VERSION 5.8 ;
BUSBITCHARS "[]" ;
DIVIDERCHAR "/" ;
UNITS
    DATABASE MICRONS 1000 ;
END UNITS

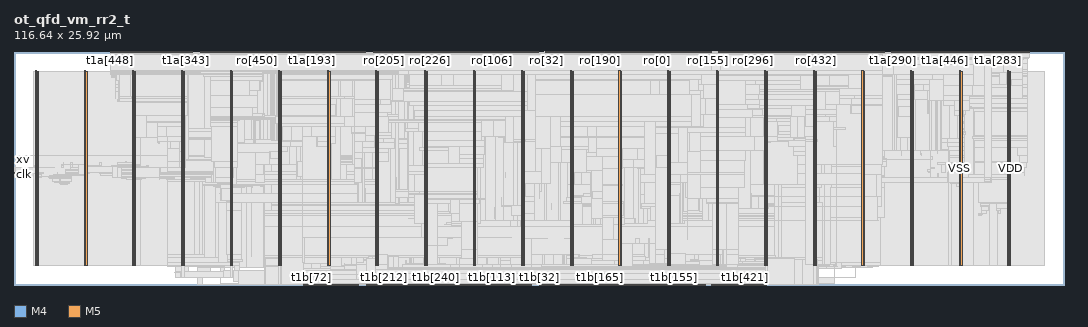
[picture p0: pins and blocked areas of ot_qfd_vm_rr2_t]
MACRO ot_qfd_vm_rr2_t
  FOREIGN ot_qfd_vm_rr2_t 0 0 ;
  CLASS BLOCK ;
  SIZE 116.64 BY 25.92 ;
  PIN clk
    DIRECTION INPUT ;
    USE SIGNAL ;
    PORT
      LAYER M4 ;
        RECT  0 12.24 0.084 12.264 ;
    END
  END clk
  PIN me_in
    DIRECTION INPUT ;
    USE SIGNAL ;
    PORT
      LAYER M4 ;
        RECT  0 12.336 0.084 12.36 ;
    END
  END me_in
  PIN ovf
    DIRECTION OUTPUT ;
    USE SIGNAL ;
    PORT
      LAYER M5 ;
        RECT  67.536 0 67.56 0.084 ;
    END
  END ovf
  PIN pop
    DIRECTION INPUT ;
    USE SIGNAL ;
    PORT
      LAYER M4 ;
        RECT  0 12.432 0.084 12.456 ;
    END
  END pop
  PIN ro[0]
    DIRECTION OUTPUT ;
    USE SIGNAL ;
    PORT
      LAYER M5 ;
        RECT  71.376 25.836 71.4 25.92 ;
    END
  END ro[0]
  PIN ro[100]
    DIRECTION OUTPUT ;
    USE SIGNAL ;
    PORT
      LAYER M5 ;
        RECT  52.56 25.836 52.584 25.92 ;
    END
  END ro[100]
  PIN ro[101]
    DIRECTION OUTPUT ;
    USE SIGNAL ;
    PORT
      LAYER M5 ;
        RECT  52.656 25.836 52.68 25.92 ;
    END
  END ro[101]
  PIN ro[102]
    DIRECTION OUTPUT ;
    USE SIGNAL ;
    PORT
      LAYER M5 ;
        RECT  52.752 25.836 52.776 25.92 ;
    END
  END ro[102]
  PIN ro[103]
    DIRECTION OUTPUT ;
    USE SIGNAL ;
    PORT
      LAYER M5 ;
        RECT  52.848 25.836 52.872 25.92 ;
    END
  END ro[103]
  PIN ro[104]
    DIRECTION OUTPUT ;
    USE SIGNAL ;
    PORT
      LAYER M5 ;
        RECT  52.944 25.836 52.968 25.92 ;
    END
  END ro[104]
  PIN ro[105]
    DIRECTION OUTPUT ;
    USE SIGNAL ;
    PORT
      LAYER M5 ;
        RECT  53.04 25.836 53.064 25.92 ;
    END
  END ro[105]
  PIN ro[106]
    DIRECTION OUTPUT ;
    USE SIGNAL ;
    PORT
      LAYER M5 ;
        RECT  53.136 25.836 53.16 25.92 ;
    END
  END ro[106]
  PIN ro[107]
    DIRECTION OUTPUT ;
    USE SIGNAL ;
    PORT
      LAYER M5 ;
        RECT  53.232 25.836 53.256 25.92 ;
    END
  END ro[107]
  PIN ro[108]
    DIRECTION OUTPUT ;
    USE SIGNAL ;
    PORT
      LAYER M5 ;
        RECT  53.328 25.836 53.352 25.92 ;
    END
  END ro[108]
  PIN ro[109]
    DIRECTION OUTPUT ;
    USE SIGNAL ;
    PORT
      LAYER M5 ;
        RECT  53.424 25.836 53.448 25.92 ;
    END
  END ro[109]
  PIN ro[10]
    DIRECTION OUTPUT ;
    USE SIGNAL ;
    PORT
      LAYER M5 ;
        RECT  72.336 25.836 72.36 25.92 ;
    END
  END ro[10]
  PIN ro[110]
    DIRECTION OUTPUT ;
    USE SIGNAL ;
    PORT
      LAYER M5 ;
        RECT  53.52 25.836 53.544 25.92 ;
    END
  END ro[110]
  PIN ro[111]
    DIRECTION OUTPUT ;
    USE SIGNAL ;
    PORT
      LAYER M5 ;
        RECT  53.616 25.836 53.64 25.92 ;
    END
  END ro[111]
  PIN ro[112]
    DIRECTION OUTPUT ;
    USE SIGNAL ;
    PORT
      LAYER M5 ;
        RECT  53.712 25.836 53.736 25.92 ;
    END
  END ro[112]
  PIN ro[113]
    DIRECTION OUTPUT ;
    USE SIGNAL ;
    PORT
      LAYER M5 ;
        RECT  53.808 25.836 53.832 25.92 ;
    END
  END ro[113]
  PIN ro[114]
    DIRECTION OUTPUT ;
    USE SIGNAL ;
    PORT
      LAYER M5 ;
        RECT  53.904 25.836 53.928 25.92 ;
    END
  END ro[114]
  PIN ro[115]
    DIRECTION OUTPUT ;
    USE SIGNAL ;
    PORT
      LAYER M5 ;
        RECT  54 25.836 54.024 25.92 ;
    END
  END ro[115]
  PIN ro[116]
    DIRECTION OUTPUT ;
    USE SIGNAL ;
    PORT
      LAYER M5 ;
        RECT  54.096 25.836 54.12 25.92 ;
    END
  END ro[116]
  PIN ro[117]
    DIRECTION OUTPUT ;
    USE SIGNAL ;
    PORT
      LAYER M5 ;
        RECT  54.192 25.836 54.216 25.92 ;
    END
  END ro[117]
  PIN ro[118]
    DIRECTION OUTPUT ;
    USE SIGNAL ;
    PORT
      LAYER M5 ;
        RECT  54.288 25.836 54.312 25.92 ;
    END
  END ro[118]
  PIN ro[119]
    DIRECTION OUTPUT ;
    USE SIGNAL ;
    PORT
      LAYER M5 ;
        RECT  54.384 25.836 54.408 25.92 ;
    END
  END ro[119]
  PIN ro[11]
    DIRECTION OUTPUT ;
    USE SIGNAL ;
    PORT
      LAYER M5 ;
        RECT  72.432 25.836 72.456 25.92 ;
    END
  END ro[11]
  PIN ro[120]
    DIRECTION OUTPUT ;
    USE SIGNAL ;
    PORT
      LAYER M5 ;
        RECT  54.48 25.836 54.504 25.92 ;
    END
  END ro[120]
  PIN ro[121]
    DIRECTION OUTPUT ;
    USE SIGNAL ;
    PORT
      LAYER M5 ;
        RECT  54.576 25.836 54.6 25.92 ;
    END
  END ro[121]
  PIN ro[122]
    DIRECTION OUTPUT ;
    USE SIGNAL ;
    PORT
      LAYER M5 ;
        RECT  54.672 25.836 54.696 25.92 ;
    END
  END ro[122]
  PIN ro[123]
    DIRECTION OUTPUT ;
    USE SIGNAL ;
    PORT
      LAYER M5 ;
        RECT  54.768 25.836 54.792 25.92 ;
    END
  END ro[123]
  PIN ro[124]
    DIRECTION OUTPUT ;
    USE SIGNAL ;
    PORT
      LAYER M5 ;
        RECT  54.864 25.836 54.888 25.92 ;
    END
  END ro[124]
  PIN ro[125]
    DIRECTION OUTPUT ;
    USE SIGNAL ;
    PORT
      LAYER M5 ;
        RECT  54.96 25.836 54.984 25.92 ;
    END
  END ro[125]
  PIN ro[126]
    DIRECTION OUTPUT ;
    USE SIGNAL ;
    PORT
      LAYER M5 ;
        RECT  55.056 25.836 55.08 25.92 ;
    END
  END ro[126]
  PIN ro[127]
    DIRECTION OUTPUT ;
    USE SIGNAL ;
    PORT
      LAYER M5 ;
        RECT  55.152 25.836 55.176 25.92 ;
    END
  END ro[127]
  PIN ro[128]
    DIRECTION OUTPUT ;
    USE SIGNAL ;
    PORT
      LAYER M5 ;
        RECT  74.448 25.836 74.472 25.92 ;
    END
  END ro[128]
  PIN ro[129]
    DIRECTION OUTPUT ;
    USE SIGNAL ;
    PORT
      LAYER M5 ;
        RECT  74.544 25.836 74.568 25.92 ;
    END
  END ro[129]
  PIN ro[12]
    DIRECTION OUTPUT ;
    USE SIGNAL ;
    PORT
      LAYER M5 ;
        RECT  72.528 25.836 72.552 25.92 ;
    END
  END ro[12]
  PIN ro[130]
    DIRECTION OUTPUT ;
    USE SIGNAL ;
    PORT
      LAYER M5 ;
        RECT  74.64 25.836 74.664 25.92 ;
    END
  END ro[130]
  PIN ro[131]
    DIRECTION OUTPUT ;
    USE SIGNAL ;
    PORT
      LAYER M5 ;
        RECT  74.736 25.836 74.76 25.92 ;
    END
  END ro[131]
  PIN ro[132]
    DIRECTION OUTPUT ;
    USE SIGNAL ;
    PORT
      LAYER M5 ;
        RECT  74.832 25.836 74.856 25.92 ;
    END
  END ro[132]
  PIN ro[133]
    DIRECTION OUTPUT ;
    USE SIGNAL ;
    PORT
      LAYER M5 ;
        RECT  74.928 25.836 74.952 25.92 ;
    END
  END ro[133]
  PIN ro[134]
    DIRECTION OUTPUT ;
    USE SIGNAL ;
    PORT
      LAYER M5 ;
        RECT  75.024 25.836 75.048 25.92 ;
    END
  END ro[134]
  PIN ro[135]
    DIRECTION OUTPUT ;
    USE SIGNAL ;
    PORT
      LAYER M5 ;
        RECT  75.12 25.836 75.144 25.92 ;
    END
  END ro[135]
  PIN ro[136]
    DIRECTION OUTPUT ;
    USE SIGNAL ;
    PORT
      LAYER M5 ;
        RECT  75.216 25.836 75.24 25.92 ;
    END
  END ro[136]
  PIN ro[137]
    DIRECTION OUTPUT ;
    USE SIGNAL ;
    PORT
      LAYER M5 ;
        RECT  75.312 25.836 75.336 25.92 ;
    END
  END ro[137]
  PIN ro[138]
    DIRECTION OUTPUT ;
    USE SIGNAL ;
    PORT
      LAYER M5 ;
        RECT  75.408 25.836 75.432 25.92 ;
    END
  END ro[138]
  PIN ro[139]
    DIRECTION OUTPUT ;
    USE SIGNAL ;
    PORT
      LAYER M5 ;
        RECT  75.504 25.836 75.528 25.92 ;
    END
  END ro[139]
  PIN ro[13]
    DIRECTION OUTPUT ;
    USE SIGNAL ;
    PORT
      LAYER M5 ;
        RECT  72.624 25.836 72.648 25.92 ;
    END
  END ro[13]
  PIN ro[140]
    DIRECTION OUTPUT ;
    USE SIGNAL ;
    PORT
      LAYER M5 ;
        RECT  75.6 25.836 75.624 25.92 ;
    END
  END ro[140]
  PIN ro[141]
    DIRECTION OUTPUT ;
    USE SIGNAL ;
    PORT
      LAYER M5 ;
        RECT  75.696 25.836 75.72 25.92 ;
    END
  END ro[141]
  PIN ro[142]
    DIRECTION OUTPUT ;
    USE SIGNAL ;
    PORT
      LAYER M5 ;
        RECT  75.792 25.836 75.816 25.92 ;
    END
  END ro[142]
  PIN ro[143]
    DIRECTION OUTPUT ;
    USE SIGNAL ;
    PORT
      LAYER M5 ;
        RECT  75.888 25.836 75.912 25.92 ;
    END
  END ro[143]
  PIN ro[144]
    DIRECTION OUTPUT ;
    USE SIGNAL ;
    PORT
      LAYER M5 ;
        RECT  75.984 25.836 76.008 25.92 ;
    END
  END ro[144]
  PIN ro[145]
    DIRECTION OUTPUT ;
    USE SIGNAL ;
    PORT
      LAYER M5 ;
        RECT  76.08 25.836 76.104 25.92 ;
    END
  END ro[145]
  PIN ro[146]
    DIRECTION OUTPUT ;
    USE SIGNAL ;
    PORT
      LAYER M5 ;
        RECT  76.176 25.836 76.2 25.92 ;
    END
  END ro[146]
  PIN ro[147]
    DIRECTION OUTPUT ;
    USE SIGNAL ;
    PORT
      LAYER M5 ;
        RECT  76.272 25.836 76.296 25.92 ;
    END
  END ro[147]
  PIN ro[148]
    DIRECTION OUTPUT ;
    USE SIGNAL ;
    PORT
      LAYER M5 ;
        RECT  76.368 25.836 76.392 25.92 ;
    END
  END ro[148]
  PIN ro[149]
    DIRECTION OUTPUT ;
    USE SIGNAL ;
    PORT
      LAYER M5 ;
        RECT  76.464 25.836 76.488 25.92 ;
    END
  END ro[149]
  PIN ro[14]
    DIRECTION OUTPUT ;
    USE SIGNAL ;
    PORT
      LAYER M5 ;
        RECT  72.72 25.836 72.744 25.92 ;
    END
  END ro[14]
  PIN ro[150]
    DIRECTION OUTPUT ;
    USE SIGNAL ;
    PORT
      LAYER M5 ;
        RECT  76.56 25.836 76.584 25.92 ;
    END
  END ro[150]
  PIN ro[151]
    DIRECTION OUTPUT ;
    USE SIGNAL ;
    PORT
      LAYER M5 ;
        RECT  76.656 25.836 76.68 25.92 ;
    END
  END ro[151]
  PIN ro[152]
    DIRECTION OUTPUT ;
    USE SIGNAL ;
    PORT
      LAYER M5 ;
        RECT  76.752 25.836 76.776 25.92 ;
    END
  END ro[152]
  PIN ro[153]
    DIRECTION OUTPUT ;
    USE SIGNAL ;
    PORT
      LAYER M5 ;
        RECT  76.848 25.836 76.872 25.92 ;
    END
  END ro[153]
  PIN ro[154]
    DIRECTION OUTPUT ;
    USE SIGNAL ;
    PORT
      LAYER M5 ;
        RECT  76.944 25.836 76.968 25.92 ;
    END
  END ro[154]
  PIN ro[155]
    DIRECTION OUTPUT ;
    USE SIGNAL ;
    PORT
      LAYER M5 ;
        RECT  77.04 25.836 77.064 25.92 ;
    END
  END ro[155]
  PIN ro[156]
    DIRECTION OUTPUT ;
    USE SIGNAL ;
    PORT
      LAYER M5 ;
        RECT  77.136 25.836 77.16 25.92 ;
    END
  END ro[156]
  PIN ro[157]
    DIRECTION OUTPUT ;
    USE SIGNAL ;
    PORT
      LAYER M5 ;
        RECT  77.232 25.836 77.256 25.92 ;
    END
  END ro[157]
  PIN ro[158]
    DIRECTION OUTPUT ;
    USE SIGNAL ;
    PORT
      LAYER M5 ;
        RECT  77.328 25.836 77.352 25.92 ;
    END
  END ro[158]
  PIN ro[159]
    DIRECTION OUTPUT ;
    USE SIGNAL ;
    PORT
      LAYER M5 ;
        RECT  77.424 25.836 77.448 25.92 ;
    END
  END ro[159]
  PIN ro[15]
    DIRECTION OUTPUT ;
    USE SIGNAL ;
    PORT
      LAYER M5 ;
        RECT  72.816 25.836 72.84 25.92 ;
    END
  END ro[15]
  PIN ro[160]
    DIRECTION OUTPUT ;
    USE SIGNAL ;
    PORT
      LAYER M5 ;
        RECT  62.16 25.836 62.184 25.92 ;
    END
  END ro[160]
  PIN ro[161]
    DIRECTION OUTPUT ;
    USE SIGNAL ;
    PORT
      LAYER M5 ;
        RECT  62.256 25.836 62.28 25.92 ;
    END
  END ro[161]
  PIN ro[162]
    DIRECTION OUTPUT ;
    USE SIGNAL ;
    PORT
      LAYER M5 ;
        RECT  62.352 25.836 62.376 25.92 ;
    END
  END ro[162]
  PIN ro[163]
    DIRECTION OUTPUT ;
    USE SIGNAL ;
    PORT
      LAYER M5 ;
        RECT  62.448 25.836 62.472 25.92 ;
    END
  END ro[163]
  PIN ro[164]
    DIRECTION OUTPUT ;
    USE SIGNAL ;
    PORT
      LAYER M5 ;
        RECT  62.544 25.836 62.568 25.92 ;
    END
  END ro[164]
  PIN ro[165]
    DIRECTION OUTPUT ;
    USE SIGNAL ;
    PORT
      LAYER M5 ;
        RECT  62.64 25.836 62.664 25.92 ;
    END
  END ro[165]
  PIN ro[166]
    DIRECTION OUTPUT ;
    USE SIGNAL ;
    PORT
      LAYER M5 ;
        RECT  62.736 25.836 62.76 25.92 ;
    END
  END ro[166]
  PIN ro[167]
    DIRECTION OUTPUT ;
    USE SIGNAL ;
    PORT
      LAYER M5 ;
        RECT  62.832 25.836 62.856 25.92 ;
    END
  END ro[167]
  PIN ro[168]
    DIRECTION OUTPUT ;
    USE SIGNAL ;
    PORT
      LAYER M5 ;
        RECT  62.928 25.836 62.952 25.92 ;
    END
  END ro[168]
  PIN ro[169]
    DIRECTION OUTPUT ;
    USE SIGNAL ;
    PORT
      LAYER M5 ;
        RECT  63.024 25.836 63.048 25.92 ;
    END
  END ro[169]
  PIN ro[16]
    DIRECTION OUTPUT ;
    USE SIGNAL ;
    PORT
      LAYER M5 ;
        RECT  72.912 25.836 72.936 25.92 ;
    END
  END ro[16]
  PIN ro[170]
    DIRECTION OUTPUT ;
    USE SIGNAL ;
    PORT
      LAYER M5 ;
        RECT  63.12 25.836 63.144 25.92 ;
    END
  END ro[170]
  PIN ro[171]
    DIRECTION OUTPUT ;
    USE SIGNAL ;
    PORT
      LAYER M5 ;
        RECT  63.216 25.836 63.24 25.92 ;
    END
  END ro[171]
  PIN ro[172]
    DIRECTION OUTPUT ;
    USE SIGNAL ;
    PORT
      LAYER M5 ;
        RECT  63.312 25.836 63.336 25.92 ;
    END
  END ro[172]
  PIN ro[173]
    DIRECTION OUTPUT ;
    USE SIGNAL ;
    PORT
      LAYER M5 ;
        RECT  63.408 25.836 63.432 25.92 ;
    END
  END ro[173]
  PIN ro[174]
    DIRECTION OUTPUT ;
    USE SIGNAL ;
    PORT
      LAYER M5 ;
        RECT  63.504 25.836 63.528 25.92 ;
    END
  END ro[174]
  PIN ro[175]
    DIRECTION OUTPUT ;
    USE SIGNAL ;
    PORT
      LAYER M5 ;
        RECT  63.6 25.836 63.624 25.92 ;
    END
  END ro[175]
  PIN ro[176]
    DIRECTION OUTPUT ;
    USE SIGNAL ;
    PORT
      LAYER M5 ;
        RECT  63.696 25.836 63.72 25.92 ;
    END
  END ro[176]
  PIN ro[177]
    DIRECTION OUTPUT ;
    USE SIGNAL ;
    PORT
      LAYER M5 ;
        RECT  63.792 25.836 63.816 25.92 ;
    END
  END ro[177]
  PIN ro[178]
    DIRECTION OUTPUT ;
    USE SIGNAL ;
    PORT
      LAYER M5 ;
        RECT  63.888 25.836 63.912 25.92 ;
    END
  END ro[178]
  PIN ro[179]
    DIRECTION OUTPUT ;
    USE SIGNAL ;
    PORT
      LAYER M5 ;
        RECT  63.984 25.836 64.008 25.92 ;
    END
  END ro[179]
  PIN ro[17]
    DIRECTION OUTPUT ;
    USE SIGNAL ;
    PORT
      LAYER M5 ;
        RECT  73.008 25.836 73.032 25.92 ;
    END
  END ro[17]
  PIN ro[180]
    DIRECTION OUTPUT ;
    USE SIGNAL ;
    PORT
      LAYER M5 ;
        RECT  64.08 25.836 64.104 25.92 ;
    END
  END ro[180]
  PIN ro[181]
    DIRECTION OUTPUT ;
    USE SIGNAL ;
    PORT
      LAYER M5 ;
        RECT  64.176 25.836 64.2 25.92 ;
    END
  END ro[181]
  PIN ro[182]
    DIRECTION OUTPUT ;
    USE SIGNAL ;
    PORT
      LAYER M5 ;
        RECT  64.272 25.836 64.296 25.92 ;
    END
  END ro[182]
  PIN ro[183]
    DIRECTION OUTPUT ;
    USE SIGNAL ;
    PORT
      LAYER M5 ;
        RECT  64.368 25.836 64.392 25.92 ;
    END
  END ro[183]
  PIN ro[184]
    DIRECTION OUTPUT ;
    USE SIGNAL ;
    PORT
      LAYER M5 ;
        RECT  64.464 25.836 64.488 25.92 ;
    END
  END ro[184]
  PIN ro[185]
    DIRECTION OUTPUT ;
    USE SIGNAL ;
    PORT
      LAYER M5 ;
        RECT  64.56 25.836 64.584 25.92 ;
    END
  END ro[185]
  PIN ro[186]
    DIRECTION OUTPUT ;
    USE SIGNAL ;
    PORT
      LAYER M5 ;
        RECT  64.656 25.836 64.68 25.92 ;
    END
  END ro[186]
  PIN ro[187]
    DIRECTION OUTPUT ;
    USE SIGNAL ;
    PORT
      LAYER M5 ;
        RECT  64.752 25.836 64.776 25.92 ;
    END
  END ro[187]
  PIN ro[188]
    DIRECTION OUTPUT ;
    USE SIGNAL ;
    PORT
      LAYER M5 ;
        RECT  64.848 25.836 64.872 25.92 ;
    END
  END ro[188]
  PIN ro[189]
    DIRECTION OUTPUT ;
    USE SIGNAL ;
    PORT
      LAYER M5 ;
        RECT  64.944 25.836 64.968 25.92 ;
    END
  END ro[189]
  PIN ro[18]
    DIRECTION OUTPUT ;
    USE SIGNAL ;
    PORT
      LAYER M5 ;
        RECT  73.104 25.836 73.128 25.92 ;
    END
  END ro[18]
  PIN ro[190]
    DIRECTION OUTPUT ;
    USE SIGNAL ;
    PORT
      LAYER M5 ;
        RECT  65.04 25.836 65.064 25.92 ;
    END
  END ro[190]
  PIN ro[191]
    DIRECTION OUTPUT ;
    USE SIGNAL ;
    PORT
      LAYER M5 ;
        RECT  65.136 25.836 65.16 25.92 ;
    END
  END ro[191]
  PIN ro[192]
    DIRECTION OUTPUT ;
    USE SIGNAL ;
    PORT
      LAYER M5 ;
        RECT  39.888 25.836 39.912 25.92 ;
    END
  END ro[192]
  PIN ro[193]
    DIRECTION OUTPUT ;
    USE SIGNAL ;
    PORT
      LAYER M5 ;
        RECT  39.984 25.836 40.008 25.92 ;
    END
  END ro[193]
  PIN ro[194]
    DIRECTION OUTPUT ;
    USE SIGNAL ;
    PORT
      LAYER M5 ;
        RECT  40.08 25.836 40.104 25.92 ;
    END
  END ro[194]
  PIN ro[195]
    DIRECTION OUTPUT ;
    USE SIGNAL ;
    PORT
      LAYER M5 ;
        RECT  40.176 25.836 40.2 25.92 ;
    END
  END ro[195]
  PIN ro[196]
    DIRECTION OUTPUT ;
    USE SIGNAL ;
    PORT
      LAYER M5 ;
        RECT  40.272 25.836 40.296 25.92 ;
    END
  END ro[196]
  PIN ro[197]
    DIRECTION OUTPUT ;
    USE SIGNAL ;
    PORT
      LAYER M5 ;
        RECT  40.368 25.836 40.392 25.92 ;
    END
  END ro[197]
  PIN ro[198]
    DIRECTION OUTPUT ;
    USE SIGNAL ;
    PORT
      LAYER M5 ;
        RECT  40.464 25.836 40.488 25.92 ;
    END
  END ro[198]
  PIN ro[199]
    DIRECTION OUTPUT ;
    USE SIGNAL ;
    PORT
      LAYER M5 ;
        RECT  40.56 25.836 40.584 25.92 ;
    END
  END ro[199]
  PIN ro[19]
    DIRECTION OUTPUT ;
    USE SIGNAL ;
    PORT
      LAYER M5 ;
        RECT  73.2 25.836 73.224 25.92 ;
    END
  END ro[19]
  PIN ro[1]
    DIRECTION OUTPUT ;
    USE SIGNAL ;
    PORT
      LAYER M5 ;
        RECT  71.472 25.836 71.496 25.92 ;
    END
  END ro[1]
  PIN ro[200]
    DIRECTION OUTPUT ;
    USE SIGNAL ;
    PORT
      LAYER M5 ;
        RECT  40.656 25.836 40.68 25.92 ;
    END
  END ro[200]
  PIN ro[201]
    DIRECTION OUTPUT ;
    USE SIGNAL ;
    PORT
      LAYER M5 ;
        RECT  40.752 25.836 40.776 25.92 ;
    END
  END ro[201]
  PIN ro[202]
    DIRECTION OUTPUT ;
    USE SIGNAL ;
    PORT
      LAYER M5 ;
        RECT  40.848 25.836 40.872 25.92 ;
    END
  END ro[202]
  PIN ro[203]
    DIRECTION OUTPUT ;
    USE SIGNAL ;
    PORT
      LAYER M5 ;
        RECT  40.944 25.836 40.968 25.92 ;
    END
  END ro[203]
  PIN ro[204]
    DIRECTION OUTPUT ;
    USE SIGNAL ;
    PORT
      LAYER M5 ;
        RECT  41.04 25.836 41.064 25.92 ;
    END
  END ro[204]
  PIN ro[205]
    DIRECTION OUTPUT ;
    USE SIGNAL ;
    PORT
      LAYER M5 ;
        RECT  41.136 25.836 41.16 25.92 ;
    END
  END ro[205]
  PIN ro[206]
    DIRECTION OUTPUT ;
    USE SIGNAL ;
    PORT
      LAYER M5 ;
        RECT  41.232 25.836 41.256 25.92 ;
    END
  END ro[206]
  PIN ro[207]
    DIRECTION OUTPUT ;
    USE SIGNAL ;
    PORT
      LAYER M5 ;
        RECT  41.328 25.836 41.352 25.92 ;
    END
  END ro[207]
  PIN ro[208]
    DIRECTION OUTPUT ;
    USE SIGNAL ;
    PORT
      LAYER M5 ;
        RECT  41.424 25.836 41.448 25.92 ;
    END
  END ro[208]
  PIN ro[209]
    DIRECTION OUTPUT ;
    USE SIGNAL ;
    PORT
      LAYER M5 ;
        RECT  41.52 25.836 41.544 25.92 ;
    END
  END ro[209]
  PIN ro[20]
    DIRECTION OUTPUT ;
    USE SIGNAL ;
    PORT
      LAYER M5 ;
        RECT  73.296 25.836 73.32 25.92 ;
    END
  END ro[20]
  PIN ro[210]
    DIRECTION OUTPUT ;
    USE SIGNAL ;
    PORT
      LAYER M5 ;
        RECT  41.616 25.836 41.64 25.92 ;
    END
  END ro[210]
  PIN ro[211]
    DIRECTION OUTPUT ;
    USE SIGNAL ;
    PORT
      LAYER M5 ;
        RECT  41.712 25.836 41.736 25.92 ;
    END
  END ro[211]
  PIN ro[212]
    DIRECTION OUTPUT ;
    USE SIGNAL ;
    PORT
      LAYER M5 ;
        RECT  41.808 25.836 41.832 25.92 ;
    END
  END ro[212]
  PIN ro[213]
    DIRECTION OUTPUT ;
    USE SIGNAL ;
    PORT
      LAYER M5 ;
        RECT  41.904 25.836 41.928 25.92 ;
    END
  END ro[213]
  PIN ro[214]
    DIRECTION OUTPUT ;
    USE SIGNAL ;
    PORT
      LAYER M5 ;
        RECT  42 25.836 42.024 25.92 ;
    END
  END ro[214]
  PIN ro[215]
    DIRECTION OUTPUT ;
    USE SIGNAL ;
    PORT
      LAYER M5 ;
        RECT  42.096 25.836 42.12 25.92 ;
    END
  END ro[215]
  PIN ro[216]
    DIRECTION OUTPUT ;
    USE SIGNAL ;
    PORT
      LAYER M5 ;
        RECT  42.192 25.836 42.216 25.92 ;
    END
  END ro[216]
  PIN ro[217]
    DIRECTION OUTPUT ;
    USE SIGNAL ;
    PORT
      LAYER M5 ;
        RECT  42.288 25.836 42.312 25.92 ;
    END
  END ro[217]
  PIN ro[218]
    DIRECTION OUTPUT ;
    USE SIGNAL ;
    PORT
      LAYER M5 ;
        RECT  42.384 25.836 42.408 25.92 ;
    END
  END ro[218]
  PIN ro[219]
    DIRECTION OUTPUT ;
    USE SIGNAL ;
    PORT
      LAYER M5 ;
        RECT  42.48 25.836 42.504 25.92 ;
    END
  END ro[219]
  PIN ro[21]
    DIRECTION OUTPUT ;
    USE SIGNAL ;
    PORT
      LAYER M5 ;
        RECT  73.392 25.836 73.416 25.92 ;
    END
  END ro[21]
  PIN ro[220]
    DIRECTION OUTPUT ;
    USE SIGNAL ;
    PORT
      LAYER M5 ;
        RECT  42.576 25.836 42.6 25.92 ;
    END
  END ro[220]
  PIN ro[221]
    DIRECTION OUTPUT ;
    USE SIGNAL ;
    PORT
      LAYER M5 ;
        RECT  42.672 25.836 42.696 25.92 ;
    END
  END ro[221]
  PIN ro[222]
    DIRECTION OUTPUT ;
    USE SIGNAL ;
    PORT
      LAYER M5 ;
        RECT  42.768 25.836 42.792 25.92 ;
    END
  END ro[222]
  PIN ro[223]
    DIRECTION OUTPUT ;
    USE SIGNAL ;
    PORT
      LAYER M5 ;
        RECT  42.864 25.836 42.888 25.92 ;
    END
  END ro[223]
  PIN ro[224]
    DIRECTION OUTPUT ;
    USE SIGNAL ;
    PORT
      LAYER M5 ;
        RECT  46.032 25.836 46.056 25.92 ;
    END
  END ro[224]
  PIN ro[225]
    DIRECTION OUTPUT ;
    USE SIGNAL ;
    PORT
      LAYER M5 ;
        RECT  46.128 25.836 46.152 25.92 ;
    END
  END ro[225]
  PIN ro[226]
    DIRECTION OUTPUT ;
    USE SIGNAL ;
    PORT
      LAYER M5 ;
        RECT  46.224 25.836 46.248 25.92 ;
    END
  END ro[226]
  PIN ro[227]
    DIRECTION OUTPUT ;
    USE SIGNAL ;
    PORT
      LAYER M5 ;
        RECT  46.32 25.836 46.344 25.92 ;
    END
  END ro[227]
  PIN ro[228]
    DIRECTION OUTPUT ;
    USE SIGNAL ;
    PORT
      LAYER M5 ;
        RECT  46.416 25.836 46.44 25.92 ;
    END
  END ro[228]
  PIN ro[229]
    DIRECTION OUTPUT ;
    USE SIGNAL ;
    PORT
      LAYER M5 ;
        RECT  46.512 25.836 46.536 25.92 ;
    END
  END ro[229]
  PIN ro[22]
    DIRECTION OUTPUT ;
    USE SIGNAL ;
    PORT
      LAYER M5 ;
        RECT  73.488 25.836 73.512 25.92 ;
    END
  END ro[22]
  PIN ro[230]
    DIRECTION OUTPUT ;
    USE SIGNAL ;
    PORT
      LAYER M5 ;
        RECT  46.608 25.836 46.632 25.92 ;
    END
  END ro[230]
  PIN ro[231]
    DIRECTION OUTPUT ;
    USE SIGNAL ;
    PORT
      LAYER M5 ;
        RECT  46.704 25.836 46.728 25.92 ;
    END
  END ro[231]
  PIN ro[232]
    DIRECTION OUTPUT ;
    USE SIGNAL ;
    PORT
      LAYER M5 ;
        RECT  46.8 25.836 46.824 25.92 ;
    END
  END ro[232]
  PIN ro[233]
    DIRECTION OUTPUT ;
    USE SIGNAL ;
    PORT
      LAYER M5 ;
        RECT  46.896 25.836 46.92 25.92 ;
    END
  END ro[233]
  PIN ro[234]
    DIRECTION OUTPUT ;
    USE SIGNAL ;
    PORT
      LAYER M5 ;
        RECT  46.992 25.836 47.016 25.92 ;
    END
  END ro[234]
  PIN ro[235]
    DIRECTION OUTPUT ;
    USE SIGNAL ;
    PORT
      LAYER M5 ;
        RECT  47.088 25.836 47.112 25.92 ;
    END
  END ro[235]
  PIN ro[236]
    DIRECTION OUTPUT ;
    USE SIGNAL ;
    PORT
      LAYER M5 ;
        RECT  47.184 25.836 47.208 25.92 ;
    END
  END ro[236]
  PIN ro[237]
    DIRECTION OUTPUT ;
    USE SIGNAL ;
    PORT
      LAYER M5 ;
        RECT  47.28 25.836 47.304 25.92 ;
    END
  END ro[237]
  PIN ro[238]
    DIRECTION OUTPUT ;
    USE SIGNAL ;
    PORT
      LAYER M5 ;
        RECT  47.376 25.836 47.4 25.92 ;
    END
  END ro[238]
  PIN ro[239]
    DIRECTION OUTPUT ;
    USE SIGNAL ;
    PORT
      LAYER M5 ;
        RECT  47.472 25.836 47.496 25.92 ;
    END
  END ro[239]
  PIN ro[23]
    DIRECTION OUTPUT ;
    USE SIGNAL ;
    PORT
      LAYER M5 ;
        RECT  73.584 25.836 73.608 25.92 ;
    END
  END ro[23]
  PIN ro[240]
    DIRECTION OUTPUT ;
    USE SIGNAL ;
    PORT
      LAYER M5 ;
        RECT  47.568 25.836 47.592 25.92 ;
    END
  END ro[240]
  PIN ro[241]
    DIRECTION OUTPUT ;
    USE SIGNAL ;
    PORT
      LAYER M5 ;
        RECT  47.664 25.836 47.688 25.92 ;
    END
  END ro[241]
  PIN ro[242]
    DIRECTION OUTPUT ;
    USE SIGNAL ;
    PORT
      LAYER M5 ;
        RECT  47.76 25.836 47.784 25.92 ;
    END
  END ro[242]
  PIN ro[243]
    DIRECTION OUTPUT ;
    USE SIGNAL ;
    PORT
      LAYER M5 ;
        RECT  47.856 25.836 47.88 25.92 ;
    END
  END ro[243]
  PIN ro[244]
    DIRECTION OUTPUT ;
    USE SIGNAL ;
    PORT
      LAYER M5 ;
        RECT  47.952 25.836 47.976 25.92 ;
    END
  END ro[244]
  PIN ro[245]
    DIRECTION OUTPUT ;
    USE SIGNAL ;
    PORT
      LAYER M5 ;
        RECT  48.048 25.836 48.072 25.92 ;
    END
  END ro[245]
  PIN ro[246]
    DIRECTION OUTPUT ;
    USE SIGNAL ;
    PORT
      LAYER M5 ;
        RECT  48.144 25.836 48.168 25.92 ;
    END
  END ro[246]
  PIN ro[247]
    DIRECTION OUTPUT ;
    USE SIGNAL ;
    PORT
      LAYER M5 ;
        RECT  48.24 25.836 48.264 25.92 ;
    END
  END ro[247]
  PIN ro[248]
    DIRECTION OUTPUT ;
    USE SIGNAL ;
    PORT
      LAYER M5 ;
        RECT  48.336 25.836 48.36 25.92 ;
    END
  END ro[248]
  PIN ro[249]
    DIRECTION OUTPUT ;
    USE SIGNAL ;
    PORT
      LAYER M5 ;
        RECT  48.432 25.836 48.456 25.92 ;
    END
  END ro[249]
  PIN ro[24]
    DIRECTION OUTPUT ;
    USE SIGNAL ;
    PORT
      LAYER M5 ;
        RECT  73.68 25.836 73.704 25.92 ;
    END
  END ro[24]
  PIN ro[250]
    DIRECTION OUTPUT ;
    USE SIGNAL ;
    PORT
      LAYER M5 ;
        RECT  48.528 25.836 48.552 25.92 ;
    END
  END ro[250]
  PIN ro[251]
    DIRECTION OUTPUT ;
    USE SIGNAL ;
    PORT
      LAYER M5 ;
        RECT  48.624 25.836 48.648 25.92 ;
    END
  END ro[251]
  PIN ro[252]
    DIRECTION OUTPUT ;
    USE SIGNAL ;
    PORT
      LAYER M5 ;
        RECT  48.72 25.836 48.744 25.92 ;
    END
  END ro[252]
  PIN ro[253]
    DIRECTION OUTPUT ;
    USE SIGNAL ;
    PORT
      LAYER M5 ;
        RECT  48.816 25.836 48.84 25.92 ;
    END
  END ro[253]
  PIN ro[254]
    DIRECTION OUTPUT ;
    USE SIGNAL ;
    PORT
      LAYER M5 ;
        RECT  48.912 25.836 48.936 25.92 ;
    END
  END ro[254]
  PIN ro[255]
    DIRECTION OUTPUT ;
    USE SIGNAL ;
    PORT
      LAYER M5 ;
        RECT  49.008 25.836 49.032 25.92 ;
    END
  END ro[255]
  PIN ro[256]
    DIRECTION OUTPUT ;
    USE SIGNAL ;
    PORT
      LAYER M5 ;
        RECT  65.232 25.836 65.256 25.92 ;
    END
  END ro[256]
  PIN ro[257]
    DIRECTION OUTPUT ;
    USE SIGNAL ;
    PORT
      LAYER M5 ;
        RECT  65.328 25.836 65.352 25.92 ;
    END
  END ro[257]
  PIN ro[258]
    DIRECTION OUTPUT ;
    USE SIGNAL ;
    PORT
      LAYER M5 ;
        RECT  65.424 25.836 65.448 25.92 ;
    END
  END ro[258]
  PIN ro[259]
    DIRECTION OUTPUT ;
    USE SIGNAL ;
    PORT
      LAYER M5 ;
        RECT  65.52 25.836 65.544 25.92 ;
    END
  END ro[259]
  PIN ro[25]
    DIRECTION OUTPUT ;
    USE SIGNAL ;
    PORT
      LAYER M5 ;
        RECT  73.776 25.836 73.8 25.92 ;
    END
  END ro[25]
  PIN ro[260]
    DIRECTION OUTPUT ;
    USE SIGNAL ;
    PORT
      LAYER M5 ;
        RECT  65.616 25.836 65.64 25.92 ;
    END
  END ro[260]
  PIN ro[261]
    DIRECTION OUTPUT ;
    USE SIGNAL ;
    PORT
      LAYER M5 ;
        RECT  65.712 25.836 65.736 25.92 ;
    END
  END ro[261]
  PIN ro[262]
    DIRECTION OUTPUT ;
    USE SIGNAL ;
    PORT
      LAYER M5 ;
        RECT  65.808 25.836 65.832 25.92 ;
    END
  END ro[262]
  PIN ro[263]
    DIRECTION OUTPUT ;
    USE SIGNAL ;
    PORT
      LAYER M5 ;
        RECT  65.904 25.836 65.928 25.92 ;
    END
  END ro[263]
  PIN ro[264]
    DIRECTION OUTPUT ;
    USE SIGNAL ;
    PORT
      LAYER M5 ;
        RECT  66 25.836 66.024 25.92 ;
    END
  END ro[264]
  PIN ro[265]
    DIRECTION OUTPUT ;
    USE SIGNAL ;
    PORT
      LAYER M5 ;
        RECT  66.096 25.836 66.12 25.92 ;
    END
  END ro[265]
  PIN ro[266]
    DIRECTION OUTPUT ;
    USE SIGNAL ;
    PORT
      LAYER M5 ;
        RECT  66.192 25.836 66.216 25.92 ;
    END
  END ro[266]
  PIN ro[267]
    DIRECTION OUTPUT ;
    USE SIGNAL ;
    PORT
      LAYER M5 ;
        RECT  66.288 25.836 66.312 25.92 ;
    END
  END ro[267]
  PIN ro[268]
    DIRECTION OUTPUT ;
    USE SIGNAL ;
    PORT
      LAYER M5 ;
        RECT  66.384 25.836 66.408 25.92 ;
    END
  END ro[268]
  PIN ro[269]
    DIRECTION OUTPUT ;
    USE SIGNAL ;
    PORT
      LAYER M5 ;
        RECT  66.48 25.836 66.504 25.92 ;
    END
  END ro[269]
  PIN ro[26]
    DIRECTION OUTPUT ;
    USE SIGNAL ;
    PORT
      LAYER M5 ;
        RECT  73.872 25.836 73.896 25.92 ;
    END
  END ro[26]
  PIN ro[270]
    DIRECTION OUTPUT ;
    USE SIGNAL ;
    PORT
      LAYER M5 ;
        RECT  66.576 25.836 66.6 25.92 ;
    END
  END ro[270]
  PIN ro[271]
    DIRECTION OUTPUT ;
    USE SIGNAL ;
    PORT
      LAYER M5 ;
        RECT  66.672 25.836 66.696 25.92 ;
    END
  END ro[271]
  PIN ro[272]
    DIRECTION OUTPUT ;
    USE SIGNAL ;
    PORT
      LAYER M5 ;
        RECT  66.768 25.836 66.792 25.92 ;
    END
  END ro[272]
  PIN ro[273]
    DIRECTION OUTPUT ;
    USE SIGNAL ;
    PORT
      LAYER M5 ;
        RECT  66.864 25.836 66.888 25.92 ;
    END
  END ro[273]
  PIN ro[274]
    DIRECTION OUTPUT ;
    USE SIGNAL ;
    PORT
      LAYER M5 ;
        RECT  66.96 25.836 66.984 25.92 ;
    END
  END ro[274]
  PIN ro[275]
    DIRECTION OUTPUT ;
    USE SIGNAL ;
    PORT
      LAYER M5 ;
        RECT  67.056 25.836 67.08 25.92 ;
    END
  END ro[275]
  PIN ro[276]
    DIRECTION OUTPUT ;
    USE SIGNAL ;
    PORT
      LAYER M5 ;
        RECT  67.152 25.836 67.176 25.92 ;
    END
  END ro[276]
  PIN ro[277]
    DIRECTION OUTPUT ;
    USE SIGNAL ;
    PORT
      LAYER M5 ;
        RECT  67.248 25.836 67.272 25.92 ;
    END
  END ro[277]
  PIN ro[278]
    DIRECTION OUTPUT ;
    USE SIGNAL ;
    PORT
      LAYER M5 ;
        RECT  67.344 25.836 67.368 25.92 ;
    END
  END ro[278]
  PIN ro[279]
    DIRECTION OUTPUT ;
    USE SIGNAL ;
    PORT
      LAYER M5 ;
        RECT  67.44 25.836 67.464 25.92 ;
    END
  END ro[279]
  PIN ro[27]
    DIRECTION OUTPUT ;
    USE SIGNAL ;
    PORT
      LAYER M5 ;
        RECT  73.968 25.836 73.992 25.92 ;
    END
  END ro[27]
  PIN ro[280]
    DIRECTION OUTPUT ;
    USE SIGNAL ;
    PORT
      LAYER M5 ;
        RECT  67.536 25.836 67.56 25.92 ;
    END
  END ro[280]
  PIN ro[281]
    DIRECTION OUTPUT ;
    USE SIGNAL ;
    PORT
      LAYER M5 ;
        RECT  67.632 25.836 67.656 25.92 ;
    END
  END ro[281]
  PIN ro[282]
    DIRECTION OUTPUT ;
    USE SIGNAL ;
    PORT
      LAYER M5 ;
        RECT  67.728 25.836 67.752 25.92 ;
    END
  END ro[282]
  PIN ro[283]
    DIRECTION OUTPUT ;
    USE SIGNAL ;
    PORT
      LAYER M5 ;
        RECT  67.824 25.836 67.848 25.92 ;
    END
  END ro[283]
  PIN ro[284]
    DIRECTION OUTPUT ;
    USE SIGNAL ;
    PORT
      LAYER M5 ;
        RECT  67.92 25.836 67.944 25.92 ;
    END
  END ro[284]
  PIN ro[285]
    DIRECTION OUTPUT ;
    USE SIGNAL ;
    PORT
      LAYER M5 ;
        RECT  68.016 25.836 68.04 25.92 ;
    END
  END ro[285]
  PIN ro[286]
    DIRECTION OUTPUT ;
    USE SIGNAL ;
    PORT
      LAYER M5 ;
        RECT  68.112 25.836 68.136 25.92 ;
    END
  END ro[286]
  PIN ro[287]
    DIRECTION OUTPUT ;
    USE SIGNAL ;
    PORT
      LAYER M5 ;
        RECT  68.208 25.836 68.232 25.92 ;
    END
  END ro[287]
  PIN ro[288]
    DIRECTION OUTPUT ;
    USE SIGNAL ;
    PORT
      LAYER M5 ;
        RECT  81.36 25.836 81.384 25.92 ;
    END
  END ro[288]
  PIN ro[289]
    DIRECTION OUTPUT ;
    USE SIGNAL ;
    PORT
      LAYER M5 ;
        RECT  81.456 25.836 81.48 25.92 ;
    END
  END ro[289]
  PIN ro[28]
    DIRECTION OUTPUT ;
    USE SIGNAL ;
    PORT
      LAYER M5 ;
        RECT  74.064 25.836 74.088 25.92 ;
    END
  END ro[28]
  PIN ro[290]
    DIRECTION OUTPUT ;
    USE SIGNAL ;
    PORT
      LAYER M5 ;
        RECT  81.552 25.836 81.576 25.92 ;
    END
  END ro[290]
  PIN ro[291]
    DIRECTION OUTPUT ;
    USE SIGNAL ;
    PORT
      LAYER M5 ;
        RECT  81.648 25.836 81.672 25.92 ;
    END
  END ro[291]
  PIN ro[292]
    DIRECTION OUTPUT ;
    USE SIGNAL ;
    PORT
      LAYER M5 ;
        RECT  81.744 25.836 81.768 25.92 ;
    END
  END ro[292]
  PIN ro[293]
    DIRECTION OUTPUT ;
    USE SIGNAL ;
    PORT
      LAYER M5 ;
        RECT  81.84 25.836 81.864 25.92 ;
    END
  END ro[293]
  PIN ro[294]
    DIRECTION OUTPUT ;
    USE SIGNAL ;
    PORT
      LAYER M5 ;
        RECT  81.936 25.836 81.96 25.92 ;
    END
  END ro[294]
  PIN ro[295]
    DIRECTION OUTPUT ;
    USE SIGNAL ;
    PORT
      LAYER M5 ;
        RECT  82.032 25.836 82.056 25.92 ;
    END
  END ro[295]
  PIN ro[296]
    DIRECTION OUTPUT ;
    USE SIGNAL ;
    PORT
      LAYER M5 ;
        RECT  82.128 25.836 82.152 25.92 ;
    END
  END ro[296]
  PIN ro[297]
    DIRECTION OUTPUT ;
    USE SIGNAL ;
    PORT
      LAYER M5 ;
        RECT  82.224 25.836 82.248 25.92 ;
    END
  END ro[297]
  PIN ro[298]
    DIRECTION OUTPUT ;
    USE SIGNAL ;
    PORT
      LAYER M5 ;
        RECT  82.32 25.836 82.344 25.92 ;
    END
  END ro[298]
  PIN ro[299]
    DIRECTION OUTPUT ;
    USE SIGNAL ;
    PORT
      LAYER M5 ;
        RECT  82.416 25.836 82.44 25.92 ;
    END
  END ro[299]
  PIN ro[29]
    DIRECTION OUTPUT ;
    USE SIGNAL ;
    PORT
      LAYER M5 ;
        RECT  74.16 25.836 74.184 25.92 ;
    END
  END ro[29]
  PIN ro[2]
    DIRECTION OUTPUT ;
    USE SIGNAL ;
    PORT
      LAYER M5 ;
        RECT  71.568 25.836 71.592 25.92 ;
    END
  END ro[2]
  PIN ro[300]
    DIRECTION OUTPUT ;
    USE SIGNAL ;
    PORT
      LAYER M5 ;
        RECT  82.512 25.836 82.536 25.92 ;
    END
  END ro[300]
  PIN ro[301]
    DIRECTION OUTPUT ;
    USE SIGNAL ;
    PORT
      LAYER M5 ;
        RECT  82.608 25.836 82.632 25.92 ;
    END
  END ro[301]
  PIN ro[302]
    DIRECTION OUTPUT ;
    USE SIGNAL ;
    PORT
      LAYER M5 ;
        RECT  82.704 25.836 82.728 25.92 ;
    END
  END ro[302]
  PIN ro[303]
    DIRECTION OUTPUT ;
    USE SIGNAL ;
    PORT
      LAYER M5 ;
        RECT  82.8 25.836 82.824 25.92 ;
    END
  END ro[303]
  PIN ro[304]
    DIRECTION OUTPUT ;
    USE SIGNAL ;
    PORT
      LAYER M5 ;
        RECT  82.896 25.836 82.92 25.92 ;
    END
  END ro[304]
  PIN ro[305]
    DIRECTION OUTPUT ;
    USE SIGNAL ;
    PORT
      LAYER M5 ;
        RECT  82.992 25.836 83.016 25.92 ;
    END
  END ro[305]
  PIN ro[306]
    DIRECTION OUTPUT ;
    USE SIGNAL ;
    PORT
      LAYER M5 ;
        RECT  83.088 25.836 83.112 25.92 ;
    END
  END ro[306]
  PIN ro[307]
    DIRECTION OUTPUT ;
    USE SIGNAL ;
    PORT
      LAYER M5 ;
        RECT  83.184 25.836 83.208 25.92 ;
    END
  END ro[307]
  PIN ro[308]
    DIRECTION OUTPUT ;
    USE SIGNAL ;
    PORT
      LAYER M5 ;
        RECT  83.28 25.836 83.304 25.92 ;
    END
  END ro[308]
  PIN ro[309]
    DIRECTION OUTPUT ;
    USE SIGNAL ;
    PORT
      LAYER M5 ;
        RECT  83.376 25.836 83.4 25.92 ;
    END
  END ro[309]
  PIN ro[30]
    DIRECTION OUTPUT ;
    USE SIGNAL ;
    PORT
      LAYER M5 ;
        RECT  74.256 25.836 74.28 25.92 ;
    END
  END ro[30]
  PIN ro[310]
    DIRECTION OUTPUT ;
    USE SIGNAL ;
    PORT
      LAYER M5 ;
        RECT  83.472 25.836 83.496 25.92 ;
    END
  END ro[310]
  PIN ro[311]
    DIRECTION OUTPUT ;
    USE SIGNAL ;
    PORT
      LAYER M5 ;
        RECT  83.568 25.836 83.592 25.92 ;
    END
  END ro[311]
  PIN ro[312]
    DIRECTION OUTPUT ;
    USE SIGNAL ;
    PORT
      LAYER M5 ;
        RECT  83.664 25.836 83.688 25.92 ;
    END
  END ro[312]
  PIN ro[313]
    DIRECTION OUTPUT ;
    USE SIGNAL ;
    PORT
      LAYER M5 ;
        RECT  83.76 25.836 83.784 25.92 ;
    END
  END ro[313]
  PIN ro[314]
    DIRECTION OUTPUT ;
    USE SIGNAL ;
    PORT
      LAYER M5 ;
        RECT  83.856 25.836 83.88 25.92 ;
    END
  END ro[314]
  PIN ro[315]
    DIRECTION OUTPUT ;
    USE SIGNAL ;
    PORT
      LAYER M5 ;
        RECT  83.952 25.836 83.976 25.92 ;
    END
  END ro[315]
  PIN ro[316]
    DIRECTION OUTPUT ;
    USE SIGNAL ;
    PORT
      LAYER M5 ;
        RECT  84.048 25.836 84.072 25.92 ;
    END
  END ro[316]
  PIN ro[317]
    DIRECTION OUTPUT ;
    USE SIGNAL ;
    PORT
      LAYER M5 ;
        RECT  84.144 25.836 84.168 25.92 ;
    END
  END ro[317]
  PIN ro[318]
    DIRECTION OUTPUT ;
    USE SIGNAL ;
    PORT
      LAYER M5 ;
        RECT  84.24 25.836 84.264 25.92 ;
    END
  END ro[318]
  PIN ro[319]
    DIRECTION OUTPUT ;
    USE SIGNAL ;
    PORT
      LAYER M5 ;
        RECT  84.336 25.836 84.36 25.92 ;
    END
  END ro[319]
  PIN ro[31]
    DIRECTION OUTPUT ;
    USE SIGNAL ;
    PORT
      LAYER M5 ;
        RECT  74.352 25.836 74.376 25.92 ;
    END
  END ro[31]
  PIN ro[320]
    DIRECTION OUTPUT ;
    USE SIGNAL ;
    PORT
      LAYER M5 ;
        RECT  42.96 25.836 42.984 25.92 ;
    END
  END ro[320]
  PIN ro[321]
    DIRECTION OUTPUT ;
    USE SIGNAL ;
    PORT
      LAYER M5 ;
        RECT  43.056 25.836 43.08 25.92 ;
    END
  END ro[321]
  PIN ro[322]
    DIRECTION OUTPUT ;
    USE SIGNAL ;
    PORT
      LAYER M5 ;
        RECT  43.152 25.836 43.176 25.92 ;
    END
  END ro[322]
  PIN ro[323]
    DIRECTION OUTPUT ;
    USE SIGNAL ;
    PORT
      LAYER M5 ;
        RECT  43.248 25.836 43.272 25.92 ;
    END
  END ro[323]
  PIN ro[324]
    DIRECTION OUTPUT ;
    USE SIGNAL ;
    PORT
      LAYER M5 ;
        RECT  43.344 25.836 43.368 25.92 ;
    END
  END ro[324]
  PIN ro[325]
    DIRECTION OUTPUT ;
    USE SIGNAL ;
    PORT
      LAYER M5 ;
        RECT  43.44 25.836 43.464 25.92 ;
    END
  END ro[325]
  PIN ro[326]
    DIRECTION OUTPUT ;
    USE SIGNAL ;
    PORT
      LAYER M5 ;
        RECT  43.536 25.836 43.56 25.92 ;
    END
  END ro[326]
  PIN ro[327]
    DIRECTION OUTPUT ;
    USE SIGNAL ;
    PORT
      LAYER M5 ;
        RECT  43.632 25.836 43.656 25.92 ;
    END
  END ro[327]
  PIN ro[328]
    DIRECTION OUTPUT ;
    USE SIGNAL ;
    PORT
      LAYER M5 ;
        RECT  43.728 25.836 43.752 25.92 ;
    END
  END ro[328]
  PIN ro[329]
    DIRECTION OUTPUT ;
    USE SIGNAL ;
    PORT
      LAYER M5 ;
        RECT  43.824 25.836 43.848 25.92 ;
    END
  END ro[329]
  PIN ro[32]
    DIRECTION OUTPUT ;
    USE SIGNAL ;
    PORT
      LAYER M5 ;
        RECT  59.088 25.836 59.112 25.92 ;
    END
  END ro[32]
  PIN ro[330]
    DIRECTION OUTPUT ;
    USE SIGNAL ;
    PORT
      LAYER M5 ;
        RECT  43.92 25.836 43.944 25.92 ;
    END
  END ro[330]
  PIN ro[331]
    DIRECTION OUTPUT ;
    USE SIGNAL ;
    PORT
      LAYER M5 ;
        RECT  44.016 25.836 44.04 25.92 ;
    END
  END ro[331]
  PIN ro[332]
    DIRECTION OUTPUT ;
    USE SIGNAL ;
    PORT
      LAYER M5 ;
        RECT  44.112 25.836 44.136 25.92 ;
    END
  END ro[332]
  PIN ro[333]
    DIRECTION OUTPUT ;
    USE SIGNAL ;
    PORT
      LAYER M5 ;
        RECT  44.208 25.836 44.232 25.92 ;
    END
  END ro[333]
  PIN ro[334]
    DIRECTION OUTPUT ;
    USE SIGNAL ;
    PORT
      LAYER M5 ;
        RECT  44.304 25.836 44.328 25.92 ;
    END
  END ro[334]
  PIN ro[335]
    DIRECTION OUTPUT ;
    USE SIGNAL ;
    PORT
      LAYER M5 ;
        RECT  44.4 25.836 44.424 25.92 ;
    END
  END ro[335]
  PIN ro[336]
    DIRECTION OUTPUT ;
    USE SIGNAL ;
    PORT
      LAYER M5 ;
        RECT  44.496 25.836 44.52 25.92 ;
    END
  END ro[336]
  PIN ro[337]
    DIRECTION OUTPUT ;
    USE SIGNAL ;
    PORT
      LAYER M5 ;
        RECT  44.592 25.836 44.616 25.92 ;
    END
  END ro[337]
  PIN ro[338]
    DIRECTION OUTPUT ;
    USE SIGNAL ;
    PORT
      LAYER M5 ;
        RECT  44.688 25.836 44.712 25.92 ;
    END
  END ro[338]
  PIN ro[339]
    DIRECTION OUTPUT ;
    USE SIGNAL ;
    PORT
      LAYER M5 ;
        RECT  44.784 25.836 44.808 25.92 ;
    END
  END ro[339]
  PIN ro[33]
    DIRECTION OUTPUT ;
    USE SIGNAL ;
    PORT
      LAYER M5 ;
        RECT  59.184 25.836 59.208 25.92 ;
    END
  END ro[33]
  PIN ro[340]
    DIRECTION OUTPUT ;
    USE SIGNAL ;
    PORT
      LAYER M5 ;
        RECT  44.88 25.836 44.904 25.92 ;
    END
  END ro[340]
  PIN ro[341]
    DIRECTION OUTPUT ;
    USE SIGNAL ;
    PORT
      LAYER M5 ;
        RECT  44.976 25.836 45 25.92 ;
    END
  END ro[341]
  PIN ro[342]
    DIRECTION OUTPUT ;
    USE SIGNAL ;
    PORT
      LAYER M5 ;
        RECT  45.072 25.836 45.096 25.92 ;
    END
  END ro[342]
  PIN ro[343]
    DIRECTION OUTPUT ;
    USE SIGNAL ;
    PORT
      LAYER M5 ;
        RECT  45.168 25.836 45.192 25.92 ;
    END
  END ro[343]
  PIN ro[344]
    DIRECTION OUTPUT ;
    USE SIGNAL ;
    PORT
      LAYER M5 ;
        RECT  45.264 25.836 45.288 25.92 ;
    END
  END ro[344]
  PIN ro[345]
    DIRECTION OUTPUT ;
    USE SIGNAL ;
    PORT
      LAYER M5 ;
        RECT  45.36 25.836 45.384 25.92 ;
    END
  END ro[345]
  PIN ro[346]
    DIRECTION OUTPUT ;
    USE SIGNAL ;
    PORT
      LAYER M5 ;
        RECT  45.456 25.836 45.48 25.92 ;
    END
  END ro[346]
  PIN ro[347]
    DIRECTION OUTPUT ;
    USE SIGNAL ;
    PORT
      LAYER M5 ;
        RECT  45.552 25.836 45.576 25.92 ;
    END
  END ro[347]
  PIN ro[348]
    DIRECTION OUTPUT ;
    USE SIGNAL ;
    PORT
      LAYER M5 ;
        RECT  45.648 25.836 45.672 25.92 ;
    END
  END ro[348]
  PIN ro[349]
    DIRECTION OUTPUT ;
    USE SIGNAL ;
    PORT
      LAYER M5 ;
        RECT  45.744 25.836 45.768 25.92 ;
    END
  END ro[349]
  PIN ro[34]
    DIRECTION OUTPUT ;
    USE SIGNAL ;
    PORT
      LAYER M5 ;
        RECT  59.28 25.836 59.304 25.92 ;
    END
  END ro[34]
  PIN ro[350]
    DIRECTION OUTPUT ;
    USE SIGNAL ;
    PORT
      LAYER M5 ;
        RECT  45.84 25.836 45.864 25.92 ;
    END
  END ro[350]
  PIN ro[351]
    DIRECTION OUTPUT ;
    USE SIGNAL ;
    PORT
      LAYER M5 ;
        RECT  45.936 25.836 45.96 25.92 ;
    END
  END ro[351]
  PIN ro[352]
    DIRECTION OUTPUT ;
    USE SIGNAL ;
    PORT
      LAYER M5 ;
        RECT  49.104 25.836 49.128 25.92 ;
    END
  END ro[352]
  PIN ro[353]
    DIRECTION OUTPUT ;
    USE SIGNAL ;
    PORT
      LAYER M5 ;
        RECT  49.2 25.836 49.224 25.92 ;
    END
  END ro[353]
  PIN ro[354]
    DIRECTION OUTPUT ;
    USE SIGNAL ;
    PORT
      LAYER M5 ;
        RECT  49.296 25.836 49.32 25.92 ;
    END
  END ro[354]
  PIN ro[355]
    DIRECTION OUTPUT ;
    USE SIGNAL ;
    PORT
      LAYER M5 ;
        RECT  49.392 25.836 49.416 25.92 ;
    END
  END ro[355]
  PIN ro[356]
    DIRECTION OUTPUT ;
    USE SIGNAL ;
    PORT
      LAYER M5 ;
        RECT  49.488 25.836 49.512 25.92 ;
    END
  END ro[356]
  PIN ro[357]
    DIRECTION OUTPUT ;
    USE SIGNAL ;
    PORT
      LAYER M5 ;
        RECT  49.584 25.836 49.608 25.92 ;
    END
  END ro[357]
  PIN ro[358]
    DIRECTION OUTPUT ;
    USE SIGNAL ;
    PORT
      LAYER M5 ;
        RECT  49.68 25.836 49.704 25.92 ;
    END
  END ro[358]
  PIN ro[359]
    DIRECTION OUTPUT ;
    USE SIGNAL ;
    PORT
      LAYER M5 ;
        RECT  49.776 25.836 49.8 25.92 ;
    END
  END ro[359]
  PIN ro[35]
    DIRECTION OUTPUT ;
    USE SIGNAL ;
    PORT
      LAYER M5 ;
        RECT  59.376 25.836 59.4 25.92 ;
    END
  END ro[35]
  PIN ro[360]
    DIRECTION OUTPUT ;
    USE SIGNAL ;
    PORT
      LAYER M5 ;
        RECT  49.872 25.836 49.896 25.92 ;
    END
  END ro[360]
  PIN ro[361]
    DIRECTION OUTPUT ;
    USE SIGNAL ;
    PORT
      LAYER M5 ;
        RECT  49.968 25.836 49.992 25.92 ;
    END
  END ro[361]
  PIN ro[362]
    DIRECTION OUTPUT ;
    USE SIGNAL ;
    PORT
      LAYER M5 ;
        RECT  50.064 25.836 50.088 25.92 ;
    END
  END ro[362]
  PIN ro[363]
    DIRECTION OUTPUT ;
    USE SIGNAL ;
    PORT
      LAYER M5 ;
        RECT  50.16 25.836 50.184 25.92 ;
    END
  END ro[363]
  PIN ro[364]
    DIRECTION OUTPUT ;
    USE SIGNAL ;
    PORT
      LAYER M5 ;
        RECT  50.256 25.836 50.28 25.92 ;
    END
  END ro[364]
  PIN ro[365]
    DIRECTION OUTPUT ;
    USE SIGNAL ;
    PORT
      LAYER M5 ;
        RECT  50.352 25.836 50.376 25.92 ;
    END
  END ro[365]
  PIN ro[366]
    DIRECTION OUTPUT ;
    USE SIGNAL ;
    PORT
      LAYER M5 ;
        RECT  50.448 25.836 50.472 25.92 ;
    END
  END ro[366]
  PIN ro[367]
    DIRECTION OUTPUT ;
    USE SIGNAL ;
    PORT
      LAYER M5 ;
        RECT  50.544 25.836 50.568 25.92 ;
    END
  END ro[367]
  PIN ro[368]
    DIRECTION OUTPUT ;
    USE SIGNAL ;
    PORT
      LAYER M5 ;
        RECT  50.64 25.836 50.664 25.92 ;
    END
  END ro[368]
  PIN ro[369]
    DIRECTION OUTPUT ;
    USE SIGNAL ;
    PORT
      LAYER M5 ;
        RECT  50.736 25.836 50.76 25.92 ;
    END
  END ro[369]
  PIN ro[36]
    DIRECTION OUTPUT ;
    USE SIGNAL ;
    PORT
      LAYER M5 ;
        RECT  59.472 25.836 59.496 25.92 ;
    END
  END ro[36]
  PIN ro[370]
    DIRECTION OUTPUT ;
    USE SIGNAL ;
    PORT
      LAYER M5 ;
        RECT  50.832 25.836 50.856 25.92 ;
    END
  END ro[370]
  PIN ro[371]
    DIRECTION OUTPUT ;
    USE SIGNAL ;
    PORT
      LAYER M5 ;
        RECT  50.928 25.836 50.952 25.92 ;
    END
  END ro[371]
  PIN ro[372]
    DIRECTION OUTPUT ;
    USE SIGNAL ;
    PORT
      LAYER M5 ;
        RECT  51.024 25.836 51.048 25.92 ;
    END
  END ro[372]
  PIN ro[373]
    DIRECTION OUTPUT ;
    USE SIGNAL ;
    PORT
      LAYER M5 ;
        RECT  51.12 25.836 51.144 25.92 ;
    END
  END ro[373]
  PIN ro[374]
    DIRECTION OUTPUT ;
    USE SIGNAL ;
    PORT
      LAYER M5 ;
        RECT  51.216 25.836 51.24 25.92 ;
    END
  END ro[374]
  PIN ro[375]
    DIRECTION OUTPUT ;
    USE SIGNAL ;
    PORT
      LAYER M5 ;
        RECT  51.312 25.836 51.336 25.92 ;
    END
  END ro[375]
  PIN ro[376]
    DIRECTION OUTPUT ;
    USE SIGNAL ;
    PORT
      LAYER M5 ;
        RECT  51.408 25.836 51.432 25.92 ;
    END
  END ro[376]
  PIN ro[377]
    DIRECTION OUTPUT ;
    USE SIGNAL ;
    PORT
      LAYER M5 ;
        RECT  51.504 25.836 51.528 25.92 ;
    END
  END ro[377]
  PIN ro[378]
    DIRECTION OUTPUT ;
    USE SIGNAL ;
    PORT
      LAYER M5 ;
        RECT  51.6 25.836 51.624 25.92 ;
    END
  END ro[378]
  PIN ro[379]
    DIRECTION OUTPUT ;
    USE SIGNAL ;
    PORT
      LAYER M5 ;
        RECT  51.696 25.836 51.72 25.92 ;
    END
  END ro[379]
  PIN ro[37]
    DIRECTION OUTPUT ;
    USE SIGNAL ;
    PORT
      LAYER M5 ;
        RECT  59.568 25.836 59.592 25.92 ;
    END
  END ro[37]
  PIN ro[380]
    DIRECTION OUTPUT ;
    USE SIGNAL ;
    PORT
      LAYER M5 ;
        RECT  51.792 25.836 51.816 25.92 ;
    END
  END ro[380]
  PIN ro[381]
    DIRECTION OUTPUT ;
    USE SIGNAL ;
    PORT
      LAYER M5 ;
        RECT  51.888 25.836 51.912 25.92 ;
    END
  END ro[381]
  PIN ro[382]
    DIRECTION OUTPUT ;
    USE SIGNAL ;
    PORT
      LAYER M5 ;
        RECT  51.984 25.836 52.008 25.92 ;
    END
  END ro[382]
  PIN ro[383]
    DIRECTION OUTPUT ;
    USE SIGNAL ;
    PORT
      LAYER M5 ;
        RECT  52.08 25.836 52.104 25.92 ;
    END
  END ro[383]
  PIN ro[384]
    DIRECTION OUTPUT ;
    USE SIGNAL ;
    PORT
      LAYER M5 ;
        RECT  68.304 25.836 68.328 25.92 ;
    END
  END ro[384]
  PIN ro[385]
    DIRECTION OUTPUT ;
    USE SIGNAL ;
    PORT
      LAYER M5 ;
        RECT  68.4 25.836 68.424 25.92 ;
    END
  END ro[385]
  PIN ro[386]
    DIRECTION OUTPUT ;
    USE SIGNAL ;
    PORT
      LAYER M5 ;
        RECT  68.496 25.836 68.52 25.92 ;
    END
  END ro[386]
  PIN ro[387]
    DIRECTION OUTPUT ;
    USE SIGNAL ;
    PORT
      LAYER M5 ;
        RECT  68.592 25.836 68.616 25.92 ;
    END
  END ro[387]
  PIN ro[388]
    DIRECTION OUTPUT ;
    USE SIGNAL ;
    PORT
      LAYER M5 ;
        RECT  68.688 25.836 68.712 25.92 ;
    END
  END ro[388]
  PIN ro[389]
    DIRECTION OUTPUT ;
    USE SIGNAL ;
    PORT
      LAYER M5 ;
        RECT  68.784 25.836 68.808 25.92 ;
    END
  END ro[389]
  PIN ro[38]
    DIRECTION OUTPUT ;
    USE SIGNAL ;
    PORT
      LAYER M5 ;
        RECT  59.664 25.836 59.688 25.92 ;
    END
  END ro[38]
  PIN ro[390]
    DIRECTION OUTPUT ;
    USE SIGNAL ;
    PORT
      LAYER M5 ;
        RECT  68.88 25.836 68.904 25.92 ;
    END
  END ro[390]
  PIN ro[391]
    DIRECTION OUTPUT ;
    USE SIGNAL ;
    PORT
      LAYER M5 ;
        RECT  68.976 25.836 69 25.92 ;
    END
  END ro[391]
  PIN ro[392]
    DIRECTION OUTPUT ;
    USE SIGNAL ;
    PORT
      LAYER M5 ;
        RECT  69.072 25.836 69.096 25.92 ;
    END
  END ro[392]
  PIN ro[393]
    DIRECTION OUTPUT ;
    USE SIGNAL ;
    PORT
      LAYER M5 ;
        RECT  69.168 25.836 69.192 25.92 ;
    END
  END ro[393]
  PIN ro[394]
    DIRECTION OUTPUT ;
    USE SIGNAL ;
    PORT
      LAYER M5 ;
        RECT  69.264 25.836 69.288 25.92 ;
    END
  END ro[394]
  PIN ro[395]
    DIRECTION OUTPUT ;
    USE SIGNAL ;
    PORT
      LAYER M5 ;
        RECT  69.36 25.836 69.384 25.92 ;
    END
  END ro[395]
  PIN ro[396]
    DIRECTION OUTPUT ;
    USE SIGNAL ;
    PORT
      LAYER M5 ;
        RECT  69.456 25.836 69.48 25.92 ;
    END
  END ro[396]
  PIN ro[397]
    DIRECTION OUTPUT ;
    USE SIGNAL ;
    PORT
      LAYER M5 ;
        RECT  69.552 25.836 69.576 25.92 ;
    END
  END ro[397]
  PIN ro[398]
    DIRECTION OUTPUT ;
    USE SIGNAL ;
    PORT
      LAYER M5 ;
        RECT  69.648 25.836 69.672 25.92 ;
    END
  END ro[398]
  PIN ro[399]
    DIRECTION OUTPUT ;
    USE SIGNAL ;
    PORT
      LAYER M5 ;
        RECT  69.744 25.836 69.768 25.92 ;
    END
  END ro[399]
  PIN ro[39]
    DIRECTION OUTPUT ;
    USE SIGNAL ;
    PORT
      LAYER M5 ;
        RECT  59.76 25.836 59.784 25.92 ;
    END
  END ro[39]
  PIN ro[3]
    DIRECTION OUTPUT ;
    USE SIGNAL ;
    PORT
      LAYER M5 ;
        RECT  71.664 25.836 71.688 25.92 ;
    END
  END ro[3]
  PIN ro[400]
    DIRECTION OUTPUT ;
    USE SIGNAL ;
    PORT
      LAYER M5 ;
        RECT  69.84 25.836 69.864 25.92 ;
    END
  END ro[400]
  PIN ro[401]
    DIRECTION OUTPUT ;
    USE SIGNAL ;
    PORT
      LAYER M5 ;
        RECT  69.936 25.836 69.96 25.92 ;
    END
  END ro[401]
  PIN ro[402]
    DIRECTION OUTPUT ;
    USE SIGNAL ;
    PORT
      LAYER M5 ;
        RECT  70.032 25.836 70.056 25.92 ;
    END
  END ro[402]
  PIN ro[403]
    DIRECTION OUTPUT ;
    USE SIGNAL ;
    PORT
      LAYER M5 ;
        RECT  70.128 25.836 70.152 25.92 ;
    END
  END ro[403]
  PIN ro[404]
    DIRECTION OUTPUT ;
    USE SIGNAL ;
    PORT
      LAYER M5 ;
        RECT  70.224 25.836 70.248 25.92 ;
    END
  END ro[404]
  PIN ro[405]
    DIRECTION OUTPUT ;
    USE SIGNAL ;
    PORT
      LAYER M5 ;
        RECT  70.32 25.836 70.344 25.92 ;
    END
  END ro[405]
  PIN ro[406]
    DIRECTION OUTPUT ;
    USE SIGNAL ;
    PORT
      LAYER M5 ;
        RECT  70.416 25.836 70.44 25.92 ;
    END
  END ro[406]
  PIN ro[407]
    DIRECTION OUTPUT ;
    USE SIGNAL ;
    PORT
      LAYER M5 ;
        RECT  70.512 25.836 70.536 25.92 ;
    END
  END ro[407]
  PIN ro[408]
    DIRECTION OUTPUT ;
    USE SIGNAL ;
    PORT
      LAYER M5 ;
        RECT  70.608 25.836 70.632 25.92 ;
    END
  END ro[408]
  PIN ro[409]
    DIRECTION OUTPUT ;
    USE SIGNAL ;
    PORT
      LAYER M5 ;
        RECT  70.704 25.836 70.728 25.92 ;
    END
  END ro[409]
  PIN ro[40]
    DIRECTION OUTPUT ;
    USE SIGNAL ;
    PORT
      LAYER M5 ;
        RECT  59.856 25.836 59.88 25.92 ;
    END
  END ro[40]
  PIN ro[410]
    DIRECTION OUTPUT ;
    USE SIGNAL ;
    PORT
      LAYER M5 ;
        RECT  70.8 25.836 70.824 25.92 ;
    END
  END ro[410]
  PIN ro[411]
    DIRECTION OUTPUT ;
    USE SIGNAL ;
    PORT
      LAYER M5 ;
        RECT  70.896 25.836 70.92 25.92 ;
    END
  END ro[411]
  PIN ro[412]
    DIRECTION OUTPUT ;
    USE SIGNAL ;
    PORT
      LAYER M5 ;
        RECT  70.992 25.836 71.016 25.92 ;
    END
  END ro[412]
  PIN ro[413]
    DIRECTION OUTPUT ;
    USE SIGNAL ;
    PORT
      LAYER M5 ;
        RECT  71.088 25.836 71.112 25.92 ;
    END
  END ro[413]
  PIN ro[414]
    DIRECTION OUTPUT ;
    USE SIGNAL ;
    PORT
      LAYER M5 ;
        RECT  71.184 25.836 71.208 25.92 ;
    END
  END ro[414]
  PIN ro[415]
    DIRECTION OUTPUT ;
    USE SIGNAL ;
    PORT
      LAYER M5 ;
        RECT  71.28 25.836 71.304 25.92 ;
    END
  END ro[415]
  PIN ro[416]
    DIRECTION OUTPUT ;
    USE SIGNAL ;
    PORT
      LAYER M5 ;
        RECT  87.504 25.836 87.528 25.92 ;
    END
  END ro[416]
  PIN ro[417]
    DIRECTION OUTPUT ;
    USE SIGNAL ;
    PORT
      LAYER M5 ;
        RECT  87.6 25.836 87.624 25.92 ;
    END
  END ro[417]
  PIN ro[418]
    DIRECTION OUTPUT ;
    USE SIGNAL ;
    PORT
      LAYER M5 ;
        RECT  87.696 25.836 87.72 25.92 ;
    END
  END ro[418]
  PIN ro[419]
    DIRECTION OUTPUT ;
    USE SIGNAL ;
    PORT
      LAYER M5 ;
        RECT  87.792 25.836 87.816 25.92 ;
    END
  END ro[419]
  PIN ro[41]
    DIRECTION OUTPUT ;
    USE SIGNAL ;
    PORT
      LAYER M5 ;
        RECT  59.952 25.836 59.976 25.92 ;
    END
  END ro[41]
  PIN ro[420]
    DIRECTION OUTPUT ;
    USE SIGNAL ;
    PORT
      LAYER M5 ;
        RECT  87.888 25.836 87.912 25.92 ;
    END
  END ro[420]
  PIN ro[421]
    DIRECTION OUTPUT ;
    USE SIGNAL ;
    PORT
      LAYER M5 ;
        RECT  87.984 25.836 88.008 25.92 ;
    END
  END ro[421]
  PIN ro[422]
    DIRECTION OUTPUT ;
    USE SIGNAL ;
    PORT
      LAYER M5 ;
        RECT  88.08 25.836 88.104 25.92 ;
    END
  END ro[422]
  PIN ro[423]
    DIRECTION OUTPUT ;
    USE SIGNAL ;
    PORT
      LAYER M5 ;
        RECT  88.176 25.836 88.2 25.92 ;
    END
  END ro[423]
  PIN ro[424]
    DIRECTION OUTPUT ;
    USE SIGNAL ;
    PORT
      LAYER M5 ;
        RECT  88.272 25.836 88.296 25.92 ;
    END
  END ro[424]
  PIN ro[425]
    DIRECTION OUTPUT ;
    USE SIGNAL ;
    PORT
      LAYER M5 ;
        RECT  88.368 25.836 88.392 25.92 ;
    END
  END ro[425]
  PIN ro[426]
    DIRECTION OUTPUT ;
    USE SIGNAL ;
    PORT
      LAYER M5 ;
        RECT  88.464 25.836 88.488 25.92 ;
    END
  END ro[426]
  PIN ro[427]
    DIRECTION OUTPUT ;
    USE SIGNAL ;
    PORT
      LAYER M5 ;
        RECT  88.56 25.836 88.584 25.92 ;
    END
  END ro[427]
  PIN ro[428]
    DIRECTION OUTPUT ;
    USE SIGNAL ;
    PORT
      LAYER M5 ;
        RECT  88.656 25.836 88.68 25.92 ;
    END
  END ro[428]
  PIN ro[429]
    DIRECTION OUTPUT ;
    USE SIGNAL ;
    PORT
      LAYER M5 ;
        RECT  88.752 25.836 88.776 25.92 ;
    END
  END ro[429]
  PIN ro[42]
    DIRECTION OUTPUT ;
    USE SIGNAL ;
    PORT
      LAYER M5 ;
        RECT  60.048 25.836 60.072 25.92 ;
    END
  END ro[42]
  PIN ro[430]
    DIRECTION OUTPUT ;
    USE SIGNAL ;
    PORT
      LAYER M5 ;
        RECT  88.848 25.836 88.872 25.92 ;
    END
  END ro[430]
  PIN ro[431]
    DIRECTION OUTPUT ;
    USE SIGNAL ;
    PORT
      LAYER M5 ;
        RECT  88.944 25.836 88.968 25.92 ;
    END
  END ro[431]
  PIN ro[432]
    DIRECTION OUTPUT ;
    USE SIGNAL ;
    PORT
      LAYER M5 ;
        RECT  89.04 25.836 89.064 25.92 ;
    END
  END ro[432]
  PIN ro[433]
    DIRECTION OUTPUT ;
    USE SIGNAL ;
    PORT
      LAYER M5 ;
        RECT  89.136 25.836 89.16 25.92 ;
    END
  END ro[433]
  PIN ro[434]
    DIRECTION OUTPUT ;
    USE SIGNAL ;
    PORT
      LAYER M5 ;
        RECT  89.232 25.836 89.256 25.92 ;
    END
  END ro[434]
  PIN ro[435]
    DIRECTION OUTPUT ;
    USE SIGNAL ;
    PORT
      LAYER M5 ;
        RECT  89.328 25.836 89.352 25.92 ;
    END
  END ro[435]
  PIN ro[436]
    DIRECTION OUTPUT ;
    USE SIGNAL ;
    PORT
      LAYER M5 ;
        RECT  89.424 25.836 89.448 25.92 ;
    END
  END ro[436]
  PIN ro[437]
    DIRECTION OUTPUT ;
    USE SIGNAL ;
    PORT
      LAYER M5 ;
        RECT  89.52 25.836 89.544 25.92 ;
    END
  END ro[437]
  PIN ro[438]
    DIRECTION OUTPUT ;
    USE SIGNAL ;
    PORT
      LAYER M5 ;
        RECT  89.616 25.836 89.64 25.92 ;
    END
  END ro[438]
  PIN ro[439]
    DIRECTION OUTPUT ;
    USE SIGNAL ;
    PORT
      LAYER M5 ;
        RECT  89.712 25.836 89.736 25.92 ;
    END
  END ro[439]
  PIN ro[43]
    DIRECTION OUTPUT ;
    USE SIGNAL ;
    PORT
      LAYER M5 ;
        RECT  60.144 25.836 60.168 25.92 ;
    END
  END ro[43]
  PIN ro[440]
    DIRECTION OUTPUT ;
    USE SIGNAL ;
    PORT
      LAYER M5 ;
        RECT  89.808 25.836 89.832 25.92 ;
    END
  END ro[440]
  PIN ro[441]
    DIRECTION OUTPUT ;
    USE SIGNAL ;
    PORT
      LAYER M5 ;
        RECT  89.904 25.836 89.928 25.92 ;
    END
  END ro[441]
  PIN ro[442]
    DIRECTION OUTPUT ;
    USE SIGNAL ;
    PORT
      LAYER M5 ;
        RECT  90 25.836 90.024 25.92 ;
    END
  END ro[442]
  PIN ro[443]
    DIRECTION OUTPUT ;
    USE SIGNAL ;
    PORT
      LAYER M5 ;
        RECT  90.096 25.836 90.12 25.92 ;
    END
  END ro[443]
  PIN ro[444]
    DIRECTION OUTPUT ;
    USE SIGNAL ;
    PORT
      LAYER M5 ;
        RECT  90.192 25.836 90.216 25.92 ;
    END
  END ro[444]
  PIN ro[445]
    DIRECTION OUTPUT ;
    USE SIGNAL ;
    PORT
      LAYER M5 ;
        RECT  90.288 25.836 90.312 25.92 ;
    END
  END ro[445]
  PIN ro[446]
    DIRECTION OUTPUT ;
    USE SIGNAL ;
    PORT
      LAYER M5 ;
        RECT  90.384 25.836 90.408 25.92 ;
    END
  END ro[446]
  PIN ro[447]
    DIRECTION OUTPUT ;
    USE SIGNAL ;
    PORT
      LAYER M5 ;
        RECT  90.48 25.836 90.504 25.92 ;
    END
  END ro[447]
  PIN ro[448]
    DIRECTION OUTPUT ;
    USE SIGNAL ;
    PORT
      LAYER M5 ;
        RECT  26.832 25.836 26.856 25.92 ;
    END
  END ro[448]
  PIN ro[449]
    DIRECTION OUTPUT ;
    USE SIGNAL ;
    PORT
      LAYER M5 ;
        RECT  26.928 25.836 26.952 25.92 ;
    END
  END ro[449]
  PIN ro[44]
    DIRECTION OUTPUT ;
    USE SIGNAL ;
    PORT
      LAYER M5 ;
        RECT  60.24 25.836 60.264 25.92 ;
    END
  END ro[44]
  PIN ro[450]
    DIRECTION OUTPUT ;
    USE SIGNAL ;
    PORT
      LAYER M5 ;
        RECT  27.024 25.836 27.048 25.92 ;
    END
  END ro[450]
  PIN ro[451]
    DIRECTION OUTPUT ;
    USE SIGNAL ;
    PORT
      LAYER M5 ;
        RECT  27.12 25.836 27.144 25.92 ;
    END
  END ro[451]
  PIN ro[452]
    DIRECTION OUTPUT ;
    USE SIGNAL ;
    PORT
      LAYER M5 ;
        RECT  27.216 25.836 27.24 25.92 ;
    END
  END ro[452]
  PIN ro[453]
    DIRECTION OUTPUT ;
    USE SIGNAL ;
    PORT
      LAYER M5 ;
        RECT  27.312 25.836 27.336 25.92 ;
    END
  END ro[453]
  PIN ro[454]
    DIRECTION OUTPUT ;
    USE SIGNAL ;
    PORT
      LAYER M5 ;
        RECT  27.408 25.836 27.432 25.92 ;
    END
  END ro[454]
  PIN ro[455]
    DIRECTION OUTPUT ;
    USE SIGNAL ;
    PORT
      LAYER M5 ;
        RECT  27.504 25.836 27.528 25.92 ;
    END
  END ro[455]
  PIN ro[456]
    DIRECTION OUTPUT ;
    USE SIGNAL ;
    PORT
      LAYER M5 ;
        RECT  27.6 25.836 27.624 25.92 ;
    END
  END ro[456]
  PIN ro[457]
    DIRECTION OUTPUT ;
    USE SIGNAL ;
    PORT
      LAYER M5 ;
        RECT  27.696 25.836 27.72 25.92 ;
    END
  END ro[457]
  PIN ro[458]
    DIRECTION OUTPUT ;
    USE SIGNAL ;
    PORT
      LAYER M5 ;
        RECT  27.792 25.836 27.816 25.92 ;
    END
  END ro[458]
  PIN ro[459]
    DIRECTION OUTPUT ;
    USE SIGNAL ;
    PORT
      LAYER M5 ;
        RECT  27.888 25.836 27.912 25.92 ;
    END
  END ro[459]
  PIN ro[45]
    DIRECTION OUTPUT ;
    USE SIGNAL ;
    PORT
      LAYER M5 ;
        RECT  60.336 25.836 60.36 25.92 ;
    END
  END ro[45]
  PIN ro[460]
    DIRECTION OUTPUT ;
    USE SIGNAL ;
    PORT
      LAYER M5 ;
        RECT  27.984 25.836 28.008 25.92 ;
    END
  END ro[460]
  PIN ro[461]
    DIRECTION OUTPUT ;
    USE SIGNAL ;
    PORT
      LAYER M5 ;
        RECT  28.08 25.836 28.104 25.92 ;
    END
  END ro[461]
  PIN ro[462]
    DIRECTION OUTPUT ;
    USE SIGNAL ;
    PORT
      LAYER M5 ;
        RECT  28.176 25.836 28.2 25.92 ;
    END
  END ro[462]
  PIN ro[463]
    DIRECTION OUTPUT ;
    USE SIGNAL ;
    PORT
      LAYER M5 ;
        RECT  28.272 25.836 28.296 25.92 ;
    END
  END ro[463]
  PIN ro[464]
    DIRECTION OUTPUT ;
    USE SIGNAL ;
    PORT
      LAYER M5 ;
        RECT  28.368 25.836 28.392 25.92 ;
    END
  END ro[464]
  PIN ro[465]
    DIRECTION OUTPUT ;
    USE SIGNAL ;
    PORT
      LAYER M5 ;
        RECT  28.464 25.836 28.488 25.92 ;
    END
  END ro[465]
  PIN ro[466]
    DIRECTION OUTPUT ;
    USE SIGNAL ;
    PORT
      LAYER M5 ;
        RECT  28.56 25.836 28.584 25.92 ;
    END
  END ro[466]
  PIN ro[467]
    DIRECTION OUTPUT ;
    USE SIGNAL ;
    PORT
      LAYER M5 ;
        RECT  28.656 25.836 28.68 25.92 ;
    END
  END ro[467]
  PIN ro[468]
    DIRECTION OUTPUT ;
    USE SIGNAL ;
    PORT
      LAYER M5 ;
        RECT  28.752 25.836 28.776 25.92 ;
    END
  END ro[468]
  PIN ro[469]
    DIRECTION OUTPUT ;
    USE SIGNAL ;
    PORT
      LAYER M5 ;
        RECT  28.848 25.836 28.872 25.92 ;
    END
  END ro[469]
  PIN ro[46]
    DIRECTION OUTPUT ;
    USE SIGNAL ;
    PORT
      LAYER M5 ;
        RECT  60.432 25.836 60.456 25.92 ;
    END
  END ro[46]
  PIN ro[470]
    DIRECTION OUTPUT ;
    USE SIGNAL ;
    PORT
      LAYER M5 ;
        RECT  28.944 25.836 28.968 25.92 ;
    END
  END ro[470]
  PIN ro[471]
    DIRECTION OUTPUT ;
    USE SIGNAL ;
    PORT
      LAYER M5 ;
        RECT  29.04 25.836 29.064 25.92 ;
    END
  END ro[471]
  PIN ro[472]
    DIRECTION OUTPUT ;
    USE SIGNAL ;
    PORT
      LAYER M5 ;
        RECT  29.136 25.836 29.16 25.92 ;
    END
  END ro[472]
  PIN ro[473]
    DIRECTION OUTPUT ;
    USE SIGNAL ;
    PORT
      LAYER M5 ;
        RECT  29.232 25.836 29.256 25.92 ;
    END
  END ro[473]
  PIN ro[474]
    DIRECTION OUTPUT ;
    USE SIGNAL ;
    PORT
      LAYER M5 ;
        RECT  29.328 25.836 29.352 25.92 ;
    END
  END ro[474]
  PIN ro[475]
    DIRECTION OUTPUT ;
    USE SIGNAL ;
    PORT
      LAYER M5 ;
        RECT  29.424 25.836 29.448 25.92 ;
    END
  END ro[475]
  PIN ro[476]
    DIRECTION OUTPUT ;
    USE SIGNAL ;
    PORT
      LAYER M5 ;
        RECT  29.52 25.836 29.544 25.92 ;
    END
  END ro[476]
  PIN ro[477]
    DIRECTION OUTPUT ;
    USE SIGNAL ;
    PORT
      LAYER M5 ;
        RECT  29.616 25.836 29.64 25.92 ;
    END
  END ro[477]
  PIN ro[478]
    DIRECTION OUTPUT ;
    USE SIGNAL ;
    PORT
      LAYER M5 ;
        RECT  29.712 25.836 29.736 25.92 ;
    END
  END ro[478]
  PIN ro[479]
    DIRECTION OUTPUT ;
    USE SIGNAL ;
    PORT
      LAYER M5 ;
        RECT  29.808 25.836 29.832 25.92 ;
    END
  END ro[479]
  PIN ro[47]
    DIRECTION OUTPUT ;
    USE SIGNAL ;
    PORT
      LAYER M5 ;
        RECT  60.528 25.836 60.552 25.92 ;
    END
  END ro[47]
  PIN ro[480]
    DIRECTION OUTPUT ;
    USE SIGNAL ;
    PORT
      LAYER M5 ;
        RECT  55.248 25.836 55.272 25.92 ;
    END
  END ro[480]
  PIN ro[481]
    DIRECTION OUTPUT ;
    USE SIGNAL ;
    PORT
      LAYER M5 ;
        RECT  55.344 25.836 55.368 25.92 ;
    END
  END ro[481]
  PIN ro[482]
    DIRECTION OUTPUT ;
    USE SIGNAL ;
    PORT
      LAYER M5 ;
        RECT  55.44 25.836 55.464 25.92 ;
    END
  END ro[482]
  PIN ro[483]
    DIRECTION OUTPUT ;
    USE SIGNAL ;
    PORT
      LAYER M5 ;
        RECT  55.536 25.836 55.56 25.92 ;
    END
  END ro[483]
  PIN ro[484]
    DIRECTION OUTPUT ;
    USE SIGNAL ;
    PORT
      LAYER M5 ;
        RECT  55.632 25.836 55.656 25.92 ;
    END
  END ro[484]
  PIN ro[485]
    DIRECTION OUTPUT ;
    USE SIGNAL ;
    PORT
      LAYER M5 ;
        RECT  55.728 25.836 55.752 25.92 ;
    END
  END ro[485]
  PIN ro[486]
    DIRECTION OUTPUT ;
    USE SIGNAL ;
    PORT
      LAYER M5 ;
        RECT  55.824 25.836 55.848 25.92 ;
    END
  END ro[486]
  PIN ro[487]
    DIRECTION OUTPUT ;
    USE SIGNAL ;
    PORT
      LAYER M5 ;
        RECT  55.92 25.836 55.944 25.92 ;
    END
  END ro[487]
  PIN ro[488]
    DIRECTION OUTPUT ;
    USE SIGNAL ;
    PORT
      LAYER M5 ;
        RECT  56.016 25.836 56.04 25.92 ;
    END
  END ro[488]
  PIN ro[489]
    DIRECTION OUTPUT ;
    USE SIGNAL ;
    PORT
      LAYER M5 ;
        RECT  56.112 25.836 56.136 25.92 ;
    END
  END ro[489]
  PIN ro[48]
    DIRECTION OUTPUT ;
    USE SIGNAL ;
    PORT
      LAYER M5 ;
        RECT  60.624 25.836 60.648 25.92 ;
    END
  END ro[48]
  PIN ro[490]
    DIRECTION OUTPUT ;
    USE SIGNAL ;
    PORT
      LAYER M5 ;
        RECT  56.208 25.836 56.232 25.92 ;
    END
  END ro[490]
  PIN ro[491]
    DIRECTION OUTPUT ;
    USE SIGNAL ;
    PORT
      LAYER M5 ;
        RECT  56.304 25.836 56.328 25.92 ;
    END
  END ro[491]
  PIN ro[492]
    DIRECTION OUTPUT ;
    USE SIGNAL ;
    PORT
      LAYER M5 ;
        RECT  56.4 25.836 56.424 25.92 ;
    END
  END ro[492]
  PIN ro[493]
    DIRECTION OUTPUT ;
    USE SIGNAL ;
    PORT
      LAYER M5 ;
        RECT  56.496 25.836 56.52 25.92 ;
    END
  END ro[493]
  PIN ro[494]
    DIRECTION OUTPUT ;
    USE SIGNAL ;
    PORT
      LAYER M5 ;
        RECT  56.592 25.836 56.616 25.92 ;
    END
  END ro[494]
  PIN ro[495]
    DIRECTION OUTPUT ;
    USE SIGNAL ;
    PORT
      LAYER M5 ;
        RECT  56.688 25.836 56.712 25.92 ;
    END
  END ro[495]
  PIN ro[496]
    DIRECTION OUTPUT ;
    USE SIGNAL ;
    PORT
      LAYER M5 ;
        RECT  56.784 25.836 56.808 25.92 ;
    END
  END ro[496]
  PIN ro[497]
    DIRECTION OUTPUT ;
    USE SIGNAL ;
    PORT
      LAYER M5 ;
        RECT  56.88 25.836 56.904 25.92 ;
    END
  END ro[497]
  PIN ro[498]
    DIRECTION OUTPUT ;
    USE SIGNAL ;
    PORT
      LAYER M5 ;
        RECT  56.976 25.836 57 25.92 ;
    END
  END ro[498]
  PIN ro[499]
    DIRECTION OUTPUT ;
    USE SIGNAL ;
    PORT
      LAYER M5 ;
        RECT  57.072 25.836 57.096 25.92 ;
    END
  END ro[499]
  PIN ro[49]
    DIRECTION OUTPUT ;
    USE SIGNAL ;
    PORT
      LAYER M5 ;
        RECT  60.72 25.836 60.744 25.92 ;
    END
  END ro[49]
  PIN ro[4]
    DIRECTION OUTPUT ;
    USE SIGNAL ;
    PORT
      LAYER M5 ;
        RECT  71.76 25.836 71.784 25.92 ;
    END
  END ro[4]
  PIN ro[500]
    DIRECTION OUTPUT ;
    USE SIGNAL ;
    PORT
      LAYER M5 ;
        RECT  57.168 25.836 57.192 25.92 ;
    END
  END ro[500]
  PIN ro[501]
    DIRECTION OUTPUT ;
    USE SIGNAL ;
    PORT
      LAYER M5 ;
        RECT  57.264 25.836 57.288 25.92 ;
    END
  END ro[501]
  PIN ro[502]
    DIRECTION OUTPUT ;
    USE SIGNAL ;
    PORT
      LAYER M5 ;
        RECT  57.36 25.836 57.384 25.92 ;
    END
  END ro[502]
  PIN ro[503]
    DIRECTION OUTPUT ;
    USE SIGNAL ;
    PORT
      LAYER M5 ;
        RECT  57.456 25.836 57.48 25.92 ;
    END
  END ro[503]
  PIN ro[504]
    DIRECTION OUTPUT ;
    USE SIGNAL ;
    PORT
      LAYER M5 ;
        RECT  57.552 25.836 57.576 25.92 ;
    END
  END ro[504]
  PIN ro[505]
    DIRECTION OUTPUT ;
    USE SIGNAL ;
    PORT
      LAYER M5 ;
        RECT  57.648 25.836 57.672 25.92 ;
    END
  END ro[505]
  PIN ro[506]
    DIRECTION OUTPUT ;
    USE SIGNAL ;
    PORT
      LAYER M5 ;
        RECT  57.744 25.836 57.768 25.92 ;
    END
  END ro[506]
  PIN ro[507]
    DIRECTION OUTPUT ;
    USE SIGNAL ;
    PORT
      LAYER M5 ;
        RECT  57.84 25.836 57.864 25.92 ;
    END
  END ro[507]
  PIN ro[508]
    DIRECTION OUTPUT ;
    USE SIGNAL ;
    PORT
      LAYER M5 ;
        RECT  57.936 25.836 57.96 25.92 ;
    END
  END ro[508]
  PIN ro[509]
    DIRECTION OUTPUT ;
    USE SIGNAL ;
    PORT
      LAYER M5 ;
        RECT  58.032 25.836 58.056 25.92 ;
    END
  END ro[509]
  PIN ro[50]
    DIRECTION OUTPUT ;
    USE SIGNAL ;
    PORT
      LAYER M5 ;
        RECT  60.816 25.836 60.84 25.92 ;
    END
  END ro[50]
  PIN ro[510]
    DIRECTION OUTPUT ;
    USE SIGNAL ;
    PORT
      LAYER M5 ;
        RECT  58.128 25.836 58.152 25.92 ;
    END
  END ro[510]
  PIN ro[511]
    DIRECTION OUTPUT ;
    USE SIGNAL ;
    PORT
      LAYER M5 ;
        RECT  58.224 25.836 58.248 25.92 ;
    END
  END ro[511]
  PIN ro[51]
    DIRECTION OUTPUT ;
    USE SIGNAL ;
    PORT
      LAYER M5 ;
        RECT  60.912 25.836 60.936 25.92 ;
    END
  END ro[51]
  PIN ro[52]
    DIRECTION OUTPUT ;
    USE SIGNAL ;
    PORT
      LAYER M5 ;
        RECT  61.008 25.836 61.032 25.92 ;
    END
  END ro[52]
  PIN ro[53]
    DIRECTION OUTPUT ;
    USE SIGNAL ;
    PORT
      LAYER M5 ;
        RECT  61.104 25.836 61.128 25.92 ;
    END
  END ro[53]
  PIN ro[54]
    DIRECTION OUTPUT ;
    USE SIGNAL ;
    PORT
      LAYER M5 ;
        RECT  61.2 25.836 61.224 25.92 ;
    END
  END ro[54]
  PIN ro[55]
    DIRECTION OUTPUT ;
    USE SIGNAL ;
    PORT
      LAYER M5 ;
        RECT  61.296 25.836 61.32 25.92 ;
    END
  END ro[55]
  PIN ro[56]
    DIRECTION OUTPUT ;
    USE SIGNAL ;
    PORT
      LAYER M5 ;
        RECT  61.392 25.836 61.416 25.92 ;
    END
  END ro[56]
  PIN ro[57]
    DIRECTION OUTPUT ;
    USE SIGNAL ;
    PORT
      LAYER M5 ;
        RECT  61.488 25.836 61.512 25.92 ;
    END
  END ro[57]
  PIN ro[58]
    DIRECTION OUTPUT ;
    USE SIGNAL ;
    PORT
      LAYER M5 ;
        RECT  61.584 25.836 61.608 25.92 ;
    END
  END ro[58]
  PIN ro[59]
    DIRECTION OUTPUT ;
    USE SIGNAL ;
    PORT
      LAYER M5 ;
        RECT  61.68 25.836 61.704 25.92 ;
    END
  END ro[59]
  PIN ro[5]
    DIRECTION OUTPUT ;
    USE SIGNAL ;
    PORT
      LAYER M5 ;
        RECT  71.856 25.836 71.88 25.92 ;
    END
  END ro[5]
  PIN ro[60]
    DIRECTION OUTPUT ;
    USE SIGNAL ;
    PORT
      LAYER M5 ;
        RECT  61.776 25.836 61.8 25.92 ;
    END
  END ro[60]
  PIN ro[61]
    DIRECTION OUTPUT ;
    USE SIGNAL ;
    PORT
      LAYER M5 ;
        RECT  61.872 25.836 61.896 25.92 ;
    END
  END ro[61]
  PIN ro[62]
    DIRECTION OUTPUT ;
    USE SIGNAL ;
    PORT
      LAYER M5 ;
        RECT  61.968 25.836 61.992 25.92 ;
    END
  END ro[62]
  PIN ro[63]
    DIRECTION OUTPUT ;
    USE SIGNAL ;
    PORT
      LAYER M5 ;
        RECT  62.064 25.836 62.088 25.92 ;
    END
  END ro[63]
  PIN ro[64]
    DIRECTION OUTPUT ;
    USE SIGNAL ;
    PORT
      LAYER M5 ;
        RECT  23.76 25.836 23.784 25.92 ;
    END
  END ro[64]
  PIN ro[65]
    DIRECTION OUTPUT ;
    USE SIGNAL ;
    PORT
      LAYER M5 ;
        RECT  23.856 25.836 23.88 25.92 ;
    END
  END ro[65]
  PIN ro[66]
    DIRECTION OUTPUT ;
    USE SIGNAL ;
    PORT
      LAYER M5 ;
        RECT  23.952 25.836 23.976 25.92 ;
    END
  END ro[66]
  PIN ro[67]
    DIRECTION OUTPUT ;
    USE SIGNAL ;
    PORT
      LAYER M5 ;
        RECT  24.048 25.836 24.072 25.92 ;
    END
  END ro[67]
  PIN ro[68]
    DIRECTION OUTPUT ;
    USE SIGNAL ;
    PORT
      LAYER M5 ;
        RECT  24.144 25.836 24.168 25.92 ;
    END
  END ro[68]
  PIN ro[69]
    DIRECTION OUTPUT ;
    USE SIGNAL ;
    PORT
      LAYER M5 ;
        RECT  24.24 25.836 24.264 25.92 ;
    END
  END ro[69]
  PIN ro[6]
    DIRECTION OUTPUT ;
    USE SIGNAL ;
    PORT
      LAYER M5 ;
        RECT  71.952 25.836 71.976 25.92 ;
    END
  END ro[6]
  PIN ro[70]
    DIRECTION OUTPUT ;
    USE SIGNAL ;
    PORT
      LAYER M5 ;
        RECT  24.336 25.836 24.36 25.92 ;
    END
  END ro[70]
  PIN ro[71]
    DIRECTION OUTPUT ;
    USE SIGNAL ;
    PORT
      LAYER M5 ;
        RECT  24.432 25.836 24.456 25.92 ;
    END
  END ro[71]
  PIN ro[72]
    DIRECTION OUTPUT ;
    USE SIGNAL ;
    PORT
      LAYER M5 ;
        RECT  24.528 25.836 24.552 25.92 ;
    END
  END ro[72]
  PIN ro[73]
    DIRECTION OUTPUT ;
    USE SIGNAL ;
    PORT
      LAYER M5 ;
        RECT  24.624 25.836 24.648 25.92 ;
    END
  END ro[73]
  PIN ro[74]
    DIRECTION OUTPUT ;
    USE SIGNAL ;
    PORT
      LAYER M5 ;
        RECT  24.72 25.836 24.744 25.92 ;
    END
  END ro[74]
  PIN ro[75]
    DIRECTION OUTPUT ;
    USE SIGNAL ;
    PORT
      LAYER M5 ;
        RECT  24.816 25.836 24.84 25.92 ;
    END
  END ro[75]
  PIN ro[76]
    DIRECTION OUTPUT ;
    USE SIGNAL ;
    PORT
      LAYER M5 ;
        RECT  24.912 25.836 24.936 25.92 ;
    END
  END ro[76]
  PIN ro[77]
    DIRECTION OUTPUT ;
    USE SIGNAL ;
    PORT
      LAYER M5 ;
        RECT  25.008 25.836 25.032 25.92 ;
    END
  END ro[77]
  PIN ro[78]
    DIRECTION OUTPUT ;
    USE SIGNAL ;
    PORT
      LAYER M5 ;
        RECT  25.104 25.836 25.128 25.92 ;
    END
  END ro[78]
  PIN ro[79]
    DIRECTION OUTPUT ;
    USE SIGNAL ;
    PORT
      LAYER M5 ;
        RECT  25.2 25.836 25.224 25.92 ;
    END
  END ro[79]
  PIN ro[7]
    DIRECTION OUTPUT ;
    USE SIGNAL ;
    PORT
      LAYER M5 ;
        RECT  72.048 25.836 72.072 25.92 ;
    END
  END ro[7]
  PIN ro[80]
    DIRECTION OUTPUT ;
    USE SIGNAL ;
    PORT
      LAYER M5 ;
        RECT  25.296 25.836 25.32 25.92 ;
    END
  END ro[80]
  PIN ro[81]
    DIRECTION OUTPUT ;
    USE SIGNAL ;
    PORT
      LAYER M5 ;
        RECT  25.392 25.836 25.416 25.92 ;
    END
  END ro[81]
  PIN ro[82]
    DIRECTION OUTPUT ;
    USE SIGNAL ;
    PORT
      LAYER M5 ;
        RECT  25.488 25.836 25.512 25.92 ;
    END
  END ro[82]
  PIN ro[83]
    DIRECTION OUTPUT ;
    USE SIGNAL ;
    PORT
      LAYER M5 ;
        RECT  25.584 25.836 25.608 25.92 ;
    END
  END ro[83]
  PIN ro[84]
    DIRECTION OUTPUT ;
    USE SIGNAL ;
    PORT
      LAYER M5 ;
        RECT  25.68 25.836 25.704 25.92 ;
    END
  END ro[84]
  PIN ro[85]
    DIRECTION OUTPUT ;
    USE SIGNAL ;
    PORT
      LAYER M5 ;
        RECT  25.776 25.836 25.8 25.92 ;
    END
  END ro[85]
  PIN ro[86]
    DIRECTION OUTPUT ;
    USE SIGNAL ;
    PORT
      LAYER M5 ;
        RECT  25.872 25.836 25.896 25.92 ;
    END
  END ro[86]
  PIN ro[87]
    DIRECTION OUTPUT ;
    USE SIGNAL ;
    PORT
      LAYER M5 ;
        RECT  25.968 25.836 25.992 25.92 ;
    END
  END ro[87]
  PIN ro[88]
    DIRECTION OUTPUT ;
    USE SIGNAL ;
    PORT
      LAYER M5 ;
        RECT  26.064 25.836 26.088 25.92 ;
    END
  END ro[88]
  PIN ro[89]
    DIRECTION OUTPUT ;
    USE SIGNAL ;
    PORT
      LAYER M5 ;
        RECT  26.16 25.836 26.184 25.92 ;
    END
  END ro[89]
  PIN ro[8]
    DIRECTION OUTPUT ;
    USE SIGNAL ;
    PORT
      LAYER M5 ;
        RECT  72.144 25.836 72.168 25.92 ;
    END
  END ro[8]
  PIN ro[90]
    DIRECTION OUTPUT ;
    USE SIGNAL ;
    PORT
      LAYER M5 ;
        RECT  26.256 25.836 26.28 25.92 ;
    END
  END ro[90]
  PIN ro[91]
    DIRECTION OUTPUT ;
    USE SIGNAL ;
    PORT
      LAYER M5 ;
        RECT  26.352 25.836 26.376 25.92 ;
    END
  END ro[91]
  PIN ro[92]
    DIRECTION OUTPUT ;
    USE SIGNAL ;
    PORT
      LAYER M5 ;
        RECT  26.448 25.836 26.472 25.92 ;
    END
  END ro[92]
  PIN ro[93]
    DIRECTION OUTPUT ;
    USE SIGNAL ;
    PORT
      LAYER M5 ;
        RECT  26.544 25.836 26.568 25.92 ;
    END
  END ro[93]
  PIN ro[94]
    DIRECTION OUTPUT ;
    USE SIGNAL ;
    PORT
      LAYER M5 ;
        RECT  26.64 25.836 26.664 25.92 ;
    END
  END ro[94]
  PIN ro[95]
    DIRECTION OUTPUT ;
    USE SIGNAL ;
    PORT
      LAYER M5 ;
        RECT  26.736 25.836 26.76 25.92 ;
    END
  END ro[95]
  PIN ro[96]
    DIRECTION OUTPUT ;
    USE SIGNAL ;
    PORT
      LAYER M5 ;
        RECT  52.176 25.836 52.2 25.92 ;
    END
  END ro[96]
  PIN ro[97]
    DIRECTION OUTPUT ;
    USE SIGNAL ;
    PORT
      LAYER M5 ;
        RECT  52.272 25.836 52.296 25.92 ;
    END
  END ro[97]
  PIN ro[98]
    DIRECTION OUTPUT ;
    USE SIGNAL ;
    PORT
      LAYER M5 ;
        RECT  52.368 25.836 52.392 25.92 ;
    END
  END ro[98]
  PIN ro[99]
    DIRECTION OUTPUT ;
    USE SIGNAL ;
    PORT
      LAYER M5 ;
        RECT  52.464 25.836 52.488 25.92 ;
    END
  END ro[99]
  PIN ro[9]
    DIRECTION OUTPUT ;
    USE SIGNAL ;
    PORT
      LAYER M5 ;
        RECT  72.24 25.836 72.264 25.92 ;
    END
  END ro[9]
  PIN rq
    DIRECTION INPUT ;
    USE SIGNAL ;
    PORT
      LAYER M4 ;
        RECT  0 12.528 0.084 12.552 ;
    END
  END rq
  PIN rqb[0]
    DIRECTION INPUT ;
    USE SIGNAL ;
    PORT
      LAYER M4 ;
        RECT  0 12.624 0.084 12.648 ;
    END
  END rqb[0]
  PIN rqb[1]
    DIRECTION INPUT ;
    USE SIGNAL ;
    PORT
      LAYER M4 ;
        RECT  0 12.72 0.084 12.744 ;
    END
  END rqb[1]
  PIN rqb[2]
    DIRECTION INPUT ;
    USE SIGNAL ;
    PORT
      LAYER M4 ;
        RECT  0 12.816 0.084 12.84 ;
    END
  END rqb[2]
  PIN rst_n
    DIRECTION INPUT ;
    USE SIGNAL ;
    PORT
      LAYER M4 ;
        RECT  0 12.912 0.084 12.936 ;
    END
  END rst_n
  PIN t1a[0]
    DIRECTION INPUT ;
    USE SIGNAL ;
    PORT
      LAYER M5 ;
        RECT  84.432 25.836 84.456 25.92 ;
    END
  END t1a[0]
  PIN t1a[100]
    DIRECTION INPUT ;
    USE SIGNAL ;
    PORT
      LAYER M5 ;
        RECT  36.432 25.836 36.456 25.92 ;
    END
  END t1a[100]
  PIN t1a[101]
    DIRECTION INPUT ;
    USE SIGNAL ;
    PORT
      LAYER M5 ;
        RECT  36.528 25.836 36.552 25.92 ;
    END
  END t1a[101]
  PIN t1a[102]
    DIRECTION INPUT ;
    USE SIGNAL ;
    PORT
      LAYER M5 ;
        RECT  36.624 25.836 36.648 25.92 ;
    END
  END t1a[102]
  PIN t1a[103]
    DIRECTION INPUT ;
    USE SIGNAL ;
    PORT
      LAYER M5 ;
        RECT  36.72 25.836 36.744 25.92 ;
    END
  END t1a[103]
  PIN t1a[104]
    DIRECTION INPUT ;
    USE SIGNAL ;
    PORT
      LAYER M5 ;
        RECT  36.816 25.836 36.84 25.92 ;
    END
  END t1a[104]
  PIN t1a[105]
    DIRECTION INPUT ;
    USE SIGNAL ;
    PORT
      LAYER M5 ;
        RECT  36.912 25.836 36.936 25.92 ;
    END
  END t1a[105]
  PIN t1a[106]
    DIRECTION INPUT ;
    USE SIGNAL ;
    PORT
      LAYER M5 ;
        RECT  37.008 25.836 37.032 25.92 ;
    END
  END t1a[106]
  PIN t1a[107]
    DIRECTION INPUT ;
    USE SIGNAL ;
    PORT
      LAYER M5 ;
        RECT  37.104 25.836 37.128 25.92 ;
    END
  END t1a[107]
  PIN t1a[108]
    DIRECTION INPUT ;
    USE SIGNAL ;
    PORT
      LAYER M5 ;
        RECT  37.2 25.836 37.224 25.92 ;
    END
  END t1a[108]
  PIN t1a[109]
    DIRECTION INPUT ;
    USE SIGNAL ;
    PORT
      LAYER M5 ;
        RECT  37.296 25.836 37.32 25.92 ;
    END
  END t1a[109]
  PIN t1a[10]
    DIRECTION INPUT ;
    USE SIGNAL ;
    PORT
      LAYER M5 ;
        RECT  85.392 25.836 85.416 25.92 ;
    END
  END t1a[10]
  PIN t1a[110]
    DIRECTION INPUT ;
    USE SIGNAL ;
    PORT
      LAYER M5 ;
        RECT  37.392 25.836 37.416 25.92 ;
    END
  END t1a[110]
  PIN t1a[111]
    DIRECTION INPUT ;
    USE SIGNAL ;
    PORT
      LAYER M5 ;
        RECT  37.488 25.836 37.512 25.92 ;
    END
  END t1a[111]
  PIN t1a[112]
    DIRECTION INPUT ;
    USE SIGNAL ;
    PORT
      LAYER M5 ;
        RECT  37.584 25.836 37.608 25.92 ;
    END
  END t1a[112]
  PIN t1a[113]
    DIRECTION INPUT ;
    USE SIGNAL ;
    PORT
      LAYER M5 ;
        RECT  37.68 25.836 37.704 25.92 ;
    END
  END t1a[113]
  PIN t1a[114]
    DIRECTION INPUT ;
    USE SIGNAL ;
    PORT
      LAYER M5 ;
        RECT  37.776 25.836 37.8 25.92 ;
    END
  END t1a[114]
  PIN t1a[115]
    DIRECTION INPUT ;
    USE SIGNAL ;
    PORT
      LAYER M5 ;
        RECT  37.872 25.836 37.896 25.92 ;
    END
  END t1a[115]
  PIN t1a[116]
    DIRECTION INPUT ;
    USE SIGNAL ;
    PORT
      LAYER M5 ;
        RECT  37.968 25.836 37.992 25.92 ;
    END
  END t1a[116]
  PIN t1a[117]
    DIRECTION INPUT ;
    USE SIGNAL ;
    PORT
      LAYER M5 ;
        RECT  38.064 25.836 38.088 25.92 ;
    END
  END t1a[117]
  PIN t1a[118]
    DIRECTION INPUT ;
    USE SIGNAL ;
    PORT
      LAYER M5 ;
        RECT  38.16 25.836 38.184 25.92 ;
    END
  END t1a[118]
  PIN t1a[119]
    DIRECTION INPUT ;
    USE SIGNAL ;
    PORT
      LAYER M5 ;
        RECT  38.256 25.836 38.28 25.92 ;
    END
  END t1a[119]
  PIN t1a[11]
    DIRECTION INPUT ;
    USE SIGNAL ;
    PORT
      LAYER M5 ;
        RECT  85.488 25.836 85.512 25.92 ;
    END
  END t1a[11]
  PIN t1a[120]
    DIRECTION INPUT ;
    USE SIGNAL ;
    PORT
      LAYER M5 ;
        RECT  38.352 25.836 38.376 25.92 ;
    END
  END t1a[120]
  PIN t1a[121]
    DIRECTION INPUT ;
    USE SIGNAL ;
    PORT
      LAYER M5 ;
        RECT  38.448 25.836 38.472 25.92 ;
    END
  END t1a[121]
  PIN t1a[122]
    DIRECTION INPUT ;
    USE SIGNAL ;
    PORT
      LAYER M5 ;
        RECT  38.544 25.836 38.568 25.92 ;
    END
  END t1a[122]
  PIN t1a[123]
    DIRECTION INPUT ;
    USE SIGNAL ;
    PORT
      LAYER M5 ;
        RECT  38.64 25.836 38.664 25.92 ;
    END
  END t1a[123]
  PIN t1a[124]
    DIRECTION INPUT ;
    USE SIGNAL ;
    PORT
      LAYER M5 ;
        RECT  38.736 25.836 38.76 25.92 ;
    END
  END t1a[124]
  PIN t1a[125]
    DIRECTION INPUT ;
    USE SIGNAL ;
    PORT
      LAYER M5 ;
        RECT  38.832 25.836 38.856 25.92 ;
    END
  END t1a[125]
  PIN t1a[126]
    DIRECTION INPUT ;
    USE SIGNAL ;
    PORT
      LAYER M5 ;
        RECT  38.928 25.836 38.952 25.92 ;
    END
  END t1a[126]
  PIN t1a[127]
    DIRECTION INPUT ;
    USE SIGNAL ;
    PORT
      LAYER M5 ;
        RECT  39.024 25.836 39.048 25.92 ;
    END
  END t1a[127]
  PIN t1a[128]
    DIRECTION INPUT ;
    USE SIGNAL ;
    PORT
      LAYER M5 ;
        RECT  78.288 25.836 78.312 25.92 ;
    END
  END t1a[128]
  PIN t1a[129]
    DIRECTION INPUT ;
    USE SIGNAL ;
    PORT
      LAYER M5 ;
        RECT  78.384 25.836 78.408 25.92 ;
    END
  END t1a[129]
  PIN t1a[12]
    DIRECTION INPUT ;
    USE SIGNAL ;
    PORT
      LAYER M5 ;
        RECT  85.584 25.836 85.608 25.92 ;
    END
  END t1a[12]
  PIN t1a[130]
    DIRECTION INPUT ;
    USE SIGNAL ;
    PORT
      LAYER M5 ;
        RECT  78.48 25.836 78.504 25.92 ;
    END
  END t1a[130]
  PIN t1a[131]
    DIRECTION INPUT ;
    USE SIGNAL ;
    PORT
      LAYER M5 ;
        RECT  78.576 25.836 78.6 25.92 ;
    END
  END t1a[131]
  PIN t1a[132]
    DIRECTION INPUT ;
    USE SIGNAL ;
    PORT
      LAYER M5 ;
        RECT  78.672 25.836 78.696 25.92 ;
    END
  END t1a[132]
  PIN t1a[133]
    DIRECTION INPUT ;
    USE SIGNAL ;
    PORT
      LAYER M5 ;
        RECT  78.768 25.836 78.792 25.92 ;
    END
  END t1a[133]
  PIN t1a[134]
    DIRECTION INPUT ;
    USE SIGNAL ;
    PORT
      LAYER M5 ;
        RECT  78.864 25.836 78.888 25.92 ;
    END
  END t1a[134]
  PIN t1a[135]
    DIRECTION INPUT ;
    USE SIGNAL ;
    PORT
      LAYER M5 ;
        RECT  78.96 25.836 78.984 25.92 ;
    END
  END t1a[135]
  PIN t1a[136]
    DIRECTION INPUT ;
    USE SIGNAL ;
    PORT
      LAYER M5 ;
        RECT  79.056 25.836 79.08 25.92 ;
    END
  END t1a[136]
  PIN t1a[137]
    DIRECTION INPUT ;
    USE SIGNAL ;
    PORT
      LAYER M5 ;
        RECT  79.152 25.836 79.176 25.92 ;
    END
  END t1a[137]
  PIN t1a[138]
    DIRECTION INPUT ;
    USE SIGNAL ;
    PORT
      LAYER M5 ;
        RECT  79.248 25.836 79.272 25.92 ;
    END
  END t1a[138]
  PIN t1a[139]
    DIRECTION INPUT ;
    USE SIGNAL ;
    PORT
      LAYER M5 ;
        RECT  79.344 25.836 79.368 25.92 ;
    END
  END t1a[139]
  PIN t1a[13]
    DIRECTION INPUT ;
    USE SIGNAL ;
    PORT
      LAYER M5 ;
        RECT  85.68 25.836 85.704 25.92 ;
    END
  END t1a[13]
  PIN t1a[140]
    DIRECTION INPUT ;
    USE SIGNAL ;
    PORT
      LAYER M5 ;
        RECT  79.44 25.836 79.464 25.92 ;
    END
  END t1a[140]
  PIN t1a[141]
    DIRECTION INPUT ;
    USE SIGNAL ;
    PORT
      LAYER M5 ;
        RECT  79.536 25.836 79.56 25.92 ;
    END
  END t1a[141]
  PIN t1a[142]
    DIRECTION INPUT ;
    USE SIGNAL ;
    PORT
      LAYER M5 ;
        RECT  79.632 25.836 79.656 25.92 ;
    END
  END t1a[142]
  PIN t1a[143]
    DIRECTION INPUT ;
    USE SIGNAL ;
    PORT
      LAYER M5 ;
        RECT  79.728 25.836 79.752 25.92 ;
    END
  END t1a[143]
  PIN t1a[144]
    DIRECTION INPUT ;
    USE SIGNAL ;
    PORT
      LAYER M5 ;
        RECT  79.824 25.836 79.848 25.92 ;
    END
  END t1a[144]
  PIN t1a[145]
    DIRECTION INPUT ;
    USE SIGNAL ;
    PORT
      LAYER M5 ;
        RECT  79.92 25.836 79.944 25.92 ;
    END
  END t1a[145]
  PIN t1a[146]
    DIRECTION INPUT ;
    USE SIGNAL ;
    PORT
      LAYER M5 ;
        RECT  80.016 25.836 80.04 25.92 ;
    END
  END t1a[146]
  PIN t1a[147]
    DIRECTION INPUT ;
    USE SIGNAL ;
    PORT
      LAYER M5 ;
        RECT  80.112 25.836 80.136 25.92 ;
    END
  END t1a[147]
  PIN t1a[148]
    DIRECTION INPUT ;
    USE SIGNAL ;
    PORT
      LAYER M5 ;
        RECT  80.208 25.836 80.232 25.92 ;
    END
  END t1a[148]
  PIN t1a[149]
    DIRECTION INPUT ;
    USE SIGNAL ;
    PORT
      LAYER M5 ;
        RECT  80.304 25.836 80.328 25.92 ;
    END
  END t1a[149]
  PIN t1a[14]
    DIRECTION INPUT ;
    USE SIGNAL ;
    PORT
      LAYER M5 ;
        RECT  85.776 25.836 85.8 25.92 ;
    END
  END t1a[14]
  PIN t1a[150]
    DIRECTION INPUT ;
    USE SIGNAL ;
    PORT
      LAYER M5 ;
        RECT  80.4 25.836 80.424 25.92 ;
    END
  END t1a[150]
  PIN t1a[151]
    DIRECTION INPUT ;
    USE SIGNAL ;
    PORT
      LAYER M5 ;
        RECT  80.496 25.836 80.52 25.92 ;
    END
  END t1a[151]
  PIN t1a[152]
    DIRECTION INPUT ;
    USE SIGNAL ;
    PORT
      LAYER M5 ;
        RECT  80.592 25.836 80.616 25.92 ;
    END
  END t1a[152]
  PIN t1a[153]
    DIRECTION INPUT ;
    USE SIGNAL ;
    PORT
      LAYER M5 ;
        RECT  80.688 25.836 80.712 25.92 ;
    END
  END t1a[153]
  PIN t1a[154]
    DIRECTION INPUT ;
    USE SIGNAL ;
    PORT
      LAYER M5 ;
        RECT  80.784 25.836 80.808 25.92 ;
    END
  END t1a[154]
  PIN t1a[155]
    DIRECTION INPUT ;
    USE SIGNAL ;
    PORT
      LAYER M5 ;
        RECT  80.88 25.836 80.904 25.92 ;
    END
  END t1a[155]
  PIN t1a[156]
    DIRECTION INPUT ;
    USE SIGNAL ;
    PORT
      LAYER M5 ;
        RECT  80.976 25.836 81 25.92 ;
    END
  END t1a[156]
  PIN t1a[157]
    DIRECTION INPUT ;
    USE SIGNAL ;
    PORT
      LAYER M5 ;
        RECT  81.072 25.836 81.096 25.92 ;
    END
  END t1a[157]
  PIN t1a[158]
    DIRECTION INPUT ;
    USE SIGNAL ;
    PORT
      LAYER M5 ;
        RECT  81.168 25.836 81.192 25.92 ;
    END
  END t1a[158]
  PIN t1a[159]
    DIRECTION INPUT ;
    USE SIGNAL ;
    PORT
      LAYER M5 ;
        RECT  81.264 25.836 81.288 25.92 ;
    END
  END t1a[159]
  PIN t1a[15]
    DIRECTION INPUT ;
    USE SIGNAL ;
    PORT
      LAYER M5 ;
        RECT  85.872 25.836 85.896 25.92 ;
    END
  END t1a[15]
  PIN t1a[160]
    DIRECTION INPUT ;
    USE SIGNAL ;
    PORT
      LAYER M5 ;
        RECT  90.576 25.836 90.6 25.92 ;
    END
  END t1a[160]
  PIN t1a[161]
    DIRECTION INPUT ;
    USE SIGNAL ;
    PORT
      LAYER M5 ;
        RECT  90.672 25.836 90.696 25.92 ;
    END
  END t1a[161]
  PIN t1a[162]
    DIRECTION INPUT ;
    USE SIGNAL ;
    PORT
      LAYER M5 ;
        RECT  90.768 25.836 90.792 25.92 ;
    END
  END t1a[162]
  PIN t1a[163]
    DIRECTION INPUT ;
    USE SIGNAL ;
    PORT
      LAYER M5 ;
        RECT  90.864 25.836 90.888 25.92 ;
    END
  END t1a[163]
  PIN t1a[164]
    DIRECTION INPUT ;
    USE SIGNAL ;
    PORT
      LAYER M5 ;
        RECT  90.96 25.836 90.984 25.92 ;
    END
  END t1a[164]
  PIN t1a[165]
    DIRECTION INPUT ;
    USE SIGNAL ;
    PORT
      LAYER M5 ;
        RECT  91.056 25.836 91.08 25.92 ;
    END
  END t1a[165]
  PIN t1a[166]
    DIRECTION INPUT ;
    USE SIGNAL ;
    PORT
      LAYER M5 ;
        RECT  91.152 25.836 91.176 25.92 ;
    END
  END t1a[166]
  PIN t1a[167]
    DIRECTION INPUT ;
    USE SIGNAL ;
    PORT
      LAYER M5 ;
        RECT  91.248 25.836 91.272 25.92 ;
    END
  END t1a[167]
  PIN t1a[168]
    DIRECTION INPUT ;
    USE SIGNAL ;
    PORT
      LAYER M5 ;
        RECT  91.344 25.836 91.368 25.92 ;
    END
  END t1a[168]
  PIN t1a[169]
    DIRECTION INPUT ;
    USE SIGNAL ;
    PORT
      LAYER M5 ;
        RECT  91.44 25.836 91.464 25.92 ;
    END
  END t1a[169]
  PIN t1a[16]
    DIRECTION INPUT ;
    USE SIGNAL ;
    PORT
      LAYER M5 ;
        RECT  85.968 25.836 85.992 25.92 ;
    END
  END t1a[16]
  PIN t1a[170]
    DIRECTION INPUT ;
    USE SIGNAL ;
    PORT
      LAYER M5 ;
        RECT  91.536 25.836 91.56 25.92 ;
    END
  END t1a[170]
  PIN t1a[171]
    DIRECTION INPUT ;
    USE SIGNAL ;
    PORT
      LAYER M5 ;
        RECT  91.632 25.836 91.656 25.92 ;
    END
  END t1a[171]
  PIN t1a[172]
    DIRECTION INPUT ;
    USE SIGNAL ;
    PORT
      LAYER M5 ;
        RECT  91.728 25.836 91.752 25.92 ;
    END
  END t1a[172]
  PIN t1a[173]
    DIRECTION INPUT ;
    USE SIGNAL ;
    PORT
      LAYER M5 ;
        RECT  91.824 25.836 91.848 25.92 ;
    END
  END t1a[173]
  PIN t1a[174]
    DIRECTION INPUT ;
    USE SIGNAL ;
    PORT
      LAYER M5 ;
        RECT  91.92 25.836 91.944 25.92 ;
    END
  END t1a[174]
  PIN t1a[175]
    DIRECTION INPUT ;
    USE SIGNAL ;
    PORT
      LAYER M5 ;
        RECT  92.016 25.836 92.04 25.92 ;
    END
  END t1a[175]
  PIN t1a[176]
    DIRECTION INPUT ;
    USE SIGNAL ;
    PORT
      LAYER M5 ;
        RECT  92.112 25.836 92.136 25.92 ;
    END
  END t1a[176]
  PIN t1a[177]
    DIRECTION INPUT ;
    USE SIGNAL ;
    PORT
      LAYER M5 ;
        RECT  92.208 25.836 92.232 25.92 ;
    END
  END t1a[177]
  PIN t1a[178]
    DIRECTION INPUT ;
    USE SIGNAL ;
    PORT
      LAYER M5 ;
        RECT  92.304 25.836 92.328 25.92 ;
    END
  END t1a[178]
  PIN t1a[179]
    DIRECTION INPUT ;
    USE SIGNAL ;
    PORT
      LAYER M5 ;
        RECT  92.4 25.836 92.424 25.92 ;
    END
  END t1a[179]
  PIN t1a[17]
    DIRECTION INPUT ;
    USE SIGNAL ;
    PORT
      LAYER M5 ;
        RECT  86.064 25.836 86.088 25.92 ;
    END
  END t1a[17]
  PIN t1a[180]
    DIRECTION INPUT ;
    USE SIGNAL ;
    PORT
      LAYER M5 ;
        RECT  92.496 25.836 92.52 25.92 ;
    END
  END t1a[180]
  PIN t1a[181]
    DIRECTION INPUT ;
    USE SIGNAL ;
    PORT
      LAYER M5 ;
        RECT  92.592 25.836 92.616 25.92 ;
    END
  END t1a[181]
  PIN t1a[182]
    DIRECTION INPUT ;
    USE SIGNAL ;
    PORT
      LAYER M5 ;
        RECT  92.688 25.836 92.712 25.92 ;
    END
  END t1a[182]
  PIN t1a[183]
    DIRECTION INPUT ;
    USE SIGNAL ;
    PORT
      LAYER M5 ;
        RECT  92.784 25.836 92.808 25.92 ;
    END
  END t1a[183]
  PIN t1a[184]
    DIRECTION INPUT ;
    USE SIGNAL ;
    PORT
      LAYER M5 ;
        RECT  92.88 25.836 92.904 25.92 ;
    END
  END t1a[184]
  PIN t1a[185]
    DIRECTION INPUT ;
    USE SIGNAL ;
    PORT
      LAYER M5 ;
        RECT  92.976 25.836 93 25.92 ;
    END
  END t1a[185]
  PIN t1a[186]
    DIRECTION INPUT ;
    USE SIGNAL ;
    PORT
      LAYER M5 ;
        RECT  93.072 25.836 93.096 25.92 ;
    END
  END t1a[186]
  PIN t1a[187]
    DIRECTION INPUT ;
    USE SIGNAL ;
    PORT
      LAYER M5 ;
        RECT  93.168 25.836 93.192 25.92 ;
    END
  END t1a[187]
  PIN t1a[188]
    DIRECTION INPUT ;
    USE SIGNAL ;
    PORT
      LAYER M5 ;
        RECT  93.264 25.836 93.288 25.92 ;
    END
  END t1a[188]
  PIN t1a[189]
    DIRECTION INPUT ;
    USE SIGNAL ;
    PORT
      LAYER M5 ;
        RECT  93.36 25.836 93.384 25.92 ;
    END
  END t1a[189]
  PIN t1a[18]
    DIRECTION INPUT ;
    USE SIGNAL ;
    PORT
      LAYER M5 ;
        RECT  86.16 25.836 86.184 25.92 ;
    END
  END t1a[18]
  PIN t1a[190]
    DIRECTION INPUT ;
    USE SIGNAL ;
    PORT
      LAYER M5 ;
        RECT  93.456 25.836 93.48 25.92 ;
    END
  END t1a[190]
  PIN t1a[191]
    DIRECTION INPUT ;
    USE SIGNAL ;
    PORT
      LAYER M5 ;
        RECT  93.552 25.836 93.576 25.92 ;
    END
  END t1a[191]
  PIN t1a[192]
    DIRECTION INPUT ;
    USE SIGNAL ;
    PORT
      LAYER M5 ;
        RECT  32.976 25.836 33 25.92 ;
    END
  END t1a[192]
  PIN t1a[193]
    DIRECTION INPUT ;
    USE SIGNAL ;
    PORT
      LAYER M5 ;
        RECT  33.072 25.836 33.096 25.92 ;
    END
  END t1a[193]
  PIN t1a[194]
    DIRECTION INPUT ;
    USE SIGNAL ;
    PORT
      LAYER M5 ;
        RECT  33.168 25.836 33.192 25.92 ;
    END
  END t1a[194]
  PIN t1a[195]
    DIRECTION INPUT ;
    USE SIGNAL ;
    PORT
      LAYER M5 ;
        RECT  33.264 25.836 33.288 25.92 ;
    END
  END t1a[195]
  PIN t1a[196]
    DIRECTION INPUT ;
    USE SIGNAL ;
    PORT
      LAYER M5 ;
        RECT  33.36 25.836 33.384 25.92 ;
    END
  END t1a[196]
  PIN t1a[197]
    DIRECTION INPUT ;
    USE SIGNAL ;
    PORT
      LAYER M5 ;
        RECT  33.456 25.836 33.48 25.92 ;
    END
  END t1a[197]
  PIN t1a[198]
    DIRECTION INPUT ;
    USE SIGNAL ;
    PORT
      LAYER M5 ;
        RECT  33.552 25.836 33.576 25.92 ;
    END
  END t1a[198]
  PIN t1a[199]
    DIRECTION INPUT ;
    USE SIGNAL ;
    PORT
      LAYER M5 ;
        RECT  33.648 25.836 33.672 25.92 ;
    END
  END t1a[199]
  PIN t1a[19]
    DIRECTION INPUT ;
    USE SIGNAL ;
    PORT
      LAYER M5 ;
        RECT  86.256 25.836 86.28 25.92 ;
    END
  END t1a[19]
  PIN t1a[1]
    DIRECTION INPUT ;
    USE SIGNAL ;
    PORT
      LAYER M5 ;
        RECT  84.528 25.836 84.552 25.92 ;
    END
  END t1a[1]
  PIN t1a[200]
    DIRECTION INPUT ;
    USE SIGNAL ;
    PORT
      LAYER M5 ;
        RECT  33.744 25.836 33.768 25.92 ;
    END
  END t1a[200]
  PIN t1a[201]
    DIRECTION INPUT ;
    USE SIGNAL ;
    PORT
      LAYER M5 ;
        RECT  33.84 25.836 33.864 25.92 ;
    END
  END t1a[201]
  PIN t1a[202]
    DIRECTION INPUT ;
    USE SIGNAL ;
    PORT
      LAYER M5 ;
        RECT  33.936 25.836 33.96 25.92 ;
    END
  END t1a[202]
  PIN t1a[203]
    DIRECTION INPUT ;
    USE SIGNAL ;
    PORT
      LAYER M5 ;
        RECT  34.032 25.836 34.056 25.92 ;
    END
  END t1a[203]
  PIN t1a[204]
    DIRECTION INPUT ;
    USE SIGNAL ;
    PORT
      LAYER M5 ;
        RECT  34.128 25.836 34.152 25.92 ;
    END
  END t1a[204]
  PIN t1a[205]
    DIRECTION INPUT ;
    USE SIGNAL ;
    PORT
      LAYER M5 ;
        RECT  34.224 25.836 34.248 25.92 ;
    END
  END t1a[205]
  PIN t1a[206]
    DIRECTION INPUT ;
    USE SIGNAL ;
    PORT
      LAYER M5 ;
        RECT  34.32 25.836 34.344 25.92 ;
    END
  END t1a[206]
  PIN t1a[207]
    DIRECTION INPUT ;
    USE SIGNAL ;
    PORT
      LAYER M5 ;
        RECT  34.416 25.836 34.44 25.92 ;
    END
  END t1a[207]
  PIN t1a[208]
    DIRECTION INPUT ;
    USE SIGNAL ;
    PORT
      LAYER M5 ;
        RECT  34.512 25.836 34.536 25.92 ;
    END
  END t1a[208]
  PIN t1a[209]
    DIRECTION INPUT ;
    USE SIGNAL ;
    PORT
      LAYER M5 ;
        RECT  34.608 25.836 34.632 25.92 ;
    END
  END t1a[209]
  PIN t1a[20]
    DIRECTION INPUT ;
    USE SIGNAL ;
    PORT
      LAYER M5 ;
        RECT  86.352 25.836 86.376 25.92 ;
    END
  END t1a[20]
  PIN t1a[210]
    DIRECTION INPUT ;
    USE SIGNAL ;
    PORT
      LAYER M5 ;
        RECT  34.704 25.836 34.728 25.92 ;
    END
  END t1a[210]
  PIN t1a[211]
    DIRECTION INPUT ;
    USE SIGNAL ;
    PORT
      LAYER M5 ;
        RECT  34.8 25.836 34.824 25.92 ;
    END
  END t1a[211]
  PIN t1a[212]
    DIRECTION INPUT ;
    USE SIGNAL ;
    PORT
      LAYER M5 ;
        RECT  34.896 25.836 34.92 25.92 ;
    END
  END t1a[212]
  PIN t1a[213]
    DIRECTION INPUT ;
    USE SIGNAL ;
    PORT
      LAYER M5 ;
        RECT  34.992 25.836 35.016 25.92 ;
    END
  END t1a[213]
  PIN t1a[214]
    DIRECTION INPUT ;
    USE SIGNAL ;
    PORT
      LAYER M5 ;
        RECT  35.088 25.836 35.112 25.92 ;
    END
  END t1a[214]
  PIN t1a[215]
    DIRECTION INPUT ;
    USE SIGNAL ;
    PORT
      LAYER M5 ;
        RECT  35.184 25.836 35.208 25.92 ;
    END
  END t1a[215]
  PIN t1a[216]
    DIRECTION INPUT ;
    USE SIGNAL ;
    PORT
      LAYER M5 ;
        RECT  35.28 25.836 35.304 25.92 ;
    END
  END t1a[216]
  PIN t1a[217]
    DIRECTION INPUT ;
    USE SIGNAL ;
    PORT
      LAYER M5 ;
        RECT  35.376 25.836 35.4 25.92 ;
    END
  END t1a[217]
  PIN t1a[218]
    DIRECTION INPUT ;
    USE SIGNAL ;
    PORT
      LAYER M5 ;
        RECT  35.472 25.836 35.496 25.92 ;
    END
  END t1a[218]
  PIN t1a[219]
    DIRECTION INPUT ;
    USE SIGNAL ;
    PORT
      LAYER M5 ;
        RECT  35.568 25.836 35.592 25.92 ;
    END
  END t1a[219]
  PIN t1a[21]
    DIRECTION INPUT ;
    USE SIGNAL ;
    PORT
      LAYER M5 ;
        RECT  86.448 25.836 86.472 25.92 ;
    END
  END t1a[21]
  PIN t1a[220]
    DIRECTION INPUT ;
    USE SIGNAL ;
    PORT
      LAYER M5 ;
        RECT  35.664 25.836 35.688 25.92 ;
    END
  END t1a[220]
  PIN t1a[221]
    DIRECTION INPUT ;
    USE SIGNAL ;
    PORT
      LAYER M5 ;
        RECT  35.76 25.836 35.784 25.92 ;
    END
  END t1a[221]
  PIN t1a[222]
    DIRECTION INPUT ;
    USE SIGNAL ;
    PORT
      LAYER M5 ;
        RECT  35.856 25.836 35.88 25.92 ;
    END
  END t1a[222]
  PIN t1a[223]
    DIRECTION INPUT ;
    USE SIGNAL ;
    PORT
      LAYER M5 ;
        RECT  35.952 25.836 35.976 25.92 ;
    END
  END t1a[223]
  PIN t1a[224]
    DIRECTION INPUT ;
    USE SIGNAL ;
    PORT
      LAYER M5 ;
        RECT  93.648 25.836 93.672 25.92 ;
    END
  END t1a[224]
  PIN t1a[225]
    DIRECTION INPUT ;
    USE SIGNAL ;
    PORT
      LAYER M5 ;
        RECT  93.744 25.836 93.768 25.92 ;
    END
  END t1a[225]
  PIN t1a[226]
    DIRECTION INPUT ;
    USE SIGNAL ;
    PORT
      LAYER M5 ;
        RECT  93.84 25.836 93.864 25.92 ;
    END
  END t1a[226]
  PIN t1a[227]
    DIRECTION INPUT ;
    USE SIGNAL ;
    PORT
      LAYER M5 ;
        RECT  93.936 25.836 93.96 25.92 ;
    END
  END t1a[227]
  PIN t1a[228]
    DIRECTION INPUT ;
    USE SIGNAL ;
    PORT
      LAYER M5 ;
        RECT  94.032 25.836 94.056 25.92 ;
    END
  END t1a[228]
  PIN t1a[229]
    DIRECTION INPUT ;
    USE SIGNAL ;
    PORT
      LAYER M5 ;
        RECT  94.128 25.836 94.152 25.92 ;
    END
  END t1a[229]
  PIN t1a[22]
    DIRECTION INPUT ;
    USE SIGNAL ;
    PORT
      LAYER M5 ;
        RECT  86.544 25.836 86.568 25.92 ;
    END
  END t1a[22]
  PIN t1a[230]
    DIRECTION INPUT ;
    USE SIGNAL ;
    PORT
      LAYER M5 ;
        RECT  94.224 25.836 94.248 25.92 ;
    END
  END t1a[230]
  PIN t1a[231]
    DIRECTION INPUT ;
    USE SIGNAL ;
    PORT
      LAYER M5 ;
        RECT  94.32 25.836 94.344 25.92 ;
    END
  END t1a[231]
  PIN t1a[232]
    DIRECTION INPUT ;
    USE SIGNAL ;
    PORT
      LAYER M5 ;
        RECT  94.416 25.836 94.44 25.92 ;
    END
  END t1a[232]
  PIN t1a[233]
    DIRECTION INPUT ;
    USE SIGNAL ;
    PORT
      LAYER M5 ;
        RECT  94.512 25.836 94.536 25.92 ;
    END
  END t1a[233]
  PIN t1a[234]
    DIRECTION INPUT ;
    USE SIGNAL ;
    PORT
      LAYER M5 ;
        RECT  94.608 25.836 94.632 25.92 ;
    END
  END t1a[234]
  PIN t1a[235]
    DIRECTION INPUT ;
    USE SIGNAL ;
    PORT
      LAYER M5 ;
        RECT  94.704 25.836 94.728 25.92 ;
    END
  END t1a[235]
  PIN t1a[236]
    DIRECTION INPUT ;
    USE SIGNAL ;
    PORT
      LAYER M5 ;
        RECT  94.8 25.836 94.824 25.92 ;
    END
  END t1a[236]
  PIN t1a[237]
    DIRECTION INPUT ;
    USE SIGNAL ;
    PORT
      LAYER M5 ;
        RECT  94.896 25.836 94.92 25.92 ;
    END
  END t1a[237]
  PIN t1a[238]
    DIRECTION INPUT ;
    USE SIGNAL ;
    PORT
      LAYER M5 ;
        RECT  94.992 25.836 95.016 25.92 ;
    END
  END t1a[238]
  PIN t1a[239]
    DIRECTION INPUT ;
    USE SIGNAL ;
    PORT
      LAYER M5 ;
        RECT  95.088 25.836 95.112 25.92 ;
    END
  END t1a[239]
  PIN t1a[23]
    DIRECTION INPUT ;
    USE SIGNAL ;
    PORT
      LAYER M5 ;
        RECT  86.64 25.836 86.664 25.92 ;
    END
  END t1a[23]
  PIN t1a[240]
    DIRECTION INPUT ;
    USE SIGNAL ;
    PORT
      LAYER M5 ;
        RECT  95.184 25.836 95.208 25.92 ;
    END
  END t1a[240]
  PIN t1a[241]
    DIRECTION INPUT ;
    USE SIGNAL ;
    PORT
      LAYER M5 ;
        RECT  95.28 25.836 95.304 25.92 ;
    END
  END t1a[241]
  PIN t1a[242]
    DIRECTION INPUT ;
    USE SIGNAL ;
    PORT
      LAYER M5 ;
        RECT  95.376 25.836 95.4 25.92 ;
    END
  END t1a[242]
  PIN t1a[243]
    DIRECTION INPUT ;
    USE SIGNAL ;
    PORT
      LAYER M5 ;
        RECT  95.472 25.836 95.496 25.92 ;
    END
  END t1a[243]
  PIN t1a[244]
    DIRECTION INPUT ;
    USE SIGNAL ;
    PORT
      LAYER M5 ;
        RECT  95.568 25.836 95.592 25.92 ;
    END
  END t1a[244]
  PIN t1a[245]
    DIRECTION INPUT ;
    USE SIGNAL ;
    PORT
      LAYER M5 ;
        RECT  95.664 25.836 95.688 25.92 ;
    END
  END t1a[245]
  PIN t1a[246]
    DIRECTION INPUT ;
    USE SIGNAL ;
    PORT
      LAYER M5 ;
        RECT  95.76 25.836 95.784 25.92 ;
    END
  END t1a[246]
  PIN t1a[247]
    DIRECTION INPUT ;
    USE SIGNAL ;
    PORT
      LAYER M5 ;
        RECT  95.856 25.836 95.88 25.92 ;
    END
  END t1a[247]
  PIN t1a[248]
    DIRECTION INPUT ;
    USE SIGNAL ;
    PORT
      LAYER M5 ;
        RECT  95.952 25.836 95.976 25.92 ;
    END
  END t1a[248]
  PIN t1a[249]
    DIRECTION INPUT ;
    USE SIGNAL ;
    PORT
      LAYER M5 ;
        RECT  96.048 25.836 96.072 25.92 ;
    END
  END t1a[249]
  PIN t1a[24]
    DIRECTION INPUT ;
    USE SIGNAL ;
    PORT
      LAYER M5 ;
        RECT  86.736 25.836 86.76 25.92 ;
    END
  END t1a[24]
  PIN t1a[250]
    DIRECTION INPUT ;
    USE SIGNAL ;
    PORT
      LAYER M5 ;
        RECT  96.144 25.836 96.168 25.92 ;
    END
  END t1a[250]
  PIN t1a[251]
    DIRECTION INPUT ;
    USE SIGNAL ;
    PORT
      LAYER M5 ;
        RECT  96.24 25.836 96.264 25.92 ;
    END
  END t1a[251]
  PIN t1a[252]
    DIRECTION INPUT ;
    USE SIGNAL ;
    PORT
      LAYER M5 ;
        RECT  96.336 25.836 96.36 25.92 ;
    END
  END t1a[252]
  PIN t1a[253]
    DIRECTION INPUT ;
    USE SIGNAL ;
    PORT
      LAYER M5 ;
        RECT  96.432 25.836 96.456 25.92 ;
    END
  END t1a[253]
  PIN t1a[254]
    DIRECTION INPUT ;
    USE SIGNAL ;
    PORT
      LAYER M5 ;
        RECT  96.528 25.836 96.552 25.92 ;
    END
  END t1a[254]
  PIN t1a[255]
    DIRECTION INPUT ;
    USE SIGNAL ;
    PORT
      LAYER M5 ;
        RECT  96.624 25.836 96.648 25.92 ;
    END
  END t1a[255]
  PIN t1a[256]
    DIRECTION INPUT ;
    USE SIGNAL ;
    PORT
      LAYER M5 ;
        RECT  106.704 25.836 106.728 25.92 ;
    END
  END t1a[256]
  PIN t1a[257]
    DIRECTION INPUT ;
    USE SIGNAL ;
    PORT
      LAYER M5 ;
        RECT  106.8 25.836 106.824 25.92 ;
    END
  END t1a[257]
  PIN t1a[258]
    DIRECTION INPUT ;
    USE SIGNAL ;
    PORT
      LAYER M5 ;
        RECT  106.896 25.836 106.92 25.92 ;
    END
  END t1a[258]
  PIN t1a[259]
    DIRECTION INPUT ;
    USE SIGNAL ;
    PORT
      LAYER M5 ;
        RECT  106.992 25.836 107.016 25.92 ;
    END
  END t1a[259]
  PIN t1a[25]
    DIRECTION INPUT ;
    USE SIGNAL ;
    PORT
      LAYER M5 ;
        RECT  86.832 25.836 86.856 25.92 ;
    END
  END t1a[25]
  PIN t1a[260]
    DIRECTION INPUT ;
    USE SIGNAL ;
    PORT
      LAYER M5 ;
        RECT  107.088 25.836 107.112 25.92 ;
    END
  END t1a[260]
  PIN t1a[261]
    DIRECTION INPUT ;
    USE SIGNAL ;
    PORT
      LAYER M5 ;
        RECT  107.184 25.836 107.208 25.92 ;
    END
  END t1a[261]
  PIN t1a[262]
    DIRECTION INPUT ;
    USE SIGNAL ;
    PORT
      LAYER M5 ;
        RECT  107.28 25.836 107.304 25.92 ;
    END
  END t1a[262]
  PIN t1a[263]
    DIRECTION INPUT ;
    USE SIGNAL ;
    PORT
      LAYER M5 ;
        RECT  107.376 25.836 107.4 25.92 ;
    END
  END t1a[263]
  PIN t1a[264]
    DIRECTION INPUT ;
    USE SIGNAL ;
    PORT
      LAYER M5 ;
        RECT  107.472 25.836 107.496 25.92 ;
    END
  END t1a[264]
  PIN t1a[265]
    DIRECTION INPUT ;
    USE SIGNAL ;
    PORT
      LAYER M5 ;
        RECT  107.568 25.836 107.592 25.92 ;
    END
  END t1a[265]
  PIN t1a[266]
    DIRECTION INPUT ;
    USE SIGNAL ;
    PORT
      LAYER M5 ;
        RECT  107.664 25.836 107.688 25.92 ;
    END
  END t1a[266]
  PIN t1a[267]
    DIRECTION INPUT ;
    USE SIGNAL ;
    PORT
      LAYER M5 ;
        RECT  107.76 25.836 107.784 25.92 ;
    END
  END t1a[267]
  PIN t1a[268]
    DIRECTION INPUT ;
    USE SIGNAL ;
    PORT
      LAYER M5 ;
        RECT  107.856 25.836 107.88 25.92 ;
    END
  END t1a[268]
  PIN t1a[269]
    DIRECTION INPUT ;
    USE SIGNAL ;
    PORT
      LAYER M5 ;
        RECT  107.952 25.836 107.976 25.92 ;
    END
  END t1a[269]
  PIN t1a[26]
    DIRECTION INPUT ;
    USE SIGNAL ;
    PORT
      LAYER M5 ;
        RECT  86.928 25.836 86.952 25.92 ;
    END
  END t1a[26]
  PIN t1a[270]
    DIRECTION INPUT ;
    USE SIGNAL ;
    PORT
      LAYER M5 ;
        RECT  108.048 25.836 108.072 25.92 ;
    END
  END t1a[270]
  PIN t1a[271]
    DIRECTION INPUT ;
    USE SIGNAL ;
    PORT
      LAYER M5 ;
        RECT  108.144 25.836 108.168 25.92 ;
    END
  END t1a[271]
  PIN t1a[272]
    DIRECTION INPUT ;
    USE SIGNAL ;
    PORT
      LAYER M5 ;
        RECT  108.24 25.836 108.264 25.92 ;
    END
  END t1a[272]
  PIN t1a[273]
    DIRECTION INPUT ;
    USE SIGNAL ;
    PORT
      LAYER M5 ;
        RECT  108.336 25.836 108.36 25.92 ;
    END
  END t1a[273]
  PIN t1a[274]
    DIRECTION INPUT ;
    USE SIGNAL ;
    PORT
      LAYER M5 ;
        RECT  108.432 25.836 108.456 25.92 ;
    END
  END t1a[274]
  PIN t1a[275]
    DIRECTION INPUT ;
    USE SIGNAL ;
    PORT
      LAYER M5 ;
        RECT  108.528 25.836 108.552 25.92 ;
    END
  END t1a[275]
  PIN t1a[276]
    DIRECTION INPUT ;
    USE SIGNAL ;
    PORT
      LAYER M5 ;
        RECT  108.624 25.836 108.648 25.92 ;
    END
  END t1a[276]
  PIN t1a[277]
    DIRECTION INPUT ;
    USE SIGNAL ;
    PORT
      LAYER M5 ;
        RECT  108.72 25.836 108.744 25.92 ;
    END
  END t1a[277]
  PIN t1a[278]
    DIRECTION INPUT ;
    USE SIGNAL ;
    PORT
      LAYER M5 ;
        RECT  108.816 25.836 108.84 25.92 ;
    END
  END t1a[278]
  PIN t1a[279]
    DIRECTION INPUT ;
    USE SIGNAL ;
    PORT
      LAYER M5 ;
        RECT  108.912 25.836 108.936 25.92 ;
    END
  END t1a[279]
  PIN t1a[27]
    DIRECTION INPUT ;
    USE SIGNAL ;
    PORT
      LAYER M5 ;
        RECT  87.024 25.836 87.048 25.92 ;
    END
  END t1a[27]
  PIN t1a[280]
    DIRECTION INPUT ;
    USE SIGNAL ;
    PORT
      LAYER M5 ;
        RECT  109.008 25.836 109.032 25.92 ;
    END
  END t1a[280]
  PIN t1a[281]
    DIRECTION INPUT ;
    USE SIGNAL ;
    PORT
      LAYER M5 ;
        RECT  109.104 25.836 109.128 25.92 ;
    END
  END t1a[281]
  PIN t1a[282]
    DIRECTION INPUT ;
    USE SIGNAL ;
    PORT
      LAYER M5 ;
        RECT  109.2 25.836 109.224 25.92 ;
    END
  END t1a[282]
  PIN t1a[283]
    DIRECTION INPUT ;
    USE SIGNAL ;
    PORT
      LAYER M5 ;
        RECT  109.296 25.836 109.32 25.92 ;
    END
  END t1a[283]
  PIN t1a[284]
    DIRECTION INPUT ;
    USE SIGNAL ;
    PORT
      LAYER M5 ;
        RECT  109.392 25.836 109.416 25.92 ;
    END
  END t1a[284]
  PIN t1a[285]
    DIRECTION INPUT ;
    USE SIGNAL ;
    PORT
      LAYER M5 ;
        RECT  109.488 25.836 109.512 25.92 ;
    END
  END t1a[285]
  PIN t1a[286]
    DIRECTION INPUT ;
    USE SIGNAL ;
    PORT
      LAYER M5 ;
        RECT  109.584 25.836 109.608 25.92 ;
    END
  END t1a[286]
  PIN t1a[287]
    DIRECTION INPUT ;
    USE SIGNAL ;
    PORT
      LAYER M5 ;
        RECT  109.68 25.836 109.704 25.92 ;
    END
  END t1a[287]
  PIN t1a[288]
    DIRECTION INPUT ;
    USE SIGNAL ;
    PORT
      LAYER M5 ;
        RECT  97.488 25.836 97.512 25.92 ;
    END
  END t1a[288]
  PIN t1a[289]
    DIRECTION INPUT ;
    USE SIGNAL ;
    PORT
      LAYER M5 ;
        RECT  97.584 25.836 97.608 25.92 ;
    END
  END t1a[289]
  PIN t1a[28]
    DIRECTION INPUT ;
    USE SIGNAL ;
    PORT
      LAYER M5 ;
        RECT  87.12 25.836 87.144 25.92 ;
    END
  END t1a[28]
  PIN t1a[290]
    DIRECTION INPUT ;
    USE SIGNAL ;
    PORT
      LAYER M5 ;
        RECT  97.68 25.836 97.704 25.92 ;
    END
  END t1a[290]
  PIN t1a[291]
    DIRECTION INPUT ;
    USE SIGNAL ;
    PORT
      LAYER M5 ;
        RECT  97.776 25.836 97.8 25.92 ;
    END
  END t1a[291]
  PIN t1a[292]
    DIRECTION INPUT ;
    USE SIGNAL ;
    PORT
      LAYER M5 ;
        RECT  97.872 25.836 97.896 25.92 ;
    END
  END t1a[292]
  PIN t1a[293]
    DIRECTION INPUT ;
    USE SIGNAL ;
    PORT
      LAYER M5 ;
        RECT  97.968 25.836 97.992 25.92 ;
    END
  END t1a[293]
  PIN t1a[294]
    DIRECTION INPUT ;
    USE SIGNAL ;
    PORT
      LAYER M5 ;
        RECT  98.064 25.836 98.088 25.92 ;
    END
  END t1a[294]
  PIN t1a[295]
    DIRECTION INPUT ;
    USE SIGNAL ;
    PORT
      LAYER M5 ;
        RECT  98.16 25.836 98.184 25.92 ;
    END
  END t1a[295]
  PIN t1a[296]
    DIRECTION INPUT ;
    USE SIGNAL ;
    PORT
      LAYER M5 ;
        RECT  98.256 25.836 98.28 25.92 ;
    END
  END t1a[296]
  PIN t1a[297]
    DIRECTION INPUT ;
    USE SIGNAL ;
    PORT
      LAYER M5 ;
        RECT  98.352 25.836 98.376 25.92 ;
    END
  END t1a[297]
  PIN t1a[298]
    DIRECTION INPUT ;
    USE SIGNAL ;
    PORT
      LAYER M5 ;
        RECT  98.448 25.836 98.472 25.92 ;
    END
  END t1a[298]
  PIN t1a[299]
    DIRECTION INPUT ;
    USE SIGNAL ;
    PORT
      LAYER M5 ;
        RECT  98.544 25.836 98.568 25.92 ;
    END
  END t1a[299]
  PIN t1a[29]
    DIRECTION INPUT ;
    USE SIGNAL ;
    PORT
      LAYER M5 ;
        RECT  87.216 25.836 87.24 25.92 ;
    END
  END t1a[29]
  PIN t1a[2]
    DIRECTION INPUT ;
    USE SIGNAL ;
    PORT
      LAYER M5 ;
        RECT  84.624 25.836 84.648 25.92 ;
    END
  END t1a[2]
  PIN t1a[300]
    DIRECTION INPUT ;
    USE SIGNAL ;
    PORT
      LAYER M5 ;
        RECT  98.64 25.836 98.664 25.92 ;
    END
  END t1a[300]
  PIN t1a[301]
    DIRECTION INPUT ;
    USE SIGNAL ;
    PORT
      LAYER M5 ;
        RECT  98.736 25.836 98.76 25.92 ;
    END
  END t1a[301]
  PIN t1a[302]
    DIRECTION INPUT ;
    USE SIGNAL ;
    PORT
      LAYER M5 ;
        RECT  98.832 25.836 98.856 25.92 ;
    END
  END t1a[302]
  PIN t1a[303]
    DIRECTION INPUT ;
    USE SIGNAL ;
    PORT
      LAYER M5 ;
        RECT  98.928 25.836 98.952 25.92 ;
    END
  END t1a[303]
  PIN t1a[304]
    DIRECTION INPUT ;
    USE SIGNAL ;
    PORT
      LAYER M5 ;
        RECT  99.024 25.836 99.048 25.92 ;
    END
  END t1a[304]
  PIN t1a[305]
    DIRECTION INPUT ;
    USE SIGNAL ;
    PORT
      LAYER M5 ;
        RECT  99.12 25.836 99.144 25.92 ;
    END
  END t1a[305]
  PIN t1a[306]
    DIRECTION INPUT ;
    USE SIGNAL ;
    PORT
      LAYER M5 ;
        RECT  99.216 25.836 99.24 25.92 ;
    END
  END t1a[306]
  PIN t1a[307]
    DIRECTION INPUT ;
    USE SIGNAL ;
    PORT
      LAYER M5 ;
        RECT  99.312 25.836 99.336 25.92 ;
    END
  END t1a[307]
  PIN t1a[308]
    DIRECTION INPUT ;
    USE SIGNAL ;
    PORT
      LAYER M5 ;
        RECT  99.408 25.836 99.432 25.92 ;
    END
  END t1a[308]
  PIN t1a[309]
    DIRECTION INPUT ;
    USE SIGNAL ;
    PORT
      LAYER M5 ;
        RECT  99.504 25.836 99.528 25.92 ;
    END
  END t1a[309]
  PIN t1a[30]
    DIRECTION INPUT ;
    USE SIGNAL ;
    PORT
      LAYER M5 ;
        RECT  87.312 25.836 87.336 25.92 ;
    END
  END t1a[30]
  PIN t1a[310]
    DIRECTION INPUT ;
    USE SIGNAL ;
    PORT
      LAYER M5 ;
        RECT  99.6 25.836 99.624 25.92 ;
    END
  END t1a[310]
  PIN t1a[311]
    DIRECTION INPUT ;
    USE SIGNAL ;
    PORT
      LAYER M5 ;
        RECT  99.696 25.836 99.72 25.92 ;
    END
  END t1a[311]
  PIN t1a[312]
    DIRECTION INPUT ;
    USE SIGNAL ;
    PORT
      LAYER M5 ;
        RECT  99.792 25.836 99.816 25.92 ;
    END
  END t1a[312]
  PIN t1a[313]
    DIRECTION INPUT ;
    USE SIGNAL ;
    PORT
      LAYER M5 ;
        RECT  99.888 25.836 99.912 25.92 ;
    END
  END t1a[313]
  PIN t1a[314]
    DIRECTION INPUT ;
    USE SIGNAL ;
    PORT
      LAYER M5 ;
        RECT  99.984 25.836 100.008 25.92 ;
    END
  END t1a[314]
  PIN t1a[315]
    DIRECTION INPUT ;
    USE SIGNAL ;
    PORT
      LAYER M5 ;
        RECT  100.08 25.836 100.104 25.92 ;
    END
  END t1a[315]
  PIN t1a[316]
    DIRECTION INPUT ;
    USE SIGNAL ;
    PORT
      LAYER M5 ;
        RECT  100.176 25.836 100.2 25.92 ;
    END
  END t1a[316]
  PIN t1a[317]
    DIRECTION INPUT ;
    USE SIGNAL ;
    PORT
      LAYER M5 ;
        RECT  100.272 25.836 100.296 25.92 ;
    END
  END t1a[317]
  PIN t1a[318]
    DIRECTION INPUT ;
    USE SIGNAL ;
    PORT
      LAYER M5 ;
        RECT  100.368 25.836 100.392 25.92 ;
    END
  END t1a[318]
  PIN t1a[319]
    DIRECTION INPUT ;
    USE SIGNAL ;
    PORT
      LAYER M5 ;
        RECT  100.464 25.836 100.488 25.92 ;
    END
  END t1a[319]
  PIN t1a[31]
    DIRECTION INPUT ;
    USE SIGNAL ;
    PORT
      LAYER M5 ;
        RECT  87.408 25.836 87.432 25.92 ;
    END
  END t1a[31]
  PIN t1a[320]
    DIRECTION INPUT ;
    USE SIGNAL ;
    PORT
      LAYER M5 ;
        RECT  16.848 25.836 16.872 25.92 ;
    END
  END t1a[320]
  PIN t1a[321]
    DIRECTION INPUT ;
    USE SIGNAL ;
    PORT
      LAYER M5 ;
        RECT  16.944 25.836 16.968 25.92 ;
    END
  END t1a[321]
  PIN t1a[322]
    DIRECTION INPUT ;
    USE SIGNAL ;
    PORT
      LAYER M5 ;
        RECT  17.04 25.836 17.064 25.92 ;
    END
  END t1a[322]
  PIN t1a[323]
    DIRECTION INPUT ;
    USE SIGNAL ;
    PORT
      LAYER M5 ;
        RECT  17.136 25.836 17.16 25.92 ;
    END
  END t1a[323]
  PIN t1a[324]
    DIRECTION INPUT ;
    USE SIGNAL ;
    PORT
      LAYER M5 ;
        RECT  17.232 25.836 17.256 25.92 ;
    END
  END t1a[324]
  PIN t1a[325]
    DIRECTION INPUT ;
    USE SIGNAL ;
    PORT
      LAYER M5 ;
        RECT  17.328 25.836 17.352 25.92 ;
    END
  END t1a[325]
  PIN t1a[326]
    DIRECTION INPUT ;
    USE SIGNAL ;
    PORT
      LAYER M5 ;
        RECT  17.424 25.836 17.448 25.92 ;
    END
  END t1a[326]
  PIN t1a[327]
    DIRECTION INPUT ;
    USE SIGNAL ;
    PORT
      LAYER M5 ;
        RECT  17.52 25.836 17.544 25.92 ;
    END
  END t1a[327]
  PIN t1a[328]
    DIRECTION INPUT ;
    USE SIGNAL ;
    PORT
      LAYER M5 ;
        RECT  17.616 25.836 17.64 25.92 ;
    END
  END t1a[328]
  PIN t1a[329]
    DIRECTION INPUT ;
    USE SIGNAL ;
    PORT
      LAYER M5 ;
        RECT  17.712 25.836 17.736 25.92 ;
    END
  END t1a[329]
  PIN t1a[32]
    DIRECTION INPUT ;
    USE SIGNAL ;
    PORT
      LAYER M5 ;
        RECT  20.688 25.836 20.712 25.92 ;
    END
  END t1a[32]
  PIN t1a[330]
    DIRECTION INPUT ;
    USE SIGNAL ;
    PORT
      LAYER M5 ;
        RECT  17.808 25.836 17.832 25.92 ;
    END
  END t1a[330]
  PIN t1a[331]
    DIRECTION INPUT ;
    USE SIGNAL ;
    PORT
      LAYER M5 ;
        RECT  17.904 25.836 17.928 25.92 ;
    END
  END t1a[331]
  PIN t1a[332]
    DIRECTION INPUT ;
    USE SIGNAL ;
    PORT
      LAYER M5 ;
        RECT  18 25.836 18.024 25.92 ;
    END
  END t1a[332]
  PIN t1a[333]
    DIRECTION INPUT ;
    USE SIGNAL ;
    PORT
      LAYER M5 ;
        RECT  18.096 25.836 18.12 25.92 ;
    END
  END t1a[333]
  PIN t1a[334]
    DIRECTION INPUT ;
    USE SIGNAL ;
    PORT
      LAYER M5 ;
        RECT  18.192 25.836 18.216 25.92 ;
    END
  END t1a[334]
  PIN t1a[335]
    DIRECTION INPUT ;
    USE SIGNAL ;
    PORT
      LAYER M5 ;
        RECT  18.288 25.836 18.312 25.92 ;
    END
  END t1a[335]
  PIN t1a[336]
    DIRECTION INPUT ;
    USE SIGNAL ;
    PORT
      LAYER M5 ;
        RECT  18.384 25.836 18.408 25.92 ;
    END
  END t1a[336]
  PIN t1a[337]
    DIRECTION INPUT ;
    USE SIGNAL ;
    PORT
      LAYER M5 ;
        RECT  18.48 25.836 18.504 25.92 ;
    END
  END t1a[337]
  PIN t1a[338]
    DIRECTION INPUT ;
    USE SIGNAL ;
    PORT
      LAYER M5 ;
        RECT  18.576 25.836 18.6 25.92 ;
    END
  END t1a[338]
  PIN t1a[339]
    DIRECTION INPUT ;
    USE SIGNAL ;
    PORT
      LAYER M5 ;
        RECT  18.672 25.836 18.696 25.92 ;
    END
  END t1a[339]
  PIN t1a[33]
    DIRECTION INPUT ;
    USE SIGNAL ;
    PORT
      LAYER M5 ;
        RECT  20.784 25.836 20.808 25.92 ;
    END
  END t1a[33]
  PIN t1a[340]
    DIRECTION INPUT ;
    USE SIGNAL ;
    PORT
      LAYER M5 ;
        RECT  18.768 25.836 18.792 25.92 ;
    END
  END t1a[340]
  PIN t1a[341]
    DIRECTION INPUT ;
    USE SIGNAL ;
    PORT
      LAYER M5 ;
        RECT  18.864 25.836 18.888 25.92 ;
    END
  END t1a[341]
  PIN t1a[342]
    DIRECTION INPUT ;
    USE SIGNAL ;
    PORT
      LAYER M5 ;
        RECT  18.96 25.836 18.984 25.92 ;
    END
  END t1a[342]
  PIN t1a[343]
    DIRECTION INPUT ;
    USE SIGNAL ;
    PORT
      LAYER M5 ;
        RECT  19.056 25.836 19.08 25.92 ;
    END
  END t1a[343]
  PIN t1a[344]
    DIRECTION INPUT ;
    USE SIGNAL ;
    PORT
      LAYER M5 ;
        RECT  19.152 25.836 19.176 25.92 ;
    END
  END t1a[344]
  PIN t1a[345]
    DIRECTION INPUT ;
    USE SIGNAL ;
    PORT
      LAYER M5 ;
        RECT  19.248 25.836 19.272 25.92 ;
    END
  END t1a[345]
  PIN t1a[346]
    DIRECTION INPUT ;
    USE SIGNAL ;
    PORT
      LAYER M5 ;
        RECT  19.344 25.836 19.368 25.92 ;
    END
  END t1a[346]
  PIN t1a[347]
    DIRECTION INPUT ;
    USE SIGNAL ;
    PORT
      LAYER M5 ;
        RECT  19.44 25.836 19.464 25.92 ;
    END
  END t1a[347]
  PIN t1a[348]
    DIRECTION INPUT ;
    USE SIGNAL ;
    PORT
      LAYER M5 ;
        RECT  19.536 25.836 19.56 25.92 ;
    END
  END t1a[348]
  PIN t1a[349]
    DIRECTION INPUT ;
    USE SIGNAL ;
    PORT
      LAYER M5 ;
        RECT  19.632 25.836 19.656 25.92 ;
    END
  END t1a[349]
  PIN t1a[34]
    DIRECTION INPUT ;
    USE SIGNAL ;
    PORT
      LAYER M5 ;
        RECT  20.88 25.836 20.904 25.92 ;
    END
  END t1a[34]
  PIN t1a[350]
    DIRECTION INPUT ;
    USE SIGNAL ;
    PORT
      LAYER M5 ;
        RECT  19.728 25.836 19.752 25.92 ;
    END
  END t1a[350]
  PIN t1a[351]
    DIRECTION INPUT ;
    USE SIGNAL ;
    PORT
      LAYER M5 ;
        RECT  19.824 25.836 19.848 25.92 ;
    END
  END t1a[351]
  PIN t1a[352]
    DIRECTION INPUT ;
    USE SIGNAL ;
    PORT
      LAYER M5 ;
        RECT  13.776 25.836 13.8 25.92 ;
    END
  END t1a[352]
  PIN t1a[353]
    DIRECTION INPUT ;
    USE SIGNAL ;
    PORT
      LAYER M5 ;
        RECT  13.872 25.836 13.896 25.92 ;
    END
  END t1a[353]
  PIN t1a[354]
    DIRECTION INPUT ;
    USE SIGNAL ;
    PORT
      LAYER M5 ;
        RECT  13.968 25.836 13.992 25.92 ;
    END
  END t1a[354]
  PIN t1a[355]
    DIRECTION INPUT ;
    USE SIGNAL ;
    PORT
      LAYER M5 ;
        RECT  14.064 25.836 14.088 25.92 ;
    END
  END t1a[355]
  PIN t1a[356]
    DIRECTION INPUT ;
    USE SIGNAL ;
    PORT
      LAYER M5 ;
        RECT  14.16 25.836 14.184 25.92 ;
    END
  END t1a[356]
  PIN t1a[357]
    DIRECTION INPUT ;
    USE SIGNAL ;
    PORT
      LAYER M5 ;
        RECT  14.256 25.836 14.28 25.92 ;
    END
  END t1a[357]
  PIN t1a[358]
    DIRECTION INPUT ;
    USE SIGNAL ;
    PORT
      LAYER M5 ;
        RECT  14.352 25.836 14.376 25.92 ;
    END
  END t1a[358]
  PIN t1a[359]
    DIRECTION INPUT ;
    USE SIGNAL ;
    PORT
      LAYER M5 ;
        RECT  14.448 25.836 14.472 25.92 ;
    END
  END t1a[359]
  PIN t1a[35]
    DIRECTION INPUT ;
    USE SIGNAL ;
    PORT
      LAYER M5 ;
        RECT  20.976 25.836 21 25.92 ;
    END
  END t1a[35]
  PIN t1a[360]
    DIRECTION INPUT ;
    USE SIGNAL ;
    PORT
      LAYER M5 ;
        RECT  14.544 25.836 14.568 25.92 ;
    END
  END t1a[360]
  PIN t1a[361]
    DIRECTION INPUT ;
    USE SIGNAL ;
    PORT
      LAYER M5 ;
        RECT  14.64 25.836 14.664 25.92 ;
    END
  END t1a[361]
  PIN t1a[362]
    DIRECTION INPUT ;
    USE SIGNAL ;
    PORT
      LAYER M5 ;
        RECT  14.736 25.836 14.76 25.92 ;
    END
  END t1a[362]
  PIN t1a[363]
    DIRECTION INPUT ;
    USE SIGNAL ;
    PORT
      LAYER M5 ;
        RECT  14.832 25.836 14.856 25.92 ;
    END
  END t1a[363]
  PIN t1a[364]
    DIRECTION INPUT ;
    USE SIGNAL ;
    PORT
      LAYER M5 ;
        RECT  14.928 25.836 14.952 25.92 ;
    END
  END t1a[364]
  PIN t1a[365]
    DIRECTION INPUT ;
    USE SIGNAL ;
    PORT
      LAYER M5 ;
        RECT  15.024 25.836 15.048 25.92 ;
    END
  END t1a[365]
  PIN t1a[366]
    DIRECTION INPUT ;
    USE SIGNAL ;
    PORT
      LAYER M5 ;
        RECT  15.12 25.836 15.144 25.92 ;
    END
  END t1a[366]
  PIN t1a[367]
    DIRECTION INPUT ;
    USE SIGNAL ;
    PORT
      LAYER M5 ;
        RECT  15.216 25.836 15.24 25.92 ;
    END
  END t1a[367]
  PIN t1a[368]
    DIRECTION INPUT ;
    USE SIGNAL ;
    PORT
      LAYER M5 ;
        RECT  15.312 25.836 15.336 25.92 ;
    END
  END t1a[368]
  PIN t1a[369]
    DIRECTION INPUT ;
    USE SIGNAL ;
    PORT
      LAYER M5 ;
        RECT  15.408 25.836 15.432 25.92 ;
    END
  END t1a[369]
  PIN t1a[36]
    DIRECTION INPUT ;
    USE SIGNAL ;
    PORT
      LAYER M5 ;
        RECT  21.072 25.836 21.096 25.92 ;
    END
  END t1a[36]
  PIN t1a[370]
    DIRECTION INPUT ;
    USE SIGNAL ;
    PORT
      LAYER M5 ;
        RECT  15.504 25.836 15.528 25.92 ;
    END
  END t1a[370]
  PIN t1a[371]
    DIRECTION INPUT ;
    USE SIGNAL ;
    PORT
      LAYER M5 ;
        RECT  15.6 25.836 15.624 25.92 ;
    END
  END t1a[371]
  PIN t1a[372]
    DIRECTION INPUT ;
    USE SIGNAL ;
    PORT
      LAYER M5 ;
        RECT  15.696 25.836 15.72 25.92 ;
    END
  END t1a[372]
  PIN t1a[373]
    DIRECTION INPUT ;
    USE SIGNAL ;
    PORT
      LAYER M5 ;
        RECT  15.792 25.836 15.816 25.92 ;
    END
  END t1a[373]
  PIN t1a[374]
    DIRECTION INPUT ;
    USE SIGNAL ;
    PORT
      LAYER M5 ;
        RECT  15.888 25.836 15.912 25.92 ;
    END
  END t1a[374]
  PIN t1a[375]
    DIRECTION INPUT ;
    USE SIGNAL ;
    PORT
      LAYER M5 ;
        RECT  15.984 25.836 16.008 25.92 ;
    END
  END t1a[375]
  PIN t1a[376]
    DIRECTION INPUT ;
    USE SIGNAL ;
    PORT
      LAYER M5 ;
        RECT  16.08 25.836 16.104 25.92 ;
    END
  END t1a[376]
  PIN t1a[377]
    DIRECTION INPUT ;
    USE SIGNAL ;
    PORT
      LAYER M5 ;
        RECT  16.176 25.836 16.2 25.92 ;
    END
  END t1a[377]
  PIN t1a[378]
    DIRECTION INPUT ;
    USE SIGNAL ;
    PORT
      LAYER M5 ;
        RECT  16.272 25.836 16.296 25.92 ;
    END
  END t1a[378]
  PIN t1a[379]
    DIRECTION INPUT ;
    USE SIGNAL ;
    PORT
      LAYER M5 ;
        RECT  16.368 25.836 16.392 25.92 ;
    END
  END t1a[379]
  PIN t1a[37]
    DIRECTION INPUT ;
    USE SIGNAL ;
    PORT
      LAYER M5 ;
        RECT  21.168 25.836 21.192 25.92 ;
    END
  END t1a[37]
  PIN t1a[380]
    DIRECTION INPUT ;
    USE SIGNAL ;
    PORT
      LAYER M5 ;
        RECT  16.464 25.836 16.488 25.92 ;
    END
  END t1a[380]
  PIN t1a[381]
    DIRECTION INPUT ;
    USE SIGNAL ;
    PORT
      LAYER M5 ;
        RECT  16.56 25.836 16.584 25.92 ;
    END
  END t1a[381]
  PIN t1a[382]
    DIRECTION INPUT ;
    USE SIGNAL ;
    PORT
      LAYER M5 ;
        RECT  16.656 25.836 16.68 25.92 ;
    END
  END t1a[382]
  PIN t1a[383]
    DIRECTION INPUT ;
    USE SIGNAL ;
    PORT
      LAYER M5 ;
        RECT  16.752 25.836 16.776 25.92 ;
    END
  END t1a[383]
  PIN t1a[384]
    DIRECTION INPUT ;
    USE SIGNAL ;
    PORT
      LAYER M5 ;
        RECT  109.776 25.836 109.8 25.92 ;
    END
  END t1a[384]
  PIN t1a[385]
    DIRECTION INPUT ;
    USE SIGNAL ;
    PORT
      LAYER M5 ;
        RECT  109.872 25.836 109.896 25.92 ;
    END
  END t1a[385]
  PIN t1a[386]
    DIRECTION INPUT ;
    USE SIGNAL ;
    PORT
      LAYER M5 ;
        RECT  109.968 25.836 109.992 25.92 ;
    END
  END t1a[386]
  PIN t1a[387]
    DIRECTION INPUT ;
    USE SIGNAL ;
    PORT
      LAYER M5 ;
        RECT  110.064 25.836 110.088 25.92 ;
    END
  END t1a[387]
  PIN t1a[388]
    DIRECTION INPUT ;
    USE SIGNAL ;
    PORT
      LAYER M5 ;
        RECT  110.16 25.836 110.184 25.92 ;
    END
  END t1a[388]
  PIN t1a[389]
    DIRECTION INPUT ;
    USE SIGNAL ;
    PORT
      LAYER M5 ;
        RECT  110.256 25.836 110.28 25.92 ;
    END
  END t1a[389]
  PIN t1a[38]
    DIRECTION INPUT ;
    USE SIGNAL ;
    PORT
      LAYER M5 ;
        RECT  21.264 25.836 21.288 25.92 ;
    END
  END t1a[38]
  PIN t1a[390]
    DIRECTION INPUT ;
    USE SIGNAL ;
    PORT
      LAYER M5 ;
        RECT  110.352 25.836 110.376 25.92 ;
    END
  END t1a[390]
  PIN t1a[391]
    DIRECTION INPUT ;
    USE SIGNAL ;
    PORT
      LAYER M5 ;
        RECT  110.448 25.836 110.472 25.92 ;
    END
  END t1a[391]
  PIN t1a[392]
    DIRECTION INPUT ;
    USE SIGNAL ;
    PORT
      LAYER M5 ;
        RECT  110.544 25.836 110.568 25.92 ;
    END
  END t1a[392]
  PIN t1a[393]
    DIRECTION INPUT ;
    USE SIGNAL ;
    PORT
      LAYER M5 ;
        RECT  110.64 25.836 110.664 25.92 ;
    END
  END t1a[393]
  PIN t1a[394]
    DIRECTION INPUT ;
    USE SIGNAL ;
    PORT
      LAYER M5 ;
        RECT  110.736 25.836 110.76 25.92 ;
    END
  END t1a[394]
  PIN t1a[395]
    DIRECTION INPUT ;
    USE SIGNAL ;
    PORT
      LAYER M5 ;
        RECT  110.832 25.836 110.856 25.92 ;
    END
  END t1a[395]
  PIN t1a[396]
    DIRECTION INPUT ;
    USE SIGNAL ;
    PORT
      LAYER M5 ;
        RECT  110.928 25.836 110.952 25.92 ;
    END
  END t1a[396]
  PIN t1a[397]
    DIRECTION INPUT ;
    USE SIGNAL ;
    PORT
      LAYER M5 ;
        RECT  111.024 25.836 111.048 25.92 ;
    END
  END t1a[397]
  PIN t1a[398]
    DIRECTION INPUT ;
    USE SIGNAL ;
    PORT
      LAYER M5 ;
        RECT  111.12 25.836 111.144 25.92 ;
    END
  END t1a[398]
  PIN t1a[399]
    DIRECTION INPUT ;
    USE SIGNAL ;
    PORT
      LAYER M5 ;
        RECT  111.216 25.836 111.24 25.92 ;
    END
  END t1a[399]
  PIN t1a[39]
    DIRECTION INPUT ;
    USE SIGNAL ;
    PORT
      LAYER M5 ;
        RECT  21.36 25.836 21.384 25.92 ;
    END
  END t1a[39]
  PIN t1a[3]
    DIRECTION INPUT ;
    USE SIGNAL ;
    PORT
      LAYER M5 ;
        RECT  84.72 25.836 84.744 25.92 ;
    END
  END t1a[3]
  PIN t1a[400]
    DIRECTION INPUT ;
    USE SIGNAL ;
    PORT
      LAYER M5 ;
        RECT  111.312 25.836 111.336 25.92 ;
    END
  END t1a[400]
  PIN t1a[401]
    DIRECTION INPUT ;
    USE SIGNAL ;
    PORT
      LAYER M5 ;
        RECT  111.408 25.836 111.432 25.92 ;
    END
  END t1a[401]
  PIN t1a[402]
    DIRECTION INPUT ;
    USE SIGNAL ;
    PORT
      LAYER M5 ;
        RECT  111.504 25.836 111.528 25.92 ;
    END
  END t1a[402]
  PIN t1a[403]
    DIRECTION INPUT ;
    USE SIGNAL ;
    PORT
      LAYER M5 ;
        RECT  111.6 25.836 111.624 25.92 ;
    END
  END t1a[403]
  PIN t1a[404]
    DIRECTION INPUT ;
    USE SIGNAL ;
    PORT
      LAYER M5 ;
        RECT  111.696 25.836 111.72 25.92 ;
    END
  END t1a[404]
  PIN t1a[405]
    DIRECTION INPUT ;
    USE SIGNAL ;
    PORT
      LAYER M5 ;
        RECT  111.792 25.836 111.816 25.92 ;
    END
  END t1a[405]
  PIN t1a[406]
    DIRECTION INPUT ;
    USE SIGNAL ;
    PORT
      LAYER M5 ;
        RECT  111.888 25.836 111.912 25.92 ;
    END
  END t1a[406]
  PIN t1a[407]
    DIRECTION INPUT ;
    USE SIGNAL ;
    PORT
      LAYER M5 ;
        RECT  111.984 25.836 112.008 25.92 ;
    END
  END t1a[407]
  PIN t1a[408]
    DIRECTION INPUT ;
    USE SIGNAL ;
    PORT
      LAYER M5 ;
        RECT  112.08 25.836 112.104 25.92 ;
    END
  END t1a[408]
  PIN t1a[409]
    DIRECTION INPUT ;
    USE SIGNAL ;
    PORT
      LAYER M5 ;
        RECT  112.176 25.836 112.2 25.92 ;
    END
  END t1a[409]
  PIN t1a[40]
    DIRECTION INPUT ;
    USE SIGNAL ;
    PORT
      LAYER M5 ;
        RECT  21.456 25.836 21.48 25.92 ;
    END
  END t1a[40]
  PIN t1a[410]
    DIRECTION INPUT ;
    USE SIGNAL ;
    PORT
      LAYER M5 ;
        RECT  112.272 25.836 112.296 25.92 ;
    END
  END t1a[410]
  PIN t1a[411]
    DIRECTION INPUT ;
    USE SIGNAL ;
    PORT
      LAYER M5 ;
        RECT  112.368 25.836 112.392 25.92 ;
    END
  END t1a[411]
  PIN t1a[412]
    DIRECTION INPUT ;
    USE SIGNAL ;
    PORT
      LAYER M5 ;
        RECT  112.464 25.836 112.488 25.92 ;
    END
  END t1a[412]
  PIN t1a[413]
    DIRECTION INPUT ;
    USE SIGNAL ;
    PORT
      LAYER M5 ;
        RECT  112.56 25.836 112.584 25.92 ;
    END
  END t1a[413]
  PIN t1a[414]
    DIRECTION INPUT ;
    USE SIGNAL ;
    PORT
      LAYER M5 ;
        RECT  112.656 25.836 112.68 25.92 ;
    END
  END t1a[414]
  PIN t1a[415]
    DIRECTION INPUT ;
    USE SIGNAL ;
    PORT
      LAYER M5 ;
        RECT  112.752 25.836 112.776 25.92 ;
    END
  END t1a[415]
  PIN t1a[416]
    DIRECTION INPUT ;
    USE SIGNAL ;
    PORT
      LAYER M5 ;
        RECT  100.56 25.836 100.584 25.92 ;
    END
  END t1a[416]
  PIN t1a[417]
    DIRECTION INPUT ;
    USE SIGNAL ;
    PORT
      LAYER M5 ;
        RECT  100.656 25.836 100.68 25.92 ;
    END
  END t1a[417]
  PIN t1a[418]
    DIRECTION INPUT ;
    USE SIGNAL ;
    PORT
      LAYER M5 ;
        RECT  100.752 25.836 100.776 25.92 ;
    END
  END t1a[418]
  PIN t1a[419]
    DIRECTION INPUT ;
    USE SIGNAL ;
    PORT
      LAYER M5 ;
        RECT  100.848 25.836 100.872 25.92 ;
    END
  END t1a[419]
  PIN t1a[41]
    DIRECTION INPUT ;
    USE SIGNAL ;
    PORT
      LAYER M5 ;
        RECT  21.552 25.836 21.576 25.92 ;
    END
  END t1a[41]
  PIN t1a[420]
    DIRECTION INPUT ;
    USE SIGNAL ;
    PORT
      LAYER M5 ;
        RECT  100.944 25.836 100.968 25.92 ;
    END
  END t1a[420]
  PIN t1a[421]
    DIRECTION INPUT ;
    USE SIGNAL ;
    PORT
      LAYER M5 ;
        RECT  101.04 25.836 101.064 25.92 ;
    END
  END t1a[421]
  PIN t1a[422]
    DIRECTION INPUT ;
    USE SIGNAL ;
    PORT
      LAYER M5 ;
        RECT  101.136 25.836 101.16 25.92 ;
    END
  END t1a[422]
  PIN t1a[423]
    DIRECTION INPUT ;
    USE SIGNAL ;
    PORT
      LAYER M5 ;
        RECT  101.232 25.836 101.256 25.92 ;
    END
  END t1a[423]
  PIN t1a[424]
    DIRECTION INPUT ;
    USE SIGNAL ;
    PORT
      LAYER M5 ;
        RECT  101.328 25.836 101.352 25.92 ;
    END
  END t1a[424]
  PIN t1a[425]
    DIRECTION INPUT ;
    USE SIGNAL ;
    PORT
      LAYER M5 ;
        RECT  101.424 25.836 101.448 25.92 ;
    END
  END t1a[425]
  PIN t1a[426]
    DIRECTION INPUT ;
    USE SIGNAL ;
    PORT
      LAYER M5 ;
        RECT  101.52 25.836 101.544 25.92 ;
    END
  END t1a[426]
  PIN t1a[427]
    DIRECTION INPUT ;
    USE SIGNAL ;
    PORT
      LAYER M5 ;
        RECT  101.616 25.836 101.64 25.92 ;
    END
  END t1a[427]
  PIN t1a[428]
    DIRECTION INPUT ;
    USE SIGNAL ;
    PORT
      LAYER M5 ;
        RECT  101.712 25.836 101.736 25.92 ;
    END
  END t1a[428]
  PIN t1a[429]
    DIRECTION INPUT ;
    USE SIGNAL ;
    PORT
      LAYER M5 ;
        RECT  101.808 25.836 101.832 25.92 ;
    END
  END t1a[429]
  PIN t1a[42]
    DIRECTION INPUT ;
    USE SIGNAL ;
    PORT
      LAYER M5 ;
        RECT  21.648 25.836 21.672 25.92 ;
    END
  END t1a[42]
  PIN t1a[430]
    DIRECTION INPUT ;
    USE SIGNAL ;
    PORT
      LAYER M5 ;
        RECT  101.904 25.836 101.928 25.92 ;
    END
  END t1a[430]
  PIN t1a[431]
    DIRECTION INPUT ;
    USE SIGNAL ;
    PORT
      LAYER M5 ;
        RECT  102 25.836 102.024 25.92 ;
    END
  END t1a[431]
  PIN t1a[432]
    DIRECTION INPUT ;
    USE SIGNAL ;
    PORT
      LAYER M5 ;
        RECT  102.096 25.836 102.12 25.92 ;
    END
  END t1a[432]
  PIN t1a[433]
    DIRECTION INPUT ;
    USE SIGNAL ;
    PORT
      LAYER M5 ;
        RECT  102.192 25.836 102.216 25.92 ;
    END
  END t1a[433]
  PIN t1a[434]
    DIRECTION INPUT ;
    USE SIGNAL ;
    PORT
      LAYER M5 ;
        RECT  102.288 25.836 102.312 25.92 ;
    END
  END t1a[434]
  PIN t1a[435]
    DIRECTION INPUT ;
    USE SIGNAL ;
    PORT
      LAYER M5 ;
        RECT  102.384 25.836 102.408 25.92 ;
    END
  END t1a[435]
  PIN t1a[436]
    DIRECTION INPUT ;
    USE SIGNAL ;
    PORT
      LAYER M5 ;
        RECT  102.48 25.836 102.504 25.92 ;
    END
  END t1a[436]
  PIN t1a[437]
    DIRECTION INPUT ;
    USE SIGNAL ;
    PORT
      LAYER M5 ;
        RECT  102.576 25.836 102.6 25.92 ;
    END
  END t1a[437]
  PIN t1a[438]
    DIRECTION INPUT ;
    USE SIGNAL ;
    PORT
      LAYER M5 ;
        RECT  102.672 25.836 102.696 25.92 ;
    END
  END t1a[438]
  PIN t1a[439]
    DIRECTION INPUT ;
    USE SIGNAL ;
    PORT
      LAYER M5 ;
        RECT  102.768 25.836 102.792 25.92 ;
    END
  END t1a[439]
  PIN t1a[43]
    DIRECTION INPUT ;
    USE SIGNAL ;
    PORT
      LAYER M5 ;
        RECT  21.744 25.836 21.768 25.92 ;
    END
  END t1a[43]
  PIN t1a[440]
    DIRECTION INPUT ;
    USE SIGNAL ;
    PORT
      LAYER M5 ;
        RECT  102.864 25.836 102.888 25.92 ;
    END
  END t1a[440]
  PIN t1a[441]
    DIRECTION INPUT ;
    USE SIGNAL ;
    PORT
      LAYER M5 ;
        RECT  102.96 25.836 102.984 25.92 ;
    END
  END t1a[441]
  PIN t1a[442]
    DIRECTION INPUT ;
    USE SIGNAL ;
    PORT
      LAYER M5 ;
        RECT  103.056 25.836 103.08 25.92 ;
    END
  END t1a[442]
  PIN t1a[443]
    DIRECTION INPUT ;
    USE SIGNAL ;
    PORT
      LAYER M5 ;
        RECT  103.152 25.836 103.176 25.92 ;
    END
  END t1a[443]
  PIN t1a[444]
    DIRECTION INPUT ;
    USE SIGNAL ;
    PORT
      LAYER M5 ;
        RECT  103.248 25.836 103.272 25.92 ;
    END
  END t1a[444]
  PIN t1a[445]
    DIRECTION INPUT ;
    USE SIGNAL ;
    PORT
      LAYER M5 ;
        RECT  103.344 25.836 103.368 25.92 ;
    END
  END t1a[445]
  PIN t1a[446]
    DIRECTION INPUT ;
    USE SIGNAL ;
    PORT
      LAYER M5 ;
        RECT  103.44 25.836 103.464 25.92 ;
    END
  END t1a[446]
  PIN t1a[447]
    DIRECTION INPUT ;
    USE SIGNAL ;
    PORT
      LAYER M5 ;
        RECT  103.536 25.836 103.56 25.92 ;
    END
  END t1a[447]
  PIN t1a[448]
    DIRECTION INPUT ;
    USE SIGNAL ;
    PORT
      LAYER M5 ;
        RECT  10.704 25.836 10.728 25.92 ;
    END
  END t1a[448]
  PIN t1a[449]
    DIRECTION INPUT ;
    USE SIGNAL ;
    PORT
      LAYER M5 ;
        RECT  10.8 25.836 10.824 25.92 ;
    END
  END t1a[449]
  PIN t1a[44]
    DIRECTION INPUT ;
    USE SIGNAL ;
    PORT
      LAYER M5 ;
        RECT  21.84 25.836 21.864 25.92 ;
    END
  END t1a[44]
  PIN t1a[450]
    DIRECTION INPUT ;
    USE SIGNAL ;
    PORT
      LAYER M5 ;
        RECT  10.896 25.836 10.92 25.92 ;
    END
  END t1a[450]
  PIN t1a[451]
    DIRECTION INPUT ;
    USE SIGNAL ;
    PORT
      LAYER M5 ;
        RECT  10.992 25.836 11.016 25.92 ;
    END
  END t1a[451]
  PIN t1a[452]
    DIRECTION INPUT ;
    USE SIGNAL ;
    PORT
      LAYER M5 ;
        RECT  11.088 25.836 11.112 25.92 ;
    END
  END t1a[452]
  PIN t1a[453]
    DIRECTION INPUT ;
    USE SIGNAL ;
    PORT
      LAYER M5 ;
        RECT  11.184 25.836 11.208 25.92 ;
    END
  END t1a[453]
  PIN t1a[454]
    DIRECTION INPUT ;
    USE SIGNAL ;
    PORT
      LAYER M5 ;
        RECT  11.28 25.836 11.304 25.92 ;
    END
  END t1a[454]
  PIN t1a[455]
    DIRECTION INPUT ;
    USE SIGNAL ;
    PORT
      LAYER M5 ;
        RECT  11.376 25.836 11.4 25.92 ;
    END
  END t1a[455]
  PIN t1a[456]
    DIRECTION INPUT ;
    USE SIGNAL ;
    PORT
      LAYER M5 ;
        RECT  11.472 25.836 11.496 25.92 ;
    END
  END t1a[456]
  PIN t1a[457]
    DIRECTION INPUT ;
    USE SIGNAL ;
    PORT
      LAYER M5 ;
        RECT  11.568 25.836 11.592 25.92 ;
    END
  END t1a[457]
  PIN t1a[458]
    DIRECTION INPUT ;
    USE SIGNAL ;
    PORT
      LAYER M5 ;
        RECT  11.664 25.836 11.688 25.92 ;
    END
  END t1a[458]
  PIN t1a[459]
    DIRECTION INPUT ;
    USE SIGNAL ;
    PORT
      LAYER M5 ;
        RECT  11.76 25.836 11.784 25.92 ;
    END
  END t1a[459]
  PIN t1a[45]
    DIRECTION INPUT ;
    USE SIGNAL ;
    PORT
      LAYER M5 ;
        RECT  21.936 25.836 21.96 25.92 ;
    END
  END t1a[45]
  PIN t1a[460]
    DIRECTION INPUT ;
    USE SIGNAL ;
    PORT
      LAYER M5 ;
        RECT  11.856 25.836 11.88 25.92 ;
    END
  END t1a[460]
  PIN t1a[461]
    DIRECTION INPUT ;
    USE SIGNAL ;
    PORT
      LAYER M5 ;
        RECT  11.952 25.836 11.976 25.92 ;
    END
  END t1a[461]
  PIN t1a[462]
    DIRECTION INPUT ;
    USE SIGNAL ;
    PORT
      LAYER M5 ;
        RECT  12.048 25.836 12.072 25.92 ;
    END
  END t1a[462]
  PIN t1a[463]
    DIRECTION INPUT ;
    USE SIGNAL ;
    PORT
      LAYER M5 ;
        RECT  12.144 25.836 12.168 25.92 ;
    END
  END t1a[463]
  PIN t1a[464]
    DIRECTION INPUT ;
    USE SIGNAL ;
    PORT
      LAYER M5 ;
        RECT  12.24 25.836 12.264 25.92 ;
    END
  END t1a[464]
  PIN t1a[465]
    DIRECTION INPUT ;
    USE SIGNAL ;
    PORT
      LAYER M5 ;
        RECT  12.336 25.836 12.36 25.92 ;
    END
  END t1a[465]
  PIN t1a[466]
    DIRECTION INPUT ;
    USE SIGNAL ;
    PORT
      LAYER M5 ;
        RECT  12.432 25.836 12.456 25.92 ;
    END
  END t1a[466]
  PIN t1a[467]
    DIRECTION INPUT ;
    USE SIGNAL ;
    PORT
      LAYER M5 ;
        RECT  12.528 25.836 12.552 25.92 ;
    END
  END t1a[467]
  PIN t1a[468]
    DIRECTION INPUT ;
    USE SIGNAL ;
    PORT
      LAYER M5 ;
        RECT  12.624 25.836 12.648 25.92 ;
    END
  END t1a[468]
  PIN t1a[469]
    DIRECTION INPUT ;
    USE SIGNAL ;
    PORT
      LAYER M5 ;
        RECT  12.72 25.836 12.744 25.92 ;
    END
  END t1a[469]
  PIN t1a[46]
    DIRECTION INPUT ;
    USE SIGNAL ;
    PORT
      LAYER M5 ;
        RECT  22.032 25.836 22.056 25.92 ;
    END
  END t1a[46]
  PIN t1a[470]
    DIRECTION INPUT ;
    USE SIGNAL ;
    PORT
      LAYER M5 ;
        RECT  12.816 25.836 12.84 25.92 ;
    END
  END t1a[470]
  PIN t1a[471]
    DIRECTION INPUT ;
    USE SIGNAL ;
    PORT
      LAYER M5 ;
        RECT  12.912 25.836 12.936 25.92 ;
    END
  END t1a[471]
  PIN t1a[472]
    DIRECTION INPUT ;
    USE SIGNAL ;
    PORT
      LAYER M5 ;
        RECT  13.008 25.836 13.032 25.92 ;
    END
  END t1a[472]
  PIN t1a[473]
    DIRECTION INPUT ;
    USE SIGNAL ;
    PORT
      LAYER M5 ;
        RECT  13.104 25.836 13.128 25.92 ;
    END
  END t1a[473]
  PIN t1a[474]
    DIRECTION INPUT ;
    USE SIGNAL ;
    PORT
      LAYER M5 ;
        RECT  13.2 25.836 13.224 25.92 ;
    END
  END t1a[474]
  PIN t1a[475]
    DIRECTION INPUT ;
    USE SIGNAL ;
    PORT
      LAYER M5 ;
        RECT  13.296 25.836 13.32 25.92 ;
    END
  END t1a[475]
  PIN t1a[476]
    DIRECTION INPUT ;
    USE SIGNAL ;
    PORT
      LAYER M5 ;
        RECT  13.392 25.836 13.416 25.92 ;
    END
  END t1a[476]
  PIN t1a[477]
    DIRECTION INPUT ;
    USE SIGNAL ;
    PORT
      LAYER M5 ;
        RECT  13.488 25.836 13.512 25.92 ;
    END
  END t1a[477]
  PIN t1a[478]
    DIRECTION INPUT ;
    USE SIGNAL ;
    PORT
      LAYER M5 ;
        RECT  13.584 25.836 13.608 25.92 ;
    END
  END t1a[478]
  PIN t1a[479]
    DIRECTION INPUT ;
    USE SIGNAL ;
    PORT
      LAYER M5 ;
        RECT  13.68 25.836 13.704 25.92 ;
    END
  END t1a[479]
  PIN t1a[47]
    DIRECTION INPUT ;
    USE SIGNAL ;
    PORT
      LAYER M5 ;
        RECT  22.128 25.836 22.152 25.92 ;
    END
  END t1a[47]
  PIN t1a[480]
    DIRECTION INPUT ;
    USE SIGNAL ;
    PORT
      LAYER M5 ;
        RECT  103.632 25.836 103.656 25.92 ;
    END
  END t1a[480]
  PIN t1a[481]
    DIRECTION INPUT ;
    USE SIGNAL ;
    PORT
      LAYER M5 ;
        RECT  103.728 25.836 103.752 25.92 ;
    END
  END t1a[481]
  PIN t1a[482]
    DIRECTION INPUT ;
    USE SIGNAL ;
    PORT
      LAYER M5 ;
        RECT  103.824 25.836 103.848 25.92 ;
    END
  END t1a[482]
  PIN t1a[483]
    DIRECTION INPUT ;
    USE SIGNAL ;
    PORT
      LAYER M5 ;
        RECT  103.92 25.836 103.944 25.92 ;
    END
  END t1a[483]
  PIN t1a[484]
    DIRECTION INPUT ;
    USE SIGNAL ;
    PORT
      LAYER M5 ;
        RECT  104.016 25.836 104.04 25.92 ;
    END
  END t1a[484]
  PIN t1a[485]
    DIRECTION INPUT ;
    USE SIGNAL ;
    PORT
      LAYER M5 ;
        RECT  104.112 25.836 104.136 25.92 ;
    END
  END t1a[485]
  PIN t1a[486]
    DIRECTION INPUT ;
    USE SIGNAL ;
    PORT
      LAYER M5 ;
        RECT  104.208 25.836 104.232 25.92 ;
    END
  END t1a[486]
  PIN t1a[487]
    DIRECTION INPUT ;
    USE SIGNAL ;
    PORT
      LAYER M5 ;
        RECT  104.304 25.836 104.328 25.92 ;
    END
  END t1a[487]
  PIN t1a[488]
    DIRECTION INPUT ;
    USE SIGNAL ;
    PORT
      LAYER M5 ;
        RECT  104.4 25.836 104.424 25.92 ;
    END
  END t1a[488]
  PIN t1a[489]
    DIRECTION INPUT ;
    USE SIGNAL ;
    PORT
      LAYER M5 ;
        RECT  104.496 25.836 104.52 25.92 ;
    END
  END t1a[489]
  PIN t1a[48]
    DIRECTION INPUT ;
    USE SIGNAL ;
    PORT
      LAYER M5 ;
        RECT  22.224 25.836 22.248 25.92 ;
    END
  END t1a[48]
  PIN t1a[490]
    DIRECTION INPUT ;
    USE SIGNAL ;
    PORT
      LAYER M5 ;
        RECT  104.592 25.836 104.616 25.92 ;
    END
  END t1a[490]
  PIN t1a[491]
    DIRECTION INPUT ;
    USE SIGNAL ;
    PORT
      LAYER M5 ;
        RECT  104.688 25.836 104.712 25.92 ;
    END
  END t1a[491]
  PIN t1a[492]
    DIRECTION INPUT ;
    USE SIGNAL ;
    PORT
      LAYER M5 ;
        RECT  104.784 25.836 104.808 25.92 ;
    END
  END t1a[492]
  PIN t1a[493]
    DIRECTION INPUT ;
    USE SIGNAL ;
    PORT
      LAYER M5 ;
        RECT  104.88 25.836 104.904 25.92 ;
    END
  END t1a[493]
  PIN t1a[494]
    DIRECTION INPUT ;
    USE SIGNAL ;
    PORT
      LAYER M5 ;
        RECT  104.976 25.836 105 25.92 ;
    END
  END t1a[494]
  PIN t1a[495]
    DIRECTION INPUT ;
    USE SIGNAL ;
    PORT
      LAYER M5 ;
        RECT  105.072 25.836 105.096 25.92 ;
    END
  END t1a[495]
  PIN t1a[496]
    DIRECTION INPUT ;
    USE SIGNAL ;
    PORT
      LAYER M5 ;
        RECT  105.168 25.836 105.192 25.92 ;
    END
  END t1a[496]
  PIN t1a[497]
    DIRECTION INPUT ;
    USE SIGNAL ;
    PORT
      LAYER M5 ;
        RECT  105.264 25.836 105.288 25.92 ;
    END
  END t1a[497]
  PIN t1a[498]
    DIRECTION INPUT ;
    USE SIGNAL ;
    PORT
      LAYER M5 ;
        RECT  105.36 25.836 105.384 25.92 ;
    END
  END t1a[498]
  PIN t1a[499]
    DIRECTION INPUT ;
    USE SIGNAL ;
    PORT
      LAYER M5 ;
        RECT  105.456 25.836 105.48 25.92 ;
    END
  END t1a[499]
  PIN t1a[49]
    DIRECTION INPUT ;
    USE SIGNAL ;
    PORT
      LAYER M5 ;
        RECT  22.32 25.836 22.344 25.92 ;
    END
  END t1a[49]
  PIN t1a[4]
    DIRECTION INPUT ;
    USE SIGNAL ;
    PORT
      LAYER M5 ;
        RECT  84.816 25.836 84.84 25.92 ;
    END
  END t1a[4]
  PIN t1a[500]
    DIRECTION INPUT ;
    USE SIGNAL ;
    PORT
      LAYER M5 ;
        RECT  105.552 25.836 105.576 25.92 ;
    END
  END t1a[500]
  PIN t1a[501]
    DIRECTION INPUT ;
    USE SIGNAL ;
    PORT
      LAYER M5 ;
        RECT  105.648 25.836 105.672 25.92 ;
    END
  END t1a[501]
  PIN t1a[502]
    DIRECTION INPUT ;
    USE SIGNAL ;
    PORT
      LAYER M5 ;
        RECT  105.744 25.836 105.768 25.92 ;
    END
  END t1a[502]
  PIN t1a[503]
    DIRECTION INPUT ;
    USE SIGNAL ;
    PORT
      LAYER M5 ;
        RECT  105.84 25.836 105.864 25.92 ;
    END
  END t1a[503]
  PIN t1a[504]
    DIRECTION INPUT ;
    USE SIGNAL ;
    PORT
      LAYER M5 ;
        RECT  105.936 25.836 105.96 25.92 ;
    END
  END t1a[504]
  PIN t1a[505]
    DIRECTION INPUT ;
    USE SIGNAL ;
    PORT
      LAYER M5 ;
        RECT  106.032 25.836 106.056 25.92 ;
    END
  END t1a[505]
  PIN t1a[506]
    DIRECTION INPUT ;
    USE SIGNAL ;
    PORT
      LAYER M5 ;
        RECT  106.128 25.836 106.152 25.92 ;
    END
  END t1a[506]
  PIN t1a[507]
    DIRECTION INPUT ;
    USE SIGNAL ;
    PORT
      LAYER M5 ;
        RECT  106.224 25.836 106.248 25.92 ;
    END
  END t1a[507]
  PIN t1a[508]
    DIRECTION INPUT ;
    USE SIGNAL ;
    PORT
      LAYER M5 ;
        RECT  106.32 25.836 106.344 25.92 ;
    END
  END t1a[508]
  PIN t1a[509]
    DIRECTION INPUT ;
    USE SIGNAL ;
    PORT
      LAYER M5 ;
        RECT  106.416 25.836 106.44 25.92 ;
    END
  END t1a[509]
  PIN t1a[50]
    DIRECTION INPUT ;
    USE SIGNAL ;
    PORT
      LAYER M5 ;
        RECT  22.416 25.836 22.44 25.92 ;
    END
  END t1a[50]
  PIN t1a[510]
    DIRECTION INPUT ;
    USE SIGNAL ;
    PORT
      LAYER M5 ;
        RECT  106.512 25.836 106.536 25.92 ;
    END
  END t1a[510]
  PIN t1a[511]
    DIRECTION INPUT ;
    USE SIGNAL ;
    PORT
      LAYER M5 ;
        RECT  106.608 25.836 106.632 25.92 ;
    END
  END t1a[511]
  PIN t1a[51]
    DIRECTION INPUT ;
    USE SIGNAL ;
    PORT
      LAYER M5 ;
        RECT  22.512 25.836 22.536 25.92 ;
    END
  END t1a[51]
  PIN t1a[52]
    DIRECTION INPUT ;
    USE SIGNAL ;
    PORT
      LAYER M5 ;
        RECT  22.608 25.836 22.632 25.92 ;
    END
  END t1a[52]
  PIN t1a[53]
    DIRECTION INPUT ;
    USE SIGNAL ;
    PORT
      LAYER M5 ;
        RECT  22.704 25.836 22.728 25.92 ;
    END
  END t1a[53]
  PIN t1a[54]
    DIRECTION INPUT ;
    USE SIGNAL ;
    PORT
      LAYER M5 ;
        RECT  22.8 25.836 22.824 25.92 ;
    END
  END t1a[54]
  PIN t1a[55]
    DIRECTION INPUT ;
    USE SIGNAL ;
    PORT
      LAYER M5 ;
        RECT  22.896 25.836 22.92 25.92 ;
    END
  END t1a[55]
  PIN t1a[56]
    DIRECTION INPUT ;
    USE SIGNAL ;
    PORT
      LAYER M5 ;
        RECT  22.992 25.836 23.016 25.92 ;
    END
  END t1a[56]
  PIN t1a[57]
    DIRECTION INPUT ;
    USE SIGNAL ;
    PORT
      LAYER M5 ;
        RECT  23.088 25.836 23.112 25.92 ;
    END
  END t1a[57]
  PIN t1a[58]
    DIRECTION INPUT ;
    USE SIGNAL ;
    PORT
      LAYER M5 ;
        RECT  23.184 25.836 23.208 25.92 ;
    END
  END t1a[58]
  PIN t1a[59]
    DIRECTION INPUT ;
    USE SIGNAL ;
    PORT
      LAYER M5 ;
        RECT  23.28 25.836 23.304 25.92 ;
    END
  END t1a[59]
  PIN t1a[5]
    DIRECTION INPUT ;
    USE SIGNAL ;
    PORT
      LAYER M5 ;
        RECT  84.912 25.836 84.936 25.92 ;
    END
  END t1a[5]
  PIN t1a[60]
    DIRECTION INPUT ;
    USE SIGNAL ;
    PORT
      LAYER M5 ;
        RECT  23.376 25.836 23.4 25.92 ;
    END
  END t1a[60]
  PIN t1a[61]
    DIRECTION INPUT ;
    USE SIGNAL ;
    PORT
      LAYER M5 ;
        RECT  23.472 25.836 23.496 25.92 ;
    END
  END t1a[61]
  PIN t1a[62]
    DIRECTION INPUT ;
    USE SIGNAL ;
    PORT
      LAYER M5 ;
        RECT  23.568 25.836 23.592 25.92 ;
    END
  END t1a[62]
  PIN t1a[63]
    DIRECTION INPUT ;
    USE SIGNAL ;
    PORT
      LAYER M5 ;
        RECT  23.664 25.836 23.688 25.92 ;
    END
  END t1a[63]
  PIN t1a[64]
    DIRECTION INPUT ;
    USE SIGNAL ;
    PORT
      LAYER M5 ;
        RECT  29.904 25.836 29.928 25.92 ;
    END
  END t1a[64]
  PIN t1a[65]
    DIRECTION INPUT ;
    USE SIGNAL ;
    PORT
      LAYER M5 ;
        RECT  30 25.836 30.024 25.92 ;
    END
  END t1a[65]
  PIN t1a[66]
    DIRECTION INPUT ;
    USE SIGNAL ;
    PORT
      LAYER M5 ;
        RECT  30.096 25.836 30.12 25.92 ;
    END
  END t1a[66]
  PIN t1a[67]
    DIRECTION INPUT ;
    USE SIGNAL ;
    PORT
      LAYER M5 ;
        RECT  30.192 25.836 30.216 25.92 ;
    END
  END t1a[67]
  PIN t1a[68]
    DIRECTION INPUT ;
    USE SIGNAL ;
    PORT
      LAYER M5 ;
        RECT  30.288 25.836 30.312 25.92 ;
    END
  END t1a[68]
  PIN t1a[69]
    DIRECTION INPUT ;
    USE SIGNAL ;
    PORT
      LAYER M5 ;
        RECT  30.384 25.836 30.408 25.92 ;
    END
  END t1a[69]
  PIN t1a[6]
    DIRECTION INPUT ;
    USE SIGNAL ;
    PORT
      LAYER M5 ;
        RECT  85.008 25.836 85.032 25.92 ;
    END
  END t1a[6]
  PIN t1a[70]
    DIRECTION INPUT ;
    USE SIGNAL ;
    PORT
      LAYER M5 ;
        RECT  30.48 25.836 30.504 25.92 ;
    END
  END t1a[70]
  PIN t1a[71]
    DIRECTION INPUT ;
    USE SIGNAL ;
    PORT
      LAYER M5 ;
        RECT  30.576 25.836 30.6 25.92 ;
    END
  END t1a[71]
  PIN t1a[72]
    DIRECTION INPUT ;
    USE SIGNAL ;
    PORT
      LAYER M5 ;
        RECT  30.672 25.836 30.696 25.92 ;
    END
  END t1a[72]
  PIN t1a[73]
    DIRECTION INPUT ;
    USE SIGNAL ;
    PORT
      LAYER M5 ;
        RECT  30.768 25.836 30.792 25.92 ;
    END
  END t1a[73]
  PIN t1a[74]
    DIRECTION INPUT ;
    USE SIGNAL ;
    PORT
      LAYER M5 ;
        RECT  30.864 25.836 30.888 25.92 ;
    END
  END t1a[74]
  PIN t1a[75]
    DIRECTION INPUT ;
    USE SIGNAL ;
    PORT
      LAYER M5 ;
        RECT  30.96 25.836 30.984 25.92 ;
    END
  END t1a[75]
  PIN t1a[76]
    DIRECTION INPUT ;
    USE SIGNAL ;
    PORT
      LAYER M5 ;
        RECT  31.056 25.836 31.08 25.92 ;
    END
  END t1a[76]
  PIN t1a[77]
    DIRECTION INPUT ;
    USE SIGNAL ;
    PORT
      LAYER M5 ;
        RECT  31.152 25.836 31.176 25.92 ;
    END
  END t1a[77]
  PIN t1a[78]
    DIRECTION INPUT ;
    USE SIGNAL ;
    PORT
      LAYER M5 ;
        RECT  31.248 25.836 31.272 25.92 ;
    END
  END t1a[78]
  PIN t1a[79]
    DIRECTION INPUT ;
    USE SIGNAL ;
    PORT
      LAYER M5 ;
        RECT  31.344 25.836 31.368 25.92 ;
    END
  END t1a[79]
  PIN t1a[7]
    DIRECTION INPUT ;
    USE SIGNAL ;
    PORT
      LAYER M5 ;
        RECT  85.104 25.836 85.128 25.92 ;
    END
  END t1a[7]
  PIN t1a[80]
    DIRECTION INPUT ;
    USE SIGNAL ;
    PORT
      LAYER M5 ;
        RECT  31.44 25.836 31.464 25.92 ;
    END
  END t1a[80]
  PIN t1a[81]
    DIRECTION INPUT ;
    USE SIGNAL ;
    PORT
      LAYER M5 ;
        RECT  31.536 25.836 31.56 25.92 ;
    END
  END t1a[81]
  PIN t1a[82]
    DIRECTION INPUT ;
    USE SIGNAL ;
    PORT
      LAYER M5 ;
        RECT  31.632 25.836 31.656 25.92 ;
    END
  END t1a[82]
  PIN t1a[83]
    DIRECTION INPUT ;
    USE SIGNAL ;
    PORT
      LAYER M5 ;
        RECT  31.728 25.836 31.752 25.92 ;
    END
  END t1a[83]
  PIN t1a[84]
    DIRECTION INPUT ;
    USE SIGNAL ;
    PORT
      LAYER M5 ;
        RECT  31.824 25.836 31.848 25.92 ;
    END
  END t1a[84]
  PIN t1a[85]
    DIRECTION INPUT ;
    USE SIGNAL ;
    PORT
      LAYER M5 ;
        RECT  31.92 25.836 31.944 25.92 ;
    END
  END t1a[85]
  PIN t1a[86]
    DIRECTION INPUT ;
    USE SIGNAL ;
    PORT
      LAYER M5 ;
        RECT  32.016 25.836 32.04 25.92 ;
    END
  END t1a[86]
  PIN t1a[87]
    DIRECTION INPUT ;
    USE SIGNAL ;
    PORT
      LAYER M5 ;
        RECT  32.112 25.836 32.136 25.92 ;
    END
  END t1a[87]
  PIN t1a[88]
    DIRECTION INPUT ;
    USE SIGNAL ;
    PORT
      LAYER M5 ;
        RECT  32.208 25.836 32.232 25.92 ;
    END
  END t1a[88]
  PIN t1a[89]
    DIRECTION INPUT ;
    USE SIGNAL ;
    PORT
      LAYER M5 ;
        RECT  32.304 25.836 32.328 25.92 ;
    END
  END t1a[89]
  PIN t1a[8]
    DIRECTION INPUT ;
    USE SIGNAL ;
    PORT
      LAYER M5 ;
        RECT  85.2 25.836 85.224 25.92 ;
    END
  END t1a[8]
  PIN t1a[90]
    DIRECTION INPUT ;
    USE SIGNAL ;
    PORT
      LAYER M5 ;
        RECT  32.4 25.836 32.424 25.92 ;
    END
  END t1a[90]
  PIN t1a[91]
    DIRECTION INPUT ;
    USE SIGNAL ;
    PORT
      LAYER M5 ;
        RECT  32.496 25.836 32.52 25.92 ;
    END
  END t1a[91]
  PIN t1a[92]
    DIRECTION INPUT ;
    USE SIGNAL ;
    PORT
      LAYER M5 ;
        RECT  32.592 25.836 32.616 25.92 ;
    END
  END t1a[92]
  PIN t1a[93]
    DIRECTION INPUT ;
    USE SIGNAL ;
    PORT
      LAYER M5 ;
        RECT  32.688 25.836 32.712 25.92 ;
    END
  END t1a[93]
  PIN t1a[94]
    DIRECTION INPUT ;
    USE SIGNAL ;
    PORT
      LAYER M5 ;
        RECT  32.784 25.836 32.808 25.92 ;
    END
  END t1a[94]
  PIN t1a[95]
    DIRECTION INPUT ;
    USE SIGNAL ;
    PORT
      LAYER M5 ;
        RECT  32.88 25.836 32.904 25.92 ;
    END
  END t1a[95]
  PIN t1a[96]
    DIRECTION INPUT ;
    USE SIGNAL ;
    PORT
      LAYER M5 ;
        RECT  36.048 25.836 36.072 25.92 ;
    END
  END t1a[96]
  PIN t1a[97]
    DIRECTION INPUT ;
    USE SIGNAL ;
    PORT
      LAYER M5 ;
        RECT  36.144 25.836 36.168 25.92 ;
    END
  END t1a[97]
  PIN t1a[98]
    DIRECTION INPUT ;
    USE SIGNAL ;
    PORT
      LAYER M5 ;
        RECT  36.24 25.836 36.264 25.92 ;
    END
  END t1a[98]
  PIN t1a[99]
    DIRECTION INPUT ;
    USE SIGNAL ;
    PORT
      LAYER M5 ;
        RECT  36.336 25.836 36.36 25.92 ;
    END
  END t1a[99]
  PIN t1a[9]
    DIRECTION INPUT ;
    USE SIGNAL ;
    PORT
      LAYER M5 ;
        RECT  85.296 25.836 85.32 25.92 ;
    END
  END t1a[9]
  PIN t1b[0]
    DIRECTION INPUT ;
    USE SIGNAL ;
    PORT
      LAYER M5 ;
        RECT  67.632 0 67.656 0.084 ;
    END
  END t1b[0]
  PIN t1b[100]
    DIRECTION INPUT ;
    USE SIGNAL ;
    PORT
      LAYER M5 ;
        RECT  51.888 0 51.912 0.084 ;
    END
  END t1b[100]
  PIN t1b[101]
    DIRECTION INPUT ;
    USE SIGNAL ;
    PORT
      LAYER M5 ;
        RECT  51.984 0 52.008 0.084 ;
    END
  END t1b[101]
  PIN t1b[102]
    DIRECTION INPUT ;
    USE SIGNAL ;
    PORT
      LAYER M5 ;
        RECT  52.08 0 52.104 0.084 ;
    END
  END t1b[102]
  PIN t1b[103]
    DIRECTION INPUT ;
    USE SIGNAL ;
    PORT
      LAYER M5 ;
        RECT  52.176 0 52.2 0.084 ;
    END
  END t1b[103]
  PIN t1b[104]
    DIRECTION INPUT ;
    USE SIGNAL ;
    PORT
      LAYER M5 ;
        RECT  52.272 0 52.296 0.084 ;
    END
  END t1b[104]
  PIN t1b[105]
    DIRECTION INPUT ;
    USE SIGNAL ;
    PORT
      LAYER M5 ;
        RECT  52.368 0 52.392 0.084 ;
    END
  END t1b[105]
  PIN t1b[106]
    DIRECTION INPUT ;
    USE SIGNAL ;
    PORT
      LAYER M5 ;
        RECT  52.464 0 52.488 0.084 ;
    END
  END t1b[106]
  PIN t1b[107]
    DIRECTION INPUT ;
    USE SIGNAL ;
    PORT
      LAYER M5 ;
        RECT  52.56 0 52.584 0.084 ;
    END
  END t1b[107]
  PIN t1b[108]
    DIRECTION INPUT ;
    USE SIGNAL ;
    PORT
      LAYER M5 ;
        RECT  52.656 0 52.68 0.084 ;
    END
  END t1b[108]
  PIN t1b[109]
    DIRECTION INPUT ;
    USE SIGNAL ;
    PORT
      LAYER M5 ;
        RECT  52.752 0 52.776 0.084 ;
    END
  END t1b[109]
  PIN t1b[10]
    DIRECTION INPUT ;
    USE SIGNAL ;
    PORT
      LAYER M5 ;
        RECT  68.592 0 68.616 0.084 ;
    END
  END t1b[10]
  PIN t1b[110]
    DIRECTION INPUT ;
    USE SIGNAL ;
    PORT
      LAYER M5 ;
        RECT  52.848 0 52.872 0.084 ;
    END
  END t1b[110]
  PIN t1b[111]
    DIRECTION INPUT ;
    USE SIGNAL ;
    PORT
      LAYER M5 ;
        RECT  52.944 0 52.968 0.084 ;
    END
  END t1b[111]
  PIN t1b[112]
    DIRECTION INPUT ;
    USE SIGNAL ;
    PORT
      LAYER M5 ;
        RECT  53.04 0 53.064 0.084 ;
    END
  END t1b[112]
  PIN t1b[113]
    DIRECTION INPUT ;
    USE SIGNAL ;
    PORT
      LAYER M5 ;
        RECT  53.136 0 53.16 0.084 ;
    END
  END t1b[113]
  PIN t1b[114]
    DIRECTION INPUT ;
    USE SIGNAL ;
    PORT
      LAYER M5 ;
        RECT  53.232 0 53.256 0.084 ;
    END
  END t1b[114]
  PIN t1b[115]
    DIRECTION INPUT ;
    USE SIGNAL ;
    PORT
      LAYER M5 ;
        RECT  53.328 0 53.352 0.084 ;
    END
  END t1b[115]
  PIN t1b[116]
    DIRECTION INPUT ;
    USE SIGNAL ;
    PORT
      LAYER M5 ;
        RECT  53.424 0 53.448 0.084 ;
    END
  END t1b[116]
  PIN t1b[117]
    DIRECTION INPUT ;
    USE SIGNAL ;
    PORT
      LAYER M5 ;
        RECT  53.52 0 53.544 0.084 ;
    END
  END t1b[117]
  PIN t1b[118]
    DIRECTION INPUT ;
    USE SIGNAL ;
    PORT
      LAYER M5 ;
        RECT  53.616 0 53.64 0.084 ;
    END
  END t1b[118]
  PIN t1b[119]
    DIRECTION INPUT ;
    USE SIGNAL ;
    PORT
      LAYER M5 ;
        RECT  53.712 0 53.736 0.084 ;
    END
  END t1b[119]
  PIN t1b[11]
    DIRECTION INPUT ;
    USE SIGNAL ;
    PORT
      LAYER M5 ;
        RECT  68.688 0 68.712 0.084 ;
    END
  END t1b[11]
  PIN t1b[120]
    DIRECTION INPUT ;
    USE SIGNAL ;
    PORT
      LAYER M5 ;
        RECT  53.808 0 53.832 0.084 ;
    END
  END t1b[120]
  PIN t1b[121]
    DIRECTION INPUT ;
    USE SIGNAL ;
    PORT
      LAYER M5 ;
        RECT  53.904 0 53.928 0.084 ;
    END
  END t1b[121]
  PIN t1b[122]
    DIRECTION INPUT ;
    USE SIGNAL ;
    PORT
      LAYER M5 ;
        RECT  54 0 54.024 0.084 ;
    END
  END t1b[122]
  PIN t1b[123]
    DIRECTION INPUT ;
    USE SIGNAL ;
    PORT
      LAYER M5 ;
        RECT  54.096 0 54.12 0.084 ;
    END
  END t1b[123]
  PIN t1b[124]
    DIRECTION INPUT ;
    USE SIGNAL ;
    PORT
      LAYER M5 ;
        RECT  54.192 0 54.216 0.084 ;
    END
  END t1b[124]
  PIN t1b[125]
    DIRECTION INPUT ;
    USE SIGNAL ;
    PORT
      LAYER M5 ;
        RECT  54.288 0 54.312 0.084 ;
    END
  END t1b[125]
  PIN t1b[126]
    DIRECTION INPUT ;
    USE SIGNAL ;
    PORT
      LAYER M5 ;
        RECT  54.384 0 54.408 0.084 ;
    END
  END t1b[126]
  PIN t1b[127]
    DIRECTION INPUT ;
    USE SIGNAL ;
    PORT
      LAYER M5 ;
        RECT  70.608 0 70.632 0.084 ;
    END
  END t1b[127]
  PIN t1b[128]
    DIRECTION INPUT ;
    USE SIGNAL ;
    PORT
      LAYER M5 ;
        RECT  70.704 0 70.728 0.084 ;
    END
  END t1b[128]
  PIN t1b[129]
    DIRECTION INPUT ;
    USE SIGNAL ;
    PORT
      LAYER M5 ;
        RECT  70.8 0 70.824 0.084 ;
    END
  END t1b[129]
  PIN t1b[12]
    DIRECTION INPUT ;
    USE SIGNAL ;
    PORT
      LAYER M5 ;
        RECT  68.784 0 68.808 0.084 ;
    END
  END t1b[12]
  PIN t1b[130]
    DIRECTION INPUT ;
    USE SIGNAL ;
    PORT
      LAYER M5 ;
        RECT  70.896 0 70.92 0.084 ;
    END
  END t1b[130]
  PIN t1b[131]
    DIRECTION INPUT ;
    USE SIGNAL ;
    PORT
      LAYER M5 ;
        RECT  70.992 0 71.016 0.084 ;
    END
  END t1b[131]
  PIN t1b[132]
    DIRECTION INPUT ;
    USE SIGNAL ;
    PORT
      LAYER M5 ;
        RECT  71.088 0 71.112 0.084 ;
    END
  END t1b[132]
  PIN t1b[133]
    DIRECTION INPUT ;
    USE SIGNAL ;
    PORT
      LAYER M5 ;
        RECT  71.184 0 71.208 0.084 ;
    END
  END t1b[133]
  PIN t1b[134]
    DIRECTION INPUT ;
    USE SIGNAL ;
    PORT
      LAYER M5 ;
        RECT  71.28 0 71.304 0.084 ;
    END
  END t1b[134]
  PIN t1b[135]
    DIRECTION INPUT ;
    USE SIGNAL ;
    PORT
      LAYER M5 ;
        RECT  71.376 0 71.4 0.084 ;
    END
  END t1b[135]
  PIN t1b[136]
    DIRECTION INPUT ;
    USE SIGNAL ;
    PORT
      LAYER M5 ;
        RECT  71.472 0 71.496 0.084 ;
    END
  END t1b[136]
  PIN t1b[137]
    DIRECTION INPUT ;
    USE SIGNAL ;
    PORT
      LAYER M5 ;
        RECT  71.568 0 71.592 0.084 ;
    END
  END t1b[137]
  PIN t1b[138]
    DIRECTION INPUT ;
    USE SIGNAL ;
    PORT
      LAYER M5 ;
        RECT  71.664 0 71.688 0.084 ;
    END
  END t1b[138]
  PIN t1b[139]
    DIRECTION INPUT ;
    USE SIGNAL ;
    PORT
      LAYER M5 ;
        RECT  71.76 0 71.784 0.084 ;
    END
  END t1b[139]
  PIN t1b[13]
    DIRECTION INPUT ;
    USE SIGNAL ;
    PORT
      LAYER M5 ;
        RECT  68.88 0 68.904 0.084 ;
    END
  END t1b[13]
  PIN t1b[140]
    DIRECTION INPUT ;
    USE SIGNAL ;
    PORT
      LAYER M5 ;
        RECT  71.856 0 71.88 0.084 ;
    END
  END t1b[140]
  PIN t1b[141]
    DIRECTION INPUT ;
    USE SIGNAL ;
    PORT
      LAYER M5 ;
        RECT  71.952 0 71.976 0.084 ;
    END
  END t1b[141]
  PIN t1b[142]
    DIRECTION INPUT ;
    USE SIGNAL ;
    PORT
      LAYER M5 ;
        RECT  72.048 0 72.072 0.084 ;
    END
  END t1b[142]
  PIN t1b[143]
    DIRECTION INPUT ;
    USE SIGNAL ;
    PORT
      LAYER M5 ;
        RECT  72.144 0 72.168 0.084 ;
    END
  END t1b[143]
  PIN t1b[144]
    DIRECTION INPUT ;
    USE SIGNAL ;
    PORT
      LAYER M5 ;
        RECT  72.24 0 72.264 0.084 ;
    END
  END t1b[144]
  PIN t1b[145]
    DIRECTION INPUT ;
    USE SIGNAL ;
    PORT
      LAYER M5 ;
        RECT  72.336 0 72.36 0.084 ;
    END
  END t1b[145]
  PIN t1b[146]
    DIRECTION INPUT ;
    USE SIGNAL ;
    PORT
      LAYER M5 ;
        RECT  72.432 0 72.456 0.084 ;
    END
  END t1b[146]
  PIN t1b[147]
    DIRECTION INPUT ;
    USE SIGNAL ;
    PORT
      LAYER M5 ;
        RECT  72.528 0 72.552 0.084 ;
    END
  END t1b[147]
  PIN t1b[148]
    DIRECTION INPUT ;
    USE SIGNAL ;
    PORT
      LAYER M5 ;
        RECT  72.624 0 72.648 0.084 ;
    END
  END t1b[148]
  PIN t1b[149]
    DIRECTION INPUT ;
    USE SIGNAL ;
    PORT
      LAYER M5 ;
        RECT  72.72 0 72.744 0.084 ;
    END
  END t1b[149]
  PIN t1b[14]
    DIRECTION INPUT ;
    USE SIGNAL ;
    PORT
      LAYER M5 ;
        RECT  68.976 0 69 0.084 ;
    END
  END t1b[14]
  PIN t1b[150]
    DIRECTION INPUT ;
    USE SIGNAL ;
    PORT
      LAYER M5 ;
        RECT  72.816 0 72.84 0.084 ;
    END
  END t1b[150]
  PIN t1b[151]
    DIRECTION INPUT ;
    USE SIGNAL ;
    PORT
      LAYER M5 ;
        RECT  72.912 0 72.936 0.084 ;
    END
  END t1b[151]
  PIN t1b[152]
    DIRECTION INPUT ;
    USE SIGNAL ;
    PORT
      LAYER M5 ;
        RECT  73.008 0 73.032 0.084 ;
    END
  END t1b[152]
  PIN t1b[153]
    DIRECTION INPUT ;
    USE SIGNAL ;
    PORT
      LAYER M5 ;
        RECT  73.104 0 73.128 0.084 ;
    END
  END t1b[153]
  PIN t1b[154]
    DIRECTION INPUT ;
    USE SIGNAL ;
    PORT
      LAYER M5 ;
        RECT  73.2 0 73.224 0.084 ;
    END
  END t1b[154]
  PIN t1b[155]
    DIRECTION INPUT ;
    USE SIGNAL ;
    PORT
      LAYER M5 ;
        RECT  73.296 0 73.32 0.084 ;
    END
  END t1b[155]
  PIN t1b[156]
    DIRECTION INPUT ;
    USE SIGNAL ;
    PORT
      LAYER M5 ;
        RECT  73.392 0 73.416 0.084 ;
    END
  END t1b[156]
  PIN t1b[157]
    DIRECTION INPUT ;
    USE SIGNAL ;
    PORT
      LAYER M5 ;
        RECT  73.488 0 73.512 0.084 ;
    END
  END t1b[157]
  PIN t1b[158]
    DIRECTION INPUT ;
    USE SIGNAL ;
    PORT
      LAYER M5 ;
        RECT  73.584 0 73.608 0.084 ;
    END
  END t1b[158]
  PIN t1b[159]
    DIRECTION INPUT ;
    USE SIGNAL ;
    PORT
      LAYER M5 ;
        RECT  64.464 0 64.488 0.084 ;
    END
  END t1b[159]
  PIN t1b[15]
    DIRECTION INPUT ;
    USE SIGNAL ;
    PORT
      LAYER M5 ;
        RECT  69.072 0 69.096 0.084 ;
    END
  END t1b[15]
  PIN t1b[160]
    DIRECTION INPUT ;
    USE SIGNAL ;
    PORT
      LAYER M5 ;
        RECT  64.56 0 64.584 0.084 ;
    END
  END t1b[160]
  PIN t1b[161]
    DIRECTION INPUT ;
    USE SIGNAL ;
    PORT
      LAYER M5 ;
        RECT  64.656 0 64.68 0.084 ;
    END
  END t1b[161]
  PIN t1b[162]
    DIRECTION INPUT ;
    USE SIGNAL ;
    PORT
      LAYER M5 ;
        RECT  64.752 0 64.776 0.084 ;
    END
  END t1b[162]
  PIN t1b[163]
    DIRECTION INPUT ;
    USE SIGNAL ;
    PORT
      LAYER M5 ;
        RECT  64.848 0 64.872 0.084 ;
    END
  END t1b[163]
  PIN t1b[164]
    DIRECTION INPUT ;
    USE SIGNAL ;
    PORT
      LAYER M5 ;
        RECT  64.944 0 64.968 0.084 ;
    END
  END t1b[164]
  PIN t1b[165]
    DIRECTION INPUT ;
    USE SIGNAL ;
    PORT
      LAYER M5 ;
        RECT  65.04 0 65.064 0.084 ;
    END
  END t1b[165]
  PIN t1b[166]
    DIRECTION INPUT ;
    USE SIGNAL ;
    PORT
      LAYER M5 ;
        RECT  65.136 0 65.16 0.084 ;
    END
  END t1b[166]
  PIN t1b[167]
    DIRECTION INPUT ;
    USE SIGNAL ;
    PORT
      LAYER M5 ;
        RECT  65.232 0 65.256 0.084 ;
    END
  END t1b[167]
  PIN t1b[168]
    DIRECTION INPUT ;
    USE SIGNAL ;
    PORT
      LAYER M5 ;
        RECT  65.328 0 65.352 0.084 ;
    END
  END t1b[168]
  PIN t1b[169]
    DIRECTION INPUT ;
    USE SIGNAL ;
    PORT
      LAYER M5 ;
        RECT  65.424 0 65.448 0.084 ;
    END
  END t1b[169]
  PIN t1b[16]
    DIRECTION INPUT ;
    USE SIGNAL ;
    PORT
      LAYER M5 ;
        RECT  69.168 0 69.192 0.084 ;
    END
  END t1b[16]
  PIN t1b[170]
    DIRECTION INPUT ;
    USE SIGNAL ;
    PORT
      LAYER M5 ;
        RECT  65.52 0 65.544 0.084 ;
    END
  END t1b[170]
  PIN t1b[171]
    DIRECTION INPUT ;
    USE SIGNAL ;
    PORT
      LAYER M5 ;
        RECT  65.616 0 65.64 0.084 ;
    END
  END t1b[171]
  PIN t1b[172]
    DIRECTION INPUT ;
    USE SIGNAL ;
    PORT
      LAYER M5 ;
        RECT  65.712 0 65.736 0.084 ;
    END
  END t1b[172]
  PIN t1b[173]
    DIRECTION INPUT ;
    USE SIGNAL ;
    PORT
      LAYER M5 ;
        RECT  65.808 0 65.832 0.084 ;
    END
  END t1b[173]
  PIN t1b[174]
    DIRECTION INPUT ;
    USE SIGNAL ;
    PORT
      LAYER M5 ;
        RECT  65.904 0 65.928 0.084 ;
    END
  END t1b[174]
  PIN t1b[175]
    DIRECTION INPUT ;
    USE SIGNAL ;
    PORT
      LAYER M5 ;
        RECT  66 0 66.024 0.084 ;
    END
  END t1b[175]
  PIN t1b[176]
    DIRECTION INPUT ;
    USE SIGNAL ;
    PORT
      LAYER M5 ;
        RECT  66.096 0 66.12 0.084 ;
    END
  END t1b[176]
  PIN t1b[177]
    DIRECTION INPUT ;
    USE SIGNAL ;
    PORT
      LAYER M5 ;
        RECT  66.192 0 66.216 0.084 ;
    END
  END t1b[177]
  PIN t1b[178]
    DIRECTION INPUT ;
    USE SIGNAL ;
    PORT
      LAYER M5 ;
        RECT  66.288 0 66.312 0.084 ;
    END
  END t1b[178]
  PIN t1b[179]
    DIRECTION INPUT ;
    USE SIGNAL ;
    PORT
      LAYER M5 ;
        RECT  66.384 0 66.408 0.084 ;
    END
  END t1b[179]
  PIN t1b[17]
    DIRECTION INPUT ;
    USE SIGNAL ;
    PORT
      LAYER M5 ;
        RECT  69.264 0 69.288 0.084 ;
    END
  END t1b[17]
  PIN t1b[180]
    DIRECTION INPUT ;
    USE SIGNAL ;
    PORT
      LAYER M5 ;
        RECT  66.48 0 66.504 0.084 ;
    END
  END t1b[180]
  PIN t1b[181]
    DIRECTION INPUT ;
    USE SIGNAL ;
    PORT
      LAYER M5 ;
        RECT  66.576 0 66.6 0.084 ;
    END
  END t1b[181]
  PIN t1b[182]
    DIRECTION INPUT ;
    USE SIGNAL ;
    PORT
      LAYER M5 ;
        RECT  66.672 0 66.696 0.084 ;
    END
  END t1b[182]
  PIN t1b[183]
    DIRECTION INPUT ;
    USE SIGNAL ;
    PORT
      LAYER M5 ;
        RECT  66.768 0 66.792 0.084 ;
    END
  END t1b[183]
  PIN t1b[184]
    DIRECTION INPUT ;
    USE SIGNAL ;
    PORT
      LAYER M5 ;
        RECT  66.864 0 66.888 0.084 ;
    END
  END t1b[184]
  PIN t1b[185]
    DIRECTION INPUT ;
    USE SIGNAL ;
    PORT
      LAYER M5 ;
        RECT  66.96 0 66.984 0.084 ;
    END
  END t1b[185]
  PIN t1b[186]
    DIRECTION INPUT ;
    USE SIGNAL ;
    PORT
      LAYER M5 ;
        RECT  67.056 0 67.08 0.084 ;
    END
  END t1b[186]
  PIN t1b[187]
    DIRECTION INPUT ;
    USE SIGNAL ;
    PORT
      LAYER M5 ;
        RECT  67.152 0 67.176 0.084 ;
    END
  END t1b[187]
  PIN t1b[188]
    DIRECTION INPUT ;
    USE SIGNAL ;
    PORT
      LAYER M5 ;
        RECT  67.248 0 67.272 0.084 ;
    END
  END t1b[188]
  PIN t1b[189]
    DIRECTION INPUT ;
    USE SIGNAL ;
    PORT
      LAYER M5 ;
        RECT  67.344 0 67.368 0.084 ;
    END
  END t1b[189]
  PIN t1b[18]
    DIRECTION INPUT ;
    USE SIGNAL ;
    PORT
      LAYER M5 ;
        RECT  69.36 0 69.384 0.084 ;
    END
  END t1b[18]
  PIN t1b[190]
    DIRECTION INPUT ;
    USE SIGNAL ;
    PORT
      LAYER M5 ;
        RECT  67.44 0 67.464 0.084 ;
    END
  END t1b[190]
  PIN t1b[191]
    DIRECTION INPUT ;
    USE SIGNAL ;
    PORT
      LAYER M5 ;
        RECT  39.12 0 39.144 0.084 ;
    END
  END t1b[191]
  PIN t1b[192]
    DIRECTION INPUT ;
    USE SIGNAL ;
    PORT
      LAYER M5 ;
        RECT  39.216 0 39.24 0.084 ;
    END
  END t1b[192]
  PIN t1b[193]
    DIRECTION INPUT ;
    USE SIGNAL ;
    PORT
      LAYER M5 ;
        RECT  39.312 0 39.336 0.084 ;
    END
  END t1b[193]
  PIN t1b[194]
    DIRECTION INPUT ;
    USE SIGNAL ;
    PORT
      LAYER M5 ;
        RECT  39.408 0 39.432 0.084 ;
    END
  END t1b[194]
  PIN t1b[195]
    DIRECTION INPUT ;
    USE SIGNAL ;
    PORT
      LAYER M5 ;
        RECT  39.504 0 39.528 0.084 ;
    END
  END t1b[195]
  PIN t1b[196]
    DIRECTION INPUT ;
    USE SIGNAL ;
    PORT
      LAYER M5 ;
        RECT  39.6 0 39.624 0.084 ;
    END
  END t1b[196]
  PIN t1b[197]
    DIRECTION INPUT ;
    USE SIGNAL ;
    PORT
      LAYER M5 ;
        RECT  39.696 0 39.72 0.084 ;
    END
  END t1b[197]
  PIN t1b[198]
    DIRECTION INPUT ;
    USE SIGNAL ;
    PORT
      LAYER M5 ;
        RECT  39.792 0 39.816 0.084 ;
    END
  END t1b[198]
  PIN t1b[199]
    DIRECTION INPUT ;
    USE SIGNAL ;
    PORT
      LAYER M5 ;
        RECT  39.888 0 39.912 0.084 ;
    END
  END t1b[199]
  PIN t1b[19]
    DIRECTION INPUT ;
    USE SIGNAL ;
    PORT
      LAYER M5 ;
        RECT  69.456 0 69.48 0.084 ;
    END
  END t1b[19]
  PIN t1b[1]
    DIRECTION INPUT ;
    USE SIGNAL ;
    PORT
      LAYER M5 ;
        RECT  67.728 0 67.752 0.084 ;
    END
  END t1b[1]
  PIN t1b[200]
    DIRECTION INPUT ;
    USE SIGNAL ;
    PORT
      LAYER M5 ;
        RECT  39.984 0 40.008 0.084 ;
    END
  END t1b[200]
  PIN t1b[201]
    DIRECTION INPUT ;
    USE SIGNAL ;
    PORT
      LAYER M5 ;
        RECT  40.08 0 40.104 0.084 ;
    END
  END t1b[201]
  PIN t1b[202]
    DIRECTION INPUT ;
    USE SIGNAL ;
    PORT
      LAYER M5 ;
        RECT  40.176 0 40.2 0.084 ;
    END
  END t1b[202]
  PIN t1b[203]
    DIRECTION INPUT ;
    USE SIGNAL ;
    PORT
      LAYER M5 ;
        RECT  40.272 0 40.296 0.084 ;
    END
  END t1b[203]
  PIN t1b[204]
    DIRECTION INPUT ;
    USE SIGNAL ;
    PORT
      LAYER M5 ;
        RECT  40.368 0 40.392 0.084 ;
    END
  END t1b[204]
  PIN t1b[205]
    DIRECTION INPUT ;
    USE SIGNAL ;
    PORT
      LAYER M5 ;
        RECT  40.464 0 40.488 0.084 ;
    END
  END t1b[205]
  PIN t1b[206]
    DIRECTION INPUT ;
    USE SIGNAL ;
    PORT
      LAYER M5 ;
        RECT  40.56 0 40.584 0.084 ;
    END
  END t1b[206]
  PIN t1b[207]
    DIRECTION INPUT ;
    USE SIGNAL ;
    PORT
      LAYER M5 ;
        RECT  40.656 0 40.68 0.084 ;
    END
  END t1b[207]
  PIN t1b[208]
    DIRECTION INPUT ;
    USE SIGNAL ;
    PORT
      LAYER M5 ;
        RECT  40.752 0 40.776 0.084 ;
    END
  END t1b[208]
  PIN t1b[209]
    DIRECTION INPUT ;
    USE SIGNAL ;
    PORT
      LAYER M5 ;
        RECT  40.848 0 40.872 0.084 ;
    END
  END t1b[209]
  PIN t1b[20]
    DIRECTION INPUT ;
    USE SIGNAL ;
    PORT
      LAYER M5 ;
        RECT  69.552 0 69.576 0.084 ;
    END
  END t1b[20]
  PIN t1b[210]
    DIRECTION INPUT ;
    USE SIGNAL ;
    PORT
      LAYER M5 ;
        RECT  40.944 0 40.968 0.084 ;
    END
  END t1b[210]
  PIN t1b[211]
    DIRECTION INPUT ;
    USE SIGNAL ;
    PORT
      LAYER M5 ;
        RECT  41.04 0 41.064 0.084 ;
    END
  END t1b[211]
  PIN t1b[212]
    DIRECTION INPUT ;
    USE SIGNAL ;
    PORT
      LAYER M5 ;
        RECT  41.136 0 41.16 0.084 ;
    END
  END t1b[212]
  PIN t1b[213]
    DIRECTION INPUT ;
    USE SIGNAL ;
    PORT
      LAYER M5 ;
        RECT  41.232 0 41.256 0.084 ;
    END
  END t1b[213]
  PIN t1b[214]
    DIRECTION INPUT ;
    USE SIGNAL ;
    PORT
      LAYER M5 ;
        RECT  41.328 0 41.352 0.084 ;
    END
  END t1b[214]
  PIN t1b[215]
    DIRECTION INPUT ;
    USE SIGNAL ;
    PORT
      LAYER M5 ;
        RECT  41.424 0 41.448 0.084 ;
    END
  END t1b[215]
  PIN t1b[216]
    DIRECTION INPUT ;
    USE SIGNAL ;
    PORT
      LAYER M5 ;
        RECT  41.52 0 41.544 0.084 ;
    END
  END t1b[216]
  PIN t1b[217]
    DIRECTION INPUT ;
    USE SIGNAL ;
    PORT
      LAYER M5 ;
        RECT  41.616 0 41.64 0.084 ;
    END
  END t1b[217]
  PIN t1b[218]
    DIRECTION INPUT ;
    USE SIGNAL ;
    PORT
      LAYER M5 ;
        RECT  41.712 0 41.736 0.084 ;
    END
  END t1b[218]
  PIN t1b[219]
    DIRECTION INPUT ;
    USE SIGNAL ;
    PORT
      LAYER M5 ;
        RECT  41.808 0 41.832 0.084 ;
    END
  END t1b[219]
  PIN t1b[21]
    DIRECTION INPUT ;
    USE SIGNAL ;
    PORT
      LAYER M5 ;
        RECT  69.648 0 69.672 0.084 ;
    END
  END t1b[21]
  PIN t1b[220]
    DIRECTION INPUT ;
    USE SIGNAL ;
    PORT
      LAYER M5 ;
        RECT  41.904 0 41.928 0.084 ;
    END
  END t1b[220]
  PIN t1b[221]
    DIRECTION INPUT ;
    USE SIGNAL ;
    PORT
      LAYER M5 ;
        RECT  42 0 42.024 0.084 ;
    END
  END t1b[221]
  PIN t1b[222]
    DIRECTION INPUT ;
    USE SIGNAL ;
    PORT
      LAYER M5 ;
        RECT  42.096 0 42.12 0.084 ;
    END
  END t1b[222]
  PIN t1b[223]
    DIRECTION INPUT ;
    USE SIGNAL ;
    PORT
      LAYER M5 ;
        RECT  45.264 0 45.288 0.084 ;
    END
  END t1b[223]
  PIN t1b[224]
    DIRECTION INPUT ;
    USE SIGNAL ;
    PORT
      LAYER M5 ;
        RECT  45.36 0 45.384 0.084 ;
    END
  END t1b[224]
  PIN t1b[225]
    DIRECTION INPUT ;
    USE SIGNAL ;
    PORT
      LAYER M5 ;
        RECT  45.456 0 45.48 0.084 ;
    END
  END t1b[225]
  PIN t1b[226]
    DIRECTION INPUT ;
    USE SIGNAL ;
    PORT
      LAYER M5 ;
        RECT  45.552 0 45.576 0.084 ;
    END
  END t1b[226]
  PIN t1b[227]
    DIRECTION INPUT ;
    USE SIGNAL ;
    PORT
      LAYER M5 ;
        RECT  45.648 0 45.672 0.084 ;
    END
  END t1b[227]
  PIN t1b[228]
    DIRECTION INPUT ;
    USE SIGNAL ;
    PORT
      LAYER M5 ;
        RECT  45.744 0 45.768 0.084 ;
    END
  END t1b[228]
  PIN t1b[229]
    DIRECTION INPUT ;
    USE SIGNAL ;
    PORT
      LAYER M5 ;
        RECT  45.84 0 45.864 0.084 ;
    END
  END t1b[229]
  PIN t1b[22]
    DIRECTION INPUT ;
    USE SIGNAL ;
    PORT
      LAYER M5 ;
        RECT  69.744 0 69.768 0.084 ;
    END
  END t1b[22]
  PIN t1b[230]
    DIRECTION INPUT ;
    USE SIGNAL ;
    PORT
      LAYER M5 ;
        RECT  45.936 0 45.96 0.084 ;
    END
  END t1b[230]
  PIN t1b[231]
    DIRECTION INPUT ;
    USE SIGNAL ;
    PORT
      LAYER M5 ;
        RECT  46.032 0 46.056 0.084 ;
    END
  END t1b[231]
  PIN t1b[232]
    DIRECTION INPUT ;
    USE SIGNAL ;
    PORT
      LAYER M5 ;
        RECT  46.128 0 46.152 0.084 ;
    END
  END t1b[232]
  PIN t1b[233]
    DIRECTION INPUT ;
    USE SIGNAL ;
    PORT
      LAYER M5 ;
        RECT  46.224 0 46.248 0.084 ;
    END
  END t1b[233]
  PIN t1b[234]
    DIRECTION INPUT ;
    USE SIGNAL ;
    PORT
      LAYER M5 ;
        RECT  46.32 0 46.344 0.084 ;
    END
  END t1b[234]
  PIN t1b[235]
    DIRECTION INPUT ;
    USE SIGNAL ;
    PORT
      LAYER M5 ;
        RECT  46.416 0 46.44 0.084 ;
    END
  END t1b[235]
  PIN t1b[236]
    DIRECTION INPUT ;
    USE SIGNAL ;
    PORT
      LAYER M5 ;
        RECT  46.512 0 46.536 0.084 ;
    END
  END t1b[236]
  PIN t1b[237]
    DIRECTION INPUT ;
    USE SIGNAL ;
    PORT
      LAYER M5 ;
        RECT  46.608 0 46.632 0.084 ;
    END
  END t1b[237]
  PIN t1b[238]
    DIRECTION INPUT ;
    USE SIGNAL ;
    PORT
      LAYER M5 ;
        RECT  46.704 0 46.728 0.084 ;
    END
  END t1b[238]
  PIN t1b[239]
    DIRECTION INPUT ;
    USE SIGNAL ;
    PORT
      LAYER M5 ;
        RECT  46.8 0 46.824 0.084 ;
    END
  END t1b[239]
  PIN t1b[23]
    DIRECTION INPUT ;
    USE SIGNAL ;
    PORT
      LAYER M5 ;
        RECT  69.84 0 69.864 0.084 ;
    END
  END t1b[23]
  PIN t1b[240]
    DIRECTION INPUT ;
    USE SIGNAL ;
    PORT
      LAYER M5 ;
        RECT  46.896 0 46.92 0.084 ;
    END
  END t1b[240]
  PIN t1b[241]
    DIRECTION INPUT ;
    USE SIGNAL ;
    PORT
      LAYER M5 ;
        RECT  46.992 0 47.016 0.084 ;
    END
  END t1b[241]
  PIN t1b[242]
    DIRECTION INPUT ;
    USE SIGNAL ;
    PORT
      LAYER M5 ;
        RECT  47.088 0 47.112 0.084 ;
    END
  END t1b[242]
  PIN t1b[243]
    DIRECTION INPUT ;
    USE SIGNAL ;
    PORT
      LAYER M5 ;
        RECT  47.184 0 47.208 0.084 ;
    END
  END t1b[243]
  PIN t1b[244]
    DIRECTION INPUT ;
    USE SIGNAL ;
    PORT
      LAYER M5 ;
        RECT  47.28 0 47.304 0.084 ;
    END
  END t1b[244]
  PIN t1b[245]
    DIRECTION INPUT ;
    USE SIGNAL ;
    PORT
      LAYER M5 ;
        RECT  47.376 0 47.4 0.084 ;
    END
  END t1b[245]
  PIN t1b[246]
    DIRECTION INPUT ;
    USE SIGNAL ;
    PORT
      LAYER M5 ;
        RECT  47.472 0 47.496 0.084 ;
    END
  END t1b[246]
  PIN t1b[247]
    DIRECTION INPUT ;
    USE SIGNAL ;
    PORT
      LAYER M5 ;
        RECT  47.568 0 47.592 0.084 ;
    END
  END t1b[247]
  PIN t1b[248]
    DIRECTION INPUT ;
    USE SIGNAL ;
    PORT
      LAYER M5 ;
        RECT  47.664 0 47.688 0.084 ;
    END
  END t1b[248]
  PIN t1b[249]
    DIRECTION INPUT ;
    USE SIGNAL ;
    PORT
      LAYER M5 ;
        RECT  47.76 0 47.784 0.084 ;
    END
  END t1b[249]
  PIN t1b[24]
    DIRECTION INPUT ;
    USE SIGNAL ;
    PORT
      LAYER M5 ;
        RECT  69.936 0 69.96 0.084 ;
    END
  END t1b[24]
  PIN t1b[250]
    DIRECTION INPUT ;
    USE SIGNAL ;
    PORT
      LAYER M5 ;
        RECT  47.856 0 47.88 0.084 ;
    END
  END t1b[250]
  PIN t1b[251]
    DIRECTION INPUT ;
    USE SIGNAL ;
    PORT
      LAYER M5 ;
        RECT  47.952 0 47.976 0.084 ;
    END
  END t1b[251]
  PIN t1b[252]
    DIRECTION INPUT ;
    USE SIGNAL ;
    PORT
      LAYER M5 ;
        RECT  48.048 0 48.072 0.084 ;
    END
  END t1b[252]
  PIN t1b[253]
    DIRECTION INPUT ;
    USE SIGNAL ;
    PORT
      LAYER M5 ;
        RECT  48.144 0 48.168 0.084 ;
    END
  END t1b[253]
  PIN t1b[254]
    DIRECTION INPUT ;
    USE SIGNAL ;
    PORT
      LAYER M5 ;
        RECT  48.24 0 48.264 0.084 ;
    END
  END t1b[254]
  PIN t1b[255]
    DIRECTION INPUT ;
    USE SIGNAL ;
    PORT
      LAYER M5 ;
        RECT  61.392 0 61.416 0.084 ;
    END
  END t1b[255]
  PIN t1b[256]
    DIRECTION INPUT ;
    USE SIGNAL ;
    PORT
      LAYER M5 ;
        RECT  61.488 0 61.512 0.084 ;
    END
  END t1b[256]
  PIN t1b[257]
    DIRECTION INPUT ;
    USE SIGNAL ;
    PORT
      LAYER M5 ;
        RECT  61.584 0 61.608 0.084 ;
    END
  END t1b[257]
  PIN t1b[258]
    DIRECTION INPUT ;
    USE SIGNAL ;
    PORT
      LAYER M5 ;
        RECT  61.68 0 61.704 0.084 ;
    END
  END t1b[258]
  PIN t1b[259]
    DIRECTION INPUT ;
    USE SIGNAL ;
    PORT
      LAYER M5 ;
        RECT  61.776 0 61.8 0.084 ;
    END
  END t1b[259]
  PIN t1b[25]
    DIRECTION INPUT ;
    USE SIGNAL ;
    PORT
      LAYER M5 ;
        RECT  70.032 0 70.056 0.084 ;
    END
  END t1b[25]
  PIN t1b[260]
    DIRECTION INPUT ;
    USE SIGNAL ;
    PORT
      LAYER M5 ;
        RECT  61.872 0 61.896 0.084 ;
    END
  END t1b[260]
  PIN t1b[261]
    DIRECTION INPUT ;
    USE SIGNAL ;
    PORT
      LAYER M5 ;
        RECT  61.968 0 61.992 0.084 ;
    END
  END t1b[261]
  PIN t1b[262]
    DIRECTION INPUT ;
    USE SIGNAL ;
    PORT
      LAYER M5 ;
        RECT  62.064 0 62.088 0.084 ;
    END
  END t1b[262]
  PIN t1b[263]
    DIRECTION INPUT ;
    USE SIGNAL ;
    PORT
      LAYER M5 ;
        RECT  62.16 0 62.184 0.084 ;
    END
  END t1b[263]
  PIN t1b[264]
    DIRECTION INPUT ;
    USE SIGNAL ;
    PORT
      LAYER M5 ;
        RECT  62.256 0 62.28 0.084 ;
    END
  END t1b[264]
  PIN t1b[265]
    DIRECTION INPUT ;
    USE SIGNAL ;
    PORT
      LAYER M5 ;
        RECT  62.352 0 62.376 0.084 ;
    END
  END t1b[265]
  PIN t1b[266]
    DIRECTION INPUT ;
    USE SIGNAL ;
    PORT
      LAYER M5 ;
        RECT  62.448 0 62.472 0.084 ;
    END
  END t1b[266]
  PIN t1b[267]
    DIRECTION INPUT ;
    USE SIGNAL ;
    PORT
      LAYER M5 ;
        RECT  62.544 0 62.568 0.084 ;
    END
  END t1b[267]
  PIN t1b[268]
    DIRECTION INPUT ;
    USE SIGNAL ;
    PORT
      LAYER M5 ;
        RECT  62.64 0 62.664 0.084 ;
    END
  END t1b[268]
  PIN t1b[269]
    DIRECTION INPUT ;
    USE SIGNAL ;
    PORT
      LAYER M5 ;
        RECT  62.736 0 62.76 0.084 ;
    END
  END t1b[269]
  PIN t1b[26]
    DIRECTION INPUT ;
    USE SIGNAL ;
    PORT
      LAYER M5 ;
        RECT  70.128 0 70.152 0.084 ;
    END
  END t1b[26]
  PIN t1b[270]
    DIRECTION INPUT ;
    USE SIGNAL ;
    PORT
      LAYER M5 ;
        RECT  62.832 0 62.856 0.084 ;
    END
  END t1b[270]
  PIN t1b[271]
    DIRECTION INPUT ;
    USE SIGNAL ;
    PORT
      LAYER M5 ;
        RECT  62.928 0 62.952 0.084 ;
    END
  END t1b[271]
  PIN t1b[272]
    DIRECTION INPUT ;
    USE SIGNAL ;
    PORT
      LAYER M5 ;
        RECT  63.024 0 63.048 0.084 ;
    END
  END t1b[272]
  PIN t1b[273]
    DIRECTION INPUT ;
    USE SIGNAL ;
    PORT
      LAYER M5 ;
        RECT  63.12 0 63.144 0.084 ;
    END
  END t1b[273]
  PIN t1b[274]
    DIRECTION INPUT ;
    USE SIGNAL ;
    PORT
      LAYER M5 ;
        RECT  63.216 0 63.24 0.084 ;
    END
  END t1b[274]
  PIN t1b[275]
    DIRECTION INPUT ;
    USE SIGNAL ;
    PORT
      LAYER M5 ;
        RECT  63.312 0 63.336 0.084 ;
    END
  END t1b[275]
  PIN t1b[276]
    DIRECTION INPUT ;
    USE SIGNAL ;
    PORT
      LAYER M5 ;
        RECT  63.408 0 63.432 0.084 ;
    END
  END t1b[276]
  PIN t1b[277]
    DIRECTION INPUT ;
    USE SIGNAL ;
    PORT
      LAYER M5 ;
        RECT  63.504 0 63.528 0.084 ;
    END
  END t1b[277]
  PIN t1b[278]
    DIRECTION INPUT ;
    USE SIGNAL ;
    PORT
      LAYER M5 ;
        RECT  63.6 0 63.624 0.084 ;
    END
  END t1b[278]
  PIN t1b[279]
    DIRECTION INPUT ;
    USE SIGNAL ;
    PORT
      LAYER M5 ;
        RECT  63.696 0 63.72 0.084 ;
    END
  END t1b[279]
  PIN t1b[27]
    DIRECTION INPUT ;
    USE SIGNAL ;
    PORT
      LAYER M5 ;
        RECT  70.224 0 70.248 0.084 ;
    END
  END t1b[27]
  PIN t1b[280]
    DIRECTION INPUT ;
    USE SIGNAL ;
    PORT
      LAYER M5 ;
        RECT  63.792 0 63.816 0.084 ;
    END
  END t1b[280]
  PIN t1b[281]
    DIRECTION INPUT ;
    USE SIGNAL ;
    PORT
      LAYER M5 ;
        RECT  63.888 0 63.912 0.084 ;
    END
  END t1b[281]
  PIN t1b[282]
    DIRECTION INPUT ;
    USE SIGNAL ;
    PORT
      LAYER M5 ;
        RECT  63.984 0 64.008 0.084 ;
    END
  END t1b[282]
  PIN t1b[283]
    DIRECTION INPUT ;
    USE SIGNAL ;
    PORT
      LAYER M5 ;
        RECT  64.08 0 64.104 0.084 ;
    END
  END t1b[283]
  PIN t1b[284]
    DIRECTION INPUT ;
    USE SIGNAL ;
    PORT
      LAYER M5 ;
        RECT  64.176 0 64.2 0.084 ;
    END
  END t1b[284]
  PIN t1b[285]
    DIRECTION INPUT ;
    USE SIGNAL ;
    PORT
      LAYER M5 ;
        RECT  64.272 0 64.296 0.084 ;
    END
  END t1b[285]
  PIN t1b[286]
    DIRECTION INPUT ;
    USE SIGNAL ;
    PORT
      LAYER M5 ;
        RECT  64.368 0 64.392 0.084 ;
    END
  END t1b[286]
  PIN t1b[287]
    DIRECTION INPUT ;
    USE SIGNAL ;
    PORT
      LAYER M5 ;
        RECT  73.68 0 73.704 0.084 ;
    END
  END t1b[287]
  PIN t1b[288]
    DIRECTION INPUT ;
    USE SIGNAL ;
    PORT
      LAYER M5 ;
        RECT  73.776 0 73.8 0.084 ;
    END
  END t1b[288]
  PIN t1b[289]
    DIRECTION INPUT ;
    USE SIGNAL ;
    PORT
      LAYER M5 ;
        RECT  73.872 0 73.896 0.084 ;
    END
  END t1b[289]
  PIN t1b[28]
    DIRECTION INPUT ;
    USE SIGNAL ;
    PORT
      LAYER M5 ;
        RECT  70.32 0 70.344 0.084 ;
    END
  END t1b[28]
  PIN t1b[290]
    DIRECTION INPUT ;
    USE SIGNAL ;
    PORT
      LAYER M5 ;
        RECT  73.968 0 73.992 0.084 ;
    END
  END t1b[290]
  PIN t1b[291]
    DIRECTION INPUT ;
    USE SIGNAL ;
    PORT
      LAYER M5 ;
        RECT  74.064 0 74.088 0.084 ;
    END
  END t1b[291]
  PIN t1b[292]
    DIRECTION INPUT ;
    USE SIGNAL ;
    PORT
      LAYER M5 ;
        RECT  74.16 0 74.184 0.084 ;
    END
  END t1b[292]
  PIN t1b[293]
    DIRECTION INPUT ;
    USE SIGNAL ;
    PORT
      LAYER M5 ;
        RECT  74.256 0 74.28 0.084 ;
    END
  END t1b[293]
  PIN t1b[294]
    DIRECTION INPUT ;
    USE SIGNAL ;
    PORT
      LAYER M5 ;
        RECT  74.352 0 74.376 0.084 ;
    END
  END t1b[294]
  PIN t1b[295]
    DIRECTION INPUT ;
    USE SIGNAL ;
    PORT
      LAYER M5 ;
        RECT  74.448 0 74.472 0.084 ;
    END
  END t1b[295]
  PIN t1b[296]
    DIRECTION INPUT ;
    USE SIGNAL ;
    PORT
      LAYER M5 ;
        RECT  74.544 0 74.568 0.084 ;
    END
  END t1b[296]
  PIN t1b[297]
    DIRECTION INPUT ;
    USE SIGNAL ;
    PORT
      LAYER M5 ;
        RECT  74.64 0 74.664 0.084 ;
    END
  END t1b[297]
  PIN t1b[298]
    DIRECTION INPUT ;
    USE SIGNAL ;
    PORT
      LAYER M5 ;
        RECT  74.736 0 74.76 0.084 ;
    END
  END t1b[298]
  PIN t1b[299]
    DIRECTION INPUT ;
    USE SIGNAL ;
    PORT
      LAYER M5 ;
        RECT  74.832 0 74.856 0.084 ;
    END
  END t1b[299]
  PIN t1b[29]
    DIRECTION INPUT ;
    USE SIGNAL ;
    PORT
      LAYER M5 ;
        RECT  70.416 0 70.44 0.084 ;
    END
  END t1b[29]
  PIN t1b[2]
    DIRECTION INPUT ;
    USE SIGNAL ;
    PORT
      LAYER M5 ;
        RECT  67.824 0 67.848 0.084 ;
    END
  END t1b[2]
  PIN t1b[300]
    DIRECTION INPUT ;
    USE SIGNAL ;
    PORT
      LAYER M5 ;
        RECT  74.928 0 74.952 0.084 ;
    END
  END t1b[300]
  PIN t1b[301]
    DIRECTION INPUT ;
    USE SIGNAL ;
    PORT
      LAYER M5 ;
        RECT  75.024 0 75.048 0.084 ;
    END
  END t1b[301]
  PIN t1b[302]
    DIRECTION INPUT ;
    USE SIGNAL ;
    PORT
      LAYER M5 ;
        RECT  75.12 0 75.144 0.084 ;
    END
  END t1b[302]
  PIN t1b[303]
    DIRECTION INPUT ;
    USE SIGNAL ;
    PORT
      LAYER M5 ;
        RECT  75.216 0 75.24 0.084 ;
    END
  END t1b[303]
  PIN t1b[304]
    DIRECTION INPUT ;
    USE SIGNAL ;
    PORT
      LAYER M5 ;
        RECT  75.312 0 75.336 0.084 ;
    END
  END t1b[304]
  PIN t1b[305]
    DIRECTION INPUT ;
    USE SIGNAL ;
    PORT
      LAYER M5 ;
        RECT  75.408 0 75.432 0.084 ;
    END
  END t1b[305]
  PIN t1b[306]
    DIRECTION INPUT ;
    USE SIGNAL ;
    PORT
      LAYER M5 ;
        RECT  75.504 0 75.528 0.084 ;
    END
  END t1b[306]
  PIN t1b[307]
    DIRECTION INPUT ;
    USE SIGNAL ;
    PORT
      LAYER M5 ;
        RECT  75.6 0 75.624 0.084 ;
    END
  END t1b[307]
  PIN t1b[308]
    DIRECTION INPUT ;
    USE SIGNAL ;
    PORT
      LAYER M5 ;
        RECT  75.696 0 75.72 0.084 ;
    END
  END t1b[308]
  PIN t1b[309]
    DIRECTION INPUT ;
    USE SIGNAL ;
    PORT
      LAYER M5 ;
        RECT  75.792 0 75.816 0.084 ;
    END
  END t1b[309]
  PIN t1b[30]
    DIRECTION INPUT ;
    USE SIGNAL ;
    PORT
      LAYER M5 ;
        RECT  70.512 0 70.536 0.084 ;
    END
  END t1b[30]
  PIN t1b[310]
    DIRECTION INPUT ;
    USE SIGNAL ;
    PORT
      LAYER M5 ;
        RECT  75.888 0 75.912 0.084 ;
    END
  END t1b[310]
  PIN t1b[311]
    DIRECTION INPUT ;
    USE SIGNAL ;
    PORT
      LAYER M5 ;
        RECT  75.984 0 76.008 0.084 ;
    END
  END t1b[311]
  PIN t1b[312]
    DIRECTION INPUT ;
    USE SIGNAL ;
    PORT
      LAYER M5 ;
        RECT  76.08 0 76.104 0.084 ;
    END
  END t1b[312]
  PIN t1b[313]
    DIRECTION INPUT ;
    USE SIGNAL ;
    PORT
      LAYER M5 ;
        RECT  76.176 0 76.2 0.084 ;
    END
  END t1b[313]
  PIN t1b[314]
    DIRECTION INPUT ;
    USE SIGNAL ;
    PORT
      LAYER M5 ;
        RECT  76.272 0 76.296 0.084 ;
    END
  END t1b[314]
  PIN t1b[315]
    DIRECTION INPUT ;
    USE SIGNAL ;
    PORT
      LAYER M5 ;
        RECT  76.368 0 76.392 0.084 ;
    END
  END t1b[315]
  PIN t1b[316]
    DIRECTION INPUT ;
    USE SIGNAL ;
    PORT
      LAYER M5 ;
        RECT  76.464 0 76.488 0.084 ;
    END
  END t1b[316]
  PIN t1b[317]
    DIRECTION INPUT ;
    USE SIGNAL ;
    PORT
      LAYER M5 ;
        RECT  76.56 0 76.584 0.084 ;
    END
  END t1b[317]
  PIN t1b[318]
    DIRECTION INPUT ;
    USE SIGNAL ;
    PORT
      LAYER M5 ;
        RECT  76.656 0 76.68 0.084 ;
    END
  END t1b[318]
  PIN t1b[319]
    DIRECTION INPUT ;
    USE SIGNAL ;
    PORT
      LAYER M5 ;
        RECT  42.192 0 42.216 0.084 ;
    END
  END t1b[319]
  PIN t1b[31]
    DIRECTION INPUT ;
    USE SIGNAL ;
    PORT
      LAYER M5 ;
        RECT  58.32 0 58.344 0.084 ;
    END
  END t1b[31]
  PIN t1b[320]
    DIRECTION INPUT ;
    USE SIGNAL ;
    PORT
      LAYER M5 ;
        RECT  42.288 0 42.312 0.084 ;
    END
  END t1b[320]
  PIN t1b[321]
    DIRECTION INPUT ;
    USE SIGNAL ;
    PORT
      LAYER M5 ;
        RECT  42.384 0 42.408 0.084 ;
    END
  END t1b[321]
  PIN t1b[322]
    DIRECTION INPUT ;
    USE SIGNAL ;
    PORT
      LAYER M5 ;
        RECT  42.48 0 42.504 0.084 ;
    END
  END t1b[322]
  PIN t1b[323]
    DIRECTION INPUT ;
    USE SIGNAL ;
    PORT
      LAYER M5 ;
        RECT  42.576 0 42.6 0.084 ;
    END
  END t1b[323]
  PIN t1b[324]
    DIRECTION INPUT ;
    USE SIGNAL ;
    PORT
      LAYER M5 ;
        RECT  42.672 0 42.696 0.084 ;
    END
  END t1b[324]
  PIN t1b[325]
    DIRECTION INPUT ;
    USE SIGNAL ;
    PORT
      LAYER M5 ;
        RECT  42.768 0 42.792 0.084 ;
    END
  END t1b[325]
  PIN t1b[326]
    DIRECTION INPUT ;
    USE SIGNAL ;
    PORT
      LAYER M5 ;
        RECT  42.864 0 42.888 0.084 ;
    END
  END t1b[326]
  PIN t1b[327]
    DIRECTION INPUT ;
    USE SIGNAL ;
    PORT
      LAYER M5 ;
        RECT  42.96 0 42.984 0.084 ;
    END
  END t1b[327]
  PIN t1b[328]
    DIRECTION INPUT ;
    USE SIGNAL ;
    PORT
      LAYER M5 ;
        RECT  43.056 0 43.08 0.084 ;
    END
  END t1b[328]
  PIN t1b[329]
    DIRECTION INPUT ;
    USE SIGNAL ;
    PORT
      LAYER M5 ;
        RECT  43.152 0 43.176 0.084 ;
    END
  END t1b[329]
  PIN t1b[32]
    DIRECTION INPUT ;
    USE SIGNAL ;
    PORT
      LAYER M5 ;
        RECT  58.416 0 58.44 0.084 ;
    END
  END t1b[32]
  PIN t1b[330]
    DIRECTION INPUT ;
    USE SIGNAL ;
    PORT
      LAYER M5 ;
        RECT  43.248 0 43.272 0.084 ;
    END
  END t1b[330]
  PIN t1b[331]
    DIRECTION INPUT ;
    USE SIGNAL ;
    PORT
      LAYER M5 ;
        RECT  43.344 0 43.368 0.084 ;
    END
  END t1b[331]
  PIN t1b[332]
    DIRECTION INPUT ;
    USE SIGNAL ;
    PORT
      LAYER M5 ;
        RECT  43.44 0 43.464 0.084 ;
    END
  END t1b[332]
  PIN t1b[333]
    DIRECTION INPUT ;
    USE SIGNAL ;
    PORT
      LAYER M5 ;
        RECT  43.536 0 43.56 0.084 ;
    END
  END t1b[333]
  PIN t1b[334]
    DIRECTION INPUT ;
    USE SIGNAL ;
    PORT
      LAYER M5 ;
        RECT  43.632 0 43.656 0.084 ;
    END
  END t1b[334]
  PIN t1b[335]
    DIRECTION INPUT ;
    USE SIGNAL ;
    PORT
      LAYER M5 ;
        RECT  43.728 0 43.752 0.084 ;
    END
  END t1b[335]
  PIN t1b[336]
    DIRECTION INPUT ;
    USE SIGNAL ;
    PORT
      LAYER M5 ;
        RECT  43.824 0 43.848 0.084 ;
    END
  END t1b[336]
  PIN t1b[337]
    DIRECTION INPUT ;
    USE SIGNAL ;
    PORT
      LAYER M5 ;
        RECT  43.92 0 43.944 0.084 ;
    END
  END t1b[337]
  PIN t1b[338]
    DIRECTION INPUT ;
    USE SIGNAL ;
    PORT
      LAYER M5 ;
        RECT  44.016 0 44.04 0.084 ;
    END
  END t1b[338]
  PIN t1b[339]
    DIRECTION INPUT ;
    USE SIGNAL ;
    PORT
      LAYER M5 ;
        RECT  44.112 0 44.136 0.084 ;
    END
  END t1b[339]
  PIN t1b[33]
    DIRECTION INPUT ;
    USE SIGNAL ;
    PORT
      LAYER M5 ;
        RECT  58.512 0 58.536 0.084 ;
    END
  END t1b[33]
  PIN t1b[340]
    DIRECTION INPUT ;
    USE SIGNAL ;
    PORT
      LAYER M5 ;
        RECT  44.208 0 44.232 0.084 ;
    END
  END t1b[340]
  PIN t1b[341]
    DIRECTION INPUT ;
    USE SIGNAL ;
    PORT
      LAYER M5 ;
        RECT  44.304 0 44.328 0.084 ;
    END
  END t1b[341]
  PIN t1b[342]
    DIRECTION INPUT ;
    USE SIGNAL ;
    PORT
      LAYER M5 ;
        RECT  44.4 0 44.424 0.084 ;
    END
  END t1b[342]
  PIN t1b[343]
    DIRECTION INPUT ;
    USE SIGNAL ;
    PORT
      LAYER M5 ;
        RECT  44.496 0 44.52 0.084 ;
    END
  END t1b[343]
  PIN t1b[344]
    DIRECTION INPUT ;
    USE SIGNAL ;
    PORT
      LAYER M5 ;
        RECT  44.592 0 44.616 0.084 ;
    END
  END t1b[344]
  PIN t1b[345]
    DIRECTION INPUT ;
    USE SIGNAL ;
    PORT
      LAYER M5 ;
        RECT  44.688 0 44.712 0.084 ;
    END
  END t1b[345]
  PIN t1b[346]
    DIRECTION INPUT ;
    USE SIGNAL ;
    PORT
      LAYER M5 ;
        RECT  44.784 0 44.808 0.084 ;
    END
  END t1b[346]
  PIN t1b[347]
    DIRECTION INPUT ;
    USE SIGNAL ;
    PORT
      LAYER M5 ;
        RECT  44.88 0 44.904 0.084 ;
    END
  END t1b[347]
  PIN t1b[348]
    DIRECTION INPUT ;
    USE SIGNAL ;
    PORT
      LAYER M5 ;
        RECT  44.976 0 45 0.084 ;
    END
  END t1b[348]
  PIN t1b[349]
    DIRECTION INPUT ;
    USE SIGNAL ;
    PORT
      LAYER M5 ;
        RECT  45.072 0 45.096 0.084 ;
    END
  END t1b[349]
  PIN t1b[34]
    DIRECTION INPUT ;
    USE SIGNAL ;
    PORT
      LAYER M5 ;
        RECT  58.608 0 58.632 0.084 ;
    END
  END t1b[34]
  PIN t1b[350]
    DIRECTION INPUT ;
    USE SIGNAL ;
    PORT
      LAYER M5 ;
        RECT  45.168 0 45.192 0.084 ;
    END
  END t1b[350]
  PIN t1b[351]
    DIRECTION INPUT ;
    USE SIGNAL ;
    PORT
      LAYER M5 ;
        RECT  48.336 0 48.36 0.084 ;
    END
  END t1b[351]
  PIN t1b[352]
    DIRECTION INPUT ;
    USE SIGNAL ;
    PORT
      LAYER M5 ;
        RECT  48.432 0 48.456 0.084 ;
    END
  END t1b[352]
  PIN t1b[353]
    DIRECTION INPUT ;
    USE SIGNAL ;
    PORT
      LAYER M5 ;
        RECT  48.528 0 48.552 0.084 ;
    END
  END t1b[353]
  PIN t1b[354]
    DIRECTION INPUT ;
    USE SIGNAL ;
    PORT
      LAYER M5 ;
        RECT  48.624 0 48.648 0.084 ;
    END
  END t1b[354]
  PIN t1b[355]
    DIRECTION INPUT ;
    USE SIGNAL ;
    PORT
      LAYER M5 ;
        RECT  48.72 0 48.744 0.084 ;
    END
  END t1b[355]
  PIN t1b[356]
    DIRECTION INPUT ;
    USE SIGNAL ;
    PORT
      LAYER M5 ;
        RECT  48.816 0 48.84 0.084 ;
    END
  END t1b[356]
  PIN t1b[357]
    DIRECTION INPUT ;
    USE SIGNAL ;
    PORT
      LAYER M5 ;
        RECT  48.912 0 48.936 0.084 ;
    END
  END t1b[357]
  PIN t1b[358]
    DIRECTION INPUT ;
    USE SIGNAL ;
    PORT
      LAYER M5 ;
        RECT  49.008 0 49.032 0.084 ;
    END
  END t1b[358]
  PIN t1b[359]
    DIRECTION INPUT ;
    USE SIGNAL ;
    PORT
      LAYER M5 ;
        RECT  49.104 0 49.128 0.084 ;
    END
  END t1b[359]
  PIN t1b[35]
    DIRECTION INPUT ;
    USE SIGNAL ;
    PORT
      LAYER M5 ;
        RECT  58.704 0 58.728 0.084 ;
    END
  END t1b[35]
  PIN t1b[360]
    DIRECTION INPUT ;
    USE SIGNAL ;
    PORT
      LAYER M5 ;
        RECT  49.2 0 49.224 0.084 ;
    END
  END t1b[360]
  PIN t1b[361]
    DIRECTION INPUT ;
    USE SIGNAL ;
    PORT
      LAYER M5 ;
        RECT  49.296 0 49.32 0.084 ;
    END
  END t1b[361]
  PIN t1b[362]
    DIRECTION INPUT ;
    USE SIGNAL ;
    PORT
      LAYER M5 ;
        RECT  49.392 0 49.416 0.084 ;
    END
  END t1b[362]
  PIN t1b[363]
    DIRECTION INPUT ;
    USE SIGNAL ;
    PORT
      LAYER M5 ;
        RECT  49.488 0 49.512 0.084 ;
    END
  END t1b[363]
  PIN t1b[364]
    DIRECTION INPUT ;
    USE SIGNAL ;
    PORT
      LAYER M5 ;
        RECT  49.584 0 49.608 0.084 ;
    END
  END t1b[364]
  PIN t1b[365]
    DIRECTION INPUT ;
    USE SIGNAL ;
    PORT
      LAYER M5 ;
        RECT  49.68 0 49.704 0.084 ;
    END
  END t1b[365]
  PIN t1b[366]
    DIRECTION INPUT ;
    USE SIGNAL ;
    PORT
      LAYER M5 ;
        RECT  49.776 0 49.8 0.084 ;
    END
  END t1b[366]
  PIN t1b[367]
    DIRECTION INPUT ;
    USE SIGNAL ;
    PORT
      LAYER M5 ;
        RECT  49.872 0 49.896 0.084 ;
    END
  END t1b[367]
  PIN t1b[368]
    DIRECTION INPUT ;
    USE SIGNAL ;
    PORT
      LAYER M5 ;
        RECT  49.968 0 49.992 0.084 ;
    END
  END t1b[368]
  PIN t1b[369]
    DIRECTION INPUT ;
    USE SIGNAL ;
    PORT
      LAYER M5 ;
        RECT  50.064 0 50.088 0.084 ;
    END
  END t1b[369]
  PIN t1b[36]
    DIRECTION INPUT ;
    USE SIGNAL ;
    PORT
      LAYER M5 ;
        RECT  58.8 0 58.824 0.084 ;
    END
  END t1b[36]
  PIN t1b[370]
    DIRECTION INPUT ;
    USE SIGNAL ;
    PORT
      LAYER M5 ;
        RECT  50.16 0 50.184 0.084 ;
    END
  END t1b[370]
  PIN t1b[371]
    DIRECTION INPUT ;
    USE SIGNAL ;
    PORT
      LAYER M5 ;
        RECT  50.256 0 50.28 0.084 ;
    END
  END t1b[371]
  PIN t1b[372]
    DIRECTION INPUT ;
    USE SIGNAL ;
    PORT
      LAYER M5 ;
        RECT  50.352 0 50.376 0.084 ;
    END
  END t1b[372]
  PIN t1b[373]
    DIRECTION INPUT ;
    USE SIGNAL ;
    PORT
      LAYER M5 ;
        RECT  50.448 0 50.472 0.084 ;
    END
  END t1b[373]
  PIN t1b[374]
    DIRECTION INPUT ;
    USE SIGNAL ;
    PORT
      LAYER M5 ;
        RECT  50.544 0 50.568 0.084 ;
    END
  END t1b[374]
  PIN t1b[375]
    DIRECTION INPUT ;
    USE SIGNAL ;
    PORT
      LAYER M5 ;
        RECT  50.64 0 50.664 0.084 ;
    END
  END t1b[375]
  PIN t1b[376]
    DIRECTION INPUT ;
    USE SIGNAL ;
    PORT
      LAYER M5 ;
        RECT  50.736 0 50.76 0.084 ;
    END
  END t1b[376]
  PIN t1b[377]
    DIRECTION INPUT ;
    USE SIGNAL ;
    PORT
      LAYER M5 ;
        RECT  50.832 0 50.856 0.084 ;
    END
  END t1b[377]
  PIN t1b[378]
    DIRECTION INPUT ;
    USE SIGNAL ;
    PORT
      LAYER M5 ;
        RECT  50.928 0 50.952 0.084 ;
    END
  END t1b[378]
  PIN t1b[379]
    DIRECTION INPUT ;
    USE SIGNAL ;
    PORT
      LAYER M5 ;
        RECT  51.024 0 51.048 0.084 ;
    END
  END t1b[379]
  PIN t1b[37]
    DIRECTION INPUT ;
    USE SIGNAL ;
    PORT
      LAYER M5 ;
        RECT  58.896 0 58.92 0.084 ;
    END
  END t1b[37]
  PIN t1b[380]
    DIRECTION INPUT ;
    USE SIGNAL ;
    PORT
      LAYER M5 ;
        RECT  51.12 0 51.144 0.084 ;
    END
  END t1b[380]
  PIN t1b[381]
    DIRECTION INPUT ;
    USE SIGNAL ;
    PORT
      LAYER M5 ;
        RECT  51.216 0 51.24 0.084 ;
    END
  END t1b[381]
  PIN t1b[382]
    DIRECTION INPUT ;
    USE SIGNAL ;
    PORT
      LAYER M5 ;
        RECT  51.312 0 51.336 0.084 ;
    END
  END t1b[382]
  PIN t1b[383]
    DIRECTION INPUT ;
    USE SIGNAL ;
    PORT
      LAYER M5 ;
        RECT  54.48 0 54.504 0.084 ;
    END
  END t1b[383]
  PIN t1b[384]
    DIRECTION INPUT ;
    USE SIGNAL ;
    PORT
      LAYER M5 ;
        RECT  54.576 0 54.6 0.084 ;
    END
  END t1b[384]
  PIN t1b[385]
    DIRECTION INPUT ;
    USE SIGNAL ;
    PORT
      LAYER M5 ;
        RECT  54.672 0 54.696 0.084 ;
    END
  END t1b[385]
  PIN t1b[386]
    DIRECTION INPUT ;
    USE SIGNAL ;
    PORT
      LAYER M5 ;
        RECT  54.768 0 54.792 0.084 ;
    END
  END t1b[386]
  PIN t1b[387]
    DIRECTION INPUT ;
    USE SIGNAL ;
    PORT
      LAYER M5 ;
        RECT  54.864 0 54.888 0.084 ;
    END
  END t1b[387]
  PIN t1b[388]
    DIRECTION INPUT ;
    USE SIGNAL ;
    PORT
      LAYER M5 ;
        RECT  54.96 0 54.984 0.084 ;
    END
  END t1b[388]
  PIN t1b[389]
    DIRECTION INPUT ;
    USE SIGNAL ;
    PORT
      LAYER M5 ;
        RECT  55.056 0 55.08 0.084 ;
    END
  END t1b[389]
  PIN t1b[38]
    DIRECTION INPUT ;
    USE SIGNAL ;
    PORT
      LAYER M5 ;
        RECT  58.992 0 59.016 0.084 ;
    END
  END t1b[38]
  PIN t1b[390]
    DIRECTION INPUT ;
    USE SIGNAL ;
    PORT
      LAYER M5 ;
        RECT  55.152 0 55.176 0.084 ;
    END
  END t1b[390]
  PIN t1b[391]
    DIRECTION INPUT ;
    USE SIGNAL ;
    PORT
      LAYER M5 ;
        RECT  55.248 0 55.272 0.084 ;
    END
  END t1b[391]
  PIN t1b[392]
    DIRECTION INPUT ;
    USE SIGNAL ;
    PORT
      LAYER M5 ;
        RECT  55.344 0 55.368 0.084 ;
    END
  END t1b[392]
  PIN t1b[393]
    DIRECTION INPUT ;
    USE SIGNAL ;
    PORT
      LAYER M5 ;
        RECT  55.44 0 55.464 0.084 ;
    END
  END t1b[393]
  PIN t1b[394]
    DIRECTION INPUT ;
    USE SIGNAL ;
    PORT
      LAYER M5 ;
        RECT  55.536 0 55.56 0.084 ;
    END
  END t1b[394]
  PIN t1b[395]
    DIRECTION INPUT ;
    USE SIGNAL ;
    PORT
      LAYER M5 ;
        RECT  55.632 0 55.656 0.084 ;
    END
  END t1b[395]
  PIN t1b[396]
    DIRECTION INPUT ;
    USE SIGNAL ;
    PORT
      LAYER M5 ;
        RECT  55.728 0 55.752 0.084 ;
    END
  END t1b[396]
  PIN t1b[397]
    DIRECTION INPUT ;
    USE SIGNAL ;
    PORT
      LAYER M5 ;
        RECT  55.824 0 55.848 0.084 ;
    END
  END t1b[397]
  PIN t1b[398]
    DIRECTION INPUT ;
    USE SIGNAL ;
    PORT
      LAYER M5 ;
        RECT  55.92 0 55.944 0.084 ;
    END
  END t1b[398]
  PIN t1b[399]
    DIRECTION INPUT ;
    USE SIGNAL ;
    PORT
      LAYER M5 ;
        RECT  56.016 0 56.04 0.084 ;
    END
  END t1b[399]
  PIN t1b[39]
    DIRECTION INPUT ;
    USE SIGNAL ;
    PORT
      LAYER M5 ;
        RECT  59.088 0 59.112 0.084 ;
    END
  END t1b[39]
  PIN t1b[3]
    DIRECTION INPUT ;
    USE SIGNAL ;
    PORT
      LAYER M5 ;
        RECT  67.92 0 67.944 0.084 ;
    END
  END t1b[3]
  PIN t1b[400]
    DIRECTION INPUT ;
    USE SIGNAL ;
    PORT
      LAYER M5 ;
        RECT  56.112 0 56.136 0.084 ;
    END
  END t1b[400]
  PIN t1b[401]
    DIRECTION INPUT ;
    USE SIGNAL ;
    PORT
      LAYER M5 ;
        RECT  56.208 0 56.232 0.084 ;
    END
  END t1b[401]
  PIN t1b[402]
    DIRECTION INPUT ;
    USE SIGNAL ;
    PORT
      LAYER M5 ;
        RECT  56.304 0 56.328 0.084 ;
    END
  END t1b[402]
  PIN t1b[403]
    DIRECTION INPUT ;
    USE SIGNAL ;
    PORT
      LAYER M5 ;
        RECT  56.4 0 56.424 0.084 ;
    END
  END t1b[403]
  PIN t1b[404]
    DIRECTION INPUT ;
    USE SIGNAL ;
    PORT
      LAYER M5 ;
        RECT  56.496 0 56.52 0.084 ;
    END
  END t1b[404]
  PIN t1b[405]
    DIRECTION INPUT ;
    USE SIGNAL ;
    PORT
      LAYER M5 ;
        RECT  56.592 0 56.616 0.084 ;
    END
  END t1b[405]
  PIN t1b[406]
    DIRECTION INPUT ;
    USE SIGNAL ;
    PORT
      LAYER M5 ;
        RECT  56.688 0 56.712 0.084 ;
    END
  END t1b[406]
  PIN t1b[407]
    DIRECTION INPUT ;
    USE SIGNAL ;
    PORT
      LAYER M5 ;
        RECT  56.784 0 56.808 0.084 ;
    END
  END t1b[407]
  PIN t1b[408]
    DIRECTION INPUT ;
    USE SIGNAL ;
    PORT
      LAYER M5 ;
        RECT  56.88 0 56.904 0.084 ;
    END
  END t1b[408]
  PIN t1b[409]
    DIRECTION INPUT ;
    USE SIGNAL ;
    PORT
      LAYER M5 ;
        RECT  56.976 0 57 0.084 ;
    END
  END t1b[409]
  PIN t1b[40]
    DIRECTION INPUT ;
    USE SIGNAL ;
    PORT
      LAYER M5 ;
        RECT  59.184 0 59.208 0.084 ;
    END
  END t1b[40]
  PIN t1b[410]
    DIRECTION INPUT ;
    USE SIGNAL ;
    PORT
      LAYER M5 ;
        RECT  57.072 0 57.096 0.084 ;
    END
  END t1b[410]
  PIN t1b[411]
    DIRECTION INPUT ;
    USE SIGNAL ;
    PORT
      LAYER M5 ;
        RECT  57.168 0 57.192 0.084 ;
    END
  END t1b[411]
  PIN t1b[412]
    DIRECTION INPUT ;
    USE SIGNAL ;
    PORT
      LAYER M5 ;
        RECT  57.264 0 57.288 0.084 ;
    END
  END t1b[412]
  PIN t1b[413]
    DIRECTION INPUT ;
    USE SIGNAL ;
    PORT
      LAYER M5 ;
        RECT  57.36 0 57.384 0.084 ;
    END
  END t1b[413]
  PIN t1b[414]
    DIRECTION INPUT ;
    USE SIGNAL ;
    PORT
      LAYER M5 ;
        RECT  57.456 0 57.48 0.084 ;
    END
  END t1b[414]
  PIN t1b[415]
    DIRECTION INPUT ;
    USE SIGNAL ;
    PORT
      LAYER M5 ;
        RECT  80.592 0 80.616 0.084 ;
    END
  END t1b[415]
  PIN t1b[416]
    DIRECTION INPUT ;
    USE SIGNAL ;
    PORT
      LAYER M5 ;
        RECT  80.688 0 80.712 0.084 ;
    END
  END t1b[416]
  PIN t1b[417]
    DIRECTION INPUT ;
    USE SIGNAL ;
    PORT
      LAYER M5 ;
        RECT  80.784 0 80.808 0.084 ;
    END
  END t1b[417]
  PIN t1b[418]
    DIRECTION INPUT ;
    USE SIGNAL ;
    PORT
      LAYER M5 ;
        RECT  80.88 0 80.904 0.084 ;
    END
  END t1b[418]
  PIN t1b[419]
    DIRECTION INPUT ;
    USE SIGNAL ;
    PORT
      LAYER M5 ;
        RECT  80.976 0 81 0.084 ;
    END
  END t1b[419]
  PIN t1b[41]
    DIRECTION INPUT ;
    USE SIGNAL ;
    PORT
      LAYER M5 ;
        RECT  59.28 0 59.304 0.084 ;
    END
  END t1b[41]
  PIN t1b[420]
    DIRECTION INPUT ;
    USE SIGNAL ;
    PORT
      LAYER M5 ;
        RECT  81.072 0 81.096 0.084 ;
    END
  END t1b[420]
  PIN t1b[421]
    DIRECTION INPUT ;
    USE SIGNAL ;
    PORT
      LAYER M5 ;
        RECT  81.168 0 81.192 0.084 ;
    END
  END t1b[421]
  PIN t1b[422]
    DIRECTION INPUT ;
    USE SIGNAL ;
    PORT
      LAYER M5 ;
        RECT  81.264 0 81.288 0.084 ;
    END
  END t1b[422]
  PIN t1b[423]
    DIRECTION INPUT ;
    USE SIGNAL ;
    PORT
      LAYER M5 ;
        RECT  81.36 0 81.384 0.084 ;
    END
  END t1b[423]
  PIN t1b[424]
    DIRECTION INPUT ;
    USE SIGNAL ;
    PORT
      LAYER M5 ;
        RECT  81.456 0 81.48 0.084 ;
    END
  END t1b[424]
  PIN t1b[425]
    DIRECTION INPUT ;
    USE SIGNAL ;
    PORT
      LAYER M5 ;
        RECT  81.552 0 81.576 0.084 ;
    END
  END t1b[425]
  PIN t1b[426]
    DIRECTION INPUT ;
    USE SIGNAL ;
    PORT
      LAYER M5 ;
        RECT  81.648 0 81.672 0.084 ;
    END
  END t1b[426]
  PIN t1b[427]
    DIRECTION INPUT ;
    USE SIGNAL ;
    PORT
      LAYER M5 ;
        RECT  81.744 0 81.768 0.084 ;
    END
  END t1b[427]
  PIN t1b[428]
    DIRECTION INPUT ;
    USE SIGNAL ;
    PORT
      LAYER M5 ;
        RECT  81.84 0 81.864 0.084 ;
    END
  END t1b[428]
  PIN t1b[429]
    DIRECTION INPUT ;
    USE SIGNAL ;
    PORT
      LAYER M5 ;
        RECT  81.936 0 81.96 0.084 ;
    END
  END t1b[429]
  PIN t1b[42]
    DIRECTION INPUT ;
    USE SIGNAL ;
    PORT
      LAYER M5 ;
        RECT  59.376 0 59.4 0.084 ;
    END
  END t1b[42]
  PIN t1b[430]
    DIRECTION INPUT ;
    USE SIGNAL ;
    PORT
      LAYER M5 ;
        RECT  82.032 0 82.056 0.084 ;
    END
  END t1b[430]
  PIN t1b[431]
    DIRECTION INPUT ;
    USE SIGNAL ;
    PORT
      LAYER M5 ;
        RECT  82.128 0 82.152 0.084 ;
    END
  END t1b[431]
  PIN t1b[432]
    DIRECTION INPUT ;
    USE SIGNAL ;
    PORT
      LAYER M5 ;
        RECT  82.224 0 82.248 0.084 ;
    END
  END t1b[432]
  PIN t1b[433]
    DIRECTION INPUT ;
    USE SIGNAL ;
    PORT
      LAYER M5 ;
        RECT  82.32 0 82.344 0.084 ;
    END
  END t1b[433]
  PIN t1b[434]
    DIRECTION INPUT ;
    USE SIGNAL ;
    PORT
      LAYER M5 ;
        RECT  82.416 0 82.44 0.084 ;
    END
  END t1b[434]
  PIN t1b[435]
    DIRECTION INPUT ;
    USE SIGNAL ;
    PORT
      LAYER M5 ;
        RECT  82.512 0 82.536 0.084 ;
    END
  END t1b[435]
  PIN t1b[436]
    DIRECTION INPUT ;
    USE SIGNAL ;
    PORT
      LAYER M5 ;
        RECT  82.608 0 82.632 0.084 ;
    END
  END t1b[436]
  PIN t1b[437]
    DIRECTION INPUT ;
    USE SIGNAL ;
    PORT
      LAYER M5 ;
        RECT  82.704 0 82.728 0.084 ;
    END
  END t1b[437]
  PIN t1b[438]
    DIRECTION INPUT ;
    USE SIGNAL ;
    PORT
      LAYER M5 ;
        RECT  82.8 0 82.824 0.084 ;
    END
  END t1b[438]
  PIN t1b[439]
    DIRECTION INPUT ;
    USE SIGNAL ;
    PORT
      LAYER M5 ;
        RECT  82.896 0 82.92 0.084 ;
    END
  END t1b[439]
  PIN t1b[43]
    DIRECTION INPUT ;
    USE SIGNAL ;
    PORT
      LAYER M5 ;
        RECT  59.472 0 59.496 0.084 ;
    END
  END t1b[43]
  PIN t1b[440]
    DIRECTION INPUT ;
    USE SIGNAL ;
    PORT
      LAYER M5 ;
        RECT  82.992 0 83.016 0.084 ;
    END
  END t1b[440]
  PIN t1b[441]
    DIRECTION INPUT ;
    USE SIGNAL ;
    PORT
      LAYER M5 ;
        RECT  83.088 0 83.112 0.084 ;
    END
  END t1b[441]
  PIN t1b[442]
    DIRECTION INPUT ;
    USE SIGNAL ;
    PORT
      LAYER M5 ;
        RECT  83.184 0 83.208 0.084 ;
    END
  END t1b[442]
  PIN t1b[443]
    DIRECTION INPUT ;
    USE SIGNAL ;
    PORT
      LAYER M5 ;
        RECT  83.28 0 83.304 0.084 ;
    END
  END t1b[443]
  PIN t1b[444]
    DIRECTION INPUT ;
    USE SIGNAL ;
    PORT
      LAYER M5 ;
        RECT  83.376 0 83.4 0.084 ;
    END
  END t1b[444]
  PIN t1b[445]
    DIRECTION INPUT ;
    USE SIGNAL ;
    PORT
      LAYER M5 ;
        RECT  83.472 0 83.496 0.084 ;
    END
  END t1b[445]
  PIN t1b[446]
    DIRECTION INPUT ;
    USE SIGNAL ;
    PORT
      LAYER M5 ;
        RECT  83.568 0 83.592 0.084 ;
    END
  END t1b[446]
  PIN t1b[447]
    DIRECTION INPUT ;
    USE SIGNAL ;
    PORT
      LAYER M5 ;
        RECT  35.28 0 35.304 0.084 ;
    END
  END t1b[447]
  PIN t1b[448]
    DIRECTION INPUT ;
    USE SIGNAL ;
    PORT
      LAYER M5 ;
        RECT  35.376 0 35.4 0.084 ;
    END
  END t1b[448]
  PIN t1b[449]
    DIRECTION INPUT ;
    USE SIGNAL ;
    PORT
      LAYER M5 ;
        RECT  35.472 0 35.496 0.084 ;
    END
  END t1b[449]
  PIN t1b[44]
    DIRECTION INPUT ;
    USE SIGNAL ;
    PORT
      LAYER M5 ;
        RECT  59.568 0 59.592 0.084 ;
    END
  END t1b[44]
  PIN t1b[450]
    DIRECTION INPUT ;
    USE SIGNAL ;
    PORT
      LAYER M5 ;
        RECT  35.568 0 35.592 0.084 ;
    END
  END t1b[450]
  PIN t1b[451]
    DIRECTION INPUT ;
    USE SIGNAL ;
    PORT
      LAYER M5 ;
        RECT  35.664 0 35.688 0.084 ;
    END
  END t1b[451]
  PIN t1b[452]
    DIRECTION INPUT ;
    USE SIGNAL ;
    PORT
      LAYER M5 ;
        RECT  35.76 0 35.784 0.084 ;
    END
  END t1b[452]
  PIN t1b[453]
    DIRECTION INPUT ;
    USE SIGNAL ;
    PORT
      LAYER M5 ;
        RECT  35.856 0 35.88 0.084 ;
    END
  END t1b[453]
  PIN t1b[454]
    DIRECTION INPUT ;
    USE SIGNAL ;
    PORT
      LAYER M5 ;
        RECT  35.952 0 35.976 0.084 ;
    END
  END t1b[454]
  PIN t1b[455]
    DIRECTION INPUT ;
    USE SIGNAL ;
    PORT
      LAYER M5 ;
        RECT  36.048 0 36.072 0.084 ;
    END
  END t1b[455]
  PIN t1b[456]
    DIRECTION INPUT ;
    USE SIGNAL ;
    PORT
      LAYER M5 ;
        RECT  36.144 0 36.168 0.084 ;
    END
  END t1b[456]
  PIN t1b[457]
    DIRECTION INPUT ;
    USE SIGNAL ;
    PORT
      LAYER M5 ;
        RECT  36.24 0 36.264 0.084 ;
    END
  END t1b[457]
  PIN t1b[458]
    DIRECTION INPUT ;
    USE SIGNAL ;
    PORT
      LAYER M5 ;
        RECT  36.336 0 36.36 0.084 ;
    END
  END t1b[458]
  PIN t1b[459]
    DIRECTION INPUT ;
    USE SIGNAL ;
    PORT
      LAYER M5 ;
        RECT  36.432 0 36.456 0.084 ;
    END
  END t1b[459]
  PIN t1b[45]
    DIRECTION INPUT ;
    USE SIGNAL ;
    PORT
      LAYER M5 ;
        RECT  59.664 0 59.688 0.084 ;
    END
  END t1b[45]
  PIN t1b[460]
    DIRECTION INPUT ;
    USE SIGNAL ;
    PORT
      LAYER M5 ;
        RECT  36.528 0 36.552 0.084 ;
    END
  END t1b[460]
  PIN t1b[461]
    DIRECTION INPUT ;
    USE SIGNAL ;
    PORT
      LAYER M5 ;
        RECT  36.624 0 36.648 0.084 ;
    END
  END t1b[461]
  PIN t1b[462]
    DIRECTION INPUT ;
    USE SIGNAL ;
    PORT
      LAYER M5 ;
        RECT  36.72 0 36.744 0.084 ;
    END
  END t1b[462]
  PIN t1b[463]
    DIRECTION INPUT ;
    USE SIGNAL ;
    PORT
      LAYER M5 ;
        RECT  36.816 0 36.84 0.084 ;
    END
  END t1b[463]
  PIN t1b[464]
    DIRECTION INPUT ;
    USE SIGNAL ;
    PORT
      LAYER M5 ;
        RECT  36.912 0 36.936 0.084 ;
    END
  END t1b[464]
  PIN t1b[465]
    DIRECTION INPUT ;
    USE SIGNAL ;
    PORT
      LAYER M5 ;
        RECT  37.008 0 37.032 0.084 ;
    END
  END t1b[465]
  PIN t1b[466]
    DIRECTION INPUT ;
    USE SIGNAL ;
    PORT
      LAYER M5 ;
        RECT  37.104 0 37.128 0.084 ;
    END
  END t1b[466]
  PIN t1b[467]
    DIRECTION INPUT ;
    USE SIGNAL ;
    PORT
      LAYER M5 ;
        RECT  37.2 0 37.224 0.084 ;
    END
  END t1b[467]
  PIN t1b[468]
    DIRECTION INPUT ;
    USE SIGNAL ;
    PORT
      LAYER M5 ;
        RECT  37.296 0 37.32 0.084 ;
    END
  END t1b[468]
  PIN t1b[469]
    DIRECTION INPUT ;
    USE SIGNAL ;
    PORT
      LAYER M5 ;
        RECT  37.392 0 37.416 0.084 ;
    END
  END t1b[469]
  PIN t1b[46]
    DIRECTION INPUT ;
    USE SIGNAL ;
    PORT
      LAYER M5 ;
        RECT  59.76 0 59.784 0.084 ;
    END
  END t1b[46]
  PIN t1b[470]
    DIRECTION INPUT ;
    USE SIGNAL ;
    PORT
      LAYER M5 ;
        RECT  37.488 0 37.512 0.084 ;
    END
  END t1b[470]
  PIN t1b[471]
    DIRECTION INPUT ;
    USE SIGNAL ;
    PORT
      LAYER M5 ;
        RECT  37.584 0 37.608 0.084 ;
    END
  END t1b[471]
  PIN t1b[472]
    DIRECTION INPUT ;
    USE SIGNAL ;
    PORT
      LAYER M5 ;
        RECT  37.68 0 37.704 0.084 ;
    END
  END t1b[472]
  PIN t1b[473]
    DIRECTION INPUT ;
    USE SIGNAL ;
    PORT
      LAYER M5 ;
        RECT  37.776 0 37.8 0.084 ;
    END
  END t1b[473]
  PIN t1b[474]
    DIRECTION INPUT ;
    USE SIGNAL ;
    PORT
      LAYER M5 ;
        RECT  37.872 0 37.896 0.084 ;
    END
  END t1b[474]
  PIN t1b[475]
    DIRECTION INPUT ;
    USE SIGNAL ;
    PORT
      LAYER M5 ;
        RECT  37.968 0 37.992 0.084 ;
    END
  END t1b[475]
  PIN t1b[476]
    DIRECTION INPUT ;
    USE SIGNAL ;
    PORT
      LAYER M5 ;
        RECT  38.064 0 38.088 0.084 ;
    END
  END t1b[476]
  PIN t1b[477]
    DIRECTION INPUT ;
    USE SIGNAL ;
    PORT
      LAYER M5 ;
        RECT  38.16 0 38.184 0.084 ;
    END
  END t1b[477]
  PIN t1b[478]
    DIRECTION INPUT ;
    USE SIGNAL ;
    PORT
      LAYER M5 ;
        RECT  38.256 0 38.28 0.084 ;
    END
  END t1b[478]
  PIN t1b[479]
    DIRECTION INPUT ;
    USE SIGNAL ;
    PORT
      LAYER M5 ;
        RECT  77.52 0 77.544 0.084 ;
    END
  END t1b[479]
  PIN t1b[47]
    DIRECTION INPUT ;
    USE SIGNAL ;
    PORT
      LAYER M5 ;
        RECT  59.856 0 59.88 0.084 ;
    END
  END t1b[47]
  PIN t1b[480]
    DIRECTION INPUT ;
    USE SIGNAL ;
    PORT
      LAYER M5 ;
        RECT  77.616 0 77.64 0.084 ;
    END
  END t1b[480]
  PIN t1b[481]
    DIRECTION INPUT ;
    USE SIGNAL ;
    PORT
      LAYER M5 ;
        RECT  77.712 0 77.736 0.084 ;
    END
  END t1b[481]
  PIN t1b[482]
    DIRECTION INPUT ;
    USE SIGNAL ;
    PORT
      LAYER M5 ;
        RECT  77.808 0 77.832 0.084 ;
    END
  END t1b[482]
  PIN t1b[483]
    DIRECTION INPUT ;
    USE SIGNAL ;
    PORT
      LAYER M5 ;
        RECT  77.904 0 77.928 0.084 ;
    END
  END t1b[483]
  PIN t1b[484]
    DIRECTION INPUT ;
    USE SIGNAL ;
    PORT
      LAYER M5 ;
        RECT  78 0 78.024 0.084 ;
    END
  END t1b[484]
  PIN t1b[485]
    DIRECTION INPUT ;
    USE SIGNAL ;
    PORT
      LAYER M5 ;
        RECT  78.096 0 78.12 0.084 ;
    END
  END t1b[485]
  PIN t1b[486]
    DIRECTION INPUT ;
    USE SIGNAL ;
    PORT
      LAYER M5 ;
        RECT  78.192 0 78.216 0.084 ;
    END
  END t1b[486]
  PIN t1b[487]
    DIRECTION INPUT ;
    USE SIGNAL ;
    PORT
      LAYER M5 ;
        RECT  78.288 0 78.312 0.084 ;
    END
  END t1b[487]
  PIN t1b[488]
    DIRECTION INPUT ;
    USE SIGNAL ;
    PORT
      LAYER M5 ;
        RECT  78.384 0 78.408 0.084 ;
    END
  END t1b[488]
  PIN t1b[489]
    DIRECTION INPUT ;
    USE SIGNAL ;
    PORT
      LAYER M5 ;
        RECT  78.48 0 78.504 0.084 ;
    END
  END t1b[489]
  PIN t1b[48]
    DIRECTION INPUT ;
    USE SIGNAL ;
    PORT
      LAYER M5 ;
        RECT  59.952 0 59.976 0.084 ;
    END
  END t1b[48]
  PIN t1b[490]
    DIRECTION INPUT ;
    USE SIGNAL ;
    PORT
      LAYER M5 ;
        RECT  78.576 0 78.6 0.084 ;
    END
  END t1b[490]
  PIN t1b[491]
    DIRECTION INPUT ;
    USE SIGNAL ;
    PORT
      LAYER M5 ;
        RECT  78.672 0 78.696 0.084 ;
    END
  END t1b[491]
  PIN t1b[492]
    DIRECTION INPUT ;
    USE SIGNAL ;
    PORT
      LAYER M5 ;
        RECT  78.768 0 78.792 0.084 ;
    END
  END t1b[492]
  PIN t1b[493]
    DIRECTION INPUT ;
    USE SIGNAL ;
    PORT
      LAYER M5 ;
        RECT  78.864 0 78.888 0.084 ;
    END
  END t1b[493]
  PIN t1b[494]
    DIRECTION INPUT ;
    USE SIGNAL ;
    PORT
      LAYER M5 ;
        RECT  78.96 0 78.984 0.084 ;
    END
  END t1b[494]
  PIN t1b[495]
    DIRECTION INPUT ;
    USE SIGNAL ;
    PORT
      LAYER M5 ;
        RECT  79.056 0 79.08 0.084 ;
    END
  END t1b[495]
  PIN t1b[496]
    DIRECTION INPUT ;
    USE SIGNAL ;
    PORT
      LAYER M5 ;
        RECT  79.152 0 79.176 0.084 ;
    END
  END t1b[496]
  PIN t1b[497]
    DIRECTION INPUT ;
    USE SIGNAL ;
    PORT
      LAYER M5 ;
        RECT  79.248 0 79.272 0.084 ;
    END
  END t1b[497]
  PIN t1b[498]
    DIRECTION INPUT ;
    USE SIGNAL ;
    PORT
      LAYER M5 ;
        RECT  79.344 0 79.368 0.084 ;
    END
  END t1b[498]
  PIN t1b[499]
    DIRECTION INPUT ;
    USE SIGNAL ;
    PORT
      LAYER M5 ;
        RECT  79.44 0 79.464 0.084 ;
    END
  END t1b[499]
  PIN t1b[49]
    DIRECTION INPUT ;
    USE SIGNAL ;
    PORT
      LAYER M5 ;
        RECT  60.048 0 60.072 0.084 ;
    END
  END t1b[49]
  PIN t1b[4]
    DIRECTION INPUT ;
    USE SIGNAL ;
    PORT
      LAYER M5 ;
        RECT  68.016 0 68.04 0.084 ;
    END
  END t1b[4]
  PIN t1b[500]
    DIRECTION INPUT ;
    USE SIGNAL ;
    PORT
      LAYER M5 ;
        RECT  79.536 0 79.56 0.084 ;
    END
  END t1b[500]
  PIN t1b[501]
    DIRECTION INPUT ;
    USE SIGNAL ;
    PORT
      LAYER M5 ;
        RECT  79.632 0 79.656 0.084 ;
    END
  END t1b[501]
  PIN t1b[502]
    DIRECTION INPUT ;
    USE SIGNAL ;
    PORT
      LAYER M5 ;
        RECT  79.728 0 79.752 0.084 ;
    END
  END t1b[502]
  PIN t1b[503]
    DIRECTION INPUT ;
    USE SIGNAL ;
    PORT
      LAYER M5 ;
        RECT  79.824 0 79.848 0.084 ;
    END
  END t1b[503]
  PIN t1b[504]
    DIRECTION INPUT ;
    USE SIGNAL ;
    PORT
      LAYER M5 ;
        RECT  79.92 0 79.944 0.084 ;
    END
  END t1b[504]
  PIN t1b[505]
    DIRECTION INPUT ;
    USE SIGNAL ;
    PORT
      LAYER M5 ;
        RECT  80.016 0 80.04 0.084 ;
    END
  END t1b[505]
  PIN t1b[506]
    DIRECTION INPUT ;
    USE SIGNAL ;
    PORT
      LAYER M5 ;
        RECT  80.112 0 80.136 0.084 ;
    END
  END t1b[506]
  PIN t1b[507]
    DIRECTION INPUT ;
    USE SIGNAL ;
    PORT
      LAYER M5 ;
        RECT  80.208 0 80.232 0.084 ;
    END
  END t1b[507]
  PIN t1b[508]
    DIRECTION INPUT ;
    USE SIGNAL ;
    PORT
      LAYER M5 ;
        RECT  80.304 0 80.328 0.084 ;
    END
  END t1b[508]
  PIN t1b[509]
    DIRECTION INPUT ;
    USE SIGNAL ;
    PORT
      LAYER M5 ;
        RECT  80.4 0 80.424 0.084 ;
    END
  END t1b[509]
  PIN t1b[50]
    DIRECTION INPUT ;
    USE SIGNAL ;
    PORT
      LAYER M5 ;
        RECT  60.144 0 60.168 0.084 ;
    END
  END t1b[50]
  PIN t1b[510]
    DIRECTION INPUT ;
    USE SIGNAL ;
    PORT
      LAYER M5 ;
        RECT  80.496 0 80.52 0.084 ;
    END
  END t1b[510]
  PIN t1b[511]
    DIRECTION INPUT ;
    USE SIGNAL ;
    PORT
      LAYER M5 ;
        RECT  76.752 0 76.776 0.084 ;
    END
  END t1b[511]
  PIN t1b[51]
    DIRECTION INPUT ;
    USE SIGNAL ;
    PORT
      LAYER M5 ;
        RECT  60.24 0 60.264 0.084 ;
    END
  END t1b[51]
  PIN t1b[52]
    DIRECTION INPUT ;
    USE SIGNAL ;
    PORT
      LAYER M5 ;
        RECT  60.336 0 60.36 0.084 ;
    END
  END t1b[52]
  PIN t1b[53]
    DIRECTION INPUT ;
    USE SIGNAL ;
    PORT
      LAYER M5 ;
        RECT  60.432 0 60.456 0.084 ;
    END
  END t1b[53]
  PIN t1b[54]
    DIRECTION INPUT ;
    USE SIGNAL ;
    PORT
      LAYER M5 ;
        RECT  60.528 0 60.552 0.084 ;
    END
  END t1b[54]
  PIN t1b[55]
    DIRECTION INPUT ;
    USE SIGNAL ;
    PORT
      LAYER M5 ;
        RECT  60.624 0 60.648 0.084 ;
    END
  END t1b[55]
  PIN t1b[56]
    DIRECTION INPUT ;
    USE SIGNAL ;
    PORT
      LAYER M5 ;
        RECT  60.72 0 60.744 0.084 ;
    END
  END t1b[56]
  PIN t1b[57]
    DIRECTION INPUT ;
    USE SIGNAL ;
    PORT
      LAYER M5 ;
        RECT  60.816 0 60.84 0.084 ;
    END
  END t1b[57]
  PIN t1b[58]
    DIRECTION INPUT ;
    USE SIGNAL ;
    PORT
      LAYER M5 ;
        RECT  60.912 0 60.936 0.084 ;
    END
  END t1b[58]
  PIN t1b[59]
    DIRECTION INPUT ;
    USE SIGNAL ;
    PORT
      LAYER M5 ;
        RECT  61.008 0 61.032 0.084 ;
    END
  END t1b[59]
  PIN t1b[5]
    DIRECTION INPUT ;
    USE SIGNAL ;
    PORT
      LAYER M5 ;
        RECT  68.112 0 68.136 0.084 ;
    END
  END t1b[5]
  PIN t1b[60]
    DIRECTION INPUT ;
    USE SIGNAL ;
    PORT
      LAYER M5 ;
        RECT  61.104 0 61.128 0.084 ;
    END
  END t1b[60]
  PIN t1b[61]
    DIRECTION INPUT ;
    USE SIGNAL ;
    PORT
      LAYER M5 ;
        RECT  61.2 0 61.224 0.084 ;
    END
  END t1b[61]
  PIN t1b[62]
    DIRECTION INPUT ;
    USE SIGNAL ;
    PORT
      LAYER M5 ;
        RECT  61.296 0 61.32 0.084 ;
    END
  END t1b[62]
  PIN t1b[63]
    DIRECTION INPUT ;
    USE SIGNAL ;
    PORT
      LAYER M5 ;
        RECT  32.208 0 32.232 0.084 ;
    END
  END t1b[63]
  PIN t1b[64]
    DIRECTION INPUT ;
    USE SIGNAL ;
    PORT
      LAYER M5 ;
        RECT  32.304 0 32.328 0.084 ;
    END
  END t1b[64]
  PIN t1b[65]
    DIRECTION INPUT ;
    USE SIGNAL ;
    PORT
      LAYER M5 ;
        RECT  32.4 0 32.424 0.084 ;
    END
  END t1b[65]
  PIN t1b[66]
    DIRECTION INPUT ;
    USE SIGNAL ;
    PORT
      LAYER M5 ;
        RECT  32.496 0 32.52 0.084 ;
    END
  END t1b[66]
  PIN t1b[67]
    DIRECTION INPUT ;
    USE SIGNAL ;
    PORT
      LAYER M5 ;
        RECT  32.592 0 32.616 0.084 ;
    END
  END t1b[67]
  PIN t1b[68]
    DIRECTION INPUT ;
    USE SIGNAL ;
    PORT
      LAYER M5 ;
        RECT  32.688 0 32.712 0.084 ;
    END
  END t1b[68]
  PIN t1b[69]
    DIRECTION INPUT ;
    USE SIGNAL ;
    PORT
      LAYER M5 ;
        RECT  32.784 0 32.808 0.084 ;
    END
  END t1b[69]
  PIN t1b[6]
    DIRECTION INPUT ;
    USE SIGNAL ;
    PORT
      LAYER M5 ;
        RECT  68.208 0 68.232 0.084 ;
    END
  END t1b[6]
  PIN t1b[70]
    DIRECTION INPUT ;
    USE SIGNAL ;
    PORT
      LAYER M5 ;
        RECT  32.88 0 32.904 0.084 ;
    END
  END t1b[70]
  PIN t1b[71]
    DIRECTION INPUT ;
    USE SIGNAL ;
    PORT
      LAYER M5 ;
        RECT  32.976 0 33 0.084 ;
    END
  END t1b[71]
  PIN t1b[72]
    DIRECTION INPUT ;
    USE SIGNAL ;
    PORT
      LAYER M5 ;
        RECT  33.072 0 33.096 0.084 ;
    END
  END t1b[72]
  PIN t1b[73]
    DIRECTION INPUT ;
    USE SIGNAL ;
    PORT
      LAYER M5 ;
        RECT  33.168 0 33.192 0.084 ;
    END
  END t1b[73]
  PIN t1b[74]
    DIRECTION INPUT ;
    USE SIGNAL ;
    PORT
      LAYER M5 ;
        RECT  33.264 0 33.288 0.084 ;
    END
  END t1b[74]
  PIN t1b[75]
    DIRECTION INPUT ;
    USE SIGNAL ;
    PORT
      LAYER M5 ;
        RECT  33.36 0 33.384 0.084 ;
    END
  END t1b[75]
  PIN t1b[76]
    DIRECTION INPUT ;
    USE SIGNAL ;
    PORT
      LAYER M5 ;
        RECT  33.456 0 33.48 0.084 ;
    END
  END t1b[76]
  PIN t1b[77]
    DIRECTION INPUT ;
    USE SIGNAL ;
    PORT
      LAYER M5 ;
        RECT  33.552 0 33.576 0.084 ;
    END
  END t1b[77]
  PIN t1b[78]
    DIRECTION INPUT ;
    USE SIGNAL ;
    PORT
      LAYER M5 ;
        RECT  33.648 0 33.672 0.084 ;
    END
  END t1b[78]
  PIN t1b[79]
    DIRECTION INPUT ;
    USE SIGNAL ;
    PORT
      LAYER M5 ;
        RECT  33.744 0 33.768 0.084 ;
    END
  END t1b[79]
  PIN t1b[7]
    DIRECTION INPUT ;
    USE SIGNAL ;
    PORT
      LAYER M5 ;
        RECT  68.304 0 68.328 0.084 ;
    END
  END t1b[7]
  PIN t1b[80]
    DIRECTION INPUT ;
    USE SIGNAL ;
    PORT
      LAYER M5 ;
        RECT  33.84 0 33.864 0.084 ;
    END
  END t1b[80]
  PIN t1b[81]
    DIRECTION INPUT ;
    USE SIGNAL ;
    PORT
      LAYER M5 ;
        RECT  33.936 0 33.96 0.084 ;
    END
  END t1b[81]
  PIN t1b[82]
    DIRECTION INPUT ;
    USE SIGNAL ;
    PORT
      LAYER M5 ;
        RECT  34.032 0 34.056 0.084 ;
    END
  END t1b[82]
  PIN t1b[83]
    DIRECTION INPUT ;
    USE SIGNAL ;
    PORT
      LAYER M5 ;
        RECT  34.128 0 34.152 0.084 ;
    END
  END t1b[83]
  PIN t1b[84]
    DIRECTION INPUT ;
    USE SIGNAL ;
    PORT
      LAYER M5 ;
        RECT  34.224 0 34.248 0.084 ;
    END
  END t1b[84]
  PIN t1b[85]
    DIRECTION INPUT ;
    USE SIGNAL ;
    PORT
      LAYER M5 ;
        RECT  34.32 0 34.344 0.084 ;
    END
  END t1b[85]
  PIN t1b[86]
    DIRECTION INPUT ;
    USE SIGNAL ;
    PORT
      LAYER M5 ;
        RECT  34.416 0 34.44 0.084 ;
    END
  END t1b[86]
  PIN t1b[87]
    DIRECTION INPUT ;
    USE SIGNAL ;
    PORT
      LAYER M5 ;
        RECT  34.512 0 34.536 0.084 ;
    END
  END t1b[87]
  PIN t1b[88]
    DIRECTION INPUT ;
    USE SIGNAL ;
    PORT
      LAYER M5 ;
        RECT  34.608 0 34.632 0.084 ;
    END
  END t1b[88]
  PIN t1b[89]
    DIRECTION INPUT ;
    USE SIGNAL ;
    PORT
      LAYER M5 ;
        RECT  34.704 0 34.728 0.084 ;
    END
  END t1b[89]
  PIN t1b[8]
    DIRECTION INPUT ;
    USE SIGNAL ;
    PORT
      LAYER M5 ;
        RECT  68.4 0 68.424 0.084 ;
    END
  END t1b[8]
  PIN t1b[90]
    DIRECTION INPUT ;
    USE SIGNAL ;
    PORT
      LAYER M5 ;
        RECT  34.8 0 34.824 0.084 ;
    END
  END t1b[90]
  PIN t1b[91]
    DIRECTION INPUT ;
    USE SIGNAL ;
    PORT
      LAYER M5 ;
        RECT  34.896 0 34.92 0.084 ;
    END
  END t1b[91]
  PIN t1b[92]
    DIRECTION INPUT ;
    USE SIGNAL ;
    PORT
      LAYER M5 ;
        RECT  34.992 0 35.016 0.084 ;
    END
  END t1b[92]
  PIN t1b[93]
    DIRECTION INPUT ;
    USE SIGNAL ;
    PORT
      LAYER M5 ;
        RECT  35.088 0 35.112 0.084 ;
    END
  END t1b[93]
  PIN t1b[94]
    DIRECTION INPUT ;
    USE SIGNAL ;
    PORT
      LAYER M5 ;
        RECT  35.184 0 35.208 0.084 ;
    END
  END t1b[94]
  PIN t1b[95]
    DIRECTION INPUT ;
    USE SIGNAL ;
    PORT
      LAYER M5 ;
        RECT  51.408 0 51.432 0.084 ;
    END
  END t1b[95]
  PIN t1b[96]
    DIRECTION INPUT ;
    USE SIGNAL ;
    PORT
      LAYER M5 ;
        RECT  51.504 0 51.528 0.084 ;
    END
  END t1b[96]
  PIN t1b[97]
    DIRECTION INPUT ;
    USE SIGNAL ;
    PORT
      LAYER M5 ;
        RECT  51.6 0 51.624 0.084 ;
    END
  END t1b[97]
  PIN t1b[98]
    DIRECTION INPUT ;
    USE SIGNAL ;
    PORT
      LAYER M5 ;
        RECT  51.696 0 51.72 0.084 ;
    END
  END t1b[98]
  PIN t1b[99]
    DIRECTION INPUT ;
    USE SIGNAL ;
    PORT
      LAYER M5 ;
        RECT  51.792 0 51.816 0.084 ;
    END
  END t1b[99]
  PIN t1b[9]
    DIRECTION INPUT ;
    USE SIGNAL ;
    PORT
      LAYER M5 ;
        RECT  68.496 0 68.52 0.084 ;
    END
  END t1b[9]
  PIN xv
    DIRECTION INPUT ;
    USE SIGNAL ;
    PORT
      LAYER M4 ;
        RECT  0 13.008 0.084 13.032 ;
    END
  END xv
  PIN VDD
    DIRECTION INOUT ;
    USE POWER ;
    PORT
      LAYER M5 ;
        RECT  110.592 2.151 110.712 23.769 ;
        RECT  105.192 2.151 105.312 23.769 ;
        RECT  99.792 2.151 99.912 23.769 ;
        RECT  94.392 2.151 94.512 23.769 ;
        RECT  88.992 2.151 89.112 23.769 ;
        RECT  83.592 2.151 83.712 23.769 ;
        RECT  78.192 2.151 78.312 23.769 ;
        RECT  72.792 2.151 72.912 23.769 ;
        RECT  67.392 2.151 67.512 23.769 ;
        RECT  61.992 2.151 62.112 23.769 ;
        RECT  56.592 2.151 56.712 23.769 ;
        RECT  51.192 2.151 51.312 23.769 ;
        RECT  45.792 2.151 45.912 23.769 ;
        RECT  40.392 2.151 40.512 23.769 ;
        RECT  34.992 2.151 35.112 23.769 ;
        RECT  29.592 2.151 29.712 23.769 ;
        RECT  24.192 2.151 24.312 23.769 ;
        RECT  18.792 2.151 18.912 23.769 ;
        RECT  13.392 2.151 13.512 23.769 ;
        RECT  7.992 2.151 8.112 23.769 ;
        RECT  2.592 2.151 2.712 23.769 ;
    END
  END VDD
  PIN VSS
    DIRECTION INOUT ;
    USE GROUND ;
    PORT
      LAYER M5 ;
        RECT  110.4 2.137 110.52 23.783 ;
        RECT  105 2.137 105.12 23.783 ;
        RECT  99.6 2.137 99.72 23.783 ;
        RECT  94.2 2.137 94.32 23.783 ;
        RECT  88.8 2.137 88.92 23.783 ;
        RECT  83.4 2.137 83.52 23.783 ;
        RECT  78 2.137 78.12 23.783 ;
        RECT  72.6 2.137 72.72 23.783 ;
        RECT  67.2 2.137 67.32 23.783 ;
        RECT  61.8 2.137 61.92 23.783 ;
        RECT  56.4 2.137 56.52 23.783 ;
        RECT  51 2.137 51.12 23.783 ;
        RECT  45.6 2.137 45.72 23.783 ;
        RECT  40.2 2.137 40.32 23.783 ;
        RECT  34.8 2.137 34.92 23.783 ;
        RECT  29.4 2.137 29.52 23.783 ;
        RECT  24 2.137 24.12 23.783 ;
        RECT  18.6 2.137 18.72 23.783 ;
        RECT  13.2 2.137 13.32 23.783 ;
        RECT  7.8 2.137 7.92 23.783 ;
        RECT  2.4 2.137 2.52 23.783 ;
    END
  END VSS
  # OT_OBS_CLOSED layer=M5 d_um=1.536 added=219
  OBS
    LAYER RVTN ;
     RECT  2.16 2.16 114.48 2.295 ;
     RECT  2.16 2.565 114.48 2.835 ;
     RECT  2.16 3.105 114.48 3.375 ;
     RECT  2.16 3.645 114.48 3.915 ;
     RECT  2.16 4.185 114.48 4.455 ;
     RECT  2.16 4.725 114.48 4.995 ;
     RECT  2.16 5.265 114.48 5.535 ;
     RECT  2.16 5.805 114.48 6.075 ;
     RECT  2.16 6.345 114.48 6.615 ;
     RECT  2.16 6.885 114.48 7.155 ;
     RECT  2.16 7.425 114.48 7.695 ;
     RECT  2.16 7.965 114.48 8.235 ;
     RECT  2.16 8.505 114.48 8.775 ;
     RECT  2.16 9.045 114.48 9.315 ;
     RECT  2.16 9.585 114.48 9.855 ;
     RECT  2.16 10.125 114.48 10.395 ;
     RECT  2.16 10.665 114.48 10.935 ;
     RECT  2.16 11.205 114.48 11.475 ;
     RECT  2.16 11.745 114.48 12.015 ;
     RECT  2.16 12.285 114.48 12.555 ;
     RECT  2.16 12.825 114.48 13.095 ;
     RECT  2.16 13.365 114.48 13.635 ;
     RECT  2.16 13.905 114.48 14.175 ;
     RECT  2.16 14.445 114.48 14.715 ;
     RECT  2.16 14.985 114.48 15.255 ;
     RECT  2.16 15.525 114.48 15.795 ;
     RECT  2.16 16.065 114.48 16.335 ;
     RECT  2.16 16.605 114.48 16.875 ;
     RECT  2.16 17.145 114.48 17.415 ;
     RECT  2.16 17.685 114.48 17.955 ;
     RECT  2.16 18.225 114.48 18.495 ;
     RECT  2.16 18.765 114.48 19.035 ;
     RECT  2.16 19.305 114.48 19.575 ;
     RECT  2.16 19.845 114.48 20.115 ;
     RECT  2.16 20.385 114.48 20.655 ;
     RECT  2.16 20.925 114.48 21.195 ;
     RECT  2.16 21.465 114.48 21.735 ;
     RECT  2.16 22.005 114.48 22.275 ;
     RECT  2.16 22.545 114.48 22.815 ;
     RECT  2.16 23.085 114.48 23.355 ;
     RECT  2.16 23.625 114.48 23.76 ;
    LAYER RVTP ;
     RECT  2.16 2.295 114.48 2.565 ;
     RECT  2.16 2.835 114.48 3.105 ;
     RECT  2.16 3.375 114.48 3.645 ;
     RECT  2.16 3.915 114.48 4.185 ;
     RECT  2.16 4.455 114.48 4.725 ;
     RECT  2.16 4.995 114.48 5.265 ;
     RECT  2.16 5.535 114.48 5.805 ;
     RECT  2.16 6.075 114.48 6.345 ;
     RECT  2.16 6.615 114.48 6.885 ;
     RECT  2.16 7.155 114.48 7.425 ;
     RECT  2.16 7.695 114.48 7.965 ;
     RECT  2.16 8.235 114.48 8.505 ;
     RECT  2.16 8.775 114.48 9.045 ;
     RECT  2.16 9.315 114.48 9.585 ;
     RECT  2.16 9.855 114.48 10.125 ;
     RECT  2.16 10.395 114.48 10.665 ;
     RECT  2.16 10.935 114.48 11.205 ;
     RECT  2.16 11.475 114.48 11.745 ;
     RECT  2.16 12.015 114.48 12.285 ;
     RECT  2.16 12.555 114.48 12.825 ;
     RECT  2.16 13.095 114.48 13.365 ;
     RECT  2.16 13.635 114.48 13.905 ;
     RECT  2.16 14.175 114.48 14.445 ;
     RECT  2.16 14.715 114.48 14.985 ;
     RECT  2.16 15.255 114.48 15.525 ;
     RECT  2.16 15.795 114.48 16.065 ;
     RECT  2.16 16.335 114.48 16.605 ;
     RECT  2.16 16.875 114.48 17.145 ;
     RECT  2.16 17.415 114.48 17.685 ;
     RECT  2.16 17.955 114.48 18.225 ;
     RECT  2.16 18.495 114.48 18.765 ;
     RECT  2.16 19.035 114.48 19.305 ;
     RECT  2.16 19.575 114.48 19.845 ;
     RECT  2.16 20.115 114.48 20.385 ;
     RECT  2.16 20.655 114.48 20.925 ;
     RECT  2.16 21.195 114.48 21.465 ;
     RECT  2.16 21.735 114.48 22.005 ;
     RECT  2.16 22.275 114.48 22.545 ;
     RECT  2.16 22.815 114.48 23.085 ;
     RECT  2.16 23.355 114.48 23.625 ;
    LAYER M1 ;
     RECT  2.16 2.151 114.48 23.769 ;
    LAYER M2 ;
     RECT  0.103 11.952 2.16 12.546 ;
     RECT  2.16 2.151 13.207 23.769 ;
     RECT  13.207 2.151 14.099 23.85 ;
     RECT  14.099 2.151 17.059 23.769 ;
     RECT  17.059 2.106 20.047 23.769 ;
     RECT  20.047 2.034 20.587 23.769 ;
     RECT  20.335 0.072 20.875 0.09 ;
     RECT  20.587 1.998 22.423 23.769 ;
     RECT  20.875 0.036 22.963 0.09 ;
     RECT  22.423 1.962 25.807 23.769 ;
     RECT  25.807 1.962 27.715 23.814 ;
     RECT  27.715 1.926 28.651 23.814 ;
     RECT  28.651 1.764 30.775 23.814 ;
     RECT  30.775 1.764 31.603 23.886 ;
     RECT  31.603 1.728 32.783 23.886 ;
     RECT  32.783 1.764 33.719 23.886 ;
     RECT  33.719 1.764 35.339 23.769 ;
     RECT  35.339 1.998 36.463 23.769 ;
     RECT  22.963 0.036 36.671 0.126 ;
     RECT  36.463 1.836 37.183 23.769 ;
     RECT  36.671 0.036 37.319 0.09 ;
     RECT  37.183 1.8 38.183 23.769 ;
     RECT  38.183 1.836 40.847 23.769 ;
     RECT  40.847 2.034 42.871 23.769 ;
     RECT  42.871 1.962 43.367 23.769 ;
     RECT  43.367 2.034 43.439 23.769 ;
     RECT  43.439 2.106 44.599 23.769 ;
     RECT  44.599 2.034 45.167 23.769 ;
     RECT  45.167 2.151 48.199 23.769 ;
     RECT  48.199 2.034 48.911 23.769 ;
     RECT  49.351 25.056 49.451 25.074 ;
     RECT  48.911 2.106 50.279 23.769 ;
     RECT  50.575 25.056 50.675 25.074 ;
     RECT  50.279 2.151 55.939 23.769 ;
     RECT  55.939 2.106 56.371 23.769 ;
     RECT  56.371 1.998 57.775 23.769 ;
     RECT  57.775 1.962 58.063 23.769 ;
     RECT  58.063 1.926 66.559 23.769 ;
     RECT  66.559 1.881 66.703 23.769 ;
     RECT  66.703 1.836 66.739 23.769 ;
     RECT  66.739 1.764 69.259 23.769 ;
     RECT  69.259 1.764 69.359 24.084 ;
     RECT  69.359 1.764 69.719 23.769 ;
     RECT  69.655 25.056 69.863 25.074 ;
     RECT  69.719 1.881 70.295 23.769 ;
     RECT  70.295 2.034 71.239 23.769 ;
     RECT  71.239 1.962 72.527 23.769 ;
     RECT  72.527 1.998 73.507 23.769 ;
     RECT  73.507 1.926 74.075 23.769 ;
     RECT  74.075 2.034 75.595 23.769 ;
     RECT  75.883 25.056 75.919 25.074 ;
     RECT  75.919 25.02 76.055 25.074 ;
     RECT  76.055 25.056 76.163 25.074 ;
     RECT  75.595 1.926 76.963 23.769 ;
     RECT  37.319 0.036 77.567 0.054 ;
     RECT  81.319 25.056 81.419 25.074 ;
     RECT  76.963 1.728 81.599 23.769 ;
     RECT  81.599 1.881 83.767 23.769 ;
     RECT  83.767 1.836 84.199 23.769 ;
     RECT  84.415 25.056 84.631 25.074 ;
     RECT  84.631 24.984 84.659 25.074 ;
     RECT  84.659 24.984 84.731 25.002 ;
     RECT  84.199 1.836 84.919 23.814 ;
     RECT  84.919 1.8 85.883 23.814 ;
     RECT  85.883 1.8 86.647 23.769 ;
     RECT  87.223 25.056 87.323 25.074 ;
     RECT  86.647 1.728 88.843 23.769 ;
     RECT  88.843 1.728 89.303 23.85 ;
     RECT  89.303 1.8 89.339 23.85 ;
     RECT  89.339 1.8 90.023 23.769 ;
     RECT  90.859 24.948 91.175 24.966 ;
     RECT  90.023 1.836 91.967 23.769 ;
     RECT  94.891 25.056 94.963 25.074 ;
     RECT  94.963 24.984 95.135 25.074 ;
     RECT  91.967 1.926 95.351 23.769 ;
     RECT  95.351 2.07 95.747 23.769 ;
     RECT  95.747 2.106 96.071 23.769 ;
     RECT  96.071 2.151 103.855 23.769 ;
     RECT  103.855 2.151 104.143 23.814 ;
     RECT  104.143 2.151 106.582 23.886 ;
     RECT  106.582 2.151 108.419 23.922 ;
     RECT  108.419 2.151 109.255 23.814 ;
     RECT  109.255 2.151 110.615 23.886 ;
     RECT  110.615 2.151 114.48 23.769 ;
    LAYER M3 ;
     RECT  20.88 0.031 20.898 0.067 ;
     RECT  37.296 0.067 37.314 0.103 ;
     RECT  40.068 0.091 40.806 0.139 ;
     RECT  43.992 0.091 44.01 0.139 ;
     RECT  36.648 0.103 37.314 0.173 ;
     RECT  77.544 0.031 77.562 0.173 ;
     RECT  30.132 0.139 30.15 0.187 ;
     RECT  43.992 0.139 44.118 0.187 ;
     RECT  89.352 0.091 89.37 0.187 ;
     RECT  31.572 0.235 31.59 0.283 ;
     RECT  33.084 0.235 33.678 0.283 ;
     RECT  34.524 0.235 34.542 0.283 ;
     RECT  77.616 0.187 77.634 0.317 ;
     RECT  30.132 0.187 30.366 0.331 ;
     RECT  31.284 0.283 31.59 0.331 ;
     RECT  24.984 0.091 25.002 0.427 ;
     RECT  37.044 0.173 37.314 0.427 ;
     RECT  37.044 0.427 37.602 0.475 ;
     RECT  42.768 0.475 42.786 0.523 ;
     RECT  45.54 0.091 45.558 0.523 ;
     RECT  33.084 0.283 34.542 0.571 ;
     RECT  37.044 0.475 37.782 0.571 ;
     RECT  39.672 0.139 41.454 0.571 ;
     RECT  42.768 0.523 42.858 0.571 ;
     RECT  43.956 0.187 44.118 0.571 ;
     RECT  49.032 0.523 49.05 0.571 ;
     RECT  50.184 0.091 50.202 0.571 ;
     RECT  51.264 0.091 51.282 0.571 ;
     RECT  52.38 0.091 52.398 0.571 ;
     RECT  58.68 0.091 58.698 0.571 ;
     RECT  37.044 0.571 37.818 0.619 ;
     RECT  48.528 0.571 50.274 0.619 ;
     RECT  20.34 0.067 20.898 0.955 ;
     RECT  20.34 0.955 21.438 1.003 ;
     RECT  37.044 0.619 38.178 1.099 ;
     RECT  48.528 0.619 50.346 1.099 ;
     RECT  58.68 0.571 59.958 1.099 ;
     RECT  37.008 1.099 38.178 1.147 ;
     RECT  38.988 0.571 41.706 1.147 ;
     RECT  42.768 0.571 44.118 1.147 ;
     RECT  45.072 0.523 45.558 1.147 ;
     RECT  47.304 0.523 47.322 1.147 ;
     RECT  48.348 1.099 50.346 1.147 ;
     RECT  51.264 0.571 52.47 1.147 ;
     RECT  58.464 1.099 59.958 1.147 ;
     RECT  61.092 0.571 61.11 1.147 ;
     RECT  18 0.859 18.018 1.387 ;
     RECT  86.004 0.235 86.022 1.387 ;
     RECT  17.892 1.387 18.018 1.435 ;
     RECT  19.08 0.907 19.098 1.435 ;
     RECT  80.532 0.859 80.55 1.435 ;
     RECT  88.704 0.187 89.37 1.435 ;
     RECT  17.892 1.435 19.098 1.483 ;
     RECT  88.704 1.435 89.406 1.483 ;
     RECT  22.968 0.103 22.986 1.531 ;
     RECT  88.38 1.483 89.406 1.531 ;
     RECT  87.444 0.859 87.462 1.579 ;
     RECT  88.272 1.531 89.406 1.579 ;
     RECT  30.132 0.331 31.59 1.723 ;
     RECT  32.472 0.571 34.542 1.723 ;
     RECT  35.316 0.283 35.334 1.723 ;
     RECT  37.008 1.147 45.558 1.723 ;
     RECT  47.304 1.147 47.394 1.723 ;
     RECT  48.348 1.147 52.47 1.723 ;
     RECT  53.856 0.091 53.874 1.723 ;
     RECT  56.304 1.675 56.322 1.723 ;
     RECT  58.464 1.147 61.11 1.723 ;
     RECT  67.572 0.091 67.59 1.723 ;
     RECT  77.868 1.675 77.886 1.723 ;
     RECT  78.804 0.091 78.822 1.723 ;
     RECT  80.532 1.435 80.946 1.723 ;
     RECT  83.736 0.571 83.754 1.723 ;
     RECT  85.5 1.387 86.022 1.723 ;
     RECT  58.464 1.723 69.282 1.759 ;
     RECT  70.128 1.723 71.226 1.759 ;
     RECT  30.132 1.723 31.626 1.771 ;
     RECT  32.472 1.723 35.334 1.771 ;
     RECT  56.304 1.723 56.574 1.771 ;
     RECT  57.6 1.723 57.618 1.771 ;
     RECT  58.464 1.759 71.226 1.771 ;
     RECT  72 1.723 73.854 1.771 ;
     RECT  74.916 1.723 74.934 1.771 ;
     RECT  85.5 1.723 86.67 1.771 ;
     RECT  30.132 1.771 35.334 1.787 ;
     RECT  87.444 1.579 89.406 1.795 ;
     RECT  37.008 1.723 54.702 1.819 ;
     RECT  56.232 1.771 73.854 1.819 ;
     RECT  76.968 1.723 76.986 1.819 ;
     RECT  77.868 1.723 81.594 1.819 ;
     RECT  82.692 1.771 82.71 1.819 ;
     RECT  37.008 1.819 73.854 1.831 ;
     RECT  83.556 1.723 83.754 1.831 ;
     RECT  84.924 1.771 86.67 1.831 ;
     RECT  87.444 1.795 90.018 1.831 ;
     RECT  36.468 1.831 73.854 1.867 ;
     RECT  74.664 1.771 74.934 1.867 ;
     RECT  76.968 1.819 81.594 1.867 ;
     RECT  82.692 1.819 82.782 1.867 ;
     RECT  84.924 1.831 90.018 1.876 ;
     RECT  36.468 1.867 74.934 1.921 ;
     RECT  83.556 1.831 83.79 1.921 ;
     RECT  20.34 1.003 21.798 1.957 ;
     RECT  22.968 1.531 23.346 1.957 ;
     RECT  93.456 0.811 93.474 1.957 ;
     RECT  36.468 1.921 75.618 1.963 ;
     RECT  95.328 1.921 95.346 1.993 ;
     RECT  17.892 1.483 19.422 2.029 ;
     RECT  20.34 1.957 23.346 2.029 ;
     RECT  28.656 1.759 28.674 2.029 ;
     RECT  91.944 1.831 91.962 2.029 ;
     RECT  93.204 1.957 93.474 2.029 ;
     RECT  30.132 1.787 35.154 2.059 ;
     RECT  83.556 1.921 84.042 2.065 ;
     RECT  84.816 1.876 90.27 2.065 ;
     RECT  93.204 2.029 94.014 2.065 ;
     RECT  94.86 1.993 95.346 2.065 ;
     RECT  36.468 1.963 75.798 2.101 ;
     RECT  76.536 1.867 82.782 2.101 ;
     RECT  91.944 2.029 92.178 2.101 ;
     RECT  94.86 2.065 95.742 2.101 ;
     RECT  17.892 2.029 23.346 2.143 ;
     RECT  24.444 0.427 25.002 2.143 ;
     RECT  29.592 2.059 35.154 2.143 ;
     RECT  36.468 2.101 82.782 2.143 ;
     RECT  83.556 2.065 90.27 2.143 ;
     RECT  93.132 2.065 94.014 2.143 ;
     RECT  94.86 2.101 96.066 2.143 ;
     RECT  17.064 2.101 17.082 2.191 ;
     RECT  17.892 2.143 25.002 2.191 ;
     RECT  27.72 1.921 27.738 2.191 ;
     RECT  36.468 2.143 90.27 2.191 ;
     RECT  91.116 0.139 91.134 2.191 ;
     RECT  91.944 2.101 92.322 2.191 ;
     RECT  93.132 2.143 96.066 2.191 ;
     RECT  27.72 2.191 27.882 2.255 ;
     RECT  35.964 2.191 91.206 2.255 ;
     RECT  27.792 2.255 27.882 2.263 ;
     RECT  28.62 2.029 28.674 2.263 ;
     RECT  2.415 2.143 2.505 2.413 ;
     RECT  7.815 2.143 7.905 2.413 ;
     RECT  13.215 2.143 13.305 2.413 ;
     RECT  99.615 2.143 99.705 2.413 ;
     RECT  105.015 2.143 105.105 2.413 ;
     RECT  110.415 2.143 110.505 2.413 ;
     RECT  27.792 2.263 28.674 2.497 ;
     RECT  29.415 2.143 35.154 2.497 ;
     RECT  90.684 2.255 91.206 2.497 ;
     RECT  91.944 2.191 96.246 2.497 ;
     RECT  17.064 2.191 25.002 2.525 ;
     RECT  23.724 2.525 25.002 2.641 ;
     RECT  27.792 2.497 35.154 2.731 ;
     RECT  35.964 2.255 89.766 2.731 ;
     RECT  23.724 2.641 25.398 2.831 ;
     RECT  17.064 2.525 22.662 3.065 ;
     RECT  27.792 2.731 89.766 3.065 ;
     RECT  27.864 3.065 84.546 3.299 ;
     RECT  23.724 2.831 25.29 3.379 ;
     RECT  17.064 3.065 21.15 3.407 ;
     RECT  27.864 3.299 84.51 6.449 ;
     RECT  56.232 6.449 84.51 7.429 ;
     RECT  56.124 7.429 84.51 7.435 ;
     RECT  90.684 2.497 96.246 7.465 ;
     RECT  56.052 7.435 84.51 7.627 ;
     RECT  27.864 6.449 55.17 7.735 ;
     RECT  55.944 7.627 84.51 7.735 ;
     RECT  107.172 7.735 107.19 7.771 ;
     RECT  107.172 7.771 107.514 7.861 ;
     RECT  107.172 7.861 107.586 7.889 ;
     RECT  27.864 7.735 84.51 7.925 ;
     RECT  109.404 7.897 109.422 7.933 ;
     RECT  107.496 7.889 107.586 7.969 ;
     RECT  55.98 7.925 84.51 7.997 ;
     RECT  23.58 3.379 25.29 8.239 ;
     RECT  109.404 7.933 109.602 8.239 ;
     RECT  27.864 7.925 55.17 8.267 ;
     RECT  107.496 7.969 107.982 8.275 ;
     RECT  109.116 8.239 109.602 8.545 ;
     RECT  110.415 2.413 110.697 8.545 ;
     RECT  107.496 8.275 108.27 8.707 ;
     RECT  28.62 8.267 55.17 8.815 ;
     RECT  56.052 7.997 84.51 8.815 ;
     RECT  107.388 8.707 108.27 8.851 ;
     RECT  28.62 8.815 84.51 8.969 ;
     RECT  56.052 8.969 84.51 9.077 ;
     RECT  107.388 8.851 108.378 9.085 ;
     RECT  109.116 8.545 110.697 9.085 ;
     RECT  22.356 3.065 22.662 9.121 ;
     RECT  23.58 8.239 25.326 9.121 ;
     RECT  107.388 9.085 110.697 9.121 ;
     RECT  85.284 3.065 89.766 9.149 ;
     RECT  28.62 8.969 55.17 9.931 ;
     RECT  56.088 9.077 84.51 9.931 ;
     RECT  26.388 3.181 26.406 10.831 ;
     RECT  85.284 9.149 89.514 10.831 ;
     RECT  90.684 7.465 96.678 10.859 ;
     RECT  22.356 9.121 25.326 10.867 ;
     RECT  22.356 10.867 25.614 10.975 ;
     RECT  26.388 10.831 26.478 10.975 ;
     RECT  27.864 8.267 27.882 10.975 ;
     RECT  105.015 2.413 105.297 10.975 ;
     RECT  20.916 3.407 21.15 11.011 ;
     RECT  22.14 10.975 26.478 11.011 ;
     RECT  20.916 11.011 26.478 11.101 ;
     RECT  27.396 10.975 27.882 11.101 ;
     RECT  20.916 11.101 27.882 11.137 ;
     RECT  28.62 9.931 84.51 11.137 ;
     RECT  5.976 11.137 5.994 11.173 ;
     RECT  5.796 11.173 5.994 11.209 ;
     RECT  5.148 11.209 5.994 11.281 ;
     RECT  104.652 10.975 105.297 11.281 ;
     RECT  5.148 11.281 6.174 11.371 ;
     RECT  17.064 3.407 20.07 11.443 ;
     RECT  20.916 11.137 84.51 11.443 ;
     RECT  85.284 10.831 89.694 11.443 ;
     RECT  4.536 11.371 6.174 11.515 ;
     RECT  17.064 11.443 89.694 11.515 ;
     RECT  4.248 11.515 6.174 11.551 ;
     RECT  13.215 2.413 13.497 11.677 ;
     RECT  17.028 11.515 89.694 11.677 ;
     RECT  101.988 11.443 102.006 11.713 ;
     RECT  107.1 9.121 110.697 11.713 ;
     RECT  13.215 11.677 14.13 11.755 ;
     RECT  4.248 11.551 6.39 11.821 ;
     RECT  12.492 11.755 14.13 11.821 ;
     RECT  16.164 11.749 16.182 11.821 ;
     RECT  16.992 11.677 89.694 11.821 ;
     RECT  3.996 11.821 6.39 11.911 ;
     RECT  16.164 11.821 89.694 11.911 ;
     RECT  15.588 11.911 89.694 11.939 ;
     RECT  101.988 11.713 102.69 11.939 ;
     RECT  106.704 11.713 110.697 11.947 ;
     RECT  15.588 11.939 84.51 11.975 ;
     RECT  2.415 2.413 2.697 11.995 ;
     RECT  11.952 11.821 14.634 12.019 ;
     RECT  90.828 10.859 96.678 12.019 ;
     RECT  11.952 12.019 14.814 12.055 ;
     RECT  15.588 11.975 26.838 12.055 ;
     RECT  101.808 11.947 101.826 12.055 ;
     RECT  3.816 11.911 6.39 12.083 ;
     RECT  3.996 12.083 6.39 12.209 ;
     RECT  90.648 12.019 96.678 12.209 ;
     RECT  4.392 12.209 6.39 12.217 ;
     RECT  7.815 2.413 8.097 12.217 ;
     RECT  10.944 11.911 10.962 12.217 ;
     RECT  4.392 12.217 8.097 12.245 ;
     RECT  11.952 12.055 26.838 12.281 ;
     RECT  106.02 11.947 110.697 12.317 ;
     RECT  2.415 11.995 3.078 12.325 ;
     RECT  11.952 12.281 26.694 12.325 ;
     RECT  104.04 11.281 105.297 12.325 ;
     RECT  102.6 11.939 102.69 12.353 ;
     RECT  2.34 12.325 3.078 12.361 ;
     RECT  5.688 12.245 8.097 12.361 ;
     RECT  9.576 12.217 10.962 12.361 ;
     RECT  11.736 12.325 26.694 12.361 ;
     RECT  103.896 12.325 105.297 12.427 ;
     RECT  5.688 12.361 8.406 12.451 ;
     RECT  9.468 12.361 26.694 12.451 ;
     RECT  2.34 12.361 3.222 12.479 ;
     RECT  101.772 12.055 101.826 12.487 ;
     RECT  112.212 12.217 112.23 12.487 ;
     RECT  5.688 12.451 26.694 12.515 ;
     RECT  103.752 12.427 105.297 12.515 ;
     RECT  4.824 12.245 4.842 12.551 ;
     RECT  98.604 12.451 98.622 12.551 ;
     RECT  0.108 11.947 0.126 12.56 ;
     RECT  27.864 11.975 84.51 12.587 ;
     RECT  101.556 12.487 101.826 12.595 ;
     RECT  17.064 12.515 22.77 12.623 ;
     RECT  5.688 12.515 16.29 12.749 ;
     RECT  104.256 12.515 105.297 12.757 ;
     RECT  5.688 12.749 15.534 12.785 ;
     RECT  5.688 12.785 14.994 12.857 ;
     RECT  101.484 12.595 101.826 12.857 ;
     RECT  101.772 12.857 101.826 12.901 ;
     RECT  2.34 12.479 2.697 13.003 ;
     RECT  10.872 12.857 14.994 13.019 ;
     RECT  16.272 12.749 16.29 13.019 ;
     RECT  101.772 12.901 102.294 13.019 ;
     RECT  111.708 12.487 112.23 13.027 ;
     RECT  1.152 12.907 1.17 13.085 ;
     RECT  4.5 13.051 4.518 13.091 ;
     RECT  6.264 12.857 9.702 13.091 ;
     RECT  7.38 13.091 9.702 13.127 ;
     RECT  10.872 13.019 14.922 13.163 ;
     RECT  90.828 12.209 96.678 13.171 ;
     RECT  23.58 12.515 26.694 13.261 ;
     RECT  5.256 13.099 5.49 13.289 ;
     RECT  7.815 13.127 9.702 13.289 ;
     RECT  14.76 13.163 14.922 13.289 ;
     RECT  2.268 13.003 2.697 13.325 ;
     RECT  8.928 13.289 9.702 13.325 ;
     RECT  10.872 13.163 13.95 13.325 ;
     RECT  14.76 13.289 14.778 13.325 ;
     RECT  103.068 12.523 103.482 13.369 ;
     RECT  5.328 13.289 5.49 13.373 ;
     RECT  7.815 13.289 8.154 13.373 ;
     RECT  11.52 13.325 13.95 13.397 ;
     RECT  23.58 13.261 26.766 13.397 ;
     RECT  5.472 13.373 5.49 13.559 ;
     RECT  6.264 13.091 6.498 13.559 ;
     RECT  9.54 13.325 9.702 13.559 ;
     RECT  11.52 13.397 13.497 13.559 ;
     RECT  102.636 13.369 103.482 13.559 ;
     RECT  23.58 13.397 25.326 13.567 ;
     RECT  106.704 12.317 110.697 13.567 ;
     RECT  111.708 13.027 112.518 13.567 ;
     RECT  2.34 13.325 2.697 13.595 ;
     RECT  6.264 13.559 6.282 13.595 ;
     RECT  9.54 13.559 9.558 13.595 ;
     RECT  12.348 13.559 13.497 13.595 ;
     RECT  104.256 12.757 105.534 13.603 ;
     RECT  11.52 13.559 11.538 13.631 ;
     RECT  28.62 12.587 84.51 13.639 ;
     RECT  85.284 11.939 89.694 13.639 ;
     RECT  12.348 13.595 12.474 13.667 ;
     RECT  106.56 13.567 110.697 13.667 ;
     RECT  27.864 12.587 27.882 13.675 ;
     RECT  28.62 13.639 89.694 13.675 ;
     RECT  90.828 13.171 96.93 13.675 ;
     RECT  12.348 13.667 12.366 13.703 ;
     RECT  17.064 12.623 22.662 13.837 ;
     RECT  23.4 13.567 25.326 13.837 ;
     RECT  26.388 13.397 26.766 13.873 ;
     RECT  101.772 13.019 101.79 13.915 ;
     RECT  17.064 13.837 25.326 13.945 ;
     RECT  27.864 13.675 89.694 13.981 ;
     RECT  90.504 13.675 96.93 13.981 ;
     RECT  27.864 13.981 96.93 14.009 ;
     RECT  26.388 13.873 26.91 14.155 ;
     RECT  26.388 14.155 27.018 14.203 ;
     RECT  27.864 14.009 96.678 14.203 ;
     RECT  103.896 13.603 105.534 14.215 ;
     RECT  101.772 13.915 102.042 14.279 ;
     RECT  17.028 13.945 25.326 14.299 ;
     RECT  26.388 14.203 96.678 14.299 ;
     RECT  103.896 14.215 105.57 14.369 ;
     RECT  111.708 13.567 112.59 14.413 ;
     RECT  100.764 14.413 100.782 14.485 ;
     RECT  100.656 14.485 100.782 14.639 ;
     RECT  103.896 14.369 105.534 14.971 ;
     RECT  98.604 14.341 98.622 15.019 ;
     RECT  98.424 15.019 98.622 15.061 ;
     RECT  102.6 14.647 102.618 15.223 ;
     RECT  106.704 13.667 110.697 15.223 ;
     RECT  111.42 14.413 112.59 15.223 ;
     RECT  102.6 15.223 102.906 15.251 ;
     RECT  99.615 2.413 99.897 15.295 ;
     RECT  100.656 14.639 100.674 15.295 ;
     RECT  98.352 15.061 98.694 15.331 ;
     RECT  103.824 14.971 105.534 15.331 ;
     RECT  99.615 15.295 100.674 15.359 ;
     RECT  98.172 15.331 98.694 15.565 ;
     RECT  99.615 15.359 99.954 15.565 ;
     RECT  17.028 14.299 96.678 15.763 ;
     RECT  98.172 15.565 99.954 15.763 ;
     RECT  102.816 15.251 102.906 15.787 ;
     RECT  103.644 15.331 105.534 15.787 ;
     RECT  98.1 15.763 99.954 15.799 ;
     RECT  16.092 15.691 16.11 15.835 ;
     RECT  102.816 15.787 105.534 15.863 ;
     RECT  15.912 15.835 16.11 15.965 ;
     RECT  102.816 15.863 102.834 16.069 ;
     RECT  106.704 15.223 112.59 16.069 ;
     RECT  15.948 15.965 16.11 16.141 ;
     RECT  17.028 15.763 97.002 16.141 ;
     RECT  15.948 16.141 97.002 16.231 ;
     RECT  97.74 15.799 99.954 16.231 ;
     RECT  106.56 16.069 112.59 16.303 ;
     RECT  15.948 16.231 99.954 16.304 ;
     RECT  102.6 16.069 102.834 16.331 ;
     RECT  16.488 16.304 99.954 16.367 ;
     RECT  103.644 15.863 105.534 16.411 ;
     RECT  14.796 16.375 14.814 16.445 ;
     RECT  106.488 16.303 112.59 16.529 ;
     RECT  101.772 14.279 101.79 16.603 ;
     RECT  106.596 16.529 112.59 16.637 ;
     RECT  103.644 16.411 105.57 16.681 ;
     RECT  103.644 16.681 105.678 16.915 ;
     RECT  101.772 16.603 101.862 16.951 ;
     RECT  103.608 16.915 105.678 17.069 ;
     RECT  16.488 16.367 99.897 17.077 ;
     RECT  102.816 16.331 102.834 17.311 ;
     RECT  103.608 17.069 105.534 17.311 ;
     RECT  16.236 17.077 99.897 17.383 ;
     RECT  101.772 16.951 102.042 17.419 ;
     RECT  102.816 17.311 105.534 17.419 ;
     RECT  15.444 17.491 15.462 17.617 ;
     RECT  16.236 17.383 100.026 17.689 ;
     RECT  15.264 17.617 15.462 17.995 ;
     RECT  16.236 17.689 100.062 17.995 ;
     RECT  100.872 17.959 100.89 17.995 ;
     RECT  101.772 17.419 105.534 17.995 ;
     RECT  15.264 17.995 100.062 18.031 ;
     RECT  100.872 17.995 105.534 18.031 ;
     RECT  15.264 18.031 105.534 18.173 ;
     RECT  14.364 18.187 14.382 18.475 ;
     RECT  15.264 18.173 15.822 18.475 ;
     RECT  13.215 13.595 13.497 18.535 ;
     RECT  14.364 18.475 15.822 18.535 ;
     RECT  16.884 18.173 105.534 18.761 ;
     RECT  97.56 18.761 105.534 18.931 ;
     RECT  97.56 18.931 105.642 19.075 ;
     RECT  106.704 16.637 112.59 19.273 ;
     RECT  13.215 18.535 15.822 19.421 ;
     RECT  13.215 19.421 15.39 19.499 ;
     RECT  97.56 19.075 105.714 19.651 ;
     RECT  106.596 19.273 112.59 19.651 ;
     RECT  16.884 18.761 96.822 19.741 ;
     RECT  97.56 19.651 112.59 19.741 ;
     RECT  16.884 19.741 112.59 20.119 ;
     RECT  16.812 20.119 112.59 20.155 ;
     RECT  13.215 19.499 15.282 20.389 ;
     RECT  13.215 20.389 15.39 20.425 ;
     RECT  11.448 20.389 11.466 20.579 ;
     RECT  12.6 20.425 15.39 20.683 ;
     RECT  16.164 20.155 112.59 20.683 ;
     RECT  12.6 20.683 112.59 20.965 ;
     RECT  12.348 20.965 112.59 21.029 ;
     RECT  11.268 20.695 11.286 21.505 ;
     RECT  12.348 21.029 102.87 21.505 ;
     RECT  11.268 21.505 102.87 21.901 ;
     RECT  103.644 21.029 112.59 21.901 ;
     RECT  11.268 21.901 112.59 22.235 ;
     RECT  11.268 22.235 13.806 23.017 ;
     RECT  10.8 23.017 13.806 23.161 ;
     RECT  14.544 22.235 112.59 23.161 ;
     RECT  10.8 23.161 112.59 23.279 ;
     RECT  20.664 23.279 112.59 23.309 ;
     RECT  10.8 23.279 19.926 23.351 ;
     RECT  20.664 23.309 79.146 23.351 ;
     RECT  19.8 23.351 19.926 23.357 ;
     RECT  10.8 23.351 18.897 23.405 ;
     RECT  20.664 23.351 38.97 23.423 ;
     RECT  20.664 23.423 32.67 23.453 ;
     RECT  79.92 23.309 112.59 23.459 ;
     RECT  79.992 23.459 112.59 23.501 ;
     RECT  2.415 13.595 2.697 23.507 ;
     RECT  7.815 13.373 8.097 23.507 ;
     RECT  11.124 23.405 18.897 23.507 ;
     RECT  11.124 23.507 18.705 23.549 ;
     RECT  20.7 23.453 32.67 23.549 ;
     RECT  39.888 23.351 79.146 23.549 ;
     RECT  22.824 23.549 32.454 23.585 ;
     RECT  33.48 23.423 38.97 23.585 ;
     RECT  19.872 23.357 19.926 23.597 ;
     RECT  39.888 23.549 79.11 23.597 ;
     RECT  11.124 23.549 16.002 23.657 ;
     RECT  17.028 23.549 18.705 23.693 ;
     RECT  17.748 23.693 18.705 23.729 ;
     RECT  85.752 23.501 112.59 23.729 ;
     RECT  11.124 23.657 15.93 23.741 ;
     RECT  17.784 23.729 18.705 23.741 ;
     RECT  20.7 23.549 22.014 23.741 ;
     RECT  2.415 23.507 2.505 23.777 ;
     RECT  7.815 23.507 7.905 23.777 ;
     RECT  18.072 23.741 18.705 23.777 ;
     RECT  15.732 23.741 15.93 23.789 ;
     RECT  18.072 23.777 18.09 23.789 ;
     RECT  20.988 23.741 22.014 23.789 ;
     RECT  33.48 23.585 38.754 23.789 ;
     RECT  11.124 23.741 14.094 23.837 ;
     RECT  19.908 23.597 19.926 23.837 ;
     RECT  22.932 23.585 32.454 23.837 ;
     RECT  33.48 23.789 37.35 23.837 ;
     RECT  38.412 23.789 38.754 23.837 ;
     RECT  52.092 23.597 79.11 23.837 ;
     RECT  12.348 23.837 14.094 23.855 ;
     RECT  11.268 23.837 11.61 23.885 ;
     RECT  12.348 23.855 13.806 23.885 ;
     RECT  15.732 23.789 15.75 23.885 ;
     RECT  52.092 23.837 77.598 23.885 ;
     RECT  78.444 23.837 79.11 23.885 ;
     RECT  11.376 23.885 11.502 23.933 ;
     RECT  12.348 23.885 12.366 23.933 ;
     RECT  21.564 23.789 22.014 23.933 ;
     RECT  22.932 23.837 29.394 23.933 ;
     RECT  30.132 23.837 32.454 23.933 ;
     RECT  33.66 23.837 37.35 23.933 ;
     RECT  38.736 23.837 38.754 23.933 ;
     RECT  52.092 23.885 76.374 23.933 ;
     RECT  77.112 23.885 77.598 23.933 ;
     RECT  79.992 23.501 84.942 23.933 ;
     RECT  85.788 23.729 112.59 23.933 ;
     RECT  13.212 23.885 13.806 23.981 ;
     RECT  22.932 23.933 29.322 23.981 ;
     RECT  30.564 23.933 31.23 23.981 ;
     RECT  35.136 23.933 35.622 23.981 ;
     RECT  77.112 23.933 77.454 23.981 ;
     RECT  86.256 23.933 99.522 23.981 ;
     RECT  13.392 23.981 13.806 24.029 ;
     RECT  91.62 23.981 99.522 24.029 ;
     RECT  92.268 24.029 99.09 24.125 ;
     RECT  22.932 23.981 29.286 24.461 ;
     RECT  52.092 23.933 76.158 24.461 ;
     RECT  22.932 24.461 29.178 24.509 ;
     RECT  39.888 23.597 51.354 24.509 ;
     RECT  52.092 24.461 58.266 24.509 ;
     RECT  59.076 24.461 76.158 24.509 ;
     RECT  79.992 23.933 84.726 24.509 ;
     RECT  86.256 23.981 90.774 24.509 ;
     RECT  22.932 24.509 28.962 24.557 ;
     RECT  35.208 23.981 35.622 24.557 ;
     RECT  39.888 24.509 43.578 24.557 ;
     RECT  44.82 24.509 51.354 24.557 ;
     RECT  52.704 24.509 53.838 24.557 ;
     RECT  54.648 24.509 57.474 24.557 ;
     RECT  64.728 24.509 74.61 24.557 ;
     RECT  83.052 24.509 84.726 24.557 ;
     RECT  92.268 24.125 97.506 24.557 ;
     RECT  100.548 23.933 103.95 24.557 ;
     RECT  104.868 23.933 112.59 24.557 ;
     RECT  22.932 24.557 28.926 24.605 ;
     RECT  47.304 24.557 51.354 24.605 ;
     RECT  59.112 24.509 63.738 24.605 ;
     RECT  98.316 24.125 99.09 24.605 ;
     RECT  103.896 24.557 103.95 24.605 ;
     RECT  105.588 24.557 112.59 24.605 ;
     RECT  59.112 24.605 62.586 24.653 ;
     RECT  105.984 24.605 112.59 24.653 ;
     RECT  53.568 24.557 53.838 24.701 ;
     RECT  59.112 24.653 62.046 24.893 ;
     RECT  77.112 23.981 77.13 24.941 ;
     RECT  88.272 24.509 90.774 24.943 ;
     RECT  88.272 24.943 91.17 24.989 ;
     RECT  40.104 24.557 43.578 25.037 ;
     RECT  44.82 24.557 45.522 25.037 ;
     RECT  46.26 24.557 46.35 25.037 ;
     RECT  53.748 24.701 53.838 25.037 ;
     RECT  59.4 24.893 62.046 25.037 ;
     RECT  73.728 24.557 74.574 25.037 ;
     RECT  88.272 24.989 90.738 25.037 ;
     RECT  75.42 24.509 76.158 25.079 ;
     RECT  86.256 24.509 87.318 25.079 ;
     RECT  22.932 24.605 27.054 25.085 ;
     RECT  28.224 24.605 28.926 25.085 ;
     RECT  40.104 25.037 42.462 25.085 ;
     RECT  43.308 25.037 43.578 25.085 ;
     RECT  44.928 25.037 45.522 25.085 ;
     RECT  46.26 25.037 46.278 25.085 ;
     RECT  48.096 24.605 51.354 25.085 ;
     RECT  53.82 25.037 53.838 25.085 ;
     RECT  54.9 24.557 57.474 25.085 ;
     RECT  59.4 25.037 61.722 25.085 ;
     RECT  63.432 24.605 63.738 25.085 ;
     RECT  64.728 24.557 72.882 25.085 ;
     RECT  73.728 25.037 73.746 25.085 ;
     RECT  74.556 25.037 74.574 25.085 ;
     RECT  75.42 25.079 76.05 25.085 ;
     RECT  79.992 24.509 81.558 25.085 ;
     RECT  82.296 24.509 82.314 25.085 ;
     RECT  83.34 24.557 84.726 25.085 ;
     RECT  88.272 25.037 89.19 25.085 ;
     RECT  99.072 24.605 99.09 25.085 ;
     RECT  26.604 25.085 27.054 25.133 ;
     RECT  28.476 25.085 28.746 25.133 ;
     RECT  30.6 23.981 31.23 25.133 ;
     RECT  32.364 23.933 32.382 25.133 ;
     RECT  47.304 24.605 47.322 25.133 ;
     RECT  63.72 25.085 63.738 25.133 ;
     RECT  65.268 25.085 65.286 25.133 ;
     RECT  66.924 25.085 69.858 25.133 ;
     RECT  71.388 25.085 71.55 25.133 ;
     RECT  75.888 25.085 76.05 25.133 ;
     RECT  79.092 23.885 79.11 25.133 ;
     RECT  79.992 25.085 81.414 25.133 ;
     RECT  83.34 25.085 83.358 25.133 ;
     RECT  90.036 25.037 90.738 25.133 ;
     RECT  92.268 24.557 95.166 25.133 ;
     RECT  96.012 24.557 97.398 25.133 ;
     RECT  98.316 24.605 98.334 25.133 ;
     RECT  100.548 24.557 102.654 25.133 ;
     RECT  103.896 24.605 103.914 25.133 ;
     RECT  106.704 24.653 112.59 25.133 ;
     RECT  43.524 25.085 43.542 25.181 ;
     RECT  66.924 25.133 68.814 25.181 ;
     RECT  84.096 25.085 84.726 25.181 ;
     RECT  90.108 25.133 90.126 25.181 ;
     RECT  101.772 25.133 102.654 25.181 ;
     RECT  102.42 25.181 102.654 25.229 ;
     RECT  79.992 25.133 81.234 25.291 ;
     RECT  102.456 25.229 102.654 25.325 ;
     RECT  79.272 25.291 81.234 25.469 ;
     RECT  79.74 25.469 81.234 25.613 ;
     RECT  18.396 25.435 18.414 25.627 ;
     RECT  18.396 25.627 18.486 25.675 ;
     RECT  22.932 25.085 23.274 25.675 ;
     RECT  13.788 24.029 13.806 25.709 ;
     RECT  56.7 25.085 57.006 25.709 ;
     RECT  68.04 25.181 68.814 25.709 ;
     RECT  92.376 25.133 92.43 25.709 ;
     RECT  18.396 25.675 18.99 25.757 ;
     RECT  30.6 25.133 31.05 25.757 ;
     RECT  56.7 25.709 56.862 25.757 ;
     RECT  84.636 25.181 84.726 25.757 ;
     RECT  94.104 25.133 95.166 25.757 ;
     RECT  96.012 25.133 97.146 25.757 ;
     RECT  18.468 25.757 18.99 25.805 ;
     RECT  22.824 25.675 23.274 25.805 ;
     RECT  26.676 25.133 27.054 25.805 ;
     RECT  28.728 25.133 28.746 25.805 ;
     RECT  30.6 25.757 30.942 25.805 ;
     RECT  35.604 24.557 35.622 25.805 ;
     RECT  38.196 25.675 38.214 25.805 ;
     RECT  40.716 25.085 40.734 25.805 ;
     RECT  45.504 25.085 45.522 25.805 ;
     RECT  49.212 25.085 50.67 25.805 ;
     RECT  56.7 25.757 56.718 25.805 ;
     RECT  59.4 25.085 59.418 25.805 ;
     RECT  60.84 25.085 60.858 25.805 ;
     RECT  66.924 25.181 67.194 25.805 ;
     RECT  68.076 25.709 68.814 25.805 ;
     RECT  71.532 25.133 71.55 25.805 ;
     RECT  72.576 25.085 72.594 25.805 ;
     RECT  75.888 25.133 75.906 25.805 ;
     RECT  80.208 25.613 81.234 25.805 ;
     RECT  84.708 25.757 84.726 25.805 ;
     RECT  86.256 25.079 87.246 25.805 ;
     RECT  88.272 25.085 88.29 25.805 ;
     RECT  89.028 25.085 89.046 25.805 ;
     RECT  92.412 25.709 92.43 25.805 ;
     RECT  95.148 25.757 95.166 25.805 ;
     RECT  96.3 25.757 97.146 25.805 ;
     RECT  102.636 25.325 102.654 25.805 ;
     RECT  106.812 25.133 112.59 25.805 ;
     RECT  94.104 25.757 94.122 25.901 ;
    LAYER M4 ;
     RECT  0.06 12.24 0.179 13.032 ;
     RECT  0.179 12.336 1.141 13.032 ;
     RECT  1.141 12.336 2.408 13.08 ;
     RECT  0.133 14.4 2.408 14.424 ;
     RECT  2.408 2.148 2.512 23.772 ;
     RECT  2.512 2.418 2.704 23.502 ;
     RECT  2.704 13.056 4.529 13.08 ;
     RECT  2.704 12 4.813 12.024 ;
     RECT  4.813 12 4.853 12.264 ;
     RECT  5.073 11.232 5.177 11.256 ;
     RECT  4.853 12.24 7.153 12.264 ;
     RECT  5.317 13.344 7.153 13.368 ;
     RECT  7.153 12.24 7.808 13.368 ;
     RECT  2.704 14.4 7.808 14.424 ;
     RECT  7.808 2.148 7.912 23.772 ;
     RECT  7.912 2.418 8.104 23.502 ;
     RECT  8.104 12.528 8.165 13.368 ;
     RECT  10.693 23.664 10.748 23.688 ;
     RECT  10.748 23.376 10.885 23.688 ;
     RECT  8.165 12.528 10.933 13.176 ;
     RECT  10.885 23.376 11.365 23.928 ;
     RECT  10.933 11.952 11.549 13.176 ;
     RECT  11.549 11.952 11.981 13.08 ;
     RECT  11.981 11.952 12.481 11.976 ;
     RECT  12.613 25.728 12.805 25.752 ;
     RECT  11.653 20.448 12.949 20.472 ;
     RECT  12.913 21.456 12.949 21.48 ;
     RECT  12.805 25.68 12.995 25.752 ;
     RECT  12.949 20.448 13.057 21.48 ;
     RECT  11.365 22.752 13.057 23.928 ;
     RECT  13.057 20.448 13.189 23.928 ;
     RECT  12.481 11.76 13.208 11.976 ;
     RECT  11.981 13.056 13.208 13.08 ;
     RECT  8.104 14.4 13.208 14.424 ;
     RECT  13.189 20.448 13.208 23.976 ;
     RECT  13.208 2.148 13.275 23.976 ;
     RECT  13.275 2.148 13.312 24.024 ;
     RECT  13.312 2.418 13.421 24.024 ;
     RECT  12.995 25.68 13.477 25.704 ;
     RECT  13.421 2.418 13.504 23.928 ;
     RECT  13.477 25.584 13.619 25.704 ;
     RECT  13.504 23.232 13.637 23.928 ;
     RECT  13.637 23.376 13.673 23.928 ;
     RECT  13.504 21.456 13.745 22.248 ;
     RECT  13.619 25.68 13.817 25.704 ;
     RECT  13.745 21.456 14.069 21.72 ;
     RECT  13.504 18.192 14.492 18.84 ;
     RECT  13.504 19.872 14.492 20.424 ;
     RECT  14.725 16.416 14.825 16.44 ;
     RECT  14.069 21.504 15.205 21.72 ;
     RECT  15.205 21.504 15.289 22.008 ;
     RECT  14.492 18.192 15.301 20.424 ;
     RECT  15.289 21.408 15.301 22.008 ;
     RECT  15.301 18.192 15.493 22.008 ;
     RECT  13.673 23.376 15.721 23.784 ;
     RECT  15.493 18.144 15.877 22.008 ;
     RECT  15.901 15.936 15.937 15.96 ;
     RECT  15.781 25.728 15.971 25.752 ;
     RECT  15.937 15.936 15.985 16.296 ;
     RECT  13.504 11.952 16.193 13.08 ;
     RECT  15.877 18.096 16.369 22.008 ;
     RECT  15.721 23.376 16.369 23.88 ;
     RECT  16.369 18.096 16.837 23.88 ;
     RECT  15.985 16.272 16.933 16.296 ;
     RECT  16.933 16.272 16.981 16.536 ;
     RECT  16.837 17.616 16.981 23.88 ;
     RECT  16.981 16.272 17.057 23.88 ;
     RECT  13.504 14.4 17.125 14.424 ;
     RECT  17.057 16.272 17.125 16.296 ;
     RECT  16.193 11.952 17.881 12.024 ;
     RECT  17.881 1.392 17.989 1.416 ;
     RECT  17.125 14.4 18.325 16.296 ;
     RECT  17.057 17.424 18.325 23.88 ;
     RECT  18.229 25.68 18.325 25.704 ;
     RECT  18.325 25.632 18.341 25.704 ;
     RECT  16.193 13.008 18.373 13.08 ;
     RECT  18.325 14.4 18.373 23.88 ;
     RECT  18.341 25.632 18.373 25.752 ;
     RECT  18.373 25.488 18.385 25.752 ;
     RECT  18.385 25.44 18.457 25.752 ;
     RECT  17.989 0.864 18.493 1.416 ;
     RECT  18.457 25.44 18.515 25.8 ;
     RECT  18.493 0.864 18.608 1.464 ;
     RECT  17.881 11.76 18.608 12.024 ;
     RECT  18.373 13.008 18.608 23.88 ;
     RECT  18.515 25.488 18.803 25.8 ;
     RECT  18.608 0.864 18.904 23.88 ;
     RECT  18.803 25.68 19.001 25.8 ;
     RECT  18.904 13.056 19.043 23.88 ;
     RECT  19.001 25.68 19.043 25.752 ;
     RECT  19.043 25.728 19.139 25.752 ;
     RECT  19.043 13.92 19.397 23.88 ;
     RECT  18.904 11.76 19.613 11.976 ;
     RECT  19.397 17.424 21.157 23.88 ;
     RECT  19.397 14.4 21.193 16.152 ;
     RECT  19.613 11.952 21.229 11.976 ;
     RECT  21.193 14.208 21.925 16.152 ;
     RECT  21.229 11.376 21.949 11.976 ;
     RECT  21.949 11.376 22.213 12.264 ;
     RECT  21.925 13.68 22.213 16.152 ;
     RECT  22.213 11.376 22.565 16.152 ;
     RECT  22.565 11.376 22.597 12.36 ;
     RECT  22.501 25.536 22.597 25.56 ;
     RECT  22.597 25.536 22.643 25.8 ;
     RECT  22.597 11.328 22.837 12.36 ;
     RECT  22.643 25.68 22.886 25.8 ;
     RECT  21.157 17.424 22.892 23.928 ;
     RECT  22.565 13.392 22.933 16.152 ;
     RECT  22.886 25.728 22.961 25.8 ;
     RECT  22.777 10.128 22.981 10.152 ;
     RECT  22.933 13.392 23.065 16.296 ;
     RECT  22.892 17.424 23.065 23.976 ;
     RECT  22.981 9.36 23.221 10.152 ;
     RECT  22.837 11.184 23.221 12.36 ;
     RECT  18.904 0.864 23.317 1.512 ;
     RECT  22.961 25.776 23.329 25.8 ;
     RECT  23.221 9.36 23.641 12.36 ;
     RECT  23.065 13.392 23.941 23.976 ;
     RECT  23.941 13.392 23.965 24.504 ;
     RECT  23.317 0.864 24.008 1.56 ;
     RECT  23.641 9.312 24.008 12.36 ;
     RECT  23.965 13.392 24.008 25.08 ;
     RECT  24.008 0.864 24.304 25.08 ;
     RECT  24.304 15.84 24.325 25.08 ;
     RECT  24.304 0.864 24.433 1.56 ;
     RECT  24.325 15.84 24.515 25.752 ;
     RECT  24.304 11.184 24.689 14.76 ;
     RECT  24.433 0.432 24.973 1.56 ;
     RECT  24.515 15.84 25.589 25.08 ;
     RECT  25.589 16.128 26.341 25.08 ;
     RECT  26.341 16.128 26.593 25.8 ;
     RECT  26.593 15.744 26.675 25.8 ;
     RECT  26.675 15.744 26.777 24.552 ;
     RECT  24.689 11.76 26.819 14.76 ;
     RECT  26.819 11.76 26.845 12.264 ;
     RECT  26.675 25.776 27.065 25.8 ;
     RECT  26.777 16.128 27.73 24.552 ;
     RECT  26.845 11.376 27.821 12.264 ;
     RECT  24.973 0.096 27.877 1.56 ;
     RECT  27.781 2.88 27.877 2.904 ;
     RECT  27.877 0.096 27.923 2.904 ;
     RECT  27.73 16.128 28.213 24.6 ;
     RECT  26.819 13.392 28.429 14.76 ;
     RECT  28.213 16.128 28.453 25.08 ;
     RECT  28.453 16.128 28.573 25.128 ;
     RECT  28.573 16.08 28.717 25.128 ;
     RECT  28.717 16.08 28.801 25.8 ;
     RECT  28.801 16.08 28.937 25.08 ;
     RECT  28.937 16.08 28.973 24.552 ;
     RECT  28.973 16.08 29.189 24.504 ;
     RECT  29.189 16.08 29.297 24.456 ;
     RECT  27.923 0.096 29.329 2.088 ;
     RECT  29.329 0.096 29.408 3.048 ;
     RECT  24.304 9.216 29.408 10.2 ;
     RECT  27.821 11.76 29.408 12.264 ;
     RECT  28.429 13.392 29.408 14.856 ;
     RECT  29.297 16.08 29.408 24.024 ;
     RECT  29.408 0.096 29.555 24.024 ;
     RECT  29.555 0.096 29.704 23.976 ;
     RECT  30.277 25.776 30.373 25.8 ;
     RECT  30.373 25.728 30.469 25.8 ;
     RECT  29.704 13.392 30.593 23.976 ;
     RECT  30.469 25.632 30.757 25.8 ;
     RECT  30.757 25.488 30.997 25.8 ;
     RECT  30.997 25.488 31.105 25.752 ;
     RECT  31.201 25.104 31.379 25.128 ;
     RECT  29.704 11.76 31.429 12.264 ;
     RECT  30.593 13.392 31.429 23.88 ;
     RECT  31.429 11.76 31.772 23.88 ;
     RECT  32.353 25.104 32.485 25.128 ;
     RECT  32.485 25.008 32.531 25.128 ;
     RECT  32.531 25.008 32.627 25.032 ;
     RECT  34.405 25.728 34.549 25.752 ;
     RECT  34.549 25.632 34.789 25.752 ;
     RECT  29.704 0.096 34.808 3.048 ;
     RECT  32.197 5.232 34.808 5.256 ;
     RECT  29.704 9.216 34.808 10.2 ;
     RECT  31.772 11.76 34.808 23.928 ;
     RECT  34.808 0.096 34.981 23.928 ;
     RECT  34.981 0.096 35.104 24.024 ;
     RECT  35.104 11.76 35.197 24.024 ;
     RECT  35.197 11.76 35.315 24.552 ;
     RECT  34.789 25.632 35.365 25.8 ;
     RECT  35.365 25.584 35.603 25.8 ;
     RECT  35.603 25.68 35.633 25.8 ;
     RECT  35.633 25.68 35.843 25.704 ;
     RECT  35.315 11.76 36.281 23.928 ;
     RECT  35.104 0.096 36.371 3.048 ;
     RECT  36.281 11.76 36.929 13.416 ;
     RECT  36.371 0.096 37.369 1.176 ;
     RECT  36.371 2.16 37.523 3.048 ;
     RECT  36.929 13.392 37.645 13.416 ;
     RECT  36.281 14.4 37.645 23.928 ;
     RECT  36.929 11.76 37.861 12.264 ;
     RECT  37.369 0.432 37.907 1.176 ;
     RECT  37.861 11.28 37.969 12.264 ;
     RECT  37.523 2.256 38.003 3.048 ;
     RECT  38.053 25.776 38.101 25.8 ;
     RECT  35.104 9.216 38.149 10.2 ;
     RECT  37.969 11.28 38.149 12.312 ;
     RECT  38.101 25.68 38.246 25.8 ;
     RECT  38.149 9.216 38.257 12.312 ;
     RECT  37.645 13.392 38.257 23.928 ;
     RECT  38.246 25.728 38.627 25.752 ;
     RECT  37.907 0.576 38.761 1.176 ;
     RECT  38.257 9.216 38.765 23.928 ;
     RECT  38.003 2.496 38.801 3.048 ;
     RECT  38.801 2.784 38.873 3.048 ;
     RECT  38.765 9.216 38.945 23.88 ;
     RECT  38.945 9.216 39.089 10.68 ;
     RECT  38.873 2.832 39.373 3.048 ;
     RECT  38.761 0.576 39.661 1.32 ;
     RECT  39.373 2.832 39.841 3.144 ;
     RECT  39.661 0.144 39.877 1.32 ;
     RECT  38.945 11.76 39.877 23.88 ;
     RECT  39.877 0.096 40.129 1.32 ;
     RECT  39.841 2.352 40.129 3.144 ;
     RECT  39.089 9.216 40.165 10.2 ;
     RECT  39.877 11.76 40.165 25.08 ;
     RECT  40.129 0.096 40.208 3.144 ;
     RECT  35.104 5.232 40.208 5.256 ;
     RECT  40.165 9.216 40.208 25.08 ;
     RECT  40.208 0.096 40.307 25.08 ;
     RECT  40.307 0.096 40.504 23.928 ;
     RECT  40.307 25.008 40.549 25.08 ;
     RECT  40.549 25.008 40.745 25.8 ;
     RECT  40.504 0.096 41.465 3.384 ;
     RECT  41.465 0.096 41.555 3.144 ;
     RECT  40.504 9.216 41.797 23.928 ;
     RECT  40.745 25.008 41.797 25.08 ;
     RECT  41.555 0.144 42.131 3.144 ;
     RECT  41.797 9.216 42.325 25.08 ;
     RECT  42.325 9.072 42.725 25.08 ;
     RECT  42.131 0.48 42.761 3.144 ;
     RECT  42.725 9.072 42.797 15.192 ;
     RECT  42.725 16.32 43.337 25.08 ;
     RECT  43.337 21.84 43.513 25.08 ;
     RECT  43.513 21.84 43.589 25.176 ;
     RECT  43.261 7.968 43.625 7.992 ;
     RECT  43.589 22.464 43.763 25.176 ;
     RECT  42.797 9.216 43.765 15.192 ;
     RECT  43.337 16.32 43.765 20.472 ;
     RECT  43.765 9.216 43.877 20.472 ;
     RECT  43.763 22.464 43.877 25.08 ;
     RECT  42.761 0.48 43.945 3.048 ;
     RECT  43.945 0.192 43.981 3.048 ;
     RECT  43.981 0.096 44.065 3.048 ;
     RECT  44.065 0.144 44.173 3.048 ;
     RECT  44.173 0.192 44.339 3.048 ;
     RECT  43.877 13.296 44.381 20.472 ;
     RECT  43.873 7.344 44.437 7.368 ;
     RECT  43.877 9.216 44.437 12.264 ;
     RECT  44.437 6.816 44.483 7.368 ;
     RECT  43.877 22.464 44.869 23.448 ;
     RECT  43.877 24.432 44.869 25.08 ;
     RECT  44.869 22.464 44.957 25.08 ;
     RECT  44.557 20.88 45.097 21 ;
     RECT  40.504 5.232 45.241 5.256 ;
     RECT  44.483 6.816 45.241 6.84 ;
     RECT  44.957 22.464 45.385 24.552 ;
     RECT  44.381 13.296 45.397 19.608 ;
     RECT  45.097 20.88 45.397 21.096 ;
     RECT  44.339 0.528 45.529 3.048 ;
     RECT  45.349 25.728 45.533 25.8 ;
     RECT  45.529 0.096 45.608 3.048 ;
     RECT  45.241 5.232 45.608 6.84 ;
     RECT  44.437 8.4 45.608 12.264 ;
     RECT  45.397 13.296 45.608 21.096 ;
     RECT  45.385 22.224 45.608 24.552 ;
     RECT  45.608 0.096 45.779 24.552 ;
     RECT  45.779 0.816 45.904 24.552 ;
     RECT  45.904 7.584 46.019 24.552 ;
     RECT  45.533 25.728 46.019 25.752 ;
     RECT  46.019 7.584 46.109 10.728 ;
     RECT  46.019 20.88 46.205 24.552 ;
     RECT  45.904 4.368 46.253 6.12 ;
     RECT  46.109 7.584 46.361 7.608 ;
     RECT  46.019 11.712 46.361 19.848 ;
     RECT  46.205 20.88 47.029 25.08 ;
     RECT  46.109 8.592 47.257 10.728 ;
     RECT  46.361 11.712 47.257 19.608 ;
     RECT  45.904 0.816 47.293 3.048 ;
     RECT  47.029 20.88 47.315 25.752 ;
     RECT  47.315 20.88 47.411 25.128 ;
     RECT  47.411 20.88 47.477 25.08 ;
     RECT  47.257 8.592 47.581 19.608 ;
     RECT  47.581 8.592 47.689 19.848 ;
     RECT  47.477 20.88 47.689 20.904 ;
     RECT  47.689 8.592 47.869 20.904 ;
     RECT  47.833 6.72 48.085 6.744 ;
     RECT  46.253 4.368 48.125 5.256 ;
     RECT  47.477 22.128 48.305 25.08 ;
     RECT  47.869 7.968 48.467 20.904 ;
     RECT  48.085 6.72 48.613 6.888 ;
     RECT  48.467 8.16 48.629 20.904 ;
     RECT  48.613 6.624 48.661 6.888 ;
     RECT  48.125 5.136 48.665 5.256 ;
     RECT  48.661 6.624 48.773 6.984 ;
     RECT  48.629 8.496 48.947 20.904 ;
     RECT  48.305 22.224 48.997 25.08 ;
     RECT  47.293 0.528 49.139 3.048 ;
     RECT  48.947 19.92 49.201 20.904 ;
     RECT  48.773 6.72 49.273 6.984 ;
     RECT  49.201 19.92 49.285 21.192 ;
     RECT  48.947 8.496 49.457 18.84 ;
     RECT  48.997 22.224 49.619 25.8 ;
     RECT  49.619 25.68 49.853 25.8 ;
     RECT  49.139 0.576 50.129 3.048 ;
     RECT  49.273 6.72 50.137 7.08 ;
     RECT  50.129 0.096 50.213 3.048 ;
     RECT  49.285 19.92 50.281 21.096 ;
     RECT  49.619 22.224 50.281 24.504 ;
     RECT  49.457 9.072 50.461 18.84 ;
     RECT  50.281 19.92 50.461 24.504 ;
     RECT  50.137 6.72 50.497 7.752 ;
     RECT  50.213 0.576 50.677 3.048 ;
     RECT  49.853 25.728 50.681 25.8 ;
     RECT  50.461 9.072 50.725 24.504 ;
     RECT  50.725 9.072 50.821 24.552 ;
     RECT  50.497 6.624 50.893 7.752 ;
     RECT  50.821 9.072 51.005 24.6 ;
     RECT  50.677 0.576 51.008 3.432 ;
     RECT  48.665 5.232 51.008 5.256 ;
     RECT  50.893 6.624 51.008 7.944 ;
     RECT  51.005 9.072 51.008 24.072 ;
     RECT  51.008 0.576 51.059 24.072 ;
     RECT  50.681 25.728 51.251 25.752 ;
     RECT  51.059 0.576 51.253 23.928 ;
     RECT  51.253 0.096 51.304 23.928 ;
     RECT  51.281 25.056 51.365 25.08 ;
     RECT  51.304 19.968 51.443 21.144 ;
     RECT  51.304 0.096 51.517 3.96 ;
     RECT  51.304 6.864 51.869 18.552 ;
     RECT  51.304 22.272 51.985 23.928 ;
     RECT  51.985 22.464 52.037 23.928 ;
     RECT  51.443 19.968 52.357 20.616 ;
     RECT  51.869 7.152 52.369 18.552 ;
     RECT  51.517 0.096 52.499 3.048 ;
     RECT  52.037 22.464 52.549 24.504 ;
     RECT  52.357 19.824 52.589 20.616 ;
     RECT  52.499 0.576 52.595 3.048 ;
     RECT  52.589 19.872 52.693 20.616 ;
     RECT  52.693 19.872 52.801 21.144 ;
     RECT  52.801 19.872 52.931 21.24 ;
     RECT  52.931 19.872 52.985 21.096 ;
     RECT  52.549 22.464 53.317 24.552 ;
     RECT  52.369 7.152 53.485 18.6 ;
     RECT  53.485 7.152 53.489 18.84 ;
     RECT  52.985 20.4 53.597 21.096 ;
     RECT  53.317 22.464 53.605 24.696 ;
     RECT  52.595 0.816 53.845 3.048 ;
     RECT  53.597 20.592 53.989 21.096 ;
     RECT  53.605 22.464 53.989 25.08 ;
     RECT  53.845 0.096 54.035 3.048 ;
     RECT  53.489 18.816 54.044 18.84 ;
     RECT  54.044 18.816 54.131 19.416 ;
     RECT  53.489 7.152 54.353 17.208 ;
     RECT  54.035 0.096 54.515 1.848 ;
     RECT  54.131 18.816 54.524 18.84 ;
     RECT  54.524 18.768 54.601 18.84 ;
     RECT  54.601 18.144 54.641 18.84 ;
     RECT  53.989 20.592 54.641 25.08 ;
     RECT  54.641 20.592 54.659 21.096 ;
     RECT  54.659 20.592 54.685 20.952 ;
     RECT  54.685 20.592 54.713 20.664 ;
     RECT  54.515 0.816 55.025 1.848 ;
     RECT  55.025 0.816 55.108 1.896 ;
     RECT  55.108 0.816 55.177 1.944 ;
     RECT  54.035 3.024 55.177 3.048 ;
     RECT  51.304 5.232 55.253 5.256 ;
     RECT  54.353 7.152 55.501 16.968 ;
     RECT  54.641 18.144 55.501 18.168 ;
     RECT  54.641 22.464 55.717 25.08 ;
     RECT  55.501 7.152 55.897 18.168 ;
     RECT  55.669 19.392 55.897 19.416 ;
     RECT  54.713 20.592 56.177 20.616 ;
     RECT  55.717 21.648 56.177 25.08 ;
     RECT  56.177 20.592 56.245 25.08 ;
     RECT  56.245 20.592 56.377 25.752 ;
     RECT  55.177 0.816 56.408 3.048 ;
     RECT  55.897 7.152 56.408 19.416 ;
     RECT  56.377 20.592 56.408 24.504 ;
     RECT  56.377 25.68 56.485 25.752 ;
     RECT  56.408 0.816 56.704 24.504 ;
     RECT  56.485 25.68 56.729 25.8 ;
     RECT  56.704 9.84 56.873 19.416 ;
     RECT  56.729 25.68 56.873 25.752 ;
     RECT  56.873 25.68 57.017 25.704 ;
     RECT  56.704 23.376 57.445 24.504 ;
     RECT  57.445 23.376 57.529 25.08 ;
     RECT  57.529 23.376 57.629 24.84 ;
     RECT  56.704 7.152 57.781 8.76 ;
     RECT  56.873 9.84 57.781 14.184 ;
     RECT  56.873 15.216 57.805 19.416 ;
     RECT  57.913 22.704 58.025 22.776 ;
     RECT  57.629 23.856 58.061 24.84 ;
     RECT  56.704 20.592 58.129 21.48 ;
     RECT  58.025 22.752 58.133 22.776 ;
     RECT  56.704 5.136 58.313 5.208 ;
     RECT  58.129 20.592 58.345 21.576 ;
     RECT  57.805 15.216 58.645 19.56 ;
     RECT  58.345 20.544 58.645 21.576 ;
     RECT  56.704 0.816 58.669 3.384 ;
     RECT  57.781 7.152 58.921 14.184 ;
     RECT  58.645 15.216 58.921 21.576 ;
     RECT  58.669 0.096 58.931 3.384 ;
     RECT  58.061 24.192 59.101 24.84 ;
     RECT  58.921 7.152 59.105 21.576 ;
     RECT  58.313 5.184 59.249 5.208 ;
     RECT  59.101 24.192 59.269 24.888 ;
     RECT  58.981 25.872 59.269 25.896 ;
     RECT  59.105 15.216 59.393 21.576 ;
     RECT  59.269 24.192 59.425 25.896 ;
     RECT  59.425 23.952 59.461 25.896 ;
     RECT  59.173 22.752 59.557 22.776 ;
     RECT  59.461 23.904 59.557 25.896 ;
     RECT  59.393 15.216 59.603 21.096 ;
     RECT  58.931 0.576 59.969 3.384 ;
     RECT  59.105 7.152 60.433 14.184 ;
     RECT  60.433 7.152 60.661 14.52 ;
     RECT  59.603 15.984 60.661 21.096 ;
     RECT  59.557 22.752 60.661 25.896 ;
     RECT  60.661 7.152 60.761 21.096 ;
     RECT  59.969 0.816 60.901 3.384 ;
     RECT  60.661 22.272 60.901 25.896 ;
     RECT  60.901 0.816 61.081 3.432 ;
     RECT  61.081 0.576 61.165 3.432 ;
     RECT  60.761 15.984 61.261 21.096 ;
     RECT  60.901 22.176 61.261 25.896 ;
     RECT  61.165 0.816 61.808 3.432 ;
     RECT  61.189 5.136 61.808 5.16 ;
     RECT  60.761 7.152 61.808 14.856 ;
     RECT  61.261 15.984 61.808 25.896 ;
     RECT  61.808 0.816 62.104 25.896 ;
     RECT  62.104 11.184 62.243 22.008 ;
     RECT  62.104 0.816 62.669 3.432 ;
     RECT  62.669 0.816 62.813 3.384 ;
     RECT  62.243 11.184 63.059 21.384 ;
     RECT  62.104 6.768 63.107 9.864 ;
     RECT  62.104 23.376 63.157 25.896 ;
     RECT  63.107 9.792 63.241 9.864 ;
     RECT  63.157 22.752 63.301 25.896 ;
     RECT  63.301 22.128 63.433 25.896 ;
     RECT  63.241 9.792 64.028 10.2 ;
     RECT  63.059 11.184 64.028 21.144 ;
     RECT  63.107 6.768 64.105 8.76 ;
     RECT  64.028 9.792 64.105 21.144 ;
     RECT  62.813 0.816 64.213 3.288 ;
     RECT  64.105 6.768 64.321 21.144 ;
     RECT  63.433 22.128 64.321 22.296 ;
     RECT  64.321 6.768 64.645 22.296 ;
     RECT  63.433 23.376 64.645 25.896 ;
     RECT  64.645 6.768 65.117 25.896 ;
     RECT  65.117 15.216 66.083 25.896 ;
     RECT  65.117 6.768 66.089 14.184 ;
     RECT  66.089 6.864 66.121 14.184 ;
     RECT  66.083 15.216 66.121 22.248 ;
     RECT  64.213 0.816 67.208 3.432 ;
     RECT  66.589 5.088 67.208 5.112 ;
     RECT  66.121 6.864 67.208 22.248 ;
     RECT  66.083 23.376 67.208 25.896 ;
     RECT  67.208 0.816 67.504 25.896 ;
     RECT  67.504 0.816 67.517 3.336 ;
     RECT  67.517 0.096 67.529 3.336 ;
     RECT  67.529 0.096 67.601 3.096 ;
     RECT  67.601 0.816 67.709 3.096 ;
     RECT  67.504 6.768 67.781 25.896 ;
     RECT  67.781 6.768 67.859 22.584 ;
     RECT  67.709 3.072 68.605 3.096 ;
     RECT  67.709 0.816 68.732 2.088 ;
     RECT  68.605 3.072 68.732 3.384 ;
     RECT  67.859 6.816 68.773 22.584 ;
     RECT  67.781 23.712 68.773 25.896 ;
     RECT  68.677 4.56 69.001 4.584 ;
     RECT  68.773 6.816 69.401 25.896 ;
     RECT  69.001 4.56 69.473 5.16 ;
     RECT  69.401 6.864 69.923 25.896 ;
     RECT  68.732 0.816 70.081 3.384 ;
     RECT  69.473 4.56 70.081 4.584 ;
     RECT  69.923 6.864 70.373 21.672 ;
     RECT  70.373 7.104 70.409 21.672 ;
     RECT  70.081 0.816 70.441 4.584 ;
     RECT  70.441 0.816 70.553 5.16 ;
     RECT  70.409 7.152 70.841 21.672 ;
     RECT  70.841 7.152 70.877 21.192 ;
     RECT  69.923 22.752 70.913 25.896 ;
     RECT  70.553 0.816 71.315 4.584 ;
     RECT  71.315 4.56 72.097 4.584 ;
     RECT  70.913 23.616 72.133 25.896 ;
     RECT  70.877 9.84 72.197 21.192 ;
     RECT  72.133 23.376 72.349 25.896 ;
     RECT  72.349 22.656 72.373 25.896 ;
     RECT  71.315 0.816 72.608 3.432 ;
     RECT  72.097 4.56 72.608 5.16 ;
     RECT  70.877 7.152 72.608 8.76 ;
     RECT  72.197 9.84 72.608 21.48 ;
     RECT  72.373 22.512 72.608 25.896 ;
     RECT  72.608 0.816 72.904 25.896 ;
     RECT  72.904 22.8 72.965 25.896 ;
     RECT  72.965 23.328 73.073 25.896 ;
     RECT  72.904 6.864 73.933 9.96 ;
     RECT  73.933 6.864 74.077 10.152 ;
     RECT  72.904 11.184 74.077 21.672 ;
     RECT  74.077 6.864 74.261 21.672 ;
     RECT  74.261 8.16 74.341 21.672 ;
     RECT  74.341 8.16 74.365 22.248 ;
     RECT  73.073 23.376 74.365 25.896 ;
     RECT  74.261 6.864 74.513 7.176 ;
     RECT  72.904 0.816 74.585 3.48 ;
     RECT  74.365 8.16 74.765 25.896 ;
     RECT  74.761 5.088 74.845 5.112 ;
     RECT  74.585 0.816 75.557 3.384 ;
     RECT  74.765 8.256 76.061 25.896 ;
     RECT  75.557 0.816 76.069 3.336 ;
     RECT  76.061 8.256 76.201 24.888 ;
     RECT  74.513 7.152 76.453 7.176 ;
     RECT  76.201 8.16 76.453 24.888 ;
     RECT  76.453 7.152 77.101 24.888 ;
     RECT  76.061 25.872 77.101 25.896 ;
     RECT  76.069 0.096 78.008 3.336 ;
     RECT  77.101 7.152 78.008 25.896 ;
     RECT  78.008 0.096 78.304 25.896 ;
     RECT  78.304 0.096 78.833 3.96 ;
     RECT  78.304 8.16 78.833 25.896 ;
     RECT  78.833 0.24 79.165 3.96 ;
     RECT  79.165 0.24 80.531 3.336 ;
     RECT  80.531 0.24 80.677 2.904 ;
     RECT  80.677 0.096 81.281 2.904 ;
     RECT  78.833 8.544 81.779 25.896 ;
     RECT  81.779 8.544 81.857 22.296 ;
     RECT  81.857 8.544 81.893 10.152 ;
     RECT  81.281 0.096 82.309 2.808 ;
     RECT  81.893 8.544 82.681 9.864 ;
     RECT  81.857 11.184 83.257 22.296 ;
     RECT  81.779 23.28 83.257 25.896 ;
     RECT  82.309 0.096 83.408 2.904 ;
     RECT  78.304 7.152 83.408 7.176 ;
     RECT  82.681 8.448 83.408 9.864 ;
     RECT  83.257 11.184 83.408 25.896 ;
     RECT  83.408 0.096 83.704 25.896 ;
     RECT  83.704 8.448 83.765 8.76 ;
     RECT  83.704 0.096 86.681 2.904 ;
     RECT  83.704 11.184 87.041 25.896 ;
     RECT  86.681 0.096 87.545 2.856 ;
     RECT  87.545 0.096 88.808 2.808 ;
     RECT  83.704 7.152 88.808 7.176 ;
     RECT  83.765 8.736 88.808 8.76 ;
     RECT  83.704 9.84 88.808 9.864 ;
     RECT  87.041 11.184 88.808 12.36 ;
     RECT  87.041 13.344 88.808 25.896 ;
     RECT  88.808 0.096 89.104 25.896 ;
     RECT  89.104 0.096 89.273 2.808 ;
     RECT  89.273 0.096 89.381 2.088 ;
     RECT  89.381 0.144 89.417 2.088 ;
     RECT  89.417 2.064 90.637 2.088 ;
     RECT  90.637 2.064 91.001 2.232 ;
     RECT  89.417 0.144 91.145 0.84 ;
     RECT  91.001 2.064 91.427 2.088 ;
     RECT  91.145 0.816 93.485 0.84 ;
     RECT  89.104 13.344 94.133 25.896 ;
     RECT  89.104 7.152 94.208 7.176 ;
     RECT  89.104 8.736 94.208 8.76 ;
     RECT  89.104 9.84 94.208 9.864 ;
     RECT  89.104 11.184 94.208 12.36 ;
     RECT  94.133 13.344 94.208 25.8 ;
     RECT  94.208 2.148 94.312 25.8 ;
     RECT  94.312 2.418 94.504 25.8 ;
     RECT  94.504 13.344 94.931 25.8 ;
     RECT  94.931 24.336 95.315 25.8 ;
     RECT  95.315 24.528 95.411 25.8 ;
     RECT  94.504 11.184 95.501 12.36 ;
     RECT  95.501 11.424 95.507 12.36 ;
     RECT  94.931 13.344 95.699 23.304 ;
     RECT  94.504 9.84 95.795 9.864 ;
     RECT  95.411 25.584 95.891 25.8 ;
     RECT  95.699 14.976 95.941 23.304 ;
     RECT  94.504 7.152 95.987 7.176 ;
     RECT  95.941 14.976 96.083 23.4 ;
     RECT  95.411 24.528 96.083 24.552 ;
     RECT  94.504 8.736 96.371 8.76 ;
     RECT  95.699 13.344 96.467 13.944 ;
     RECT  95.891 25.68 97.009 25.8 ;
     RECT  97.009 25.056 97.436 25.8 ;
     RECT  96.083 14.976 97.585 23.208 ;
     RECT  97.585 14.976 97.765 23.4 ;
     RECT  97.436 24.528 97.765 25.8 ;
     RECT  97.765 14.976 98.003 25.8 ;
     RECT  98.003 14.976 98.483 25.752 ;
     RECT  98.483 14.976 99.251 25.128 ;
     RECT  99.251 25.056 99.539 25.128 ;
     RECT  95.507 11.424 99.608 11.976 ;
     RECT  96.467 13.92 99.608 13.944 ;
     RECT  99.251 14.976 99.608 24.024 ;
     RECT  99.608 2.148 99.712 24.024 ;
     RECT  99.712 2.418 99.731 24.024 ;
     RECT  99.731 2.418 99.904 23.928 ;
     RECT  99.781 25.728 100.067 25.752 ;
     RECT  99.904 14.976 100.109 23.928 ;
     RECT  100.109 14.976 100.145 23.832 ;
     RECT  100.145 14.976 101.725 23.736 ;
     RECT  100.537 25.104 101.761 25.128 ;
     RECT  101.725 14.976 101.941 24.024 ;
     RECT  101.761 25.104 101.941 25.176 ;
     RECT  99.904 13.92 102.053 13.944 ;
     RECT  101.941 14.976 102.409 25.176 ;
     RECT  102.409 14.976 102.445 25.224 ;
     RECT  102.445 14.976 102.625 25.32 ;
     RECT  102.625 14.976 102.899 25.8 ;
     RECT  102.899 14.976 102.989 24.6 ;
     RECT  102.899 25.728 103.379 25.8 ;
     RECT  103.379 25.728 103.571 25.752 ;
     RECT  99.904 11.424 103.741 11.976 ;
     RECT  103.741 11.424 103.813 12.456 ;
     RECT  102.989 14.976 103.853 15 ;
     RECT  102.989 16.32 103.885 24.6 ;
     RECT  103.885 16.32 104.819 25.128 ;
     RECT  103.813 11.424 105.008 12.504 ;
     RECT  104.819 16.32 105.008 24.6 ;
     RECT  105.008 2.148 105.112 24.6 ;
     RECT  105.112 2.418 105.304 24.6 ;
     RECT  105.304 16.8 105.473 16.824 ;
     RECT  105.304 18.768 105.473 22.248 ;
     RECT  105.473 18.96 105.653 22.248 ;
     RECT  105.304 23.376 105.973 24.6 ;
     RECT  105.653 19.392 106.085 22.248 ;
     RECT  106.085 19.392 106.163 19.8 ;
     RECT  105.973 23.376 106.259 24.648 ;
     RECT  106.163 19.776 106.337 19.8 ;
     RECT  106.259 23.376 106.355 23.64 ;
     RECT  106.085 21.072 106.451 21.096 ;
     RECT  106.259 24.624 106.547 24.648 ;
     RECT  106.085 22.224 106.643 22.248 ;
     RECT  105.253 25.728 106.652 25.752 ;
     RECT  106.652 25.104 106.757 25.752 ;
     RECT  105.304 11.424 107.795 11.976 ;
     RECT  106.355 23.616 108.313 23.64 ;
     RECT  108.313 23.616 108.385 23.976 ;
     RECT  107.795 11.424 108.563 11.448 ;
     RECT  108.385 23.616 108.853 24.072 ;
     RECT  108.313 22.224 109.429 22.248 ;
     RECT  108.853 23.616 109.429 24.12 ;
     RECT  106.757 25.104 110.099 25.8 ;
     RECT  109.429 22.224 110.257 24.12 ;
     RECT  109.717 20.688 110.408 20.712 ;
     RECT  110.257 22.224 110.408 24.552 ;
     RECT  110.408 2.148 110.512 24.552 ;
     RECT  110.512 2.418 110.704 24.552 ;
     RECT  110.704 22.224 110.867 24.552 ;
     RECT  110.867 22.8 110.963 24.552 ;
     RECT  110.963 23.952 111.059 24.552 ;
     RECT  110.963 22.8 111.155 22.824 ;
     RECT  110.099 25.728 111.26 25.8 ;
     RECT  111.059 23.952 111.635 23.976 ;
     RECT  110.704 20.688 112.019 20.712 ;
     RECT  111.26 25.104 112.115 25.8 ;
     RECT  112.115 25.152 112.307 25.8 ;
     RECT  112.307 25.2 112.601 25.8 ;
     RECT  112.601 25.2 112.691 25.272 ;
     RECT  112.691 25.248 112.787 25.272 ;
    LAYER M5 ;
     RECT  32.208 0.016 83.592 0.179 ;
     RECT  32.208 0.179 83.496 0.659 ;
     RECT  32.208 0.659 38.088 1.187 ;
     RECT  39.12 0.659 83.496 1.331 ;
     RECT  32.208 1.187 37.992 1.619 ;
     RECT  36.336 1.619 37.992 1.667 ;
     RECT  40.2 1.331 83.496 1.763 ;
     RECT  32.208 1.619 35.208 1.811 ;
     RECT  42.48 1.763 83.496 1.811 ;
     RECT  42.576 1.811 57.48 1.859 ;
     RECT  42.576 1.859 54.024 1.907 ;
     RECT  55.056 1.859 57.48 1.907 ;
     RECT  58.512 1.811 83.496 1.907 ;
     RECT  43.152 1.907 52.008 1.955 ;
     RECT  55.152 1.907 57.48 1.955 ;
     RECT  58.608 1.907 83.496 1.955 ;
     RECT  34.032 1.811 35.208 2.099 ;
     RECT  58.608 1.955 79.176 2.099 ;
     RECT  80.4 1.955 83.496 2.137 ;
     RECT  68.688 2.099 79.176 2.147 ;
     RECT  2.4 2.137 2.52 2.151 ;
     RECT  7.8 2.137 7.92 2.151 ;
     RECT  13.2 2.137 13.32 2.151 ;
     RECT  18.6 2.137 18.72 2.151 ;
     RECT  24 2.137 24.12 2.151 ;
     RECT  29.4 2.137 29.52 2.151 ;
     RECT  80.4 2.137 83.52 2.151 ;
     RECT  88.8 2.137 88.92 2.151 ;
     RECT  94.2 2.137 94.32 2.151 ;
     RECT  99.6 2.137 99.72 2.151 ;
     RECT  105 2.137 105.12 2.151 ;
     RECT  110.4 2.137 110.52 2.151 ;
     RECT  36.72 1.667 37.992 2.195 ;
     RECT  68.688 2.147 76.2 2.243 ;
     RECT  77.568 2.147 79.176 2.243 ;
     RECT  88.8 2.151 89.112 2.245 ;
     RECT  36.72 2.195 36.936 2.291 ;
     RECT  37.968 2.195 37.992 2.291 ;
     RECT  40.2 1.763 41.448 2.291 ;
     RECT  43.152 1.955 48.456 2.291 ;
     RECT  49.488 1.955 52.008 2.291 ;
     RECT  53.136 1.907 54.024 2.291 ;
     RECT  55.248 1.955 57.48 2.291 ;
     RECT  58.608 2.099 67.512 2.291 ;
     RECT  68.688 2.243 70.632 2.291 ;
     RECT  71.664 2.243 73.32 2.291 ;
     RECT  77.568 2.243 78.888 2.291 ;
     RECT  80.4 2.151 83.712 2.291 ;
     RECT  36.72 2.291 36.744 2.339 ;
     RECT  44.784 2.291 45.912 2.339 ;
     RECT  46.992 2.291 47.88 2.339 ;
     RECT  72.144 2.291 72.912 2.339 ;
     RECT  80.88 2.291 83.712 2.339 ;
     RECT  32.208 1.811 33 2.387 ;
     RECT  34.032 2.099 35.112 2.435 ;
     RECT  32.208 2.387 32.232 2.485 ;
     RECT  74.64 2.243 76.2 2.579 ;
     RECT  80.976 2.339 83.712 2.579 ;
     RECT  80.976 2.579 81.096 2.627 ;
     RECT  43.536 2.291 43.56 2.771 ;
     RECT  66.672 2.291 67.512 2.771 ;
     RECT  69.936 2.291 70.632 2.771 ;
     RECT  75.12 2.579 76.2 2.771 ;
     RECT  75.12 2.771 76.008 2.819 ;
     RECT  75.216 2.819 76.008 2.867 ;
     RECT  82.32 2.579 83.712 2.867 ;
     RECT  27.888 2.053 27.912 2.915 ;
     RECT  49.488 2.291 51.312 2.915 ;
     RECT  61.392 2.291 64.104 2.915 ;
     RECT  72.24 2.339 72.912 2.915 ;
     RECT  82.32 2.867 82.344 2.915 ;
     RECT  39.12 1.331 39.144 2.963 ;
     RECT  63.6 2.915 64.104 2.963 ;
     RECT  63.6 2.963 63.624 3.011 ;
     RECT  70.128 2.771 70.632 3.107 ;
     RECT  75.984 2.867 76.008 3.107 ;
     RECT  70.128 3.107 70.152 3.155 ;
     RECT  61.392 2.915 62.112 3.299 ;
     RECT  77.568 2.291 78.456 3.397 ;
     RECT  49.728 2.915 51.312 3.925 ;
     RECT  77.568 3.397 78.744 3.925 ;
     RECT  45.6 2.339 45.912 4.357 ;
     RECT  46.992 2.339 47.016 4.357 ;
     RECT  68.688 2.291 68.712 4.595 ;
     RECT  67.2 2.771 67.512 5.077 ;
     RECT  56.4 2.291 57.48 5.219 ;
     RECT  32.016 2.485 32.232 5.267 ;
     RECT  66.624 5.077 67.512 6.757 ;
     RECT  48.624 6.613 48.648 6.851 ;
     RECT  49.728 3.925 51.48 7.045 ;
     RECT  71.28 3.973 71.304 7.189 ;
     RECT  68.976 6.805 69 7.379 ;
     RECT  65.376 3.301 65.4 7.525 ;
     RECT  66.624 6.757 67.848 7.525 ;
     RECT  65.376 7.525 67.848 7.715 ;
     RECT  48.432 7.957 48.456 8.149 ;
     RECT  53.424 7.381 53.448 8.579 ;
     RECT  69.648 8.533 69.672 8.629 ;
     RECT  70.656 7.189 71.304 8.675 ;
     RECT  95.952 7.141 95.976 8.725 ;
     RECT  55.248 7.765 55.272 8.819 ;
     RECT  59.664 8.437 59.688 9.011 ;
     RECT  45.6 4.357 47.016 9.013 ;
     RECT  48.24 8.149 48.456 9.013 ;
     RECT  69.552 8.629 69.672 9.013 ;
     RECT  49.536 7.045 51.48 9.061 ;
     RECT  61.8 3.299 62.112 9.061 ;
     RECT  77.568 3.925 79.128 9.061 ;
     RECT  80.496 3.301 80.52 9.061 ;
     RECT  61.8 9.061 63.096 9.109 ;
     RECT  65.376 7.715 67.512 9.109 ;
     RECT  77.568 9.061 80.52 9.109 ;
     RECT  76.944 9.109 80.52 9.205 ;
     RECT  57.792 7.957 57.816 9.251 ;
     RECT  61.008 9.109 63.096 9.251 ;
     RECT  65.376 9.109 67.704 9.251 ;
     RECT  45.6 9.013 48.456 9.445 ;
     RECT  49.536 9.061 51.672 9.445 ;
     RECT  76.896 9.205 80.52 9.589 ;
     RECT  45.6 9.445 52.392 9.635 ;
     RECT  64.128 7.381 64.152 9.637 ;
     RECT  44.448 6.805 44.472 9.685 ;
     RECT  74.784 5.077 74.808 9.685 ;
     RECT  54.144 8.773 54.168 9.731 ;
     RECT  61.344 9.251 63.096 9.731 ;
     RECT  61.8 9.731 63.096 9.827 ;
     RECT  95.952 8.725 96.36 9.829 ;
     RECT  45.6 9.635 51.528 10.019 ;
     RECT  43.776 9.685 44.472 10.067 ;
     RECT  69.552 9.013 70.008 10.067 ;
     RECT  45.6 10.019 51.48 10.165 ;
     RECT  43.776 10.067 43.896 10.211 ;
     RECT  42.336 9.061 42.36 10.355 ;
     RECT  64.128 9.637 64.296 10.355 ;
     RECT  45.024 10.165 51.48 10.403 ;
     RECT  58.368 9.637 58.392 10.405 ;
     RECT  43.776 10.211 43.8 10.595 ;
     RECT  22.992 9.349 23.016 10.693 ;
     RECT  24 2.151 24.312 10.693 ;
     RECT  64.128 10.355 64.152 10.741 ;
     RECT  76.224 9.589 80.52 10.789 ;
     RECT  56.4 5.219 56.712 11.077 ;
     RECT  65.376 9.251 67.512 11.077 ;
     RECT  22.992 10.693 24.312 11.173 ;
     RECT  61.8 9.827 62.112 11.173 ;
     RECT  65.376 11.077 67.608 11.219 ;
     RECT  38.16 10.645 38.184 11.269 ;
     RECT  56.4 11.077 56.808 11.269 ;
     RECT  58.368 10.405 58.632 11.269 ;
     RECT  22.848 11.173 24.312 11.317 ;
     RECT  37.872 11.269 38.184 11.365 ;
     RECT  74.544 9.685 74.808 11.365 ;
     RECT  22.608 11.317 24.312 11.413 ;
     RECT  69.648 10.067 70.008 11.413 ;
     RECT  71.28 8.675 71.304 11.413 ;
     RECT  83.4 2.867 83.712 11.749 ;
     RECT  42.432 10.981 42.456 11.939 ;
     RECT  22.416 11.413 24.312 11.941 ;
     RECT  108.528 11.413 108.552 11.941 ;
     RECT  32.016 5.267 32.04 12.085 ;
     RECT  69.648 11.413 71.304 12.227 ;
     RECT  5.088 11.221 5.112 12.275 ;
     RECT  74.064 11.365 74.808 12.275 ;
     RECT  74.784 12.275 74.808 12.325 ;
     RECT  76.224 10.789 81.096 12.325 ;
     RECT  94.2 2.151 94.512 12.325 ;
     RECT  95.76 9.829 96.36 12.325 ;
     RECT  54.624 11.941 54.648 12.467 ;
     RECT  74.784 12.325 81.096 12.467 ;
     RECT  64.08 10.741 64.152 12.469 ;
     RECT  56.4 11.269 58.632 12.563 ;
     RECT  63.552 12.469 64.152 12.755 ;
     RECT  37.872 11.365 38.616 12.901 ;
     RECT  65.376 11.219 67.512 12.901 ;
     RECT  69.648 12.227 70.008 12.997 ;
     RECT  37.872 12.901 39.192 13.043 ;
     RECT  18.6 2.151 18.912 13.045 ;
     RECT  22.416 11.941 24.408 13.045 ;
     RECT  83.28 11.749 83.712 13.045 ;
     RECT  22.416 13.045 24.792 13.093 ;
     RECT  45.6 10.403 51.48 13.093 ;
     RECT  69.216 12.997 70.008 13.093 ;
     RECT  71.28 12.227 71.304 13.093 ;
     RECT  94.2 12.325 96.36 13.333 ;
     RECT  45.6 13.093 52.104 13.475 ;
     RECT  61.536 11.173 62.112 13.621 ;
     RECT  72.6 2.915 72.912 13.621 ;
     RECT  18.6 13.045 19.032 13.669 ;
     RECT  22.224 13.093 24.792 13.669 ;
     RECT  31.44 12.085 32.04 13.715 ;
     RECT  83.232 13.045 83.712 13.763 ;
     RECT  76.224 12.467 81.096 13.861 ;
     RECT  68.832 13.093 70.008 13.907 ;
     RECT  29.4 2.151 29.712 14.101 ;
     RECT  37.872 13.043 38.616 14.101 ;
     RECT  49.536 13.475 52.104 14.101 ;
     RECT  65.376 12.901 67.608 14.245 ;
     RECT  26.784 11.845 26.808 14.339 ;
     RECT  71.28 13.093 71.352 14.387 ;
     RECT  0.144 12.229 0.168 14.435 ;
     RECT  83.28 13.763 83.712 14.435 ;
     RECT  34.8 2.435 35.112 14.485 ;
     RECT  49.536 14.101 52.152 14.533 ;
     RECT  41.616 13.669 41.64 14.675 ;
     RECT  37.872 14.101 38.664 14.773 ;
     RECT  63.552 12.755 63.576 14.773 ;
     RECT  86.592 14.389 86.616 14.819 ;
     RECT  74.784 12.467 74.808 14.821 ;
     RECT  18.384 13.669 19.032 14.867 ;
     RECT  28.464 14.101 29.712 14.867 ;
     RECT  29.4 14.867 29.712 14.869 ;
     RECT  76.224 13.861 81.288 14.917 ;
     RECT  45.6 13.475 48.264 14.965 ;
     RECT  60.816 13.621 62.112 15.061 ;
     RECT  63.552 14.773 63.768 15.061 ;
     RECT  64.752 14.245 67.608 15.109 ;
     RECT  69.216 13.907 70.008 15.109 ;
     RECT  17.04 12.997 17.064 15.157 ;
     RECT  57.984 12.563 58.632 15.205 ;
     RECT  59.616 11.221 59.64 15.205 ;
     RECT  45.024 14.965 48.264 15.299 ;
     RECT  40.2 2.291 40.512 15.301 ;
     RECT  29.4 14.869 30.408 15.349 ;
     RECT  45.6 15.299 48.264 15.397 ;
     RECT  49.536 14.533 52.248 15.397 ;
     RECT  60.816 15.061 63.768 15.397 ;
     RECT  91.392 2.053 91.416 15.397 ;
     RECT  34.8 14.485 35.304 15.685 ;
     RECT  40.08 15.301 40.512 15.829 ;
     RECT  56.4 12.563 56.712 15.829 ;
     RECT  83.4 14.435 83.712 15.877 ;
     RECT  17.04 15.157 17.352 15.925 ;
     RECT  18.384 14.867 18.912 15.925 ;
     RECT  29.4 15.349 30.744 15.925 ;
     RECT  32.016 13.715 32.04 15.925 ;
     RECT  87.888 2.245 89.112 15.925 ;
     RECT  17.04 15.925 18.912 15.973 ;
     RECT  33.648 15.349 33.672 15.973 ;
     RECT  37.776 14.773 38.76 15.973 ;
     RECT  55.536 15.829 56.712 15.973 ;
     RECT  83.4 15.877 84.072 15.973 ;
     RECT  29.4 15.925 32.04 16.019 ;
     RECT  45.6 15.397 52.248 16.019 ;
     RECT  86.064 15.349 86.088 16.019 ;
     RECT  55.536 15.973 56.808 16.115 ;
     RECT  87.888 15.925 89.208 16.163 ;
     RECT  42.24 15.157 42.264 16.259 ;
     RECT  86.64 16.021 86.664 16.261 ;
     RECT  40.08 15.829 41.064 16.309 ;
     RECT  60.672 15.397 63.768 16.357 ;
     RECT  64.752 15.109 70.008 16.357 ;
     RECT  86.64 16.261 86.76 16.403 ;
     RECT  54.528 15.877 54.552 16.405 ;
     RECT  17.04 15.973 19.08 16.501 ;
     RECT  87.888 16.163 89.112 16.501 ;
     RECT  60.672 16.357 70.008 16.547 ;
     RECT  76.224 14.917 82.248 16.547 ;
     RECT  83.4 15.973 84.792 16.547 ;
     RECT  33.648 15.973 33.768 16.549 ;
     RECT  34.8 15.685 35.736 16.549 ;
     RECT  53.856 16.405 54.552 16.549 ;
     RECT  40.08 16.309 41.88 16.643 ;
     RECT  84.768 16.547 84.792 16.693 ;
     RECT  37.776 15.973 39.048 16.789 ;
     RECT  71.28 14.387 71.304 16.789 ;
     RECT  72.6 13.621 73.8 16.789 ;
     RECT  37.536 16.789 39.048 16.931 ;
     RECT  74.784 14.821 75 16.933 ;
     RECT  76.224 16.547 81.288 16.933 ;
     RECT  40.2 16.643 41.88 16.979 ;
     RECT  45.6 16.019 51.96 17.077 ;
     RECT  91.056 15.397 91.416 17.269 ;
     RECT  43.488 17.077 43.512 17.413 ;
     RECT  71.28 16.789 73.8 17.461 ;
     RECT  74.784 16.933 81.288 17.461 ;
     RECT  71.28 17.461 81.288 17.507 ;
     RECT  91.056 17.269 92.376 17.507 ;
     RECT  71.28 17.507 76.632 17.555 ;
     RECT  60.672 16.547 63.672 17.557 ;
     RECT  64.656 16.547 70.008 17.557 ;
     RECT  15.936 15.925 15.96 17.605 ;
     RECT  16.944 16.501 19.08 17.605 ;
     RECT  21.936 13.669 24.792 17.605 ;
     RECT  37.776 16.931 39.048 17.605 ;
     RECT  40.2 16.979 40.512 17.605 ;
     RECT  87.792 16.501 89.112 17.651 ;
     RECT  29.4 16.019 29.88 17.653 ;
     RECT  30.864 16.019 32.04 17.653 ;
     RECT  33.072 16.549 35.736 17.653 ;
     RECT  84.768 16.693 84.936 17.701 ;
     RECT  86.208 17.077 86.232 17.701 ;
     RECT  29.4 17.653 36.696 17.989 ;
     RECT  41.568 16.979 41.88 18.037 ;
     RECT  43.488 17.413 43.704 18.037 ;
     RECT  44.976 17.077 51.96 18.037 ;
     RECT  15.936 17.605 19.08 18.085 ;
     RECT  21.84 17.605 24.792 18.085 ;
     RECT  14.736 16.405 14.76 18.133 ;
     RECT  15.888 18.085 19.08 18.133 ;
     RECT  60.672 17.557 70.008 18.181 ;
     RECT  71.28 17.555 75.24 18.181 ;
     RECT  84.768 17.701 86.232 18.181 ;
     RECT  91.056 17.507 91.416 18.181 ;
     RECT  27.312 16.261 27.336 18.229 ;
     RECT  41.568 18.037 51.96 18.229 ;
     RECT  53.28 16.549 54.552 18.229 ;
     RECT  21.84 18.085 24.84 18.277 ;
     RECT  41.568 18.229 54.552 18.371 ;
     RECT  26.784 18.229 27.336 18.373 ;
     RECT  21.84 18.277 25.08 18.421 ;
     RECT  26.784 18.373 27.624 18.421 ;
     RECT  83.4 16.547 83.712 18.469 ;
     RECT  84.72 18.181 86.232 18.469 ;
     RECT  21.84 18.421 27.624 18.517 ;
     RECT  78 17.507 81.288 18.565 ;
     RECT  21.84 18.517 27.816 18.613 ;
     RECT  29.04 17.989 36.696 18.707 ;
     RECT  41.568 18.371 42.744 18.709 ;
     RECT  60.672 18.181 75.24 18.709 ;
     RECT  83.4 18.469 86.232 18.709 ;
     RECT  90.576 18.181 91.416 18.709 ;
     RECT  21.84 18.613 27.864 18.755 ;
     RECT  44.496 18.371 54.552 18.757 ;
     RECT  55.536 16.115 56.712 18.757 ;
     RECT  57.984 15.205 59.64 18.757 ;
     RECT  60.624 18.709 75.24 18.757 ;
     RECT  98.112 16.405 98.136 18.757 ;
     RECT  13.2 2.151 13.512 18.805 ;
     RECT  14.736 18.133 19.08 18.805 ;
     RECT  105 2.151 105.312 18.805 ;
     RECT  29.04 18.707 35.736 18.851 ;
     RECT  13.2 18.805 19.08 18.853 ;
     RECT  83.4 18.709 86.376 18.853 ;
     RECT  27.6 18.755 27.864 18.899 ;
     RECT  41.52 18.709 42.744 18.899 ;
     RECT  87.888 17.651 89.112 18.901 ;
     RECT  90.096 18.709 91.416 18.901 ;
     RECT  76.224 17.555 76.632 18.949 ;
     RECT  27.6 18.899 27.816 19.043 ;
     RECT  37.776 17.605 40.512 19.189 ;
     RECT  41.52 18.899 41.88 19.189 ;
     RECT  44.496 18.757 56.712 19.381 ;
     RECT  104.496 18.805 105.312 19.381 ;
     RECT  78 18.565 82.056 19.475 ;
     RECT  87.888 18.901 91.416 19.523 ;
     RECT  83.184 18.853 86.376 19.621 ;
     RECT  21.84 18.755 26.52 19.765 ;
     RECT  98.112 18.757 98.232 19.861 ;
     RECT  99.6 2.151 99.912 19.861 ;
     RECT  82.8 19.621 86.376 19.909 ;
     RECT  87.888 19.523 89.112 19.909 ;
     RECT  44.4 19.381 57 19.957 ;
     RECT  92.976 18.997 93 19.957 ;
     RECT  94.2 13.333 96.456 19.957 ;
     RECT  78 19.475 81.48 20.003 ;
     RECT  92.976 19.957 96.456 20.003 ;
     RECT  37.776 19.189 41.88 20.051 ;
     RECT  90.096 19.523 91.416 20.053 ;
     RECT  29.4 18.851 35.736 20.101 ;
     RECT  13.2 18.853 19.272 20.293 ;
     RECT  13.2 20.293 19.416 20.435 ;
     RECT  43.92 19.957 57 20.437 ;
     RECT  41.856 20.051 41.88 20.485 ;
     RECT  103.2 19.909 103.224 20.485 ;
     RECT  104.496 19.381 106.152 20.485 ;
     RECT  101.52 18.997 101.544 20.533 ;
     RECT  37.776 20.051 40.68 20.579 ;
     RECT  82.8 19.909 89.112 20.581 ;
     RECT  98.112 19.861 99.912 20.581 ;
     RECT  29.4 20.101 35.784 20.677 ;
     RECT  93.072 20.003 96.456 20.723 ;
     RECT  13.2 20.435 19.272 20.725 ;
     RECT  76.224 18.949 76.824 20.771 ;
     RECT  29.4 20.677 36.696 20.963 ;
     RECT  13.056 20.725 19.272 20.965 ;
     RECT  21.84 19.765 27.096 21.011 ;
     RECT  93.36 20.723 96.456 21.059 ;
     RECT  103.2 20.485 106.152 21.061 ;
     RECT  98.112 20.581 100.056 21.109 ;
     RECT  57.984 18.757 75.24 21.155 ;
     RECT  82.656 20.581 89.112 21.155 ;
     RECT  57.984 21.155 75.048 21.203 ;
     RECT  82.8 21.155 89.112 21.445 ;
     RECT  90.096 20.053 91.704 21.445 ;
     RECT  43.296 20.437 57 21.539 ;
     RECT  76.224 20.771 76.632 21.589 ;
     RECT  101.52 20.533 101.736 21.589 ;
     RECT  43.296 21.539 54.552 21.635 ;
     RECT  82.8 21.445 91.704 21.683 ;
     RECT  43.296 21.635 54.12 21.827 ;
     RECT  88.8 21.683 91.704 21.877 ;
     RECT  92.688 21.781 92.712 21.877 ;
     RECT  88.8 21.877 92.712 22.067 ;
     RECT  43.92 21.827 54.12 22.163 ;
     RECT  90.096 22.067 92.712 22.211 ;
     RECT  103.2 21.061 106.44 22.213 ;
     RECT  110.4 2.151 110.712 22.213 ;
     RECT  82.8 21.683 87.336 22.261 ;
     RECT  98.064 21.109 100.056 22.261 ;
     RECT  101.04 21.589 101.736 22.261 ;
     RECT  76.08 21.589 76.632 22.307 ;
     RECT  27.312 21.637 27.336 22.597 ;
     RECT  21.84 21.011 26.184 22.693 ;
     RECT  27.312 22.597 27.624 22.693 ;
     RECT  11.664 20.437 11.688 22.741 ;
     RECT  29.4 20.963 36.024 22.741 ;
     RECT  37.776 20.579 40.512 22.741 ;
     RECT  57.984 21.203 70.68 22.741 ;
     RECT  71.76 21.203 75.048 22.741 ;
     RECT  78 20.003 81.288 22.741 ;
     RECT  82.32 22.261 87.336 22.741 ;
     RECT  29.4 22.741 40.512 22.789 ;
     RECT  41.856 20.485 42.024 22.789 ;
     RECT  57.984 22.741 75.048 22.789 ;
     RECT  76.08 22.307 76.392 22.789 ;
     RECT  98.064 22.261 101.736 22.789 ;
     RECT  110.4 22.213 110.856 22.789 ;
     RECT  111.984 20.677 112.008 22.789 ;
     RECT  21.84 22.693 27.624 23.173 ;
     RECT  78 22.741 87.336 23.317 ;
     RECT  88.8 22.067 89.112 23.317 ;
     RECT  90.576 22.211 92.712 23.317 ;
     RECT  11.376 22.741 11.688 23.365 ;
     RECT  12.96 20.965 19.272 23.365 ;
     RECT  29.4 22.789 42.024 23.365 ;
     RECT  43.92 22.163 47.496 23.365 ;
     RECT  48.816 22.163 54.12 23.365 ;
     RECT  55.536 21.539 57 23.365 ;
     RECT  57.984 22.789 76.392 23.365 ;
     RECT  78 23.317 92.712 23.365 ;
     RECT  94.2 21.059 96.456 23.365 ;
     RECT  98.064 22.789 102.024 23.365 ;
     RECT  103.2 22.213 106.632 23.365 ;
     RECT  10.8 23.365 19.272 23.413 ;
     RECT  21.072 23.173 27.624 23.413 ;
     RECT  10.8 23.413 19.368 23.461 ;
     RECT  20.784 23.413 27.624 23.461 ;
     RECT  29.4 23.365 42.696 23.461 ;
     RECT  10.8 23.461 19.56 23.557 ;
     RECT  29.04 23.461 42.696 23.557 ;
     RECT  110.4 22.789 112.008 23.605 ;
     RECT  10.8 23.557 19.656 23.653 ;
     RECT  10.704 23.653 19.656 23.749 ;
     RECT  20.688 23.461 27.624 23.749 ;
     RECT  28.944 23.557 42.696 23.749 ;
     RECT  2.4 2.151 2.712 23.769 ;
     RECT  7.8 2.151 8.112 23.769 ;
     RECT  2.4 23.769 2.52 23.783 ;
     RECT  7.8 23.769 7.92 23.783 ;
     RECT  43.824 23.365 96.456 23.783 ;
     RECT  10.704 23.749 42.696 23.797 ;
     RECT  43.824 23.783 77.448 23.797 ;
     RECT  97.68 23.365 106.632 24.517 ;
     RECT  97.488 24.517 106.632 25.093 ;
     RECT  107.76 11.941 108.552 25.093 ;
     RECT  109.872 23.605 112.008 25.093 ;
     RECT  97.488 25.093 112.104 25.141 ;
     RECT  97.488 25.141 112.296 25.189 ;
     RECT  97.488 25.189 112.68 25.237 ;
     RECT  10.704 23.797 77.448 25.621 ;
     RECT  78.432 23.783 96.456 25.621 ;
     RECT  10.704 25.621 96.456 25.717 ;
     RECT  97.488 25.237 112.776 25.717 ;
     RECT  10.704 25.717 112.776 25.872 ;
     RECT  58.992 25.872 59.016 25.907 ;
     RECT  38.088 0.659 39.12 1.187 ;
     RECT  37.992 1.187 39.12 2.291 ;
     RECT  39.144 1.331 40.2 2.963 ;
     RECT  35.208 1.619 36.336 1.667 ;
     RECT  35.208 1.667 36.72 2.099 ;
     RECT  41.448 1.763 42.48 1.811 ;
     RECT  33 1.811 34.032 2.387 ;
     RECT  41.448 1.811 42.576 1.907 ;
     RECT  57.48 1.811 58.512 1.907 ;
     RECT  54.024 1.859 55.056 1.907 ;
     RECT  52.008 1.907 53.136 2.291 ;
     RECT  54.024 1.907 55.152 1.955 ;
     RECT  57.48 1.907 58.608 2.291 ;
     RECT  48.456 1.955 49.488 2.291 ;
     RECT  54.024 1.955 55.248 2.291 ;
     RECT  79.176 1.955 80.4 2.243 ;
     RECT  67.512 2.099 68.688 4.595 ;
     RECT  27.912 2.137 29.4 2.915 ;
     RECT  76.2 2.147 77.568 2.771 ;
     RECT  36.936 2.195 37.968 2.291 ;
     RECT  70.632 2.243 71.664 2.291 ;
     RECT  73.32 2.243 74.64 2.291 ;
     RECT  78.888 2.243 80.4 2.291 ;
     RECT  43.56 2.291 44.784 2.339 ;
     RECT  45.912 2.291 46.992 4.357 ;
     RECT  64.104 2.291 66.672 2.771 ;
     RECT  68.712 2.291 69.936 2.771 ;
     RECT  70.632 2.291 72.144 2.339 ;
     RECT  78.456 2.291 78.744 3.397 ;
     RECT  80.496 2.291 80.88 2.339 ;
     RECT  80.496 2.339 80.976 2.627 ;
     RECT  81.096 2.579 82.32 2.627 ;
     RECT  80.496 2.627 80.52 3.301 ;
     RECT  64.104 2.771 65.4 2.963 ;
     RECT  68.712 2.771 70.128 3.155 ;
     RECT  82.344 2.867 83.4 2.915 ;
     RECT  62.112 2.915 63.6 3.011 ;
     RECT  72.24 2.915 72.6 3.973 ;
     RECT  65.376 2.963 65.4 3.301 ;
     RECT  79.128 3.925 80.496 9.061 ;
     RECT  71.304 3.973 72.6 13.093 ;
     RECT  65.4 5.077 66.624 7.525 ;
     RECT  48.648 6.613 49.728 6.851 ;
     RECT  44.472 6.805 45.6 10.067 ;
     RECT  67.848 6.805 68.976 7.379 ;
     RECT  48.624 6.851 49.728 7.045 ;
     RECT  48.624 7.045 49.536 7.957 ;
     RECT  94.512 7.141 95.952 9.829 ;
     RECT  64.152 7.381 65.376 9.637 ;
     RECT  67.512 7.715 67.704 9.109 ;
     RECT  55.272 7.765 56.4 8.819 ;
     RECT  47.016 7.957 48.432 8.149 ;
     RECT  48.456 7.957 49.536 9.445 ;
     RECT  56.712 7.957 57.792 9.251 ;
     RECT  47.016 8.149 48.24 9.013 ;
     RECT  69.672 8.533 70.656 8.675 ;
     RECT  69.672 8.675 71.28 9.013 ;
     RECT  54.168 8.773 55.248 8.819 ;
     RECT  70.008 9.013 71.28 11.413 ;
     RECT  63.096 9.061 64.128 9.827 ;
     RECT  23.016 9.349 24 10.693 ;
     RECT  74.808 9.589 76.224 12.325 ;
     RECT  64.296 9.637 65.376 10.355 ;
     RECT  42.36 9.685 43.776 10.355 ;
     RECT  61.536 9.731 61.8 11.173 ;
     RECT  64.08 9.827 64.128 10.741 ;
     RECT  94.512 9.829 95.76 12.325 ;
     RECT  43.896 10.067 45.6 10.165 ;
     RECT  43.896 10.165 45.024 10.211 ;
     RECT  43.8 10.211 45.024 10.403 ;
     RECT  42.432 10.355 43.776 10.595 ;
     RECT  64.152 10.355 65.376 12.755 ;
     RECT  42.432 10.595 42.456 10.981 ;
     RECT  58.632 11.221 59.616 15.205 ;
     RECT  72.912 11.365 74.064 12.275 ;
     RECT  70.008 12.227 71.28 18.181 ;
     RECT  72.912 12.275 74.784 13.621 ;
     RECT  74.808 12.467 76.224 14.821 ;
     RECT  62.112 12.469 63.552 15.061 ;
     RECT  56.712 12.563 57.984 15.973 ;
     RECT  63.576 12.755 65.376 14.245 ;
     RECT  39.192 12.901 40.2 13.043 ;
     RECT  38.616 13.043 38.664 14.101 ;
     RECT  67.608 13.093 68.832 13.907 ;
     RECT  71.352 13.093 72.6 14.387 ;
     RECT  48.264 13.475 49.536 15.397 ;
     RECT  59.64 13.621 60.816 15.397 ;
     RECT  73.8 13.621 74.784 17.461 ;
     RECT  17.064 13.669 18.384 15.157 ;
     RECT  40.512 13.669 41.616 14.675 ;
     RECT  83.232 13.763 83.28 14.435 ;
     RECT  67.608 13.907 69.216 15.109 ;
     RECT  63.576 14.245 64.752 14.773 ;
     RECT  71.304 14.387 72.6 16.789 ;
     RECT  86.616 14.389 87.888 14.819 ;
     RECT  83.232 14.435 83.4 14.917 ;
     RECT  40.512 14.675 41.64 15.157 ;
     RECT  38.76 14.773 40.2 15.301 ;
     RECT  63.768 14.773 64.752 16.357 ;
     RECT  86.592 14.819 87.888 15.349 ;
     RECT  75 14.821 76.224 16.933 ;
     RECT  18.912 14.867 19.032 15.973 ;
     RECT  82.248 14.917 83.4 16.547 ;
     RECT  17.352 15.157 18.384 15.925 ;
     RECT  40.512 15.157 42.24 15.829 ;
     RECT  38.76 15.301 40.08 15.973 ;
     RECT  30.744 15.349 32.016 15.925 ;
     RECT  33.672 15.349 34.8 15.973 ;
     RECT  86.088 15.349 87.888 16.019 ;
     RECT  59.64 15.397 60.672 18.709 ;
     RECT  41.064 15.829 42.24 16.259 ;
     RECT  54.552 15.877 55.536 18.757 ;
     RECT  15.96 15.925 17.04 16.501 ;
     RECT  33.768 15.973 34.8 16.549 ;
     RECT  39.048 15.973 40.08 16.643 ;
     RECT  56.808 15.973 57.984 16.115 ;
     RECT  84.792 15.973 86.064 16.019 ;
     RECT  29.88 16.019 30.864 17.653 ;
     RECT  51.96 16.019 52.248 16.549 ;
     RECT  84.792 16.019 87.888 16.021 ;
     RECT  84.792 16.021 86.64 16.403 ;
     RECT  86.664 16.021 87.888 16.261 ;
     RECT  56.712 16.115 57.984 19.381 ;
     RECT  41.064 16.259 41.88 16.309 ;
     RECT  86.76 16.261 87.888 16.403 ;
     RECT  84.792 16.403 86.232 16.693 ;
     RECT  87.792 16.403 87.888 16.501 ;
     RECT  13.512 16.405 14.736 18.805 ;
     RECT  14.76 16.405 15.936 18.085 ;
     RECT  98.136 16.405 99.6 18.757 ;
     RECT  15.96 16.501 16.944 17.605 ;
     RECT  63.672 16.547 64.656 17.557 ;
     RECT  83.712 16.547 84.768 18.181 ;
     RECT  32.04 16.549 33.072 17.653 ;
     RECT  51.96 16.549 53.28 18.229 ;
     RECT  39.048 16.643 40.2 17.605 ;
     RECT  84.936 16.693 86.232 17.077 ;
     RECT  37.536 16.931 37.776 17.653 ;
     RECT  40.512 16.979 41.568 18.709 ;
     RECT  43.512 17.077 44.976 17.413 ;
     RECT  84.936 17.077 86.208 17.701 ;
     RECT  43.704 17.413 44.976 18.037 ;
     RECT  76.632 17.507 78 18.949 ;
     RECT  75.24 17.555 76.224 21.155 ;
     RECT  87.792 17.651 87.888 18.709 ;
     RECT  36.696 17.653 37.776 18.707 ;
     RECT  14.76 18.085 15.888 18.133 ;
     RECT  83.712 18.181 84.72 18.469 ;
     RECT  89.112 18.181 90.576 18.709 ;
     RECT  44.4 18.371 44.496 19.381 ;
     RECT  27.624 18.373 29.04 18.517 ;
     RECT  27.816 18.517 29.04 18.613 ;
     RECT  82.056 18.565 83.4 18.853 ;
     RECT  27.864 18.613 29.04 18.851 ;
     RECT  35.736 18.707 35.784 20.101 ;
     RECT  40.512 18.709 41.52 19.189 ;
     RECT  59.64 18.709 60.624 18.757 ;
     RECT  86.376 18.709 87.888 19.909 ;
     RECT  89.112 18.709 90.096 18.901 ;
     RECT  26.52 18.755 27.6 19.043 ;
     RECT  98.232 18.757 99.6 19.861 ;
     RECT  82.056 18.853 83.184 19.475 ;
     RECT  76.824 18.949 78 20.771 ;
     RECT  93 18.997 94.2 19.957 ;
     RECT  26.52 19.043 27.096 19.765 ;
     RECT  57 19.381 57.984 23.365 ;
     RECT  81.48 19.475 83.184 19.621 ;
     RECT  89.112 19.523 90.096 21.445 ;
     RECT  81.48 19.621 82.8 20.003 ;
     RECT  103.224 19.909 104.496 20.485 ;
     RECT  81.288 20.003 82.8 20.581 ;
     RECT  92.976 20.003 93.072 20.053 ;
     RECT  40.68 20.051 41.856 20.579 ;
     RECT  91.704 20.053 93.072 20.723 ;
     RECT  11.688 20.437 13.2 20.725 ;
     RECT  41.88 20.437 43.296 20.485 ;
     RECT  42.024 20.485 43.296 21.827 ;
     RECT  101.736 20.533 103.2 22.789 ;
     RECT  40.512 20.579 41.856 22.789 ;
     RECT  81.288 20.581 82.656 21.155 ;
     RECT  100.056 20.581 101.52 21.589 ;
     RECT  36.696 20.677 37.776 20.963 ;
     RECT  110.712 20.677 111.984 22.213 ;
     RECT  91.704 20.723 93.36 21.059 ;
     RECT  11.688 20.725 13.056 20.965 ;
     RECT  76.632 20.771 78 22.307 ;
     RECT  11.688 20.965 12.96 23.365 ;
     RECT  26.184 21.011 27.096 21.637 ;
     RECT  91.704 21.059 94.2 21.781 ;
     RECT  106.44 21.061 107.76 22.213 ;
     RECT  75.048 21.155 76.224 21.589 ;
     RECT  81.288 21.155 82.8 22.261 ;
     RECT  70.68 21.203 71.76 22.741 ;
     RECT  54.552 21.539 55.536 21.635 ;
     RECT  75.048 21.589 76.08 22.789 ;
     RECT  100.056 21.589 101.04 22.261 ;
     RECT  54.12 21.635 55.536 23.365 ;
     RECT  26.184 21.637 27.312 22.693 ;
     RECT  87.336 21.683 88.8 23.317 ;
     RECT  91.704 21.781 92.688 21.877 ;
     RECT  92.712 21.781 94.2 23.365 ;
     RECT  89.112 22.067 90.096 22.211 ;
     RECT  47.496 22.163 48.816 23.365 ;
     RECT  89.112 22.211 90.576 23.317 ;
     RECT  106.632 22.213 107.76 25.093 ;
     RECT  110.856 22.213 111.984 22.789 ;
     RECT  81.288 22.261 82.32 22.741 ;
     RECT  76.392 22.307 78 23.365 ;
     RECT  102.024 22.789 103.2 23.365 ;
     RECT  42.696 23.365 43.824 23.797 ;
     RECT  96.456 23.365 97.68 24.517 ;
     RECT  19.368 23.413 20.784 23.461 ;
     RECT  19.56 23.461 20.688 23.557 ;
     RECT  27.624 23.461 29.04 23.557 ;
     RECT  19.656 23.557 20.688 23.749 ;
     RECT  27.624 23.557 28.944 23.749 ;
     RECT  108.552 23.605 109.872 25.093 ;
     RECT  77.448 23.783 78.432 25.621 ;
     RECT  96.456 24.517 97.488 25.717 ;
  END
END ot_qfd_vm_rr2_t
END LIBRARY
